VERSION 5.8 ;
BUSBITCHARS "[]" ;
DIVIDERCHAR "/" ;
UNITS
    DATABASE MICRONS 1000 ;
END UNITS

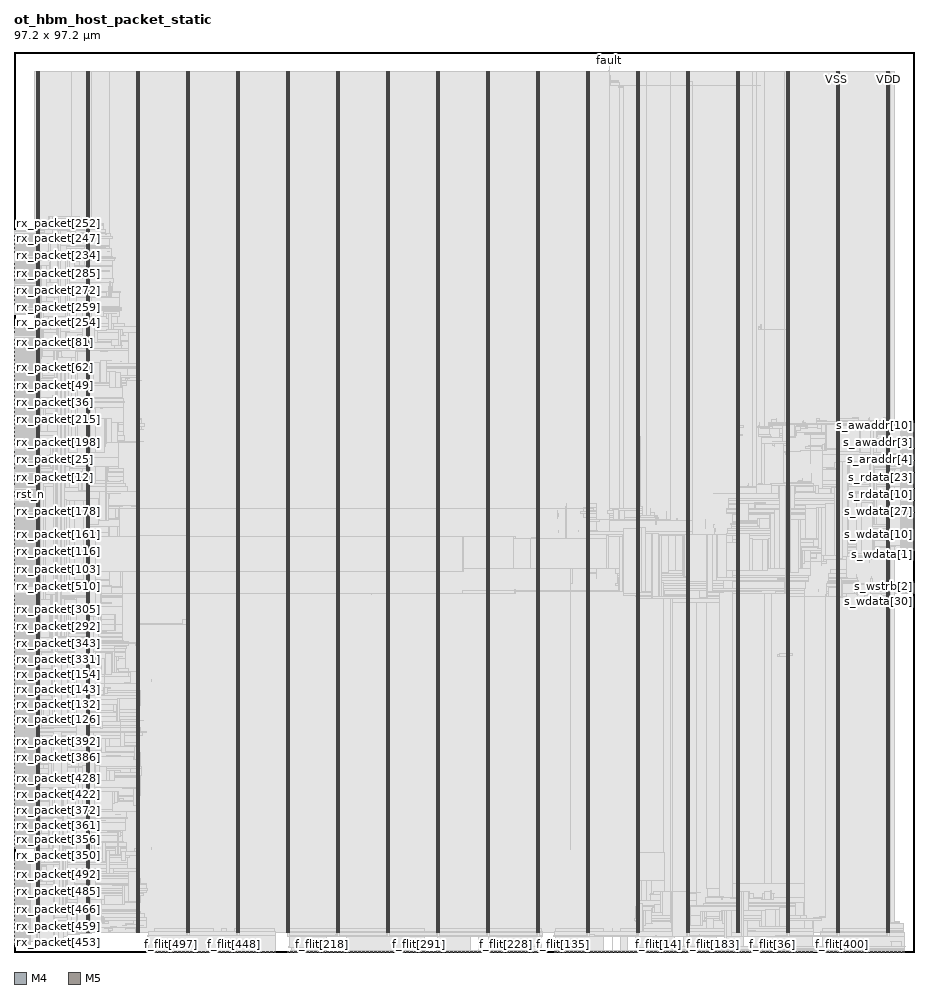
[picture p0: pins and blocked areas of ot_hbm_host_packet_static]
MACRO ot_hbm_host_packet_static
  FOREIGN ot_hbm_host_packet_static 0 0 ;
  CLASS BLOCK ;
  SIZE 97.2 BY 97.2 ;
  PIN clk
    DIRECTION INPUT ;
    USE SIGNAL ;
    PORT
      LAYER M4 ;
        RECT  0 49.248 0.084 49.272 ;
    END
  END clk
  PIN f_flit[0]
    DIRECTION OUTPUT ;
    USE SIGNAL ;
    PORT
      LAYER M5 ;
        RECT  67.536 0 67.56 0.084 ;
    END
  END f_flit[0]
  PIN f_flit[100]
    DIRECTION OUTPUT ;
    USE SIGNAL ;
    PORT
      LAYER M5 ;
        RECT  77.328 0 77.352 0.084 ;
    END
  END f_flit[100]
  PIN f_flit[101]
    DIRECTION OUTPUT ;
    USE SIGNAL ;
    PORT
      LAYER M5 ;
        RECT  77.472 0 77.496 0.084 ;
    END
  END f_flit[101]
  PIN f_flit[102]
    DIRECTION OUTPUT ;
    USE SIGNAL ;
    PORT
      LAYER M5 ;
        RECT  77.616 0 77.64 0.084 ;
    END
  END f_flit[102]
  PIN f_flit[103]
    DIRECTION OUTPUT ;
    USE SIGNAL ;
    PORT
      LAYER M5 ;
        RECT  77.76 0 77.784 0.084 ;
    END
  END f_flit[103]
  PIN f_flit[104]
    DIRECTION OUTPUT ;
    USE SIGNAL ;
    PORT
      LAYER M5 ;
        RECT  77.904 0 77.928 0.084 ;
    END
  END f_flit[104]
  PIN f_flit[105]
    DIRECTION OUTPUT ;
    USE SIGNAL ;
    PORT
      LAYER M5 ;
        RECT  78.048 0 78.072 0.084 ;
    END
  END f_flit[105]
  PIN f_flit[106]
    DIRECTION OUTPUT ;
    USE SIGNAL ;
    PORT
      LAYER M5 ;
        RECT  78.192 0 78.216 0.084 ;
    END
  END f_flit[106]
  PIN f_flit[107]
    DIRECTION OUTPUT ;
    USE SIGNAL ;
    PORT
      LAYER M5 ;
        RECT  78.336 0 78.36 0.084 ;
    END
  END f_flit[107]
  PIN f_flit[108]
    DIRECTION OUTPUT ;
    USE SIGNAL ;
    PORT
      LAYER M5 ;
        RECT  78.48 0 78.504 0.084 ;
    END
  END f_flit[108]
  PIN f_flit[109]
    DIRECTION OUTPUT ;
    USE SIGNAL ;
    PORT
      LAYER M5 ;
        RECT  78.624 0 78.648 0.084 ;
    END
  END f_flit[109]
  PIN f_flit[10]
    DIRECTION OUTPUT ;
    USE SIGNAL ;
    PORT
      LAYER M5 ;
        RECT  68.976 0 69 0.084 ;
    END
  END f_flit[10]
  PIN f_flit[110]
    DIRECTION OUTPUT ;
    USE SIGNAL ;
    PORT
      LAYER M5 ;
        RECT  78.768 0 78.792 0.084 ;
    END
  END f_flit[110]
  PIN f_flit[111]
    DIRECTION OUTPUT ;
    USE SIGNAL ;
    PORT
      LAYER M5 ;
        RECT  78.912 0 78.936 0.084 ;
    END
  END f_flit[111]
  PIN f_flit[112]
    DIRECTION OUTPUT ;
    USE SIGNAL ;
    PORT
      LAYER M5 ;
        RECT  79.056 0 79.08 0.084 ;
    END
  END f_flit[112]
  PIN f_flit[113]
    DIRECTION OUTPUT ;
    USE SIGNAL ;
    PORT
      LAYER M5 ;
        RECT  79.2 0 79.224 0.084 ;
    END
  END f_flit[113]
  PIN f_flit[114]
    DIRECTION OUTPUT ;
    USE SIGNAL ;
    PORT
      LAYER M5 ;
        RECT  79.344 0 79.368 0.084 ;
    END
  END f_flit[114]
  PIN f_flit[115]
    DIRECTION OUTPUT ;
    USE SIGNAL ;
    PORT
      LAYER M5 ;
        RECT  79.488 0 79.512 0.084 ;
    END
  END f_flit[115]
  PIN f_flit[116]
    DIRECTION OUTPUT ;
    USE SIGNAL ;
    PORT
      LAYER M5 ;
        RECT  79.632 0 79.656 0.084 ;
    END
  END f_flit[116]
  PIN f_flit[117]
    DIRECTION OUTPUT ;
    USE SIGNAL ;
    PORT
      LAYER M5 ;
        RECT  79.776 0 79.8 0.084 ;
    END
  END f_flit[117]
  PIN f_flit[118]
    DIRECTION OUTPUT ;
    USE SIGNAL ;
    PORT
      LAYER M5 ;
        RECT  79.92 0 79.944 0.084 ;
    END
  END f_flit[118]
  PIN f_flit[119]
    DIRECTION OUTPUT ;
    USE SIGNAL ;
    PORT
      LAYER M5 ;
        RECT  80.064 0 80.088 0.084 ;
    END
  END f_flit[119]
  PIN f_flit[11]
    DIRECTION OUTPUT ;
    USE SIGNAL ;
    PORT
      LAYER M5 ;
        RECT  69.12 0 69.144 0.084 ;
    END
  END f_flit[11]
  PIN f_flit[120]
    DIRECTION OUTPUT ;
    USE SIGNAL ;
    PORT
      LAYER M5 ;
        RECT  80.208 0 80.232 0.084 ;
    END
  END f_flit[120]
  PIN f_flit[121]
    DIRECTION OUTPUT ;
    USE SIGNAL ;
    PORT
      LAYER M5 ;
        RECT  80.352 0 80.376 0.084 ;
    END
  END f_flit[121]
  PIN f_flit[122]
    DIRECTION OUTPUT ;
    USE SIGNAL ;
    PORT
      LAYER M5 ;
        RECT  80.496 0 80.52 0.084 ;
    END
  END f_flit[122]
  PIN f_flit[123]
    DIRECTION OUTPUT ;
    USE SIGNAL ;
    PORT
      LAYER M5 ;
        RECT  80.64 0 80.664 0.084 ;
    END
  END f_flit[123]
  PIN f_flit[124]
    DIRECTION OUTPUT ;
    USE SIGNAL ;
    PORT
      LAYER M5 ;
        RECT  80.784 0 80.808 0.084 ;
    END
  END f_flit[124]
  PIN f_flit[125]
    DIRECTION OUTPUT ;
    USE SIGNAL ;
    PORT
      LAYER M5 ;
        RECT  80.928 0 80.952 0.084 ;
    END
  END f_flit[125]
  PIN f_flit[126]
    DIRECTION OUTPUT ;
    USE SIGNAL ;
    PORT
      LAYER M5 ;
        RECT  81.072 0 81.096 0.084 ;
    END
  END f_flit[126]
  PIN f_flit[127]
    DIRECTION OUTPUT ;
    USE SIGNAL ;
    PORT
      LAYER M5 ;
        RECT  81.216 0 81.24 0.084 ;
    END
  END f_flit[127]
  PIN f_flit[128]
    DIRECTION OUTPUT ;
    USE SIGNAL ;
    PORT
      LAYER M5 ;
        RECT  58.32 0 58.344 0.084 ;
    END
  END f_flit[128]
  PIN f_flit[129]
    DIRECTION OUTPUT ;
    USE SIGNAL ;
    PORT
      LAYER M5 ;
        RECT  58.464 0 58.488 0.084 ;
    END
  END f_flit[129]
  PIN f_flit[12]
    DIRECTION OUTPUT ;
    USE SIGNAL ;
    PORT
      LAYER M5 ;
        RECT  69.264 0 69.288 0.084 ;
    END
  END f_flit[12]
  PIN f_flit[130]
    DIRECTION OUTPUT ;
    USE SIGNAL ;
    PORT
      LAYER M5 ;
        RECT  58.608 0 58.632 0.084 ;
    END
  END f_flit[130]
  PIN f_flit[131]
    DIRECTION OUTPUT ;
    USE SIGNAL ;
    PORT
      LAYER M5 ;
        RECT  58.752 0 58.776 0.084 ;
    END
  END f_flit[131]
  PIN f_flit[132]
    DIRECTION OUTPUT ;
    USE SIGNAL ;
    PORT
      LAYER M5 ;
        RECT  58.896 0 58.92 0.084 ;
    END
  END f_flit[132]
  PIN f_flit[133]
    DIRECTION OUTPUT ;
    USE SIGNAL ;
    PORT
      LAYER M5 ;
        RECT  59.04 0 59.064 0.084 ;
    END
  END f_flit[133]
  PIN f_flit[134]
    DIRECTION OUTPUT ;
    USE SIGNAL ;
    PORT
      LAYER M5 ;
        RECT  59.184 0 59.208 0.084 ;
    END
  END f_flit[134]
  PIN f_flit[135]
    DIRECTION OUTPUT ;
    USE SIGNAL ;
    PORT
      LAYER M5 ;
        RECT  59.328 0 59.352 0.084 ;
    END
  END f_flit[135]
  PIN f_flit[136]
    DIRECTION OUTPUT ;
    USE SIGNAL ;
    PORT
      LAYER M5 ;
        RECT  59.472 0 59.496 0.084 ;
    END
  END f_flit[136]
  PIN f_flit[137]
    DIRECTION OUTPUT ;
    USE SIGNAL ;
    PORT
      LAYER M5 ;
        RECT  59.616 0 59.64 0.084 ;
    END
  END f_flit[137]
  PIN f_flit[138]
    DIRECTION OUTPUT ;
    USE SIGNAL ;
    PORT
      LAYER M5 ;
        RECT  59.76 0 59.784 0.084 ;
    END
  END f_flit[138]
  PIN f_flit[139]
    DIRECTION OUTPUT ;
    USE SIGNAL ;
    PORT
      LAYER M5 ;
        RECT  59.904 0 59.928 0.084 ;
    END
  END f_flit[139]
  PIN f_flit[13]
    DIRECTION OUTPUT ;
    USE SIGNAL ;
    PORT
      LAYER M5 ;
        RECT  69.408 0 69.432 0.084 ;
    END
  END f_flit[13]
  PIN f_flit[140]
    DIRECTION OUTPUT ;
    USE SIGNAL ;
    PORT
      LAYER M5 ;
        RECT  60.048 0 60.072 0.084 ;
    END
  END f_flit[140]
  PIN f_flit[141]
    DIRECTION OUTPUT ;
    USE SIGNAL ;
    PORT
      LAYER M5 ;
        RECT  60.192 0 60.216 0.084 ;
    END
  END f_flit[141]
  PIN f_flit[142]
    DIRECTION OUTPUT ;
    USE SIGNAL ;
    PORT
      LAYER M5 ;
        RECT  60.336 0 60.36 0.084 ;
    END
  END f_flit[142]
  PIN f_flit[143]
    DIRECTION OUTPUT ;
    USE SIGNAL ;
    PORT
      LAYER M5 ;
        RECT  60.48 0 60.504 0.084 ;
    END
  END f_flit[143]
  PIN f_flit[144]
    DIRECTION OUTPUT ;
    USE SIGNAL ;
    PORT
      LAYER M5 ;
        RECT  60.624 0 60.648 0.084 ;
    END
  END f_flit[144]
  PIN f_flit[145]
    DIRECTION OUTPUT ;
    USE SIGNAL ;
    PORT
      LAYER M5 ;
        RECT  60.768 0 60.792 0.084 ;
    END
  END f_flit[145]
  PIN f_flit[146]
    DIRECTION OUTPUT ;
    USE SIGNAL ;
    PORT
      LAYER M5 ;
        RECT  60.912 0 60.936 0.084 ;
    END
  END f_flit[146]
  PIN f_flit[147]
    DIRECTION OUTPUT ;
    USE SIGNAL ;
    PORT
      LAYER M5 ;
        RECT  61.056 0 61.08 0.084 ;
    END
  END f_flit[147]
  PIN f_flit[148]
    DIRECTION OUTPUT ;
    USE SIGNAL ;
    PORT
      LAYER M5 ;
        RECT  61.2 0 61.224 0.084 ;
    END
  END f_flit[148]
  PIN f_flit[149]
    DIRECTION OUTPUT ;
    USE SIGNAL ;
    PORT
      LAYER M5 ;
        RECT  61.344 0 61.368 0.084 ;
    END
  END f_flit[149]
  PIN f_flit[14]
    DIRECTION OUTPUT ;
    USE SIGNAL ;
    PORT
      LAYER M5 ;
        RECT  69.552 0 69.576 0.084 ;
    END
  END f_flit[14]
  PIN f_flit[150]
    DIRECTION OUTPUT ;
    USE SIGNAL ;
    PORT
      LAYER M5 ;
        RECT  61.488 0 61.512 0.084 ;
    END
  END f_flit[150]
  PIN f_flit[151]
    DIRECTION OUTPUT ;
    USE SIGNAL ;
    PORT
      LAYER M5 ;
        RECT  61.632 0 61.656 0.084 ;
    END
  END f_flit[151]
  PIN f_flit[152]
    DIRECTION OUTPUT ;
    USE SIGNAL ;
    PORT
      LAYER M5 ;
        RECT  61.776 0 61.8 0.084 ;
    END
  END f_flit[152]
  PIN f_flit[153]
    DIRECTION OUTPUT ;
    USE SIGNAL ;
    PORT
      LAYER M5 ;
        RECT  61.92 0 61.944 0.084 ;
    END
  END f_flit[153]
  PIN f_flit[154]
    DIRECTION OUTPUT ;
    USE SIGNAL ;
    PORT
      LAYER M5 ;
        RECT  62.064 0 62.088 0.084 ;
    END
  END f_flit[154]
  PIN f_flit[155]
    DIRECTION OUTPUT ;
    USE SIGNAL ;
    PORT
      LAYER M5 ;
        RECT  62.208 0 62.232 0.084 ;
    END
  END f_flit[155]
  PIN f_flit[156]
    DIRECTION OUTPUT ;
    USE SIGNAL ;
    PORT
      LAYER M5 ;
        RECT  62.352 0 62.376 0.084 ;
    END
  END f_flit[156]
  PIN f_flit[157]
    DIRECTION OUTPUT ;
    USE SIGNAL ;
    PORT
      LAYER M5 ;
        RECT  62.496 0 62.52 0.084 ;
    END
  END f_flit[157]
  PIN f_flit[158]
    DIRECTION OUTPUT ;
    USE SIGNAL ;
    PORT
      LAYER M5 ;
        RECT  62.64 0 62.664 0.084 ;
    END
  END f_flit[158]
  PIN f_flit[159]
    DIRECTION OUTPUT ;
    USE SIGNAL ;
    PORT
      LAYER M5 ;
        RECT  62.784 0 62.808 0.084 ;
    END
  END f_flit[159]
  PIN f_flit[15]
    DIRECTION OUTPUT ;
    USE SIGNAL ;
    PORT
      LAYER M5 ;
        RECT  69.696 0 69.72 0.084 ;
    END
  END f_flit[15]
  PIN f_flit[160]
    DIRECTION OUTPUT ;
    USE SIGNAL ;
    PORT
      LAYER M5 ;
        RECT  72.144 0 72.168 0.084 ;
    END
  END f_flit[160]
  PIN f_flit[161]
    DIRECTION OUTPUT ;
    USE SIGNAL ;
    PORT
      LAYER M5 ;
        RECT  72.288 0 72.312 0.084 ;
    END
  END f_flit[161]
  PIN f_flit[162]
    DIRECTION OUTPUT ;
    USE SIGNAL ;
    PORT
      LAYER M5 ;
        RECT  72.432 0 72.456 0.084 ;
    END
  END f_flit[162]
  PIN f_flit[163]
    DIRECTION OUTPUT ;
    USE SIGNAL ;
    PORT
      LAYER M5 ;
        RECT  72.576 0 72.6 0.084 ;
    END
  END f_flit[163]
  PIN f_flit[164]
    DIRECTION OUTPUT ;
    USE SIGNAL ;
    PORT
      LAYER M5 ;
        RECT  72.72 0 72.744 0.084 ;
    END
  END f_flit[164]
  PIN f_flit[165]
    DIRECTION OUTPUT ;
    USE SIGNAL ;
    PORT
      LAYER M5 ;
        RECT  72.864 0 72.888 0.084 ;
    END
  END f_flit[165]
  PIN f_flit[166]
    DIRECTION OUTPUT ;
    USE SIGNAL ;
    PORT
      LAYER M5 ;
        RECT  73.008 0 73.032 0.084 ;
    END
  END f_flit[166]
  PIN f_flit[167]
    DIRECTION OUTPUT ;
    USE SIGNAL ;
    PORT
      LAYER M5 ;
        RECT  73.152 0 73.176 0.084 ;
    END
  END f_flit[167]
  PIN f_flit[168]
    DIRECTION OUTPUT ;
    USE SIGNAL ;
    PORT
      LAYER M5 ;
        RECT  73.296 0 73.32 0.084 ;
    END
  END f_flit[168]
  PIN f_flit[169]
    DIRECTION OUTPUT ;
    USE SIGNAL ;
    PORT
      LAYER M5 ;
        RECT  73.44 0 73.464 0.084 ;
    END
  END f_flit[169]
  PIN f_flit[16]
    DIRECTION OUTPUT ;
    USE SIGNAL ;
    PORT
      LAYER M5 ;
        RECT  69.84 0 69.864 0.084 ;
    END
  END f_flit[16]
  PIN f_flit[170]
    DIRECTION OUTPUT ;
    USE SIGNAL ;
    PORT
      LAYER M5 ;
        RECT  73.584 0 73.608 0.084 ;
    END
  END f_flit[170]
  PIN f_flit[171]
    DIRECTION OUTPUT ;
    USE SIGNAL ;
    PORT
      LAYER M5 ;
        RECT  73.728 0 73.752 0.084 ;
    END
  END f_flit[171]
  PIN f_flit[172]
    DIRECTION OUTPUT ;
    USE SIGNAL ;
    PORT
      LAYER M5 ;
        RECT  73.872 0 73.896 0.084 ;
    END
  END f_flit[172]
  PIN f_flit[173]
    DIRECTION OUTPUT ;
    USE SIGNAL ;
    PORT
      LAYER M5 ;
        RECT  74.016 0 74.04 0.084 ;
    END
  END f_flit[173]
  PIN f_flit[174]
    DIRECTION OUTPUT ;
    USE SIGNAL ;
    PORT
      LAYER M5 ;
        RECT  74.16 0 74.184 0.084 ;
    END
  END f_flit[174]
  PIN f_flit[175]
    DIRECTION OUTPUT ;
    USE SIGNAL ;
    PORT
      LAYER M5 ;
        RECT  74.304 0 74.328 0.084 ;
    END
  END f_flit[175]
  PIN f_flit[176]
    DIRECTION OUTPUT ;
    USE SIGNAL ;
    PORT
      LAYER M5 ;
        RECT  74.448 0 74.472 0.084 ;
    END
  END f_flit[176]
  PIN f_flit[177]
    DIRECTION OUTPUT ;
    USE SIGNAL ;
    PORT
      LAYER M5 ;
        RECT  74.592 0 74.616 0.084 ;
    END
  END f_flit[177]
  PIN f_flit[178]
    DIRECTION OUTPUT ;
    USE SIGNAL ;
    PORT
      LAYER M5 ;
        RECT  74.736 0 74.76 0.084 ;
    END
  END f_flit[178]
  PIN f_flit[179]
    DIRECTION OUTPUT ;
    USE SIGNAL ;
    PORT
      LAYER M5 ;
        RECT  74.88 0 74.904 0.084 ;
    END
  END f_flit[179]
  PIN f_flit[17]
    DIRECTION OUTPUT ;
    USE SIGNAL ;
    PORT
      LAYER M5 ;
        RECT  69.984 0 70.008 0.084 ;
    END
  END f_flit[17]
  PIN f_flit[180]
    DIRECTION OUTPUT ;
    USE SIGNAL ;
    PORT
      LAYER M5 ;
        RECT  75.024 0 75.048 0.084 ;
    END
  END f_flit[180]
  PIN f_flit[181]
    DIRECTION OUTPUT ;
    USE SIGNAL ;
    PORT
      LAYER M5 ;
        RECT  75.168 0 75.192 0.084 ;
    END
  END f_flit[181]
  PIN f_flit[182]
    DIRECTION OUTPUT ;
    USE SIGNAL ;
    PORT
      LAYER M5 ;
        RECT  75.312 0 75.336 0.084 ;
    END
  END f_flit[182]
  PIN f_flit[183]
    DIRECTION OUTPUT ;
    USE SIGNAL ;
    PORT
      LAYER M5 ;
        RECT  75.456 0 75.48 0.084 ;
    END
  END f_flit[183]
  PIN f_flit[184]
    DIRECTION OUTPUT ;
    USE SIGNAL ;
    PORT
      LAYER M5 ;
        RECT  75.6 0 75.624 0.084 ;
    END
  END f_flit[184]
  PIN f_flit[185]
    DIRECTION OUTPUT ;
    USE SIGNAL ;
    PORT
      LAYER M5 ;
        RECT  75.744 0 75.768 0.084 ;
    END
  END f_flit[185]
  PIN f_flit[186]
    DIRECTION OUTPUT ;
    USE SIGNAL ;
    PORT
      LAYER M5 ;
        RECT  75.888 0 75.912 0.084 ;
    END
  END f_flit[186]
  PIN f_flit[187]
    DIRECTION OUTPUT ;
    USE SIGNAL ;
    PORT
      LAYER M5 ;
        RECT  76.032 0 76.056 0.084 ;
    END
  END f_flit[187]
  PIN f_flit[188]
    DIRECTION OUTPUT ;
    USE SIGNAL ;
    PORT
      LAYER M5 ;
        RECT  76.176 0 76.2 0.084 ;
    END
  END f_flit[188]
  PIN f_flit[189]
    DIRECTION OUTPUT ;
    USE SIGNAL ;
    PORT
      LAYER M5 ;
        RECT  76.32 0 76.344 0.084 ;
    END
  END f_flit[189]
  PIN f_flit[18]
    DIRECTION OUTPUT ;
    USE SIGNAL ;
    PORT
      LAYER M5 ;
        RECT  70.128 0 70.152 0.084 ;
    END
  END f_flit[18]
  PIN f_flit[190]
    DIRECTION OUTPUT ;
    USE SIGNAL ;
    PORT
      LAYER M5 ;
        RECT  76.464 0 76.488 0.084 ;
    END
  END f_flit[190]
  PIN f_flit[191]
    DIRECTION OUTPUT ;
    USE SIGNAL ;
    PORT
      LAYER M5 ;
        RECT  76.608 0 76.632 0.084 ;
    END
  END f_flit[191]
  PIN f_flit[192]
    DIRECTION OUTPUT ;
    USE SIGNAL ;
    PORT
      LAYER M5 ;
        RECT  29.52 0 29.544 0.084 ;
    END
  END f_flit[192]
  PIN f_flit[193]
    DIRECTION OUTPUT ;
    USE SIGNAL ;
    PORT
      LAYER M5 ;
        RECT  29.664 0 29.688 0.084 ;
    END
  END f_flit[193]
  PIN f_flit[194]
    DIRECTION OUTPUT ;
    USE SIGNAL ;
    PORT
      LAYER M5 ;
        RECT  29.808 0 29.832 0.084 ;
    END
  END f_flit[194]
  PIN f_flit[195]
    DIRECTION OUTPUT ;
    USE SIGNAL ;
    PORT
      LAYER M5 ;
        RECT  29.952 0 29.976 0.084 ;
    END
  END f_flit[195]
  PIN f_flit[196]
    DIRECTION OUTPUT ;
    USE SIGNAL ;
    PORT
      LAYER M5 ;
        RECT  30.096 0 30.12 0.084 ;
    END
  END f_flit[196]
  PIN f_flit[197]
    DIRECTION OUTPUT ;
    USE SIGNAL ;
    PORT
      LAYER M5 ;
        RECT  30.24 0 30.264 0.084 ;
    END
  END f_flit[197]
  PIN f_flit[198]
    DIRECTION OUTPUT ;
    USE SIGNAL ;
    PORT
      LAYER M5 ;
        RECT  30.384 0 30.408 0.084 ;
    END
  END f_flit[198]
  PIN f_flit[199]
    DIRECTION OUTPUT ;
    USE SIGNAL ;
    PORT
      LAYER M5 ;
        RECT  30.528 0 30.552 0.084 ;
    END
  END f_flit[199]
  PIN f_flit[19]
    DIRECTION OUTPUT ;
    USE SIGNAL ;
    PORT
      LAYER M5 ;
        RECT  70.272 0 70.296 0.084 ;
    END
  END f_flit[19]
  PIN f_flit[1]
    DIRECTION OUTPUT ;
    USE SIGNAL ;
    PORT
      LAYER M5 ;
        RECT  67.68 0 67.704 0.084 ;
    END
  END f_flit[1]
  PIN f_flit[200]
    DIRECTION OUTPUT ;
    USE SIGNAL ;
    PORT
      LAYER M5 ;
        RECT  30.672 0 30.696 0.084 ;
    END
  END f_flit[200]
  PIN f_flit[201]
    DIRECTION OUTPUT ;
    USE SIGNAL ;
    PORT
      LAYER M5 ;
        RECT  30.816 0 30.84 0.084 ;
    END
  END f_flit[201]
  PIN f_flit[202]
    DIRECTION OUTPUT ;
    USE SIGNAL ;
    PORT
      LAYER M5 ;
        RECT  30.96 0 30.984 0.084 ;
    END
  END f_flit[202]
  PIN f_flit[203]
    DIRECTION OUTPUT ;
    USE SIGNAL ;
    PORT
      LAYER M5 ;
        RECT  31.104 0 31.128 0.084 ;
    END
  END f_flit[203]
  PIN f_flit[204]
    DIRECTION OUTPUT ;
    USE SIGNAL ;
    PORT
      LAYER M5 ;
        RECT  31.248 0 31.272 0.084 ;
    END
  END f_flit[204]
  PIN f_flit[205]
    DIRECTION OUTPUT ;
    USE SIGNAL ;
    PORT
      LAYER M5 ;
        RECT  31.392 0 31.416 0.084 ;
    END
  END f_flit[205]
  PIN f_flit[206]
    DIRECTION OUTPUT ;
    USE SIGNAL ;
    PORT
      LAYER M5 ;
        RECT  31.536 0 31.56 0.084 ;
    END
  END f_flit[206]
  PIN f_flit[207]
    DIRECTION OUTPUT ;
    USE SIGNAL ;
    PORT
      LAYER M5 ;
        RECT  31.68 0 31.704 0.084 ;
    END
  END f_flit[207]
  PIN f_flit[208]
    DIRECTION OUTPUT ;
    USE SIGNAL ;
    PORT
      LAYER M5 ;
        RECT  31.824 0 31.848 0.084 ;
    END
  END f_flit[208]
  PIN f_flit[209]
    DIRECTION OUTPUT ;
    USE SIGNAL ;
    PORT
      LAYER M5 ;
        RECT  31.968 0 31.992 0.084 ;
    END
  END f_flit[209]
  PIN f_flit[20]
    DIRECTION OUTPUT ;
    USE SIGNAL ;
    PORT
      LAYER M5 ;
        RECT  70.416 0 70.44 0.084 ;
    END
  END f_flit[20]
  PIN f_flit[210]
    DIRECTION OUTPUT ;
    USE SIGNAL ;
    PORT
      LAYER M5 ;
        RECT  32.112 0 32.136 0.084 ;
    END
  END f_flit[210]
  PIN f_flit[211]
    DIRECTION OUTPUT ;
    USE SIGNAL ;
    PORT
      LAYER M5 ;
        RECT  32.256 0 32.28 0.084 ;
    END
  END f_flit[211]
  PIN f_flit[212]
    DIRECTION OUTPUT ;
    USE SIGNAL ;
    PORT
      LAYER M5 ;
        RECT  32.4 0 32.424 0.084 ;
    END
  END f_flit[212]
  PIN f_flit[213]
    DIRECTION OUTPUT ;
    USE SIGNAL ;
    PORT
      LAYER M5 ;
        RECT  32.544 0 32.568 0.084 ;
    END
  END f_flit[213]
  PIN f_flit[214]
    DIRECTION OUTPUT ;
    USE SIGNAL ;
    PORT
      LAYER M5 ;
        RECT  32.688 0 32.712 0.084 ;
    END
  END f_flit[214]
  PIN f_flit[215]
    DIRECTION OUTPUT ;
    USE SIGNAL ;
    PORT
      LAYER M5 ;
        RECT  32.832 0 32.856 0.084 ;
    END
  END f_flit[215]
  PIN f_flit[216]
    DIRECTION OUTPUT ;
    USE SIGNAL ;
    PORT
      LAYER M5 ;
        RECT  32.976 0 33 0.084 ;
    END
  END f_flit[216]
  PIN f_flit[217]
    DIRECTION OUTPUT ;
    USE SIGNAL ;
    PORT
      LAYER M5 ;
        RECT  33.12 0 33.144 0.084 ;
    END
  END f_flit[217]
  PIN f_flit[218]
    DIRECTION OUTPUT ;
    USE SIGNAL ;
    PORT
      LAYER M5 ;
        RECT  33.264 0 33.288 0.084 ;
    END
  END f_flit[218]
  PIN f_flit[219]
    DIRECTION OUTPUT ;
    USE SIGNAL ;
    PORT
      LAYER M5 ;
        RECT  33.408 0 33.432 0.084 ;
    END
  END f_flit[219]
  PIN f_flit[21]
    DIRECTION OUTPUT ;
    USE SIGNAL ;
    PORT
      LAYER M5 ;
        RECT  70.56 0 70.584 0.084 ;
    END
  END f_flit[21]
  PIN f_flit[220]
    DIRECTION OUTPUT ;
    USE SIGNAL ;
    PORT
      LAYER M5 ;
        RECT  33.552 0 33.576 0.084 ;
    END
  END f_flit[220]
  PIN f_flit[221]
    DIRECTION OUTPUT ;
    USE SIGNAL ;
    PORT
      LAYER M5 ;
        RECT  33.696 0 33.72 0.084 ;
    END
  END f_flit[221]
  PIN f_flit[222]
    DIRECTION OUTPUT ;
    USE SIGNAL ;
    PORT
      LAYER M5 ;
        RECT  33.84 0 33.864 0.084 ;
    END
  END f_flit[222]
  PIN f_flit[223]
    DIRECTION OUTPUT ;
    USE SIGNAL ;
    PORT
      LAYER M5 ;
        RECT  33.984 0 34.008 0.084 ;
    END
  END f_flit[223]
  PIN f_flit[224]
    DIRECTION OUTPUT ;
    USE SIGNAL ;
    PORT
      LAYER M5 ;
        RECT  52.56 0 52.584 0.084 ;
    END
  END f_flit[224]
  PIN f_flit[225]
    DIRECTION OUTPUT ;
    USE SIGNAL ;
    PORT
      LAYER M5 ;
        RECT  52.704 0 52.728 0.084 ;
    END
  END f_flit[225]
  PIN f_flit[226]
    DIRECTION OUTPUT ;
    USE SIGNAL ;
    PORT
      LAYER M5 ;
        RECT  52.848 0 52.872 0.084 ;
    END
  END f_flit[226]
  PIN f_flit[227]
    DIRECTION OUTPUT ;
    USE SIGNAL ;
    PORT
      LAYER M5 ;
        RECT  52.992 0 53.016 0.084 ;
    END
  END f_flit[227]
  PIN f_flit[228]
    DIRECTION OUTPUT ;
    USE SIGNAL ;
    PORT
      LAYER M5 ;
        RECT  53.136 0 53.16 0.084 ;
    END
  END f_flit[228]
  PIN f_flit[229]
    DIRECTION OUTPUT ;
    USE SIGNAL ;
    PORT
      LAYER M5 ;
        RECT  53.28 0 53.304 0.084 ;
    END
  END f_flit[229]
  PIN f_flit[22]
    DIRECTION OUTPUT ;
    USE SIGNAL ;
    PORT
      LAYER M5 ;
        RECT  70.704 0 70.728 0.084 ;
    END
  END f_flit[22]
  PIN f_flit[230]
    DIRECTION OUTPUT ;
    USE SIGNAL ;
    PORT
      LAYER M5 ;
        RECT  53.424 0 53.448 0.084 ;
    END
  END f_flit[230]
  PIN f_flit[231]
    DIRECTION OUTPUT ;
    USE SIGNAL ;
    PORT
      LAYER M5 ;
        RECT  53.568 0 53.592 0.084 ;
    END
  END f_flit[231]
  PIN f_flit[232]
    DIRECTION OUTPUT ;
    USE SIGNAL ;
    PORT
      LAYER M5 ;
        RECT  53.712 0 53.736 0.084 ;
    END
  END f_flit[232]
  PIN f_flit[233]
    DIRECTION OUTPUT ;
    USE SIGNAL ;
    PORT
      LAYER M5 ;
        RECT  53.856 0 53.88 0.084 ;
    END
  END f_flit[233]
  PIN f_flit[234]
    DIRECTION OUTPUT ;
    USE SIGNAL ;
    PORT
      LAYER M5 ;
        RECT  54 0 54.024 0.084 ;
    END
  END f_flit[234]
  PIN f_flit[235]
    DIRECTION OUTPUT ;
    USE SIGNAL ;
    PORT
      LAYER M5 ;
        RECT  54.144 0 54.168 0.084 ;
    END
  END f_flit[235]
  PIN f_flit[236]
    DIRECTION OUTPUT ;
    USE SIGNAL ;
    PORT
      LAYER M5 ;
        RECT  54.288 0 54.312 0.084 ;
    END
  END f_flit[236]
  PIN f_flit[237]
    DIRECTION OUTPUT ;
    USE SIGNAL ;
    PORT
      LAYER M5 ;
        RECT  54.432 0 54.456 0.084 ;
    END
  END f_flit[237]
  PIN f_flit[238]
    DIRECTION OUTPUT ;
    USE SIGNAL ;
    PORT
      LAYER M5 ;
        RECT  54.576 0 54.6 0.084 ;
    END
  END f_flit[238]
  PIN f_flit[239]
    DIRECTION OUTPUT ;
    USE SIGNAL ;
    PORT
      LAYER M5 ;
        RECT  54.72 0 54.744 0.084 ;
    END
  END f_flit[239]
  PIN f_flit[23]
    DIRECTION OUTPUT ;
    USE SIGNAL ;
    PORT
      LAYER M5 ;
        RECT  70.848 0 70.872 0.084 ;
    END
  END f_flit[23]
  PIN f_flit[240]
    DIRECTION OUTPUT ;
    USE SIGNAL ;
    PORT
      LAYER M5 ;
        RECT  54.864 0 54.888 0.084 ;
    END
  END f_flit[240]
  PIN f_flit[241]
    DIRECTION OUTPUT ;
    USE SIGNAL ;
    PORT
      LAYER M5 ;
        RECT  55.008 0 55.032 0.084 ;
    END
  END f_flit[241]
  PIN f_flit[242]
    DIRECTION OUTPUT ;
    USE SIGNAL ;
    PORT
      LAYER M5 ;
        RECT  55.152 0 55.176 0.084 ;
    END
  END f_flit[242]
  PIN f_flit[243]
    DIRECTION OUTPUT ;
    USE SIGNAL ;
    PORT
      LAYER M5 ;
        RECT  55.296 0 55.32 0.084 ;
    END
  END f_flit[243]
  PIN f_flit[244]
    DIRECTION OUTPUT ;
    USE SIGNAL ;
    PORT
      LAYER M5 ;
        RECT  55.44 0 55.464 0.084 ;
    END
  END f_flit[244]
  PIN f_flit[245]
    DIRECTION OUTPUT ;
    USE SIGNAL ;
    PORT
      LAYER M5 ;
        RECT  55.584 0 55.608 0.084 ;
    END
  END f_flit[245]
  PIN f_flit[246]
    DIRECTION OUTPUT ;
    USE SIGNAL ;
    PORT
      LAYER M5 ;
        RECT  55.728 0 55.752 0.084 ;
    END
  END f_flit[246]
  PIN f_flit[247]
    DIRECTION OUTPUT ;
    USE SIGNAL ;
    PORT
      LAYER M5 ;
        RECT  55.872 0 55.896 0.084 ;
    END
  END f_flit[247]
  PIN f_flit[248]
    DIRECTION OUTPUT ;
    USE SIGNAL ;
    PORT
      LAYER M5 ;
        RECT  56.016 0 56.04 0.084 ;
    END
  END f_flit[248]
  PIN f_flit[249]
    DIRECTION OUTPUT ;
    USE SIGNAL ;
    PORT
      LAYER M5 ;
        RECT  56.16 0 56.184 0.084 ;
    END
  END f_flit[249]
  PIN f_flit[24]
    DIRECTION OUTPUT ;
    USE SIGNAL ;
    PORT
      LAYER M5 ;
        RECT  70.992 0 71.016 0.084 ;
    END
  END f_flit[24]
  PIN f_flit[250]
    DIRECTION OUTPUT ;
    USE SIGNAL ;
    PORT
      LAYER M5 ;
        RECT  56.304 0 56.328 0.084 ;
    END
  END f_flit[250]
  PIN f_flit[251]
    DIRECTION OUTPUT ;
    USE SIGNAL ;
    PORT
      LAYER M5 ;
        RECT  56.448 0 56.472 0.084 ;
    END
  END f_flit[251]
  PIN f_flit[252]
    DIRECTION OUTPUT ;
    USE SIGNAL ;
    PORT
      LAYER M5 ;
        RECT  56.592 0 56.616 0.084 ;
    END
  END f_flit[252]
  PIN f_flit[253]
    DIRECTION OUTPUT ;
    USE SIGNAL ;
    PORT
      LAYER M5 ;
        RECT  56.736 0 56.76 0.084 ;
    END
  END f_flit[253]
  PIN f_flit[254]
    DIRECTION OUTPUT ;
    USE SIGNAL ;
    PORT
      LAYER M5 ;
        RECT  56.88 0 56.904 0.084 ;
    END
  END f_flit[254]
  PIN f_flit[255]
    DIRECTION OUTPUT ;
    USE SIGNAL ;
    PORT
      LAYER M5 ;
        RECT  57.024 0 57.048 0.084 ;
    END
  END f_flit[255]
  PIN f_flit[256]
    DIRECTION OUTPUT ;
    USE SIGNAL ;
    PORT
      LAYER M5 ;
        RECT  47.952 0 47.976 0.084 ;
    END
  END f_flit[256]
  PIN f_flit[257]
    DIRECTION OUTPUT ;
    USE SIGNAL ;
    PORT
      LAYER M5 ;
        RECT  48.096 0 48.12 0.084 ;
    END
  END f_flit[257]
  PIN f_flit[258]
    DIRECTION OUTPUT ;
    USE SIGNAL ;
    PORT
      LAYER M5 ;
        RECT  48.24 0 48.264 0.084 ;
    END
  END f_flit[258]
  PIN f_flit[259]
    DIRECTION OUTPUT ;
    USE SIGNAL ;
    PORT
      LAYER M5 ;
        RECT  48.384 0 48.408 0.084 ;
    END
  END f_flit[259]
  PIN f_flit[25]
    DIRECTION OUTPUT ;
    USE SIGNAL ;
    PORT
      LAYER M5 ;
        RECT  71.136 0 71.16 0.084 ;
    END
  END f_flit[25]
  PIN f_flit[260]
    DIRECTION OUTPUT ;
    USE SIGNAL ;
    PORT
      LAYER M5 ;
        RECT  48.528 0 48.552 0.084 ;
    END
  END f_flit[260]
  PIN f_flit[261]
    DIRECTION OUTPUT ;
    USE SIGNAL ;
    PORT
      LAYER M5 ;
        RECT  48.672 0 48.696 0.084 ;
    END
  END f_flit[261]
  PIN f_flit[262]
    DIRECTION OUTPUT ;
    USE SIGNAL ;
    PORT
      LAYER M5 ;
        RECT  48.816 0 48.84 0.084 ;
    END
  END f_flit[262]
  PIN f_flit[263]
    DIRECTION OUTPUT ;
    USE SIGNAL ;
    PORT
      LAYER M5 ;
        RECT  48.96 0 48.984 0.084 ;
    END
  END f_flit[263]
  PIN f_flit[264]
    DIRECTION OUTPUT ;
    USE SIGNAL ;
    PORT
      LAYER M5 ;
        RECT  49.104 0 49.128 0.084 ;
    END
  END f_flit[264]
  PIN f_flit[265]
    DIRECTION OUTPUT ;
    USE SIGNAL ;
    PORT
      LAYER M5 ;
        RECT  49.248 0 49.272 0.084 ;
    END
  END f_flit[265]
  PIN f_flit[266]
    DIRECTION OUTPUT ;
    USE SIGNAL ;
    PORT
      LAYER M5 ;
        RECT  49.392 0 49.416 0.084 ;
    END
  END f_flit[266]
  PIN f_flit[267]
    DIRECTION OUTPUT ;
    USE SIGNAL ;
    PORT
      LAYER M5 ;
        RECT  49.536 0 49.56 0.084 ;
    END
  END f_flit[267]
  PIN f_flit[268]
    DIRECTION OUTPUT ;
    USE SIGNAL ;
    PORT
      LAYER M5 ;
        RECT  49.68 0 49.704 0.084 ;
    END
  END f_flit[268]
  PIN f_flit[269]
    DIRECTION OUTPUT ;
    USE SIGNAL ;
    PORT
      LAYER M5 ;
        RECT  49.824 0 49.848 0.084 ;
    END
  END f_flit[269]
  PIN f_flit[26]
    DIRECTION OUTPUT ;
    USE SIGNAL ;
    PORT
      LAYER M5 ;
        RECT  71.28 0 71.304 0.084 ;
    END
  END f_flit[26]
  PIN f_flit[270]
    DIRECTION OUTPUT ;
    USE SIGNAL ;
    PORT
      LAYER M5 ;
        RECT  49.968 0 49.992 0.084 ;
    END
  END f_flit[270]
  PIN f_flit[271]
    DIRECTION OUTPUT ;
    USE SIGNAL ;
    PORT
      LAYER M5 ;
        RECT  50.112 0 50.136 0.084 ;
    END
  END f_flit[271]
  PIN f_flit[272]
    DIRECTION OUTPUT ;
    USE SIGNAL ;
    PORT
      LAYER M5 ;
        RECT  50.256 0 50.28 0.084 ;
    END
  END f_flit[272]
  PIN f_flit[273]
    DIRECTION OUTPUT ;
    USE SIGNAL ;
    PORT
      LAYER M5 ;
        RECT  50.4 0 50.424 0.084 ;
    END
  END f_flit[273]
  PIN f_flit[274]
    DIRECTION OUTPUT ;
    USE SIGNAL ;
    PORT
      LAYER M5 ;
        RECT  50.544 0 50.568 0.084 ;
    END
  END f_flit[274]
  PIN f_flit[275]
    DIRECTION OUTPUT ;
    USE SIGNAL ;
    PORT
      LAYER M5 ;
        RECT  50.688 0 50.712 0.084 ;
    END
  END f_flit[275]
  PIN f_flit[276]
    DIRECTION OUTPUT ;
    USE SIGNAL ;
    PORT
      LAYER M5 ;
        RECT  50.832 0 50.856 0.084 ;
    END
  END f_flit[276]
  PIN f_flit[277]
    DIRECTION OUTPUT ;
    USE SIGNAL ;
    PORT
      LAYER M5 ;
        RECT  50.976 0 51 0.084 ;
    END
  END f_flit[277]
  PIN f_flit[278]
    DIRECTION OUTPUT ;
    USE SIGNAL ;
    PORT
      LAYER M5 ;
        RECT  51.12 0 51.144 0.084 ;
    END
  END f_flit[278]
  PIN f_flit[279]
    DIRECTION OUTPUT ;
    USE SIGNAL ;
    PORT
      LAYER M5 ;
        RECT  51.264 0 51.288 0.084 ;
    END
  END f_flit[279]
  PIN f_flit[27]
    DIRECTION OUTPUT ;
    USE SIGNAL ;
    PORT
      LAYER M5 ;
        RECT  71.424 0 71.448 0.084 ;
    END
  END f_flit[27]
  PIN f_flit[280]
    DIRECTION OUTPUT ;
    USE SIGNAL ;
    PORT
      LAYER M5 ;
        RECT  51.408 0 51.432 0.084 ;
    END
  END f_flit[280]
  PIN f_flit[281]
    DIRECTION OUTPUT ;
    USE SIGNAL ;
    PORT
      LAYER M5 ;
        RECT  51.552 0 51.576 0.084 ;
    END
  END f_flit[281]
  PIN f_flit[282]
    DIRECTION OUTPUT ;
    USE SIGNAL ;
    PORT
      LAYER M5 ;
        RECT  51.696 0 51.72 0.084 ;
    END
  END f_flit[282]
  PIN f_flit[283]
    DIRECTION OUTPUT ;
    USE SIGNAL ;
    PORT
      LAYER M5 ;
        RECT  51.84 0 51.864 0.084 ;
    END
  END f_flit[283]
  PIN f_flit[284]
    DIRECTION OUTPUT ;
    USE SIGNAL ;
    PORT
      LAYER M5 ;
        RECT  51.984 0 52.008 0.084 ;
    END
  END f_flit[284]
  PIN f_flit[285]
    DIRECTION OUTPUT ;
    USE SIGNAL ;
    PORT
      LAYER M5 ;
        RECT  52.128 0 52.152 0.084 ;
    END
  END f_flit[285]
  PIN f_flit[286]
    DIRECTION OUTPUT ;
    USE SIGNAL ;
    PORT
      LAYER M5 ;
        RECT  52.272 0 52.296 0.084 ;
    END
  END f_flit[286]
  PIN f_flit[287]
    DIRECTION OUTPUT ;
    USE SIGNAL ;
    PORT
      LAYER M5 ;
        RECT  52.416 0 52.44 0.084 ;
    END
  END f_flit[287]
  PIN f_flit[288]
    DIRECTION OUTPUT ;
    USE SIGNAL ;
    PORT
      LAYER M5 ;
        RECT  43.344 0 43.368 0.084 ;
    END
  END f_flit[288]
  PIN f_flit[289]
    DIRECTION OUTPUT ;
    USE SIGNAL ;
    PORT
      LAYER M5 ;
        RECT  43.488 0 43.512 0.084 ;
    END
  END f_flit[289]
  PIN f_flit[28]
    DIRECTION OUTPUT ;
    USE SIGNAL ;
    PORT
      LAYER M5 ;
        RECT  71.568 0 71.592 0.084 ;
    END
  END f_flit[28]
  PIN f_flit[290]
    DIRECTION OUTPUT ;
    USE SIGNAL ;
    PORT
      LAYER M5 ;
        RECT  43.632 0 43.656 0.084 ;
    END
  END f_flit[290]
  PIN f_flit[291]
    DIRECTION OUTPUT ;
    USE SIGNAL ;
    PORT
      LAYER M5 ;
        RECT  43.776 0 43.8 0.084 ;
    END
  END f_flit[291]
  PIN f_flit[292]
    DIRECTION OUTPUT ;
    USE SIGNAL ;
    PORT
      LAYER M5 ;
        RECT  43.92 0 43.944 0.084 ;
    END
  END f_flit[292]
  PIN f_flit[293]
    DIRECTION OUTPUT ;
    USE SIGNAL ;
    PORT
      LAYER M5 ;
        RECT  44.064 0 44.088 0.084 ;
    END
  END f_flit[293]
  PIN f_flit[294]
    DIRECTION OUTPUT ;
    USE SIGNAL ;
    PORT
      LAYER M5 ;
        RECT  44.208 0 44.232 0.084 ;
    END
  END f_flit[294]
  PIN f_flit[295]
    DIRECTION OUTPUT ;
    USE SIGNAL ;
    PORT
      LAYER M5 ;
        RECT  44.352 0 44.376 0.084 ;
    END
  END f_flit[295]
  PIN f_flit[296]
    DIRECTION OUTPUT ;
    USE SIGNAL ;
    PORT
      LAYER M5 ;
        RECT  44.496 0 44.52 0.084 ;
    END
  END f_flit[296]
  PIN f_flit[297]
    DIRECTION OUTPUT ;
    USE SIGNAL ;
    PORT
      LAYER M5 ;
        RECT  44.64 0 44.664 0.084 ;
    END
  END f_flit[297]
  PIN f_flit[298]
    DIRECTION OUTPUT ;
    USE SIGNAL ;
    PORT
      LAYER M5 ;
        RECT  44.784 0 44.808 0.084 ;
    END
  END f_flit[298]
  PIN f_flit[299]
    DIRECTION OUTPUT ;
    USE SIGNAL ;
    PORT
      LAYER M5 ;
        RECT  44.928 0 44.952 0.084 ;
    END
  END f_flit[299]
  PIN f_flit[29]
    DIRECTION OUTPUT ;
    USE SIGNAL ;
    PORT
      LAYER M5 ;
        RECT  71.712 0 71.736 0.084 ;
    END
  END f_flit[29]
  PIN f_flit[2]
    DIRECTION OUTPUT ;
    USE SIGNAL ;
    PORT
      LAYER M5 ;
        RECT  67.824 0 67.848 0.084 ;
    END
  END f_flit[2]
  PIN f_flit[300]
    DIRECTION OUTPUT ;
    USE SIGNAL ;
    PORT
      LAYER M5 ;
        RECT  45.072 0 45.096 0.084 ;
    END
  END f_flit[300]
  PIN f_flit[301]
    DIRECTION OUTPUT ;
    USE SIGNAL ;
    PORT
      LAYER M5 ;
        RECT  45.216 0 45.24 0.084 ;
    END
  END f_flit[301]
  PIN f_flit[302]
    DIRECTION OUTPUT ;
    USE SIGNAL ;
    PORT
      LAYER M5 ;
        RECT  45.36 0 45.384 0.084 ;
    END
  END f_flit[302]
  PIN f_flit[303]
    DIRECTION OUTPUT ;
    USE SIGNAL ;
    PORT
      LAYER M5 ;
        RECT  45.504 0 45.528 0.084 ;
    END
  END f_flit[303]
  PIN f_flit[304]
    DIRECTION OUTPUT ;
    USE SIGNAL ;
    PORT
      LAYER M5 ;
        RECT  45.648 0 45.672 0.084 ;
    END
  END f_flit[304]
  PIN f_flit[305]
    DIRECTION OUTPUT ;
    USE SIGNAL ;
    PORT
      LAYER M5 ;
        RECT  45.792 0 45.816 0.084 ;
    END
  END f_flit[305]
  PIN f_flit[306]
    DIRECTION OUTPUT ;
    USE SIGNAL ;
    PORT
      LAYER M5 ;
        RECT  45.936 0 45.96 0.084 ;
    END
  END f_flit[306]
  PIN f_flit[307]
    DIRECTION OUTPUT ;
    USE SIGNAL ;
    PORT
      LAYER M5 ;
        RECT  46.08 0 46.104 0.084 ;
    END
  END f_flit[307]
  PIN f_flit[308]
    DIRECTION OUTPUT ;
    USE SIGNAL ;
    PORT
      LAYER M5 ;
        RECT  46.224 0 46.248 0.084 ;
    END
  END f_flit[308]
  PIN f_flit[309]
    DIRECTION OUTPUT ;
    USE SIGNAL ;
    PORT
      LAYER M5 ;
        RECT  46.368 0 46.392 0.084 ;
    END
  END f_flit[309]
  PIN f_flit[30]
    DIRECTION OUTPUT ;
    USE SIGNAL ;
    PORT
      LAYER M5 ;
        RECT  71.856 0 71.88 0.084 ;
    END
  END f_flit[30]
  PIN f_flit[310]
    DIRECTION OUTPUT ;
    USE SIGNAL ;
    PORT
      LAYER M5 ;
        RECT  46.512 0 46.536 0.084 ;
    END
  END f_flit[310]
  PIN f_flit[311]
    DIRECTION OUTPUT ;
    USE SIGNAL ;
    PORT
      LAYER M5 ;
        RECT  46.656 0 46.68 0.084 ;
    END
  END f_flit[311]
  PIN f_flit[312]
    DIRECTION OUTPUT ;
    USE SIGNAL ;
    PORT
      LAYER M5 ;
        RECT  46.8 0 46.824 0.084 ;
    END
  END f_flit[312]
  PIN f_flit[313]
    DIRECTION OUTPUT ;
    USE SIGNAL ;
    PORT
      LAYER M5 ;
        RECT  46.944 0 46.968 0.084 ;
    END
  END f_flit[313]
  PIN f_flit[314]
    DIRECTION OUTPUT ;
    USE SIGNAL ;
    PORT
      LAYER M5 ;
        RECT  47.088 0 47.112 0.084 ;
    END
  END f_flit[314]
  PIN f_flit[315]
    DIRECTION OUTPUT ;
    USE SIGNAL ;
    PORT
      LAYER M5 ;
        RECT  47.232 0 47.256 0.084 ;
    END
  END f_flit[315]
  PIN f_flit[316]
    DIRECTION OUTPUT ;
    USE SIGNAL ;
    PORT
      LAYER M5 ;
        RECT  47.376 0 47.4 0.084 ;
    END
  END f_flit[316]
  PIN f_flit[317]
    DIRECTION OUTPUT ;
    USE SIGNAL ;
    PORT
      LAYER M5 ;
        RECT  47.52 0 47.544 0.084 ;
    END
  END f_flit[317]
  PIN f_flit[318]
    DIRECTION OUTPUT ;
    USE SIGNAL ;
    PORT
      LAYER M5 ;
        RECT  47.664 0 47.688 0.084 ;
    END
  END f_flit[318]
  PIN f_flit[319]
    DIRECTION OUTPUT ;
    USE SIGNAL ;
    PORT
      LAYER M5 ;
        RECT  47.808 0 47.832 0.084 ;
    END
  END f_flit[319]
  PIN f_flit[31]
    DIRECTION OUTPUT ;
    USE SIGNAL ;
    PORT
      LAYER M5 ;
        RECT  72 0 72.024 0.084 ;
    END
  END f_flit[31]
  PIN f_flit[320]
    DIRECTION OUTPUT ;
    USE SIGNAL ;
    PORT
      LAYER M5 ;
        RECT  38.736 0 38.76 0.084 ;
    END
  END f_flit[320]
  PIN f_flit[321]
    DIRECTION OUTPUT ;
    USE SIGNAL ;
    PORT
      LAYER M5 ;
        RECT  38.88 0 38.904 0.084 ;
    END
  END f_flit[321]
  PIN f_flit[322]
    DIRECTION OUTPUT ;
    USE SIGNAL ;
    PORT
      LAYER M5 ;
        RECT  39.024 0 39.048 0.084 ;
    END
  END f_flit[322]
  PIN f_flit[323]
    DIRECTION OUTPUT ;
    USE SIGNAL ;
    PORT
      LAYER M5 ;
        RECT  39.168 0 39.192 0.084 ;
    END
  END f_flit[323]
  PIN f_flit[324]
    DIRECTION OUTPUT ;
    USE SIGNAL ;
    PORT
      LAYER M5 ;
        RECT  39.312 0 39.336 0.084 ;
    END
  END f_flit[324]
  PIN f_flit[325]
    DIRECTION OUTPUT ;
    USE SIGNAL ;
    PORT
      LAYER M5 ;
        RECT  39.456 0 39.48 0.084 ;
    END
  END f_flit[325]
  PIN f_flit[326]
    DIRECTION OUTPUT ;
    USE SIGNAL ;
    PORT
      LAYER M5 ;
        RECT  39.6 0 39.624 0.084 ;
    END
  END f_flit[326]
  PIN f_flit[327]
    DIRECTION OUTPUT ;
    USE SIGNAL ;
    PORT
      LAYER M5 ;
        RECT  39.744 0 39.768 0.084 ;
    END
  END f_flit[327]
  PIN f_flit[328]
    DIRECTION OUTPUT ;
    USE SIGNAL ;
    PORT
      LAYER M5 ;
        RECT  39.888 0 39.912 0.084 ;
    END
  END f_flit[328]
  PIN f_flit[329]
    DIRECTION OUTPUT ;
    USE SIGNAL ;
    PORT
      LAYER M5 ;
        RECT  40.032 0 40.056 0.084 ;
    END
  END f_flit[329]
  PIN f_flit[32]
    DIRECTION OUTPUT ;
    USE SIGNAL ;
    PORT
      LAYER M5 ;
        RECT  81.36 0 81.384 0.084 ;
    END
  END f_flit[32]
  PIN f_flit[330]
    DIRECTION OUTPUT ;
    USE SIGNAL ;
    PORT
      LAYER M5 ;
        RECT  40.176 0 40.2 0.084 ;
    END
  END f_flit[330]
  PIN f_flit[331]
    DIRECTION OUTPUT ;
    USE SIGNAL ;
    PORT
      LAYER M5 ;
        RECT  40.32 0 40.344 0.084 ;
    END
  END f_flit[331]
  PIN f_flit[332]
    DIRECTION OUTPUT ;
    USE SIGNAL ;
    PORT
      LAYER M5 ;
        RECT  40.464 0 40.488 0.084 ;
    END
  END f_flit[332]
  PIN f_flit[333]
    DIRECTION OUTPUT ;
    USE SIGNAL ;
    PORT
      LAYER M5 ;
        RECT  40.608 0 40.632 0.084 ;
    END
  END f_flit[333]
  PIN f_flit[334]
    DIRECTION OUTPUT ;
    USE SIGNAL ;
    PORT
      LAYER M5 ;
        RECT  40.752 0 40.776 0.084 ;
    END
  END f_flit[334]
  PIN f_flit[335]
    DIRECTION OUTPUT ;
    USE SIGNAL ;
    PORT
      LAYER M5 ;
        RECT  40.896 0 40.92 0.084 ;
    END
  END f_flit[335]
  PIN f_flit[336]
    DIRECTION OUTPUT ;
    USE SIGNAL ;
    PORT
      LAYER M5 ;
        RECT  41.04 0 41.064 0.084 ;
    END
  END f_flit[336]
  PIN f_flit[337]
    DIRECTION OUTPUT ;
    USE SIGNAL ;
    PORT
      LAYER M5 ;
        RECT  41.184 0 41.208 0.084 ;
    END
  END f_flit[337]
  PIN f_flit[338]
    DIRECTION OUTPUT ;
    USE SIGNAL ;
    PORT
      LAYER M5 ;
        RECT  41.328 0 41.352 0.084 ;
    END
  END f_flit[338]
  PIN f_flit[339]
    DIRECTION OUTPUT ;
    USE SIGNAL ;
    PORT
      LAYER M5 ;
        RECT  41.472 0 41.496 0.084 ;
    END
  END f_flit[339]
  PIN f_flit[33]
    DIRECTION OUTPUT ;
    USE SIGNAL ;
    PORT
      LAYER M5 ;
        RECT  81.504 0 81.528 0.084 ;
    END
  END f_flit[33]
  PIN f_flit[340]
    DIRECTION OUTPUT ;
    USE SIGNAL ;
    PORT
      LAYER M5 ;
        RECT  41.616 0 41.64 0.084 ;
    END
  END f_flit[340]
  PIN f_flit[341]
    DIRECTION OUTPUT ;
    USE SIGNAL ;
    PORT
      LAYER M5 ;
        RECT  41.76 0 41.784 0.084 ;
    END
  END f_flit[341]
  PIN f_flit[342]
    DIRECTION OUTPUT ;
    USE SIGNAL ;
    PORT
      LAYER M5 ;
        RECT  41.904 0 41.928 0.084 ;
    END
  END f_flit[342]
  PIN f_flit[343]
    DIRECTION OUTPUT ;
    USE SIGNAL ;
    PORT
      LAYER M5 ;
        RECT  42.048 0 42.072 0.084 ;
    END
  END f_flit[343]
  PIN f_flit[344]
    DIRECTION OUTPUT ;
    USE SIGNAL ;
    PORT
      LAYER M5 ;
        RECT  42.192 0 42.216 0.084 ;
    END
  END f_flit[344]
  PIN f_flit[345]
    DIRECTION OUTPUT ;
    USE SIGNAL ;
    PORT
      LAYER M5 ;
        RECT  42.336 0 42.36 0.084 ;
    END
  END f_flit[345]
  PIN f_flit[346]
    DIRECTION OUTPUT ;
    USE SIGNAL ;
    PORT
      LAYER M5 ;
        RECT  42.48 0 42.504 0.084 ;
    END
  END f_flit[346]
  PIN f_flit[347]
    DIRECTION OUTPUT ;
    USE SIGNAL ;
    PORT
      LAYER M5 ;
        RECT  42.624 0 42.648 0.084 ;
    END
  END f_flit[347]
  PIN f_flit[348]
    DIRECTION OUTPUT ;
    USE SIGNAL ;
    PORT
      LAYER M5 ;
        RECT  42.768 0 42.792 0.084 ;
    END
  END f_flit[348]
  PIN f_flit[349]
    DIRECTION OUTPUT ;
    USE SIGNAL ;
    PORT
      LAYER M5 ;
        RECT  42.912 0 42.936 0.084 ;
    END
  END f_flit[349]
  PIN f_flit[34]
    DIRECTION OUTPUT ;
    USE SIGNAL ;
    PORT
      LAYER M5 ;
        RECT  81.648 0 81.672 0.084 ;
    END
  END f_flit[34]
  PIN f_flit[350]
    DIRECTION OUTPUT ;
    USE SIGNAL ;
    PORT
      LAYER M5 ;
        RECT  43.056 0 43.08 0.084 ;
    END
  END f_flit[350]
  PIN f_flit[351]
    DIRECTION OUTPUT ;
    USE SIGNAL ;
    PORT
      LAYER M5 ;
        RECT  43.2 0 43.224 0.084 ;
    END
  END f_flit[351]
  PIN f_flit[352]
    DIRECTION OUTPUT ;
    USE SIGNAL ;
    PORT
      LAYER M5 ;
        RECT  34.128 0 34.152 0.084 ;
    END
  END f_flit[352]
  PIN f_flit[353]
    DIRECTION OUTPUT ;
    USE SIGNAL ;
    PORT
      LAYER M5 ;
        RECT  34.272 0 34.296 0.084 ;
    END
  END f_flit[353]
  PIN f_flit[354]
    DIRECTION OUTPUT ;
    USE SIGNAL ;
    PORT
      LAYER M5 ;
        RECT  34.416 0 34.44 0.084 ;
    END
  END f_flit[354]
  PIN f_flit[355]
    DIRECTION OUTPUT ;
    USE SIGNAL ;
    PORT
      LAYER M5 ;
        RECT  34.56 0 34.584 0.084 ;
    END
  END f_flit[355]
  PIN f_flit[356]
    DIRECTION OUTPUT ;
    USE SIGNAL ;
    PORT
      LAYER M5 ;
        RECT  34.704 0 34.728 0.084 ;
    END
  END f_flit[356]
  PIN f_flit[357]
    DIRECTION OUTPUT ;
    USE SIGNAL ;
    PORT
      LAYER M5 ;
        RECT  34.848 0 34.872 0.084 ;
    END
  END f_flit[357]
  PIN f_flit[358]
    DIRECTION OUTPUT ;
    USE SIGNAL ;
    PORT
      LAYER M5 ;
        RECT  34.992 0 35.016 0.084 ;
    END
  END f_flit[358]
  PIN f_flit[359]
    DIRECTION OUTPUT ;
    USE SIGNAL ;
    PORT
      LAYER M5 ;
        RECT  35.136 0 35.16 0.084 ;
    END
  END f_flit[359]
  PIN f_flit[35]
    DIRECTION OUTPUT ;
    USE SIGNAL ;
    PORT
      LAYER M5 ;
        RECT  81.792 0 81.816 0.084 ;
    END
  END f_flit[35]
  PIN f_flit[360]
    DIRECTION OUTPUT ;
    USE SIGNAL ;
    PORT
      LAYER M5 ;
        RECT  35.28 0 35.304 0.084 ;
    END
  END f_flit[360]
  PIN f_flit[361]
    DIRECTION OUTPUT ;
    USE SIGNAL ;
    PORT
      LAYER M5 ;
        RECT  35.424 0 35.448 0.084 ;
    END
  END f_flit[361]
  PIN f_flit[362]
    DIRECTION OUTPUT ;
    USE SIGNAL ;
    PORT
      LAYER M5 ;
        RECT  35.568 0 35.592 0.084 ;
    END
  END f_flit[362]
  PIN f_flit[363]
    DIRECTION OUTPUT ;
    USE SIGNAL ;
    PORT
      LAYER M5 ;
        RECT  35.712 0 35.736 0.084 ;
    END
  END f_flit[363]
  PIN f_flit[364]
    DIRECTION OUTPUT ;
    USE SIGNAL ;
    PORT
      LAYER M5 ;
        RECT  35.856 0 35.88 0.084 ;
    END
  END f_flit[364]
  PIN f_flit[365]
    DIRECTION OUTPUT ;
    USE SIGNAL ;
    PORT
      LAYER M5 ;
        RECT  36 0 36.024 0.084 ;
    END
  END f_flit[365]
  PIN f_flit[366]
    DIRECTION OUTPUT ;
    USE SIGNAL ;
    PORT
      LAYER M5 ;
        RECT  36.144 0 36.168 0.084 ;
    END
  END f_flit[366]
  PIN f_flit[367]
    DIRECTION OUTPUT ;
    USE SIGNAL ;
    PORT
      LAYER M5 ;
        RECT  36.288 0 36.312 0.084 ;
    END
  END f_flit[367]
  PIN f_flit[368]
    DIRECTION OUTPUT ;
    USE SIGNAL ;
    PORT
      LAYER M5 ;
        RECT  36.432 0 36.456 0.084 ;
    END
  END f_flit[368]
  PIN f_flit[369]
    DIRECTION OUTPUT ;
    USE SIGNAL ;
    PORT
      LAYER M5 ;
        RECT  36.576 0 36.6 0.084 ;
    END
  END f_flit[369]
  PIN f_flit[36]
    DIRECTION OUTPUT ;
    USE SIGNAL ;
    PORT
      LAYER M5 ;
        RECT  81.936 0 81.96 0.084 ;
    END
  END f_flit[36]
  PIN f_flit[370]
    DIRECTION OUTPUT ;
    USE SIGNAL ;
    PORT
      LAYER M5 ;
        RECT  36.72 0 36.744 0.084 ;
    END
  END f_flit[370]
  PIN f_flit[371]
    DIRECTION OUTPUT ;
    USE SIGNAL ;
    PORT
      LAYER M5 ;
        RECT  36.864 0 36.888 0.084 ;
    END
  END f_flit[371]
  PIN f_flit[372]
    DIRECTION OUTPUT ;
    USE SIGNAL ;
    PORT
      LAYER M5 ;
        RECT  37.008 0 37.032 0.084 ;
    END
  END f_flit[372]
  PIN f_flit[373]
    DIRECTION OUTPUT ;
    USE SIGNAL ;
    PORT
      LAYER M5 ;
        RECT  37.152 0 37.176 0.084 ;
    END
  END f_flit[373]
  PIN f_flit[374]
    DIRECTION OUTPUT ;
    USE SIGNAL ;
    PORT
      LAYER M5 ;
        RECT  37.296 0 37.32 0.084 ;
    END
  END f_flit[374]
  PIN f_flit[375]
    DIRECTION OUTPUT ;
    USE SIGNAL ;
    PORT
      LAYER M5 ;
        RECT  37.44 0 37.464 0.084 ;
    END
  END f_flit[375]
  PIN f_flit[376]
    DIRECTION OUTPUT ;
    USE SIGNAL ;
    PORT
      LAYER M5 ;
        RECT  37.584 0 37.608 0.084 ;
    END
  END f_flit[376]
  PIN f_flit[377]
    DIRECTION OUTPUT ;
    USE SIGNAL ;
    PORT
      LAYER M5 ;
        RECT  37.728 0 37.752 0.084 ;
    END
  END f_flit[377]
  PIN f_flit[378]
    DIRECTION OUTPUT ;
    USE SIGNAL ;
    PORT
      LAYER M5 ;
        RECT  37.872 0 37.896 0.084 ;
    END
  END f_flit[378]
  PIN f_flit[379]
    DIRECTION OUTPUT ;
    USE SIGNAL ;
    PORT
      LAYER M5 ;
        RECT  38.016 0 38.04 0.084 ;
    END
  END f_flit[379]
  PIN f_flit[37]
    DIRECTION OUTPUT ;
    USE SIGNAL ;
    PORT
      LAYER M5 ;
        RECT  82.08 0 82.104 0.084 ;
    END
  END f_flit[37]
  PIN f_flit[380]
    DIRECTION OUTPUT ;
    USE SIGNAL ;
    PORT
      LAYER M5 ;
        RECT  38.16 0 38.184 0.084 ;
    END
  END f_flit[380]
  PIN f_flit[381]
    DIRECTION OUTPUT ;
    USE SIGNAL ;
    PORT
      LAYER M5 ;
        RECT  38.304 0 38.328 0.084 ;
    END
  END f_flit[381]
  PIN f_flit[382]
    DIRECTION OUTPUT ;
    USE SIGNAL ;
    PORT
      LAYER M5 ;
        RECT  38.448 0 38.472 0.084 ;
    END
  END f_flit[382]
  PIN f_flit[383]
    DIRECTION OUTPUT ;
    USE SIGNAL ;
    PORT
      LAYER M5 ;
        RECT  38.592 0 38.616 0.084 ;
    END
  END f_flit[383]
  PIN f_flit[384]
    DIRECTION OUTPUT ;
    USE SIGNAL ;
    PORT
      LAYER M5 ;
        RECT  87.12 0 87.144 0.084 ;
    END
  END f_flit[384]
  PIN f_flit[385]
    DIRECTION OUTPUT ;
    USE SIGNAL ;
    PORT
      LAYER M5 ;
        RECT  87.264 0 87.288 0.084 ;
    END
  END f_flit[385]
  PIN f_flit[386]
    DIRECTION OUTPUT ;
    USE SIGNAL ;
    PORT
      LAYER M5 ;
        RECT  87.408 0 87.432 0.084 ;
    END
  END f_flit[386]
  PIN f_flit[387]
    DIRECTION OUTPUT ;
    USE SIGNAL ;
    PORT
      LAYER M5 ;
        RECT  87.552 0 87.576 0.084 ;
    END
  END f_flit[387]
  PIN f_flit[388]
    DIRECTION OUTPUT ;
    USE SIGNAL ;
    PORT
      LAYER M5 ;
        RECT  87.696 0 87.72 0.084 ;
    END
  END f_flit[388]
  PIN f_flit[389]
    DIRECTION OUTPUT ;
    USE SIGNAL ;
    PORT
      LAYER M5 ;
        RECT  87.84 0 87.864 0.084 ;
    END
  END f_flit[389]
  PIN f_flit[38]
    DIRECTION OUTPUT ;
    USE SIGNAL ;
    PORT
      LAYER M5 ;
        RECT  82.224 0 82.248 0.084 ;
    END
  END f_flit[38]
  PIN f_flit[390]
    DIRECTION OUTPUT ;
    USE SIGNAL ;
    PORT
      LAYER M5 ;
        RECT  87.984 0 88.008 0.084 ;
    END
  END f_flit[390]
  PIN f_flit[391]
    DIRECTION OUTPUT ;
    USE SIGNAL ;
    PORT
      LAYER M5 ;
        RECT  88.128 0 88.152 0.084 ;
    END
  END f_flit[391]
  PIN f_flit[392]
    DIRECTION OUTPUT ;
    USE SIGNAL ;
    PORT
      LAYER M5 ;
        RECT  88.272 0 88.296 0.084 ;
    END
  END f_flit[392]
  PIN f_flit[393]
    DIRECTION OUTPUT ;
    USE SIGNAL ;
    PORT
      LAYER M5 ;
        RECT  88.416 0 88.44 0.084 ;
    END
  END f_flit[393]
  PIN f_flit[394]
    DIRECTION OUTPUT ;
    USE SIGNAL ;
    PORT
      LAYER M5 ;
        RECT  88.56 0 88.584 0.084 ;
    END
  END f_flit[394]
  PIN f_flit[395]
    DIRECTION OUTPUT ;
    USE SIGNAL ;
    PORT
      LAYER M5 ;
        RECT  88.704 0 88.728 0.084 ;
    END
  END f_flit[395]
  PIN f_flit[396]
    DIRECTION OUTPUT ;
    USE SIGNAL ;
    PORT
      LAYER M5 ;
        RECT  88.848 0 88.872 0.084 ;
    END
  END f_flit[396]
  PIN f_flit[397]
    DIRECTION OUTPUT ;
    USE SIGNAL ;
    PORT
      LAYER M5 ;
        RECT  88.992 0 89.016 0.084 ;
    END
  END f_flit[397]
  PIN f_flit[398]
    DIRECTION OUTPUT ;
    USE SIGNAL ;
    PORT
      LAYER M5 ;
        RECT  89.136 0 89.16 0.084 ;
    END
  END f_flit[398]
  PIN f_flit[399]
    DIRECTION OUTPUT ;
    USE SIGNAL ;
    PORT
      LAYER M5 ;
        RECT  89.28 0 89.304 0.084 ;
    END
  END f_flit[399]
  PIN f_flit[39]
    DIRECTION OUTPUT ;
    USE SIGNAL ;
    PORT
      LAYER M5 ;
        RECT  82.368 0 82.392 0.084 ;
    END
  END f_flit[39]
  PIN f_flit[3]
    DIRECTION OUTPUT ;
    USE SIGNAL ;
    PORT
      LAYER M5 ;
        RECT  67.968 0 67.992 0.084 ;
    END
  END f_flit[3]
  PIN f_flit[400]
    DIRECTION OUTPUT ;
    USE SIGNAL ;
    PORT
      LAYER M5 ;
        RECT  89.424 0 89.448 0.084 ;
    END
  END f_flit[400]
  PIN f_flit[401]
    DIRECTION OUTPUT ;
    USE SIGNAL ;
    PORT
      LAYER M5 ;
        RECT  89.568 0 89.592 0.084 ;
    END
  END f_flit[401]
  PIN f_flit[402]
    DIRECTION OUTPUT ;
    USE SIGNAL ;
    PORT
      LAYER M5 ;
        RECT  89.712 0 89.736 0.084 ;
    END
  END f_flit[402]
  PIN f_flit[403]
    DIRECTION OUTPUT ;
    USE SIGNAL ;
    PORT
      LAYER M5 ;
        RECT  89.856 0 89.88 0.084 ;
    END
  END f_flit[403]
  PIN f_flit[404]
    DIRECTION OUTPUT ;
    USE SIGNAL ;
    PORT
      LAYER M5 ;
        RECT  90 0 90.024 0.084 ;
    END
  END f_flit[404]
  PIN f_flit[405]
    DIRECTION OUTPUT ;
    USE SIGNAL ;
    PORT
      LAYER M5 ;
        RECT  90.144 0 90.168 0.084 ;
    END
  END f_flit[405]
  PIN f_flit[406]
    DIRECTION OUTPUT ;
    USE SIGNAL ;
    PORT
      LAYER M5 ;
        RECT  90.288 0 90.312 0.084 ;
    END
  END f_flit[406]
  PIN f_flit[407]
    DIRECTION OUTPUT ;
    USE SIGNAL ;
    PORT
      LAYER M5 ;
        RECT  90.432 0 90.456 0.084 ;
    END
  END f_flit[407]
  PIN f_flit[408]
    DIRECTION OUTPUT ;
    USE SIGNAL ;
    PORT
      LAYER M5 ;
        RECT  90.576 0 90.6 0.084 ;
    END
  END f_flit[408]
  PIN f_flit[409]
    DIRECTION OUTPUT ;
    USE SIGNAL ;
    PORT
      LAYER M5 ;
        RECT  90.72 0 90.744 0.084 ;
    END
  END f_flit[409]
  PIN f_flit[40]
    DIRECTION OUTPUT ;
    USE SIGNAL ;
    PORT
      LAYER M5 ;
        RECT  82.512 0 82.536 0.084 ;
    END
  END f_flit[40]
  PIN f_flit[410]
    DIRECTION OUTPUT ;
    USE SIGNAL ;
    PORT
      LAYER M5 ;
        RECT  90.864 0 90.888 0.084 ;
    END
  END f_flit[410]
  PIN f_flit[411]
    DIRECTION OUTPUT ;
    USE SIGNAL ;
    PORT
      LAYER M5 ;
        RECT  91.008 0 91.032 0.084 ;
    END
  END f_flit[411]
  PIN f_flit[412]
    DIRECTION OUTPUT ;
    USE SIGNAL ;
    PORT
      LAYER M5 ;
        RECT  91.152 0 91.176 0.084 ;
    END
  END f_flit[412]
  PIN f_flit[413]
    DIRECTION OUTPUT ;
    USE SIGNAL ;
    PORT
      LAYER M5 ;
        RECT  91.296 0 91.32 0.084 ;
    END
  END f_flit[413]
  PIN f_flit[414]
    DIRECTION OUTPUT ;
    USE SIGNAL ;
    PORT
      LAYER M5 ;
        RECT  91.44 0 91.464 0.084 ;
    END
  END f_flit[414]
  PIN f_flit[415]
    DIRECTION OUTPUT ;
    USE SIGNAL ;
    PORT
      LAYER M5 ;
        RECT  91.584 0 91.608 0.084 ;
    END
  END f_flit[415]
  PIN f_flit[416]
    DIRECTION OUTPUT ;
    USE SIGNAL ;
    PORT
      LAYER M5 ;
        RECT  91.728 0 91.752 0.084 ;
    END
  END f_flit[416]
  PIN f_flit[417]
    DIRECTION OUTPUT ;
    USE SIGNAL ;
    PORT
      LAYER M5 ;
        RECT  91.872 0 91.896 0.084 ;
    END
  END f_flit[417]
  PIN f_flit[418]
    DIRECTION OUTPUT ;
    USE SIGNAL ;
    PORT
      LAYER M5 ;
        RECT  92.016 0 92.04 0.084 ;
    END
  END f_flit[418]
  PIN f_flit[419]
    DIRECTION OUTPUT ;
    USE SIGNAL ;
    PORT
      LAYER M5 ;
        RECT  92.16 0 92.184 0.084 ;
    END
  END f_flit[419]
  PIN f_flit[41]
    DIRECTION OUTPUT ;
    USE SIGNAL ;
    PORT
      LAYER M5 ;
        RECT  82.656 0 82.68 0.084 ;
    END
  END f_flit[41]
  PIN f_flit[420]
    DIRECTION OUTPUT ;
    USE SIGNAL ;
    PORT
      LAYER M5 ;
        RECT  92.304 0 92.328 0.084 ;
    END
  END f_flit[420]
  PIN f_flit[421]
    DIRECTION OUTPUT ;
    USE SIGNAL ;
    PORT
      LAYER M5 ;
        RECT  92.448 0 92.472 0.084 ;
    END
  END f_flit[421]
  PIN f_flit[422]
    DIRECTION OUTPUT ;
    USE SIGNAL ;
    PORT
      LAYER M5 ;
        RECT  92.592 0 92.616 0.084 ;
    END
  END f_flit[422]
  PIN f_flit[423]
    DIRECTION OUTPUT ;
    USE SIGNAL ;
    PORT
      LAYER M5 ;
        RECT  92.736 0 92.76 0.084 ;
    END
  END f_flit[423]
  PIN f_flit[424]
    DIRECTION OUTPUT ;
    USE SIGNAL ;
    PORT
      LAYER M5 ;
        RECT  92.88 0 92.904 0.084 ;
    END
  END f_flit[424]
  PIN f_flit[425]
    DIRECTION OUTPUT ;
    USE SIGNAL ;
    PORT
      LAYER M5 ;
        RECT  93.024 0 93.048 0.084 ;
    END
  END f_flit[425]
  PIN f_flit[426]
    DIRECTION OUTPUT ;
    USE SIGNAL ;
    PORT
      LAYER M5 ;
        RECT  93.168 0 93.192 0.084 ;
    END
  END f_flit[426]
  PIN f_flit[427]
    DIRECTION OUTPUT ;
    USE SIGNAL ;
    PORT
      LAYER M5 ;
        RECT  93.312 0 93.336 0.084 ;
    END
  END f_flit[427]
  PIN f_flit[428]
    DIRECTION OUTPUT ;
    USE SIGNAL ;
    PORT
      LAYER M5 ;
        RECT  93.456 0 93.48 0.084 ;
    END
  END f_flit[428]
  PIN f_flit[429]
    DIRECTION OUTPUT ;
    USE SIGNAL ;
    PORT
      LAYER M5 ;
        RECT  93.6 0 93.624 0.084 ;
    END
  END f_flit[429]
  PIN f_flit[42]
    DIRECTION OUTPUT ;
    USE SIGNAL ;
    PORT
      LAYER M5 ;
        RECT  82.8 0 82.824 0.084 ;
    END
  END f_flit[42]
  PIN f_flit[430]
    DIRECTION OUTPUT ;
    USE SIGNAL ;
    PORT
      LAYER M5 ;
        RECT  93.744 0 93.768 0.084 ;
    END
  END f_flit[430]
  PIN f_flit[431]
    DIRECTION OUTPUT ;
    USE SIGNAL ;
    PORT
      LAYER M5 ;
        RECT  93.888 0 93.912 0.084 ;
    END
  END f_flit[431]
  PIN f_flit[432]
    DIRECTION OUTPUT ;
    USE SIGNAL ;
    PORT
      LAYER M5 ;
        RECT  94.032 0 94.056 0.084 ;
    END
  END f_flit[432]
  PIN f_flit[433]
    DIRECTION OUTPUT ;
    USE SIGNAL ;
    PORT
      LAYER M5 ;
        RECT  94.176 0 94.2 0.084 ;
    END
  END f_flit[433]
  PIN f_flit[434]
    DIRECTION OUTPUT ;
    USE SIGNAL ;
    PORT
      LAYER M5 ;
        RECT  94.32 0 94.344 0.084 ;
    END
  END f_flit[434]
  PIN f_flit[435]
    DIRECTION OUTPUT ;
    USE SIGNAL ;
    PORT
      LAYER M5 ;
        RECT  94.464 0 94.488 0.084 ;
    END
  END f_flit[435]
  PIN f_flit[436]
    DIRECTION OUTPUT ;
    USE SIGNAL ;
    PORT
      LAYER M5 ;
        RECT  94.608 0 94.632 0.084 ;
    END
  END f_flit[436]
  PIN f_flit[437]
    DIRECTION OUTPUT ;
    USE SIGNAL ;
    PORT
      LAYER M5 ;
        RECT  94.752 0 94.776 0.084 ;
    END
  END f_flit[437]
  PIN f_flit[438]
    DIRECTION OUTPUT ;
    USE SIGNAL ;
    PORT
      LAYER M5 ;
        RECT  94.896 0 94.92 0.084 ;
    END
  END f_flit[438]
  PIN f_flit[439]
    DIRECTION OUTPUT ;
    USE SIGNAL ;
    PORT
      LAYER M5 ;
        RECT  95.04 0 95.064 0.084 ;
    END
  END f_flit[439]
  PIN f_flit[43]
    DIRECTION OUTPUT ;
    USE SIGNAL ;
    PORT
      LAYER M5 ;
        RECT  82.944 0 82.968 0.084 ;
    END
  END f_flit[43]
  PIN f_flit[440]
    DIRECTION OUTPUT ;
    USE SIGNAL ;
    PORT
      LAYER M5 ;
        RECT  95.184 0 95.208 0.084 ;
    END
  END f_flit[440]
  PIN f_flit[441]
    DIRECTION OUTPUT ;
    USE SIGNAL ;
    PORT
      LAYER M5 ;
        RECT  95.328 0 95.352 0.084 ;
    END
  END f_flit[441]
  PIN f_flit[442]
    DIRECTION OUTPUT ;
    USE SIGNAL ;
    PORT
      LAYER M5 ;
        RECT  95.472 0 95.496 0.084 ;
    END
  END f_flit[442]
  PIN f_flit[443]
    DIRECTION OUTPUT ;
    USE SIGNAL ;
    PORT
      LAYER M5 ;
        RECT  95.616 0 95.64 0.084 ;
    END
  END f_flit[443]
  PIN f_flit[444]
    DIRECTION OUTPUT ;
    USE SIGNAL ;
    PORT
      LAYER M5 ;
        RECT  95.76 0 95.784 0.084 ;
    END
  END f_flit[444]
  PIN f_flit[445]
    DIRECTION OUTPUT ;
    USE SIGNAL ;
    PORT
      LAYER M5 ;
        RECT  95.904 0 95.928 0.084 ;
    END
  END f_flit[445]
  PIN f_flit[446]
    DIRECTION OUTPUT ;
    USE SIGNAL ;
    PORT
      LAYER M5 ;
        RECT  96.048 0 96.072 0.084 ;
    END
  END f_flit[446]
  PIN f_flit[447]
    DIRECTION OUTPUT ;
    USE SIGNAL ;
    PORT
      LAYER M5 ;
        RECT  96.192 0 96.216 0.084 ;
    END
  END f_flit[447]
  PIN f_flit[448]
    DIRECTION OUTPUT ;
    USE SIGNAL ;
    PORT
      LAYER M5 ;
        RECT  23.76 0 23.784 0.084 ;
    END
  END f_flit[448]
  PIN f_flit[449]
    DIRECTION OUTPUT ;
    USE SIGNAL ;
    PORT
      LAYER M5 ;
        RECT  23.904 0 23.928 0.084 ;
    END
  END f_flit[449]
  PIN f_flit[44]
    DIRECTION OUTPUT ;
    USE SIGNAL ;
    PORT
      LAYER M5 ;
        RECT  83.088 0 83.112 0.084 ;
    END
  END f_flit[44]
  PIN f_flit[450]
    DIRECTION OUTPUT ;
    USE SIGNAL ;
    PORT
      LAYER M5 ;
        RECT  24.048 0 24.072 0.084 ;
    END
  END f_flit[450]
  PIN f_flit[451]
    DIRECTION OUTPUT ;
    USE SIGNAL ;
    PORT
      LAYER M5 ;
        RECT  24.192 0 24.216 0.084 ;
    END
  END f_flit[451]
  PIN f_flit[452]
    DIRECTION OUTPUT ;
    USE SIGNAL ;
    PORT
      LAYER M5 ;
        RECT  24.336 0 24.36 0.084 ;
    END
  END f_flit[452]
  PIN f_flit[453]
    DIRECTION OUTPUT ;
    USE SIGNAL ;
    PORT
      LAYER M5 ;
        RECT  24.48 0 24.504 0.084 ;
    END
  END f_flit[453]
  PIN f_flit[454]
    DIRECTION OUTPUT ;
    USE SIGNAL ;
    PORT
      LAYER M5 ;
        RECT  24.624 0 24.648 0.084 ;
    END
  END f_flit[454]
  PIN f_flit[455]
    DIRECTION OUTPUT ;
    USE SIGNAL ;
    PORT
      LAYER M5 ;
        RECT  24.768 0 24.792 0.084 ;
    END
  END f_flit[455]
  PIN f_flit[456]
    DIRECTION OUTPUT ;
    USE SIGNAL ;
    PORT
      LAYER M5 ;
        RECT  24.912 0 24.936 0.084 ;
    END
  END f_flit[456]
  PIN f_flit[457]
    DIRECTION OUTPUT ;
    USE SIGNAL ;
    PORT
      LAYER M5 ;
        RECT  25.056 0 25.08 0.084 ;
    END
  END f_flit[457]
  PIN f_flit[458]
    DIRECTION OUTPUT ;
    USE SIGNAL ;
    PORT
      LAYER M5 ;
        RECT  25.2 0 25.224 0.084 ;
    END
  END f_flit[458]
  PIN f_flit[459]
    DIRECTION OUTPUT ;
    USE SIGNAL ;
    PORT
      LAYER M5 ;
        RECT  25.344 0 25.368 0.084 ;
    END
  END f_flit[459]
  PIN f_flit[45]
    DIRECTION OUTPUT ;
    USE SIGNAL ;
    PORT
      LAYER M5 ;
        RECT  83.232 0 83.256 0.084 ;
    END
  END f_flit[45]
  PIN f_flit[460]
    DIRECTION OUTPUT ;
    USE SIGNAL ;
    PORT
      LAYER M5 ;
        RECT  25.488 0 25.512 0.084 ;
    END
  END f_flit[460]
  PIN f_flit[461]
    DIRECTION OUTPUT ;
    USE SIGNAL ;
    PORT
      LAYER M5 ;
        RECT  25.632 0 25.656 0.084 ;
    END
  END f_flit[461]
  PIN f_flit[462]
    DIRECTION OUTPUT ;
    USE SIGNAL ;
    PORT
      LAYER M5 ;
        RECT  25.776 0 25.8 0.084 ;
    END
  END f_flit[462]
  PIN f_flit[463]
    DIRECTION OUTPUT ;
    USE SIGNAL ;
    PORT
      LAYER M5 ;
        RECT  25.92 0 25.944 0.084 ;
    END
  END f_flit[463]
  PIN f_flit[464]
    DIRECTION OUTPUT ;
    USE SIGNAL ;
    PORT
      LAYER M5 ;
        RECT  26.064 0 26.088 0.084 ;
    END
  END f_flit[464]
  PIN f_flit[465]
    DIRECTION OUTPUT ;
    USE SIGNAL ;
    PORT
      LAYER M5 ;
        RECT  26.208 0 26.232 0.084 ;
    END
  END f_flit[465]
  PIN f_flit[466]
    DIRECTION OUTPUT ;
    USE SIGNAL ;
    PORT
      LAYER M5 ;
        RECT  26.352 0 26.376 0.084 ;
    END
  END f_flit[466]
  PIN f_flit[467]
    DIRECTION OUTPUT ;
    USE SIGNAL ;
    PORT
      LAYER M5 ;
        RECT  26.496 0 26.52 0.084 ;
    END
  END f_flit[467]
  PIN f_flit[468]
    DIRECTION OUTPUT ;
    USE SIGNAL ;
    PORT
      LAYER M5 ;
        RECT  26.64 0 26.664 0.084 ;
    END
  END f_flit[468]
  PIN f_flit[469]
    DIRECTION OUTPUT ;
    USE SIGNAL ;
    PORT
      LAYER M5 ;
        RECT  26.784 0 26.808 0.084 ;
    END
  END f_flit[469]
  PIN f_flit[46]
    DIRECTION OUTPUT ;
    USE SIGNAL ;
    PORT
      LAYER M5 ;
        RECT  83.376 0 83.4 0.084 ;
    END
  END f_flit[46]
  PIN f_flit[470]
    DIRECTION OUTPUT ;
    USE SIGNAL ;
    PORT
      LAYER M5 ;
        RECT  26.928 0 26.952 0.084 ;
    END
  END f_flit[470]
  PIN f_flit[471]
    DIRECTION OUTPUT ;
    USE SIGNAL ;
    PORT
      LAYER M5 ;
        RECT  27.072 0 27.096 0.084 ;
    END
  END f_flit[471]
  PIN f_flit[472]
    DIRECTION OUTPUT ;
    USE SIGNAL ;
    PORT
      LAYER M5 ;
        RECT  27.216 0 27.24 0.084 ;
    END
  END f_flit[472]
  PIN f_flit[473]
    DIRECTION OUTPUT ;
    USE SIGNAL ;
    PORT
      LAYER M5 ;
        RECT  27.36 0 27.384 0.084 ;
    END
  END f_flit[473]
  PIN f_flit[474]
    DIRECTION OUTPUT ;
    USE SIGNAL ;
    PORT
      LAYER M5 ;
        RECT  27.504 0 27.528 0.084 ;
    END
  END f_flit[474]
  PIN f_flit[475]
    DIRECTION OUTPUT ;
    USE SIGNAL ;
    PORT
      LAYER M5 ;
        RECT  27.648 0 27.672 0.084 ;
    END
  END f_flit[475]
  PIN f_flit[476]
    DIRECTION OUTPUT ;
    USE SIGNAL ;
    PORT
      LAYER M5 ;
        RECT  27.792 0 27.816 0.084 ;
    END
  END f_flit[476]
  PIN f_flit[477]
    DIRECTION OUTPUT ;
    USE SIGNAL ;
    PORT
      LAYER M5 ;
        RECT  27.936 0 27.96 0.084 ;
    END
  END f_flit[477]
  PIN f_flit[478]
    DIRECTION OUTPUT ;
    USE SIGNAL ;
    PORT
      LAYER M5 ;
        RECT  28.08 0 28.104 0.084 ;
    END
  END f_flit[478]
  PIN f_flit[479]
    DIRECTION OUTPUT ;
    USE SIGNAL ;
    PORT
      LAYER M5 ;
        RECT  28.224 0 28.248 0.084 ;
    END
  END f_flit[479]
  PIN f_flit[47]
    DIRECTION OUTPUT ;
    USE SIGNAL ;
    PORT
      LAYER M5 ;
        RECT  83.52 0 83.544 0.084 ;
    END
  END f_flit[47]
  PIN f_flit[480]
    DIRECTION OUTPUT ;
    USE SIGNAL ;
    PORT
      LAYER M5 ;
        RECT  14.544 0 14.568 0.084 ;
    END
  END f_flit[480]
  PIN f_flit[481]
    DIRECTION OUTPUT ;
    USE SIGNAL ;
    PORT
      LAYER M5 ;
        RECT  14.688 0 14.712 0.084 ;
    END
  END f_flit[481]
  PIN f_flit[482]
    DIRECTION OUTPUT ;
    USE SIGNAL ;
    PORT
      LAYER M5 ;
        RECT  14.832 0 14.856 0.084 ;
    END
  END f_flit[482]
  PIN f_flit[483]
    DIRECTION OUTPUT ;
    USE SIGNAL ;
    PORT
      LAYER M5 ;
        RECT  14.976 0 15 0.084 ;
    END
  END f_flit[483]
  PIN f_flit[484]
    DIRECTION OUTPUT ;
    USE SIGNAL ;
    PORT
      LAYER M5 ;
        RECT  15.12 0 15.144 0.084 ;
    END
  END f_flit[484]
  PIN f_flit[485]
    DIRECTION OUTPUT ;
    USE SIGNAL ;
    PORT
      LAYER M5 ;
        RECT  15.264 0 15.288 0.084 ;
    END
  END f_flit[485]
  PIN f_flit[486]
    DIRECTION OUTPUT ;
    USE SIGNAL ;
    PORT
      LAYER M5 ;
        RECT  15.408 0 15.432 0.084 ;
    END
  END f_flit[486]
  PIN f_flit[487]
    DIRECTION OUTPUT ;
    USE SIGNAL ;
    PORT
      LAYER M5 ;
        RECT  15.552 0 15.576 0.084 ;
    END
  END f_flit[487]
  PIN f_flit[488]
    DIRECTION OUTPUT ;
    USE SIGNAL ;
    PORT
      LAYER M5 ;
        RECT  15.696 0 15.72 0.084 ;
    END
  END f_flit[488]
  PIN f_flit[489]
    DIRECTION OUTPUT ;
    USE SIGNAL ;
    PORT
      LAYER M5 ;
        RECT  15.84 0 15.864 0.084 ;
    END
  END f_flit[489]
  PIN f_flit[48]
    DIRECTION OUTPUT ;
    USE SIGNAL ;
    PORT
      LAYER M5 ;
        RECT  83.664 0 83.688 0.084 ;
    END
  END f_flit[48]
  PIN f_flit[490]
    DIRECTION OUTPUT ;
    USE SIGNAL ;
    PORT
      LAYER M5 ;
        RECT  15.984 0 16.008 0.084 ;
    END
  END f_flit[490]
  PIN f_flit[491]
    DIRECTION OUTPUT ;
    USE SIGNAL ;
    PORT
      LAYER M5 ;
        RECT  16.128 0 16.152 0.084 ;
    END
  END f_flit[491]
  PIN f_flit[492]
    DIRECTION OUTPUT ;
    USE SIGNAL ;
    PORT
      LAYER M5 ;
        RECT  16.272 0 16.296 0.084 ;
    END
  END f_flit[492]
  PIN f_flit[493]
    DIRECTION OUTPUT ;
    USE SIGNAL ;
    PORT
      LAYER M5 ;
        RECT  16.416 0 16.44 0.084 ;
    END
  END f_flit[493]
  PIN f_flit[494]
    DIRECTION OUTPUT ;
    USE SIGNAL ;
    PORT
      LAYER M5 ;
        RECT  16.56 0 16.584 0.084 ;
    END
  END f_flit[494]
  PIN f_flit[495]
    DIRECTION OUTPUT ;
    USE SIGNAL ;
    PORT
      LAYER M5 ;
        RECT  16.704 0 16.728 0.084 ;
    END
  END f_flit[495]
  PIN f_flit[496]
    DIRECTION OUTPUT ;
    USE SIGNAL ;
    PORT
      LAYER M5 ;
        RECT  16.848 0 16.872 0.084 ;
    END
  END f_flit[496]
  PIN f_flit[497]
    DIRECTION OUTPUT ;
    USE SIGNAL ;
    PORT
      LAYER M5 ;
        RECT  16.992 0 17.016 0.084 ;
    END
  END f_flit[497]
  PIN f_flit[498]
    DIRECTION OUTPUT ;
    USE SIGNAL ;
    PORT
      LAYER M5 ;
        RECT  17.136 0 17.16 0.084 ;
    END
  END f_flit[498]
  PIN f_flit[499]
    DIRECTION OUTPUT ;
    USE SIGNAL ;
    PORT
      LAYER M5 ;
        RECT  17.28 0 17.304 0.084 ;
    END
  END f_flit[499]
  PIN f_flit[49]
    DIRECTION OUTPUT ;
    USE SIGNAL ;
    PORT
      LAYER M5 ;
        RECT  83.808 0 83.832 0.084 ;
    END
  END f_flit[49]
  PIN f_flit[4]
    DIRECTION OUTPUT ;
    USE SIGNAL ;
    PORT
      LAYER M5 ;
        RECT  68.112 0 68.136 0.084 ;
    END
  END f_flit[4]
  PIN f_flit[500]
    DIRECTION OUTPUT ;
    USE SIGNAL ;
    PORT
      LAYER M5 ;
        RECT  17.424 0 17.448 0.084 ;
    END
  END f_flit[500]
  PIN f_flit[501]
    DIRECTION OUTPUT ;
    USE SIGNAL ;
    PORT
      LAYER M5 ;
        RECT  17.568 0 17.592 0.084 ;
    END
  END f_flit[501]
  PIN f_flit[502]
    DIRECTION OUTPUT ;
    USE SIGNAL ;
    PORT
      LAYER M5 ;
        RECT  17.712 0 17.736 0.084 ;
    END
  END f_flit[502]
  PIN f_flit[503]
    DIRECTION OUTPUT ;
    USE SIGNAL ;
    PORT
      LAYER M5 ;
        RECT  17.856 0 17.88 0.084 ;
    END
  END f_flit[503]
  PIN f_flit[504]
    DIRECTION OUTPUT ;
    USE SIGNAL ;
    PORT
      LAYER M5 ;
        RECT  18 0 18.024 0.084 ;
    END
  END f_flit[504]
  PIN f_flit[505]
    DIRECTION OUTPUT ;
    USE SIGNAL ;
    PORT
      LAYER M5 ;
        RECT  18.144 0 18.168 0.084 ;
    END
  END f_flit[505]
  PIN f_flit[506]
    DIRECTION OUTPUT ;
    USE SIGNAL ;
    PORT
      LAYER M5 ;
        RECT  18.288 0 18.312 0.084 ;
    END
  END f_flit[506]
  PIN f_flit[507]
    DIRECTION OUTPUT ;
    USE SIGNAL ;
    PORT
      LAYER M5 ;
        RECT  18.432 0 18.456 0.084 ;
    END
  END f_flit[507]
  PIN f_flit[508]
    DIRECTION OUTPUT ;
    USE SIGNAL ;
    PORT
      LAYER M5 ;
        RECT  18.576 0 18.6 0.084 ;
    END
  END f_flit[508]
  PIN f_flit[509]
    DIRECTION OUTPUT ;
    USE SIGNAL ;
    PORT
      LAYER M5 ;
        RECT  18.72 0 18.744 0.084 ;
    END
  END f_flit[509]
  PIN f_flit[50]
    DIRECTION OUTPUT ;
    USE SIGNAL ;
    PORT
      LAYER M5 ;
        RECT  83.952 0 83.976 0.084 ;
    END
  END f_flit[50]
  PIN f_flit[510]
    DIRECTION OUTPUT ;
    USE SIGNAL ;
    PORT
      LAYER M5 ;
        RECT  18.864 0 18.888 0.084 ;
    END
  END f_flit[510]
  PIN f_flit[511]
    DIRECTION OUTPUT ;
    USE SIGNAL ;
    PORT
      LAYER M5 ;
        RECT  19.008 0 19.032 0.084 ;
    END
  END f_flit[511]
  PIN f_flit[512]
    DIRECTION OUTPUT ;
    USE SIGNAL ;
    PORT
      LAYER M5 ;
        RECT  19.152 0 19.176 0.084 ;
    END
  END f_flit[512]
  PIN f_flit[513]
    DIRECTION OUTPUT ;
    USE SIGNAL ;
    PORT
      LAYER M5 ;
        RECT  19.296 0 19.32 0.084 ;
    END
  END f_flit[513]
  PIN f_flit[514]
    DIRECTION OUTPUT ;
    USE SIGNAL ;
    PORT
      LAYER M5 ;
        RECT  19.44 0 19.464 0.084 ;
    END
  END f_flit[514]
  PIN f_flit[515]
    DIRECTION OUTPUT ;
    USE SIGNAL ;
    PORT
      LAYER M5 ;
        RECT  19.584 0 19.608 0.084 ;
    END
  END f_flit[515]
  PIN f_flit[516]
    DIRECTION OUTPUT ;
    USE SIGNAL ;
    PORT
      LAYER M5 ;
        RECT  19.728 0 19.752 0.084 ;
    END
  END f_flit[516]
  PIN f_flit[517]
    DIRECTION OUTPUT ;
    USE SIGNAL ;
    PORT
      LAYER M5 ;
        RECT  19.872 0 19.896 0.084 ;
    END
  END f_flit[517]
  PIN f_flit[518]
    DIRECTION OUTPUT ;
    USE SIGNAL ;
    PORT
      LAYER M5 ;
        RECT  20.016 0 20.04 0.084 ;
    END
  END f_flit[518]
  PIN f_flit[519]
    DIRECTION OUTPUT ;
    USE SIGNAL ;
    PORT
      LAYER M5 ;
        RECT  20.16 0 20.184 0.084 ;
    END
  END f_flit[519]
  PIN f_flit[51]
    DIRECTION OUTPUT ;
    USE SIGNAL ;
    PORT
      LAYER M5 ;
        RECT  84.096 0 84.12 0.084 ;
    END
  END f_flit[51]
  PIN f_flit[520]
    DIRECTION OUTPUT ;
    USE SIGNAL ;
    PORT
      LAYER M5 ;
        RECT  20.304 0 20.328 0.084 ;
    END
  END f_flit[520]
  PIN f_flit[521]
    DIRECTION OUTPUT ;
    USE SIGNAL ;
    PORT
      LAYER M5 ;
        RECT  20.448 0 20.472 0.084 ;
    END
  END f_flit[521]
  PIN f_flit[522]
    DIRECTION OUTPUT ;
    USE SIGNAL ;
    PORT
      LAYER M5 ;
        RECT  20.592 0 20.616 0.084 ;
    END
  END f_flit[522]
  PIN f_flit[523]
    DIRECTION OUTPUT ;
    USE SIGNAL ;
    PORT
      LAYER M5 ;
        RECT  20.736 0 20.76 0.084 ;
    END
  END f_flit[523]
  PIN f_flit[524]
    DIRECTION OUTPUT ;
    USE SIGNAL ;
    PORT
      LAYER M5 ;
        RECT  20.88 0 20.904 0.084 ;
    END
  END f_flit[524]
  PIN f_flit[525]
    DIRECTION OUTPUT ;
    USE SIGNAL ;
    PORT
      LAYER M5 ;
        RECT  21.024 0 21.048 0.084 ;
    END
  END f_flit[525]
  PIN f_flit[526]
    DIRECTION OUTPUT ;
    USE SIGNAL ;
    PORT
      LAYER M5 ;
        RECT  21.168 0 21.192 0.084 ;
    END
  END f_flit[526]
  PIN f_flit[527]
    DIRECTION OUTPUT ;
    USE SIGNAL ;
    PORT
      LAYER M5 ;
        RECT  21.312 0 21.336 0.084 ;
    END
  END f_flit[527]
  PIN f_flit[528]
    DIRECTION OUTPUT ;
    USE SIGNAL ;
    PORT
      LAYER M5 ;
        RECT  21.456 0 21.48 0.084 ;
    END
  END f_flit[528]
  PIN f_flit[529]
    DIRECTION OUTPUT ;
    USE SIGNAL ;
    PORT
      LAYER M5 ;
        RECT  21.6 0 21.624 0.084 ;
    END
  END f_flit[529]
  PIN f_flit[52]
    DIRECTION OUTPUT ;
    USE SIGNAL ;
    PORT
      LAYER M5 ;
        RECT  84.24 0 84.264 0.084 ;
    END
  END f_flit[52]
  PIN f_flit[530]
    DIRECTION OUTPUT ;
    USE SIGNAL ;
    PORT
      LAYER M5 ;
        RECT  21.744 0 21.768 0.084 ;
    END
  END f_flit[530]
  PIN f_flit[531]
    DIRECTION OUTPUT ;
    USE SIGNAL ;
    PORT
      LAYER M5 ;
        RECT  21.888 0 21.912 0.084 ;
    END
  END f_flit[531]
  PIN f_flit[532]
    DIRECTION OUTPUT ;
    USE SIGNAL ;
    PORT
      LAYER M5 ;
        RECT  22.032 0 22.056 0.084 ;
    END
  END f_flit[532]
  PIN f_flit[533]
    DIRECTION OUTPUT ;
    USE SIGNAL ;
    PORT
      LAYER M5 ;
        RECT  22.176 0 22.2 0.084 ;
    END
  END f_flit[533]
  PIN f_flit[534]
    DIRECTION OUTPUT ;
    USE SIGNAL ;
    PORT
      LAYER M5 ;
        RECT  22.32 0 22.344 0.084 ;
    END
  END f_flit[534]
  PIN f_flit[535]
    DIRECTION OUTPUT ;
    USE SIGNAL ;
    PORT
      LAYER M5 ;
        RECT  22.464 0 22.488 0.084 ;
    END
  END f_flit[535]
  PIN f_flit[536]
    DIRECTION OUTPUT ;
    USE SIGNAL ;
    PORT
      LAYER M5 ;
        RECT  22.608 0 22.632 0.084 ;
    END
  END f_flit[536]
  PIN f_flit[537]
    DIRECTION OUTPUT ;
    USE SIGNAL ;
    PORT
      LAYER M5 ;
        RECT  22.752 0 22.776 0.084 ;
    END
  END f_flit[537]
  PIN f_flit[538]
    DIRECTION OUTPUT ;
    USE SIGNAL ;
    PORT
      LAYER M5 ;
        RECT  22.896 0 22.92 0.084 ;
    END
  END f_flit[538]
  PIN f_flit[539]
    DIRECTION OUTPUT ;
    USE SIGNAL ;
    PORT
      LAYER M5 ;
        RECT  23.04 0 23.064 0.084 ;
    END
  END f_flit[539]
  PIN f_flit[53]
    DIRECTION OUTPUT ;
    USE SIGNAL ;
    PORT
      LAYER M5 ;
        RECT  84.384 0 84.408 0.084 ;
    END
  END f_flit[53]
  PIN f_flit[540]
    DIRECTION OUTPUT ;
    USE SIGNAL ;
    PORT
      LAYER M5 ;
        RECT  23.184 0 23.208 0.084 ;
    END
  END f_flit[540]
  PIN f_flit[541]
    DIRECTION OUTPUT ;
    USE SIGNAL ;
    PORT
      LAYER M5 ;
        RECT  23.328 0 23.352 0.084 ;
    END
  END f_flit[541]
  PIN f_flit[542]
    DIRECTION OUTPUT ;
    USE SIGNAL ;
    PORT
      LAYER M5 ;
        RECT  23.472 0 23.496 0.084 ;
    END
  END f_flit[542]
  PIN f_flit[543]
    DIRECTION OUTPUT ;
    USE SIGNAL ;
    PORT
      LAYER M5 ;
        RECT  23.616 0 23.64 0.084 ;
    END
  END f_flit[543]
  PIN f_flit[544]
    DIRECTION OUTPUT ;
    USE SIGNAL ;
    PORT
      LAYER M5 ;
        RECT  85.968 0 85.992 0.084 ;
    END
  END f_flit[544]
  PIN f_flit[54]
    DIRECTION OUTPUT ;
    USE SIGNAL ;
    PORT
      LAYER M5 ;
        RECT  84.528 0 84.552 0.084 ;
    END
  END f_flit[54]
  PIN f_flit[55]
    DIRECTION OUTPUT ;
    USE SIGNAL ;
    PORT
      LAYER M5 ;
        RECT  84.672 0 84.696 0.084 ;
    END
  END f_flit[55]
  PIN f_flit[56]
    DIRECTION OUTPUT ;
    USE SIGNAL ;
    PORT
      LAYER M5 ;
        RECT  84.816 0 84.84 0.084 ;
    END
  END f_flit[56]
  PIN f_flit[57]
    DIRECTION OUTPUT ;
    USE SIGNAL ;
    PORT
      LAYER M5 ;
        RECT  84.96 0 84.984 0.084 ;
    END
  END f_flit[57]
  PIN f_flit[58]
    DIRECTION OUTPUT ;
    USE SIGNAL ;
    PORT
      LAYER M5 ;
        RECT  85.104 0 85.128 0.084 ;
    END
  END f_flit[58]
  PIN f_flit[59]
    DIRECTION OUTPUT ;
    USE SIGNAL ;
    PORT
      LAYER M5 ;
        RECT  85.248 0 85.272 0.084 ;
    END
  END f_flit[59]
  PIN f_flit[5]
    DIRECTION OUTPUT ;
    USE SIGNAL ;
    PORT
      LAYER M5 ;
        RECT  68.256 0 68.28 0.084 ;
    END
  END f_flit[5]
  PIN f_flit[60]
    DIRECTION OUTPUT ;
    USE SIGNAL ;
    PORT
      LAYER M5 ;
        RECT  85.392 0 85.416 0.084 ;
    END
  END f_flit[60]
  PIN f_flit[61]
    DIRECTION OUTPUT ;
    USE SIGNAL ;
    PORT
      LAYER M5 ;
        RECT  85.536 0 85.56 0.084 ;
    END
  END f_flit[61]
  PIN f_flit[62]
    DIRECTION OUTPUT ;
    USE SIGNAL ;
    PORT
      LAYER M5 ;
        RECT  85.68 0 85.704 0.084 ;
    END
  END f_flit[62]
  PIN f_flit[63]
    DIRECTION OUTPUT ;
    USE SIGNAL ;
    PORT
      LAYER M5 ;
        RECT  85.824 0 85.848 0.084 ;
    END
  END f_flit[63]
  PIN f_flit[64]
    DIRECTION OUTPUT ;
    USE SIGNAL ;
    PORT
      LAYER M5 ;
        RECT  62.928 0 62.952 0.084 ;
    END
  END f_flit[64]
  PIN f_flit[65]
    DIRECTION OUTPUT ;
    USE SIGNAL ;
    PORT
      LAYER M5 ;
        RECT  63.072 0 63.096 0.084 ;
    END
  END f_flit[65]
  PIN f_flit[66]
    DIRECTION OUTPUT ;
    USE SIGNAL ;
    PORT
      LAYER M5 ;
        RECT  63.216 0 63.24 0.084 ;
    END
  END f_flit[66]
  PIN f_flit[67]
    DIRECTION OUTPUT ;
    USE SIGNAL ;
    PORT
      LAYER M5 ;
        RECT  63.36 0 63.384 0.084 ;
    END
  END f_flit[67]
  PIN f_flit[68]
    DIRECTION OUTPUT ;
    USE SIGNAL ;
    PORT
      LAYER M5 ;
        RECT  63.504 0 63.528 0.084 ;
    END
  END f_flit[68]
  PIN f_flit[69]
    DIRECTION OUTPUT ;
    USE SIGNAL ;
    PORT
      LAYER M5 ;
        RECT  63.648 0 63.672 0.084 ;
    END
  END f_flit[69]
  PIN f_flit[6]
    DIRECTION OUTPUT ;
    USE SIGNAL ;
    PORT
      LAYER M5 ;
        RECT  68.4 0 68.424 0.084 ;
    END
  END f_flit[6]
  PIN f_flit[70]
    DIRECTION OUTPUT ;
    USE SIGNAL ;
    PORT
      LAYER M5 ;
        RECT  63.792 0 63.816 0.084 ;
    END
  END f_flit[70]
  PIN f_flit[71]
    DIRECTION OUTPUT ;
    USE SIGNAL ;
    PORT
      LAYER M5 ;
        RECT  63.936 0 63.96 0.084 ;
    END
  END f_flit[71]
  PIN f_flit[72]
    DIRECTION OUTPUT ;
    USE SIGNAL ;
    PORT
      LAYER M5 ;
        RECT  64.08 0 64.104 0.084 ;
    END
  END f_flit[72]
  PIN f_flit[73]
    DIRECTION OUTPUT ;
    USE SIGNAL ;
    PORT
      LAYER M5 ;
        RECT  64.224 0 64.248 0.084 ;
    END
  END f_flit[73]
  PIN f_flit[74]
    DIRECTION OUTPUT ;
    USE SIGNAL ;
    PORT
      LAYER M5 ;
        RECT  64.368 0 64.392 0.084 ;
    END
  END f_flit[74]
  PIN f_flit[75]
    DIRECTION OUTPUT ;
    USE SIGNAL ;
    PORT
      LAYER M5 ;
        RECT  64.512 0 64.536 0.084 ;
    END
  END f_flit[75]
  PIN f_flit[76]
    DIRECTION OUTPUT ;
    USE SIGNAL ;
    PORT
      LAYER M5 ;
        RECT  64.656 0 64.68 0.084 ;
    END
  END f_flit[76]
  PIN f_flit[77]
    DIRECTION OUTPUT ;
    USE SIGNAL ;
    PORT
      LAYER M5 ;
        RECT  64.8 0 64.824 0.084 ;
    END
  END f_flit[77]
  PIN f_flit[78]
    DIRECTION OUTPUT ;
    USE SIGNAL ;
    PORT
      LAYER M5 ;
        RECT  64.944 0 64.968 0.084 ;
    END
  END f_flit[78]
  PIN f_flit[79]
    DIRECTION OUTPUT ;
    USE SIGNAL ;
    PORT
      LAYER M5 ;
        RECT  65.088 0 65.112 0.084 ;
    END
  END f_flit[79]
  PIN f_flit[7]
    DIRECTION OUTPUT ;
    USE SIGNAL ;
    PORT
      LAYER M5 ;
        RECT  68.544 0 68.568 0.084 ;
    END
  END f_flit[7]
  PIN f_flit[80]
    DIRECTION OUTPUT ;
    USE SIGNAL ;
    PORT
      LAYER M5 ;
        RECT  65.232 0 65.256 0.084 ;
    END
  END f_flit[80]
  PIN f_flit[81]
    DIRECTION OUTPUT ;
    USE SIGNAL ;
    PORT
      LAYER M5 ;
        RECT  65.376 0 65.4 0.084 ;
    END
  END f_flit[81]
  PIN f_flit[82]
    DIRECTION OUTPUT ;
    USE SIGNAL ;
    PORT
      LAYER M5 ;
        RECT  65.52 0 65.544 0.084 ;
    END
  END f_flit[82]
  PIN f_flit[83]
    DIRECTION OUTPUT ;
    USE SIGNAL ;
    PORT
      LAYER M5 ;
        RECT  65.664 0 65.688 0.084 ;
    END
  END f_flit[83]
  PIN f_flit[84]
    DIRECTION OUTPUT ;
    USE SIGNAL ;
    PORT
      LAYER M5 ;
        RECT  65.808 0 65.832 0.084 ;
    END
  END f_flit[84]
  PIN f_flit[85]
    DIRECTION OUTPUT ;
    USE SIGNAL ;
    PORT
      LAYER M5 ;
        RECT  65.952 0 65.976 0.084 ;
    END
  END f_flit[85]
  PIN f_flit[86]
    DIRECTION OUTPUT ;
    USE SIGNAL ;
    PORT
      LAYER M5 ;
        RECT  66.096 0 66.12 0.084 ;
    END
  END f_flit[86]
  PIN f_flit[87]
    DIRECTION OUTPUT ;
    USE SIGNAL ;
    PORT
      LAYER M5 ;
        RECT  66.24 0 66.264 0.084 ;
    END
  END f_flit[87]
  PIN f_flit[88]
    DIRECTION OUTPUT ;
    USE SIGNAL ;
    PORT
      LAYER M5 ;
        RECT  66.384 0 66.408 0.084 ;
    END
  END f_flit[88]
  PIN f_flit[89]
    DIRECTION OUTPUT ;
    USE SIGNAL ;
    PORT
      LAYER M5 ;
        RECT  66.528 0 66.552 0.084 ;
    END
  END f_flit[89]
  PIN f_flit[8]
    DIRECTION OUTPUT ;
    USE SIGNAL ;
    PORT
      LAYER M5 ;
        RECT  68.688 0 68.712 0.084 ;
    END
  END f_flit[8]
  PIN f_flit[90]
    DIRECTION OUTPUT ;
    USE SIGNAL ;
    PORT
      LAYER M5 ;
        RECT  66.672 0 66.696 0.084 ;
    END
  END f_flit[90]
  PIN f_flit[91]
    DIRECTION OUTPUT ;
    USE SIGNAL ;
    PORT
      LAYER M5 ;
        RECT  66.816 0 66.84 0.084 ;
    END
  END f_flit[91]
  PIN f_flit[92]
    DIRECTION OUTPUT ;
    USE SIGNAL ;
    PORT
      LAYER M5 ;
        RECT  66.96 0 66.984 0.084 ;
    END
  END f_flit[92]
  PIN f_flit[93]
    DIRECTION OUTPUT ;
    USE SIGNAL ;
    PORT
      LAYER M5 ;
        RECT  67.104 0 67.128 0.084 ;
    END
  END f_flit[93]
  PIN f_flit[94]
    DIRECTION OUTPUT ;
    USE SIGNAL ;
    PORT
      LAYER M5 ;
        RECT  67.248 0 67.272 0.084 ;
    END
  END f_flit[94]
  PIN f_flit[95]
    DIRECTION OUTPUT ;
    USE SIGNAL ;
    PORT
      LAYER M5 ;
        RECT  67.392 0 67.416 0.084 ;
    END
  END f_flit[95]
  PIN f_flit[96]
    DIRECTION OUTPUT ;
    USE SIGNAL ;
    PORT
      LAYER M5 ;
        RECT  76.752 0 76.776 0.084 ;
    END
  END f_flit[96]
  PIN f_flit[97]
    DIRECTION OUTPUT ;
    USE SIGNAL ;
    PORT
      LAYER M5 ;
        RECT  76.896 0 76.92 0.084 ;
    END
  END f_flit[97]
  PIN f_flit[98]
    DIRECTION OUTPUT ;
    USE SIGNAL ;
    PORT
      LAYER M5 ;
        RECT  77.04 0 77.064 0.084 ;
    END
  END f_flit[98]
  PIN f_flit[99]
    DIRECTION OUTPUT ;
    USE SIGNAL ;
    PORT
      LAYER M5 ;
        RECT  77.184 0 77.208 0.084 ;
    END
  END f_flit[99]
  PIN f_flit[9]
    DIRECTION OUTPUT ;
    USE SIGNAL ;
    PORT
      LAYER M5 ;
        RECT  68.832 0 68.856 0.084 ;
    END
  END f_flit[9]
  PIN f_send
    DIRECTION OUTPUT ;
    USE SIGNAL ;
    PORT
      LAYER M5 ;
        RECT  86.112 0 86.136 0.084 ;
    END
  END f_send
  PIN fault
    DIRECTION INPUT ;
    USE SIGNAL ;
    PORT
      LAYER M5 ;
        RECT  64.224 97.116 64.248 97.2 ;
    END
  END fault
  PIN irq
    DIRECTION INPUT ;
    USE SIGNAL ;
    PORT
      LAYER M5 ;
        RECT  64.368 97.116 64.392 97.2 ;
    END
  END irq
  PIN protocol_fault
    DIRECTION OUTPUT ;
    USE SIGNAL ;
    PORT
      LAYER M5 ;
        RECT  64.512 97.116 64.536 97.2 ;
    END
  END protocol_fault
  PIN rst_n
    DIRECTION INPUT ;
    USE SIGNAL ;
    PORT
      LAYER M4 ;
        RECT  0 49.392 0.084 49.416 ;
    END
  END rst_n
  PIN rx_packet[0]
    DIRECTION INPUT ;
    USE SIGNAL ;
    PORT
      LAYER M4 ;
        RECT  0 49.536 0.084 49.56 ;
    END
  END rx_packet[0]
  PIN rx_packet[100]
    DIRECTION INPUT ;
    USE SIGNAL ;
    PORT
      LAYER M4 ;
        RECT  0 40.896 0.084 40.92 ;
    END
  END rx_packet[100]
  PIN rx_packet[101]
    DIRECTION INPUT ;
    USE SIGNAL ;
    PORT
      LAYER M4 ;
        RECT  0 41.04 0.084 41.064 ;
    END
  END rx_packet[101]
  PIN rx_packet[102]
    DIRECTION INPUT ;
    USE SIGNAL ;
    PORT
      LAYER M4 ;
        RECT  0 41.184 0.084 41.208 ;
    END
  END rx_packet[102]
  PIN rx_packet[103]
    DIRECTION INPUT ;
    USE SIGNAL ;
    PORT
      LAYER M4 ;
        RECT  0 41.328 0.084 41.352 ;
    END
  END rx_packet[103]
  PIN rx_packet[104]
    DIRECTION INPUT ;
    USE SIGNAL ;
    PORT
      LAYER M4 ;
        RECT  0 41.472 0.084 41.496 ;
    END
  END rx_packet[104]
  PIN rx_packet[105]
    DIRECTION INPUT ;
    USE SIGNAL ;
    PORT
      LAYER M4 ;
        RECT  0 41.616 0.084 41.64 ;
    END
  END rx_packet[105]
  PIN rx_packet[106]
    DIRECTION INPUT ;
    USE SIGNAL ;
    PORT
      LAYER M4 ;
        RECT  0 41.76 0.084 41.784 ;
    END
  END rx_packet[106]
  PIN rx_packet[107]
    DIRECTION INPUT ;
    USE SIGNAL ;
    PORT
      LAYER M4 ;
        RECT  0 41.904 0.084 41.928 ;
    END
  END rx_packet[107]
  PIN rx_packet[108]
    DIRECTION INPUT ;
    USE SIGNAL ;
    PORT
      LAYER M4 ;
        RECT  0 42.048 0.084 42.072 ;
    END
  END rx_packet[108]
  PIN rx_packet[109]
    DIRECTION INPUT ;
    USE SIGNAL ;
    PORT
      LAYER M4 ;
        RECT  0 42.192 0.084 42.216 ;
    END
  END rx_packet[109]
  PIN rx_packet[10]
    DIRECTION INPUT ;
    USE SIGNAL ;
    PORT
      LAYER M4 ;
        RECT  0 50.976 0.084 51 ;
    END
  END rx_packet[10]
  PIN rx_packet[110]
    DIRECTION INPUT ;
    USE SIGNAL ;
    PORT
      LAYER M4 ;
        RECT  0 42.336 0.084 42.36 ;
    END
  END rx_packet[110]
  PIN rx_packet[111]
    DIRECTION INPUT ;
    USE SIGNAL ;
    PORT
      LAYER M4 ;
        RECT  0 42.48 0.084 42.504 ;
    END
  END rx_packet[111]
  PIN rx_packet[112]
    DIRECTION INPUT ;
    USE SIGNAL ;
    PORT
      LAYER M4 ;
        RECT  0 42.624 0.084 42.648 ;
    END
  END rx_packet[112]
  PIN rx_packet[113]
    DIRECTION INPUT ;
    USE SIGNAL ;
    PORT
      LAYER M4 ;
        RECT  0 42.768 0.084 42.792 ;
    END
  END rx_packet[113]
  PIN rx_packet[114]
    DIRECTION INPUT ;
    USE SIGNAL ;
    PORT
      LAYER M4 ;
        RECT  0 42.912 0.084 42.936 ;
    END
  END rx_packet[114]
  PIN rx_packet[115]
    DIRECTION INPUT ;
    USE SIGNAL ;
    PORT
      LAYER M4 ;
        RECT  0 43.056 0.084 43.08 ;
    END
  END rx_packet[115]
  PIN rx_packet[116]
    DIRECTION INPUT ;
    USE SIGNAL ;
    PORT
      LAYER M4 ;
        RECT  0 43.2 0.084 43.224 ;
    END
  END rx_packet[116]
  PIN rx_packet[117]
    DIRECTION INPUT ;
    USE SIGNAL ;
    PORT
      LAYER M4 ;
        RECT  0 43.344 0.084 43.368 ;
    END
  END rx_packet[117]
  PIN rx_packet[118]
    DIRECTION INPUT ;
    USE SIGNAL ;
    PORT
      LAYER M4 ;
        RECT  0 43.488 0.084 43.512 ;
    END
  END rx_packet[118]
  PIN rx_packet[119]
    DIRECTION INPUT ;
    USE SIGNAL ;
    PORT
      LAYER M4 ;
        RECT  0 43.632 0.084 43.656 ;
    END
  END rx_packet[119]
  PIN rx_packet[11]
    DIRECTION INPUT ;
    USE SIGNAL ;
    PORT
      LAYER M4 ;
        RECT  0 51.12 0.084 51.144 ;
    END
  END rx_packet[11]
  PIN rx_packet[120]
    DIRECTION INPUT ;
    USE SIGNAL ;
    PORT
      LAYER M4 ;
        RECT  0 43.776 0.084 43.8 ;
    END
  END rx_packet[120]
  PIN rx_packet[121]
    DIRECTION INPUT ;
    USE SIGNAL ;
    PORT
      LAYER M4 ;
        RECT  0 43.92 0.084 43.944 ;
    END
  END rx_packet[121]
  PIN rx_packet[122]
    DIRECTION INPUT ;
    USE SIGNAL ;
    PORT
      LAYER M4 ;
        RECT  0 44.064 0.084 44.088 ;
    END
  END rx_packet[122]
  PIN rx_packet[123]
    DIRECTION INPUT ;
    USE SIGNAL ;
    PORT
      LAYER M4 ;
        RECT  0 44.208 0.084 44.232 ;
    END
  END rx_packet[123]
  PIN rx_packet[124]
    DIRECTION INPUT ;
    USE SIGNAL ;
    PORT
      LAYER M4 ;
        RECT  0 44.352 0.084 44.376 ;
    END
  END rx_packet[124]
  PIN rx_packet[125]
    DIRECTION INPUT ;
    USE SIGNAL ;
    PORT
      LAYER M4 ;
        RECT  0 44.496 0.084 44.52 ;
    END
  END rx_packet[125]
  PIN rx_packet[126]
    DIRECTION INPUT ;
    USE SIGNAL ;
    PORT
      LAYER M4 ;
        RECT  0 25.056 0.084 25.08 ;
    END
  END rx_packet[126]
  PIN rx_packet[127]
    DIRECTION INPUT ;
    USE SIGNAL ;
    PORT
      LAYER M4 ;
        RECT  0 25.2 0.084 25.224 ;
    END
  END rx_packet[127]
  PIN rx_packet[128]
    DIRECTION INPUT ;
    USE SIGNAL ;
    PORT
      LAYER M4 ;
        RECT  0 25.344 0.084 25.368 ;
    END
  END rx_packet[128]
  PIN rx_packet[129]
    DIRECTION INPUT ;
    USE SIGNAL ;
    PORT
      LAYER M4 ;
        RECT  0 25.488 0.084 25.512 ;
    END
  END rx_packet[129]
  PIN rx_packet[12]
    DIRECTION INPUT ;
    USE SIGNAL ;
    PORT
      LAYER M4 ;
        RECT  0 51.264 0.084 51.288 ;
    END
  END rx_packet[12]
  PIN rx_packet[130]
    DIRECTION INPUT ;
    USE SIGNAL ;
    PORT
      LAYER M4 ;
        RECT  0 25.632 0.084 25.656 ;
    END
  END rx_packet[130]
  PIN rx_packet[131]
    DIRECTION INPUT ;
    USE SIGNAL ;
    PORT
      LAYER M4 ;
        RECT  0 25.776 0.084 25.8 ;
    END
  END rx_packet[131]
  PIN rx_packet[132]
    DIRECTION INPUT ;
    USE SIGNAL ;
    PORT
      LAYER M4 ;
        RECT  0 25.92 0.084 25.944 ;
    END
  END rx_packet[132]
  PIN rx_packet[133]
    DIRECTION INPUT ;
    USE SIGNAL ;
    PORT
      LAYER M4 ;
        RECT  0 26.064 0.084 26.088 ;
    END
  END rx_packet[133]
  PIN rx_packet[134]
    DIRECTION INPUT ;
    USE SIGNAL ;
    PORT
      LAYER M4 ;
        RECT  0 26.208 0.084 26.232 ;
    END
  END rx_packet[134]
  PIN rx_packet[135]
    DIRECTION INPUT ;
    USE SIGNAL ;
    PORT
      LAYER M4 ;
        RECT  0 26.352 0.084 26.376 ;
    END
  END rx_packet[135]
  PIN rx_packet[136]
    DIRECTION INPUT ;
    USE SIGNAL ;
    PORT
      LAYER M4 ;
        RECT  0 26.496 0.084 26.52 ;
    END
  END rx_packet[136]
  PIN rx_packet[137]
    DIRECTION INPUT ;
    USE SIGNAL ;
    PORT
      LAYER M4 ;
        RECT  0 26.64 0.084 26.664 ;
    END
  END rx_packet[137]
  PIN rx_packet[138]
    DIRECTION INPUT ;
    USE SIGNAL ;
    PORT
      LAYER M4 ;
        RECT  0 26.784 0.084 26.808 ;
    END
  END rx_packet[138]
  PIN rx_packet[139]
    DIRECTION INPUT ;
    USE SIGNAL ;
    PORT
      LAYER M4 ;
        RECT  0 26.928 0.084 26.952 ;
    END
  END rx_packet[139]
  PIN rx_packet[13]
    DIRECTION INPUT ;
    USE SIGNAL ;
    PORT
      LAYER M4 ;
        RECT  0 51.408 0.084 51.432 ;
    END
  END rx_packet[13]
  PIN rx_packet[140]
    DIRECTION INPUT ;
    USE SIGNAL ;
    PORT
      LAYER M4 ;
        RECT  0 27.072 0.084 27.096 ;
    END
  END rx_packet[140]
  PIN rx_packet[141]
    DIRECTION INPUT ;
    USE SIGNAL ;
    PORT
      LAYER M4 ;
        RECT  0 27.216 0.084 27.24 ;
    END
  END rx_packet[141]
  PIN rx_packet[142]
    DIRECTION INPUT ;
    USE SIGNAL ;
    PORT
      LAYER M4 ;
        RECT  0 27.36 0.084 27.384 ;
    END
  END rx_packet[142]
  PIN rx_packet[143]
    DIRECTION INPUT ;
    USE SIGNAL ;
    PORT
      LAYER M4 ;
        RECT  0 27.504 0.084 27.528 ;
    END
  END rx_packet[143]
  PIN rx_packet[144]
    DIRECTION INPUT ;
    USE SIGNAL ;
    PORT
      LAYER M4 ;
        RECT  0 27.648 0.084 27.672 ;
    END
  END rx_packet[144]
  PIN rx_packet[145]
    DIRECTION INPUT ;
    USE SIGNAL ;
    PORT
      LAYER M4 ;
        RECT  0 27.792 0.084 27.816 ;
    END
  END rx_packet[145]
  PIN rx_packet[146]
    DIRECTION INPUT ;
    USE SIGNAL ;
    PORT
      LAYER M4 ;
        RECT  0 27.936 0.084 27.96 ;
    END
  END rx_packet[146]
  PIN rx_packet[147]
    DIRECTION INPUT ;
    USE SIGNAL ;
    PORT
      LAYER M4 ;
        RECT  0 28.08 0.084 28.104 ;
    END
  END rx_packet[147]
  PIN rx_packet[148]
    DIRECTION INPUT ;
    USE SIGNAL ;
    PORT
      LAYER M4 ;
        RECT  0 28.224 0.084 28.248 ;
    END
  END rx_packet[148]
  PIN rx_packet[149]
    DIRECTION INPUT ;
    USE SIGNAL ;
    PORT
      LAYER M4 ;
        RECT  0 28.368 0.084 28.392 ;
    END
  END rx_packet[149]
  PIN rx_packet[14]
    DIRECTION INPUT ;
    USE SIGNAL ;
    PORT
      LAYER M4 ;
        RECT  0 51.552 0.084 51.576 ;
    END
  END rx_packet[14]
  PIN rx_packet[150]
    DIRECTION INPUT ;
    USE SIGNAL ;
    PORT
      LAYER M4 ;
        RECT  0 28.512 0.084 28.536 ;
    END
  END rx_packet[150]
  PIN rx_packet[151]
    DIRECTION INPUT ;
    USE SIGNAL ;
    PORT
      LAYER M4 ;
        RECT  0 28.656 0.084 28.68 ;
    END
  END rx_packet[151]
  PIN rx_packet[152]
    DIRECTION INPUT ;
    USE SIGNAL ;
    PORT
      LAYER M4 ;
        RECT  0 28.8 0.084 28.824 ;
    END
  END rx_packet[152]
  PIN rx_packet[153]
    DIRECTION INPUT ;
    USE SIGNAL ;
    PORT
      LAYER M4 ;
        RECT  0 28.944 0.084 28.968 ;
    END
  END rx_packet[153]
  PIN rx_packet[154]
    DIRECTION INPUT ;
    USE SIGNAL ;
    PORT
      LAYER M4 ;
        RECT  0 29.088 0.084 29.112 ;
    END
  END rx_packet[154]
  PIN rx_packet[155]
    DIRECTION INPUT ;
    USE SIGNAL ;
    PORT
      LAYER M4 ;
        RECT  0 29.232 0.084 29.256 ;
    END
  END rx_packet[155]
  PIN rx_packet[156]
    DIRECTION INPUT ;
    USE SIGNAL ;
    PORT
      LAYER M4 ;
        RECT  0 29.376 0.084 29.4 ;
    END
  END rx_packet[156]
  PIN rx_packet[157]
    DIRECTION INPUT ;
    USE SIGNAL ;
    PORT
      LAYER M4 ;
        RECT  0 29.52 0.084 29.544 ;
    END
  END rx_packet[157]
  PIN rx_packet[158]
    DIRECTION INPUT ;
    USE SIGNAL ;
    PORT
      LAYER M4 ;
        RECT  0 44.64 0.084 44.664 ;
    END
  END rx_packet[158]
  PIN rx_packet[159]
    DIRECTION INPUT ;
    USE SIGNAL ;
    PORT
      LAYER M4 ;
        RECT  0 44.784 0.084 44.808 ;
    END
  END rx_packet[159]
  PIN rx_packet[15]
    DIRECTION INPUT ;
    USE SIGNAL ;
    PORT
      LAYER M4 ;
        RECT  0 51.696 0.084 51.72 ;
    END
  END rx_packet[15]
  PIN rx_packet[160]
    DIRECTION INPUT ;
    USE SIGNAL ;
    PORT
      LAYER M4 ;
        RECT  0 44.928 0.084 44.952 ;
    END
  END rx_packet[160]
  PIN rx_packet[161]
    DIRECTION INPUT ;
    USE SIGNAL ;
    PORT
      LAYER M4 ;
        RECT  0 45.072 0.084 45.096 ;
    END
  END rx_packet[161]
  PIN rx_packet[162]
    DIRECTION INPUT ;
    USE SIGNAL ;
    PORT
      LAYER M4 ;
        RECT  0 45.216 0.084 45.24 ;
    END
  END rx_packet[162]
  PIN rx_packet[163]
    DIRECTION INPUT ;
    USE SIGNAL ;
    PORT
      LAYER M4 ;
        RECT  0 45.36 0.084 45.384 ;
    END
  END rx_packet[163]
  PIN rx_packet[164]
    DIRECTION INPUT ;
    USE SIGNAL ;
    PORT
      LAYER M4 ;
        RECT  0 45.504 0.084 45.528 ;
    END
  END rx_packet[164]
  PIN rx_packet[165]
    DIRECTION INPUT ;
    USE SIGNAL ;
    PORT
      LAYER M4 ;
        RECT  0 45.648 0.084 45.672 ;
    END
  END rx_packet[165]
  PIN rx_packet[166]
    DIRECTION INPUT ;
    USE SIGNAL ;
    PORT
      LAYER M4 ;
        RECT  0 45.792 0.084 45.816 ;
    END
  END rx_packet[166]
  PIN rx_packet[167]
    DIRECTION INPUT ;
    USE SIGNAL ;
    PORT
      LAYER M4 ;
        RECT  0 45.936 0.084 45.96 ;
    END
  END rx_packet[167]
  PIN rx_packet[168]
    DIRECTION INPUT ;
    USE SIGNAL ;
    PORT
      LAYER M4 ;
        RECT  0 46.08 0.084 46.104 ;
    END
  END rx_packet[168]
  PIN rx_packet[169]
    DIRECTION INPUT ;
    USE SIGNAL ;
    PORT
      LAYER M4 ;
        RECT  0 46.224 0.084 46.248 ;
    END
  END rx_packet[169]
  PIN rx_packet[16]
    DIRECTION INPUT ;
    USE SIGNAL ;
    PORT
      LAYER M4 ;
        RECT  0 51.84 0.084 51.864 ;
    END
  END rx_packet[16]
  PIN rx_packet[170]
    DIRECTION INPUT ;
    USE SIGNAL ;
    PORT
      LAYER M4 ;
        RECT  0 46.368 0.084 46.392 ;
    END
  END rx_packet[170]
  PIN rx_packet[171]
    DIRECTION INPUT ;
    USE SIGNAL ;
    PORT
      LAYER M4 ;
        RECT  0 46.512 0.084 46.536 ;
    END
  END rx_packet[171]
  PIN rx_packet[172]
    DIRECTION INPUT ;
    USE SIGNAL ;
    PORT
      LAYER M4 ;
        RECT  0 46.656 0.084 46.68 ;
    END
  END rx_packet[172]
  PIN rx_packet[173]
    DIRECTION INPUT ;
    USE SIGNAL ;
    PORT
      LAYER M4 ;
        RECT  0 46.8 0.084 46.824 ;
    END
  END rx_packet[173]
  PIN rx_packet[174]
    DIRECTION INPUT ;
    USE SIGNAL ;
    PORT
      LAYER M4 ;
        RECT  0 46.944 0.084 46.968 ;
    END
  END rx_packet[174]
  PIN rx_packet[175]
    DIRECTION INPUT ;
    USE SIGNAL ;
    PORT
      LAYER M4 ;
        RECT  0 47.088 0.084 47.112 ;
    END
  END rx_packet[175]
  PIN rx_packet[176]
    DIRECTION INPUT ;
    USE SIGNAL ;
    PORT
      LAYER M4 ;
        RECT  0 47.232 0.084 47.256 ;
    END
  END rx_packet[176]
  PIN rx_packet[177]
    DIRECTION INPUT ;
    USE SIGNAL ;
    PORT
      LAYER M4 ;
        RECT  0 47.376 0.084 47.4 ;
    END
  END rx_packet[177]
  PIN rx_packet[178]
    DIRECTION INPUT ;
    USE SIGNAL ;
    PORT
      LAYER M4 ;
        RECT  0 47.52 0.084 47.544 ;
    END
  END rx_packet[178]
  PIN rx_packet[179]
    DIRECTION INPUT ;
    USE SIGNAL ;
    PORT
      LAYER M4 ;
        RECT  0 47.664 0.084 47.688 ;
    END
  END rx_packet[179]
  PIN rx_packet[17]
    DIRECTION INPUT ;
    USE SIGNAL ;
    PORT
      LAYER M4 ;
        RECT  0 51.984 0.084 52.008 ;
    END
  END rx_packet[17]
  PIN rx_packet[180]
    DIRECTION INPUT ;
    USE SIGNAL ;
    PORT
      LAYER M4 ;
        RECT  0 47.808 0.084 47.832 ;
    END
  END rx_packet[180]
  PIN rx_packet[181]
    DIRECTION INPUT ;
    USE SIGNAL ;
    PORT
      LAYER M4 ;
        RECT  0 47.952 0.084 47.976 ;
    END
  END rx_packet[181]
  PIN rx_packet[182]
    DIRECTION INPUT ;
    USE SIGNAL ;
    PORT
      LAYER M4 ;
        RECT  0 48.096 0.084 48.12 ;
    END
  END rx_packet[182]
  PIN rx_packet[183]
    DIRECTION INPUT ;
    USE SIGNAL ;
    PORT
      LAYER M4 ;
        RECT  0 48.24 0.084 48.264 ;
    END
  END rx_packet[183]
  PIN rx_packet[184]
    DIRECTION INPUT ;
    USE SIGNAL ;
    PORT
      LAYER M4 ;
        RECT  0 48.384 0.084 48.408 ;
    END
  END rx_packet[184]
  PIN rx_packet[185]
    DIRECTION INPUT ;
    USE SIGNAL ;
    PORT
      LAYER M4 ;
        RECT  0 48.528 0.084 48.552 ;
    END
  END rx_packet[185]
  PIN rx_packet[186]
    DIRECTION INPUT ;
    USE SIGNAL ;
    PORT
      LAYER M4 ;
        RECT  0 48.672 0.084 48.696 ;
    END
  END rx_packet[186]
  PIN rx_packet[187]
    DIRECTION INPUT ;
    USE SIGNAL ;
    PORT
      LAYER M4 ;
        RECT  0 48.816 0.084 48.84 ;
    END
  END rx_packet[187]
  PIN rx_packet[188]
    DIRECTION INPUT ;
    USE SIGNAL ;
    PORT
      LAYER M4 ;
        RECT  0 48.96 0.084 48.984 ;
    END
  END rx_packet[188]
  PIN rx_packet[189]
    DIRECTION INPUT ;
    USE SIGNAL ;
    PORT
      LAYER M4 ;
        RECT  0 49.104 0.084 49.128 ;
    END
  END rx_packet[189]
  PIN rx_packet[18]
    DIRECTION INPUT ;
    USE SIGNAL ;
    PORT
      LAYER M4 ;
        RECT  0 52.128 0.084 52.152 ;
    END
  END rx_packet[18]
  PIN rx_packet[190]
    DIRECTION INPUT ;
    USE SIGNAL ;
    PORT
      LAYER M4 ;
        RECT  0 53.856 0.084 53.88 ;
    END
  END rx_packet[190]
  PIN rx_packet[191]
    DIRECTION INPUT ;
    USE SIGNAL ;
    PORT
      LAYER M4 ;
        RECT  0 54 0.084 54.024 ;
    END
  END rx_packet[191]
  PIN rx_packet[192]
    DIRECTION INPUT ;
    USE SIGNAL ;
    PORT
      LAYER M4 ;
        RECT  0 54.144 0.084 54.168 ;
    END
  END rx_packet[192]
  PIN rx_packet[193]
    DIRECTION INPUT ;
    USE SIGNAL ;
    PORT
      LAYER M4 ;
        RECT  0 54.288 0.084 54.312 ;
    END
  END rx_packet[193]
  PIN rx_packet[194]
    DIRECTION INPUT ;
    USE SIGNAL ;
    PORT
      LAYER M4 ;
        RECT  0 54.432 0.084 54.456 ;
    END
  END rx_packet[194]
  PIN rx_packet[195]
    DIRECTION INPUT ;
    USE SIGNAL ;
    PORT
      LAYER M4 ;
        RECT  0 54.576 0.084 54.6 ;
    END
  END rx_packet[195]
  PIN rx_packet[196]
    DIRECTION INPUT ;
    USE SIGNAL ;
    PORT
      LAYER M4 ;
        RECT  0 54.72 0.084 54.744 ;
    END
  END rx_packet[196]
  PIN rx_packet[197]
    DIRECTION INPUT ;
    USE SIGNAL ;
    PORT
      LAYER M4 ;
        RECT  0 54.864 0.084 54.888 ;
    END
  END rx_packet[197]
  PIN rx_packet[198]
    DIRECTION INPUT ;
    USE SIGNAL ;
    PORT
      LAYER M4 ;
        RECT  0 55.008 0.084 55.032 ;
    END
  END rx_packet[198]
  PIN rx_packet[199]
    DIRECTION INPUT ;
    USE SIGNAL ;
    PORT
      LAYER M4 ;
        RECT  0 55.152 0.084 55.176 ;
    END
  END rx_packet[199]
  PIN rx_packet[19]
    DIRECTION INPUT ;
    USE SIGNAL ;
    PORT
      LAYER M4 ;
        RECT  0 52.272 0.084 52.296 ;
    END
  END rx_packet[19]
  PIN rx_packet[1]
    DIRECTION INPUT ;
    USE SIGNAL ;
    PORT
      LAYER M4 ;
        RECT  0 49.68 0.084 49.704 ;
    END
  END rx_packet[1]
  PIN rx_packet[200]
    DIRECTION INPUT ;
    USE SIGNAL ;
    PORT
      LAYER M4 ;
        RECT  0 55.296 0.084 55.32 ;
    END
  END rx_packet[200]
  PIN rx_packet[201]
    DIRECTION INPUT ;
    USE SIGNAL ;
    PORT
      LAYER M4 ;
        RECT  0 55.44 0.084 55.464 ;
    END
  END rx_packet[201]
  PIN rx_packet[202]
    DIRECTION INPUT ;
    USE SIGNAL ;
    PORT
      LAYER M4 ;
        RECT  0 55.584 0.084 55.608 ;
    END
  END rx_packet[202]
  PIN rx_packet[203]
    DIRECTION INPUT ;
    USE SIGNAL ;
    PORT
      LAYER M4 ;
        RECT  0 55.728 0.084 55.752 ;
    END
  END rx_packet[203]
  PIN rx_packet[204]
    DIRECTION INPUT ;
    USE SIGNAL ;
    PORT
      LAYER M4 ;
        RECT  0 55.872 0.084 55.896 ;
    END
  END rx_packet[204]
  PIN rx_packet[205]
    DIRECTION INPUT ;
    USE SIGNAL ;
    PORT
      LAYER M4 ;
        RECT  0 56.016 0.084 56.04 ;
    END
  END rx_packet[205]
  PIN rx_packet[206]
    DIRECTION INPUT ;
    USE SIGNAL ;
    PORT
      LAYER M4 ;
        RECT  0 56.16 0.084 56.184 ;
    END
  END rx_packet[206]
  PIN rx_packet[207]
    DIRECTION INPUT ;
    USE SIGNAL ;
    PORT
      LAYER M4 ;
        RECT  0 56.304 0.084 56.328 ;
    END
  END rx_packet[207]
  PIN rx_packet[208]
    DIRECTION INPUT ;
    USE SIGNAL ;
    PORT
      LAYER M4 ;
        RECT  0 56.448 0.084 56.472 ;
    END
  END rx_packet[208]
  PIN rx_packet[209]
    DIRECTION INPUT ;
    USE SIGNAL ;
    PORT
      LAYER M4 ;
        RECT  0 56.592 0.084 56.616 ;
    END
  END rx_packet[209]
  PIN rx_packet[20]
    DIRECTION INPUT ;
    USE SIGNAL ;
    PORT
      LAYER M4 ;
        RECT  0 52.416 0.084 52.44 ;
    END
  END rx_packet[20]
  PIN rx_packet[210]
    DIRECTION INPUT ;
    USE SIGNAL ;
    PORT
      LAYER M4 ;
        RECT  0 56.736 0.084 56.76 ;
    END
  END rx_packet[210]
  PIN rx_packet[211]
    DIRECTION INPUT ;
    USE SIGNAL ;
    PORT
      LAYER M4 ;
        RECT  0 56.88 0.084 56.904 ;
    END
  END rx_packet[211]
  PIN rx_packet[212]
    DIRECTION INPUT ;
    USE SIGNAL ;
    PORT
      LAYER M4 ;
        RECT  0 57.024 0.084 57.048 ;
    END
  END rx_packet[212]
  PIN rx_packet[213]
    DIRECTION INPUT ;
    USE SIGNAL ;
    PORT
      LAYER M4 ;
        RECT  0 57.168 0.084 57.192 ;
    END
  END rx_packet[213]
  PIN rx_packet[214]
    DIRECTION INPUT ;
    USE SIGNAL ;
    PORT
      LAYER M4 ;
        RECT  0 57.312 0.084 57.336 ;
    END
  END rx_packet[214]
  PIN rx_packet[215]
    DIRECTION INPUT ;
    USE SIGNAL ;
    PORT
      LAYER M4 ;
        RECT  0 57.456 0.084 57.48 ;
    END
  END rx_packet[215]
  PIN rx_packet[216]
    DIRECTION INPUT ;
    USE SIGNAL ;
    PORT
      LAYER M4 ;
        RECT  0 57.6 0.084 57.624 ;
    END
  END rx_packet[216]
  PIN rx_packet[217]
    DIRECTION INPUT ;
    USE SIGNAL ;
    PORT
      LAYER M4 ;
        RECT  0 57.744 0.084 57.768 ;
    END
  END rx_packet[217]
  PIN rx_packet[218]
    DIRECTION INPUT ;
    USE SIGNAL ;
    PORT
      LAYER M4 ;
        RECT  0 57.888 0.084 57.912 ;
    END
  END rx_packet[218]
  PIN rx_packet[219]
    DIRECTION INPUT ;
    USE SIGNAL ;
    PORT
      LAYER M4 ;
        RECT  0 58.032 0.084 58.056 ;
    END
  END rx_packet[219]
  PIN rx_packet[21]
    DIRECTION INPUT ;
    USE SIGNAL ;
    PORT
      LAYER M4 ;
        RECT  0 52.56 0.084 52.584 ;
    END
  END rx_packet[21]
  PIN rx_packet[220]
    DIRECTION INPUT ;
    USE SIGNAL ;
    PORT
      LAYER M4 ;
        RECT  0 58.176 0.084 58.2 ;
    END
  END rx_packet[220]
  PIN rx_packet[221]
    DIRECTION INPUT ;
    USE SIGNAL ;
    PORT
      LAYER M4 ;
        RECT  0 58.32 0.084 58.344 ;
    END
  END rx_packet[221]
  PIN rx_packet[222]
    DIRECTION INPUT ;
    USE SIGNAL ;
    PORT
      LAYER M4 ;
        RECT  0 73.44 0.084 73.464 ;
    END
  END rx_packet[222]
  PIN rx_packet[223]
    DIRECTION INPUT ;
    USE SIGNAL ;
    PORT
      LAYER M4 ;
        RECT  0 73.584 0.084 73.608 ;
    END
  END rx_packet[223]
  PIN rx_packet[224]
    DIRECTION INPUT ;
    USE SIGNAL ;
    PORT
      LAYER M4 ;
        RECT  0 73.728 0.084 73.752 ;
    END
  END rx_packet[224]
  PIN rx_packet[225]
    DIRECTION INPUT ;
    USE SIGNAL ;
    PORT
      LAYER M4 ;
        RECT  0 73.872 0.084 73.896 ;
    END
  END rx_packet[225]
  PIN rx_packet[226]
    DIRECTION INPUT ;
    USE SIGNAL ;
    PORT
      LAYER M4 ;
        RECT  0 74.016 0.084 74.04 ;
    END
  END rx_packet[226]
  PIN rx_packet[227]
    DIRECTION INPUT ;
    USE SIGNAL ;
    PORT
      LAYER M4 ;
        RECT  0 74.16 0.084 74.184 ;
    END
  END rx_packet[227]
  PIN rx_packet[228]
    DIRECTION INPUT ;
    USE SIGNAL ;
    PORT
      LAYER M4 ;
        RECT  0 74.304 0.084 74.328 ;
    END
  END rx_packet[228]
  PIN rx_packet[229]
    DIRECTION INPUT ;
    USE SIGNAL ;
    PORT
      LAYER M4 ;
        RECT  0 74.448 0.084 74.472 ;
    END
  END rx_packet[229]
  PIN rx_packet[22]
    DIRECTION INPUT ;
    USE SIGNAL ;
    PORT
      LAYER M4 ;
        RECT  0 52.704 0.084 52.728 ;
    END
  END rx_packet[22]
  PIN rx_packet[230]
    DIRECTION INPUT ;
    USE SIGNAL ;
    PORT
      LAYER M4 ;
        RECT  0 74.592 0.084 74.616 ;
    END
  END rx_packet[230]
  PIN rx_packet[231]
    DIRECTION INPUT ;
    USE SIGNAL ;
    PORT
      LAYER M4 ;
        RECT  0 74.736 0.084 74.76 ;
    END
  END rx_packet[231]
  PIN rx_packet[232]
    DIRECTION INPUT ;
    USE SIGNAL ;
    PORT
      LAYER M4 ;
        RECT  0 74.88 0.084 74.904 ;
    END
  END rx_packet[232]
  PIN rx_packet[233]
    DIRECTION INPUT ;
    USE SIGNAL ;
    PORT
      LAYER M4 ;
        RECT  0 75.024 0.084 75.048 ;
    END
  END rx_packet[233]
  PIN rx_packet[234]
    DIRECTION INPUT ;
    USE SIGNAL ;
    PORT
      LAYER M4 ;
        RECT  0 75.168 0.084 75.192 ;
    END
  END rx_packet[234]
  PIN rx_packet[235]
    DIRECTION INPUT ;
    USE SIGNAL ;
    PORT
      LAYER M4 ;
        RECT  0 75.312 0.084 75.336 ;
    END
  END rx_packet[235]
  PIN rx_packet[236]
    DIRECTION INPUT ;
    USE SIGNAL ;
    PORT
      LAYER M4 ;
        RECT  0 75.456 0.084 75.48 ;
    END
  END rx_packet[236]
  PIN rx_packet[237]
    DIRECTION INPUT ;
    USE SIGNAL ;
    PORT
      LAYER M4 ;
        RECT  0 75.6 0.084 75.624 ;
    END
  END rx_packet[237]
  PIN rx_packet[238]
    DIRECTION INPUT ;
    USE SIGNAL ;
    PORT
      LAYER M4 ;
        RECT  0 75.744 0.084 75.768 ;
    END
  END rx_packet[238]
  PIN rx_packet[239]
    DIRECTION INPUT ;
    USE SIGNAL ;
    PORT
      LAYER M4 ;
        RECT  0 75.888 0.084 75.912 ;
    END
  END rx_packet[239]
  PIN rx_packet[23]
    DIRECTION INPUT ;
    USE SIGNAL ;
    PORT
      LAYER M4 ;
        RECT  0 52.848 0.084 52.872 ;
    END
  END rx_packet[23]
  PIN rx_packet[240]
    DIRECTION INPUT ;
    USE SIGNAL ;
    PORT
      LAYER M4 ;
        RECT  0 76.032 0.084 76.056 ;
    END
  END rx_packet[240]
  PIN rx_packet[241]
    DIRECTION INPUT ;
    USE SIGNAL ;
    PORT
      LAYER M4 ;
        RECT  0 76.176 0.084 76.2 ;
    END
  END rx_packet[241]
  PIN rx_packet[242]
    DIRECTION INPUT ;
    USE SIGNAL ;
    PORT
      LAYER M4 ;
        RECT  0 76.32 0.084 76.344 ;
    END
  END rx_packet[242]
  PIN rx_packet[243]
    DIRECTION INPUT ;
    USE SIGNAL ;
    PORT
      LAYER M4 ;
        RECT  0 76.464 0.084 76.488 ;
    END
  END rx_packet[243]
  PIN rx_packet[244]
    DIRECTION INPUT ;
    USE SIGNAL ;
    PORT
      LAYER M4 ;
        RECT  0 76.608 0.084 76.632 ;
    END
  END rx_packet[244]
  PIN rx_packet[245]
    DIRECTION INPUT ;
    USE SIGNAL ;
    PORT
      LAYER M4 ;
        RECT  0 76.752 0.084 76.776 ;
    END
  END rx_packet[245]
  PIN rx_packet[246]
    DIRECTION INPUT ;
    USE SIGNAL ;
    PORT
      LAYER M4 ;
        RECT  0 76.896 0.084 76.92 ;
    END
  END rx_packet[246]
  PIN rx_packet[247]
    DIRECTION INPUT ;
    USE SIGNAL ;
    PORT
      LAYER M4 ;
        RECT  0 77.04 0.084 77.064 ;
    END
  END rx_packet[247]
  PIN rx_packet[248]
    DIRECTION INPUT ;
    USE SIGNAL ;
    PORT
      LAYER M4 ;
        RECT  0 77.184 0.084 77.208 ;
    END
  END rx_packet[248]
  PIN rx_packet[249]
    DIRECTION INPUT ;
    USE SIGNAL ;
    PORT
      LAYER M4 ;
        RECT  0 77.328 0.084 77.352 ;
    END
  END rx_packet[249]
  PIN rx_packet[24]
    DIRECTION INPUT ;
    USE SIGNAL ;
    PORT
      LAYER M4 ;
        RECT  0 52.992 0.084 53.016 ;
    END
  END rx_packet[24]
  PIN rx_packet[250]
    DIRECTION INPUT ;
    USE SIGNAL ;
    PORT
      LAYER M4 ;
        RECT  0 77.472 0.084 77.496 ;
    END
  END rx_packet[250]
  PIN rx_packet[251]
    DIRECTION INPUT ;
    USE SIGNAL ;
    PORT
      LAYER M4 ;
        RECT  0 77.616 0.084 77.64 ;
    END
  END rx_packet[251]
  PIN rx_packet[252]
    DIRECTION INPUT ;
    USE SIGNAL ;
    PORT
      LAYER M4 ;
        RECT  0 77.76 0.084 77.784 ;
    END
  END rx_packet[252]
  PIN rx_packet[253]
    DIRECTION INPUT ;
    USE SIGNAL ;
    PORT
      LAYER M4 ;
        RECT  0 77.904 0.084 77.928 ;
    END
  END rx_packet[253]
  PIN rx_packet[254]
    DIRECTION INPUT ;
    USE SIGNAL ;
    PORT
      LAYER M4 ;
        RECT  0 68.832 0.084 68.856 ;
    END
  END rx_packet[254]
  PIN rx_packet[255]
    DIRECTION INPUT ;
    USE SIGNAL ;
    PORT
      LAYER M4 ;
        RECT  0 68.976 0.084 69 ;
    END
  END rx_packet[255]
  PIN rx_packet[256]
    DIRECTION INPUT ;
    USE SIGNAL ;
    PORT
      LAYER M4 ;
        RECT  0 69.12 0.084 69.144 ;
    END
  END rx_packet[256]
  PIN rx_packet[257]
    DIRECTION INPUT ;
    USE SIGNAL ;
    PORT
      LAYER M4 ;
        RECT  0 69.264 0.084 69.288 ;
    END
  END rx_packet[257]
  PIN rx_packet[258]
    DIRECTION INPUT ;
    USE SIGNAL ;
    PORT
      LAYER M4 ;
        RECT  0 69.408 0.084 69.432 ;
    END
  END rx_packet[258]
  PIN rx_packet[259]
    DIRECTION INPUT ;
    USE SIGNAL ;
    PORT
      LAYER M4 ;
        RECT  0 69.552 0.084 69.576 ;
    END
  END rx_packet[259]
  PIN rx_packet[25]
    DIRECTION INPUT ;
    USE SIGNAL ;
    PORT
      LAYER M4 ;
        RECT  0 53.136 0.084 53.16 ;
    END
  END rx_packet[25]
  PIN rx_packet[260]
    DIRECTION INPUT ;
    USE SIGNAL ;
    PORT
      LAYER M4 ;
        RECT  0 69.696 0.084 69.72 ;
    END
  END rx_packet[260]
  PIN rx_packet[261]
    DIRECTION INPUT ;
    USE SIGNAL ;
    PORT
      LAYER M4 ;
        RECT  0 69.84 0.084 69.864 ;
    END
  END rx_packet[261]
  PIN rx_packet[262]
    DIRECTION INPUT ;
    USE SIGNAL ;
    PORT
      LAYER M4 ;
        RECT  0 69.984 0.084 70.008 ;
    END
  END rx_packet[262]
  PIN rx_packet[263]
    DIRECTION INPUT ;
    USE SIGNAL ;
    PORT
      LAYER M4 ;
        RECT  0 70.128 0.084 70.152 ;
    END
  END rx_packet[263]
  PIN rx_packet[264]
    DIRECTION INPUT ;
    USE SIGNAL ;
    PORT
      LAYER M4 ;
        RECT  0 70.272 0.084 70.296 ;
    END
  END rx_packet[264]
  PIN rx_packet[265]
    DIRECTION INPUT ;
    USE SIGNAL ;
    PORT
      LAYER M4 ;
        RECT  0 70.416 0.084 70.44 ;
    END
  END rx_packet[265]
  PIN rx_packet[266]
    DIRECTION INPUT ;
    USE SIGNAL ;
    PORT
      LAYER M4 ;
        RECT  0 70.56 0.084 70.584 ;
    END
  END rx_packet[266]
  PIN rx_packet[267]
    DIRECTION INPUT ;
    USE SIGNAL ;
    PORT
      LAYER M4 ;
        RECT  0 70.704 0.084 70.728 ;
    END
  END rx_packet[267]
  PIN rx_packet[268]
    DIRECTION INPUT ;
    USE SIGNAL ;
    PORT
      LAYER M4 ;
        RECT  0 70.848 0.084 70.872 ;
    END
  END rx_packet[268]
  PIN rx_packet[269]
    DIRECTION INPUT ;
    USE SIGNAL ;
    PORT
      LAYER M4 ;
        RECT  0 70.992 0.084 71.016 ;
    END
  END rx_packet[269]
  PIN rx_packet[26]
    DIRECTION INPUT ;
    USE SIGNAL ;
    PORT
      LAYER M4 ;
        RECT  0 53.28 0.084 53.304 ;
    END
  END rx_packet[26]
  PIN rx_packet[270]
    DIRECTION INPUT ;
    USE SIGNAL ;
    PORT
      LAYER M4 ;
        RECT  0 71.136 0.084 71.16 ;
    END
  END rx_packet[270]
  PIN rx_packet[271]
    DIRECTION INPUT ;
    USE SIGNAL ;
    PORT
      LAYER M4 ;
        RECT  0 71.28 0.084 71.304 ;
    END
  END rx_packet[271]
  PIN rx_packet[272]
    DIRECTION INPUT ;
    USE SIGNAL ;
    PORT
      LAYER M4 ;
        RECT  0 71.424 0.084 71.448 ;
    END
  END rx_packet[272]
  PIN rx_packet[273]
    DIRECTION INPUT ;
    USE SIGNAL ;
    PORT
      LAYER M4 ;
        RECT  0 71.568 0.084 71.592 ;
    END
  END rx_packet[273]
  PIN rx_packet[274]
    DIRECTION INPUT ;
    USE SIGNAL ;
    PORT
      LAYER M4 ;
        RECT  0 71.712 0.084 71.736 ;
    END
  END rx_packet[274]
  PIN rx_packet[275]
    DIRECTION INPUT ;
    USE SIGNAL ;
    PORT
      LAYER M4 ;
        RECT  0 71.856 0.084 71.88 ;
    END
  END rx_packet[275]
  PIN rx_packet[276]
    DIRECTION INPUT ;
    USE SIGNAL ;
    PORT
      LAYER M4 ;
        RECT  0 72 0.084 72.024 ;
    END
  END rx_packet[276]
  PIN rx_packet[277]
    DIRECTION INPUT ;
    USE SIGNAL ;
    PORT
      LAYER M4 ;
        RECT  0 72.144 0.084 72.168 ;
    END
  END rx_packet[277]
  PIN rx_packet[278]
    DIRECTION INPUT ;
    USE SIGNAL ;
    PORT
      LAYER M4 ;
        RECT  0 72.288 0.084 72.312 ;
    END
  END rx_packet[278]
  PIN rx_packet[279]
    DIRECTION INPUT ;
    USE SIGNAL ;
    PORT
      LAYER M4 ;
        RECT  0 72.432 0.084 72.456 ;
    END
  END rx_packet[279]
  PIN rx_packet[27]
    DIRECTION INPUT ;
    USE SIGNAL ;
    PORT
      LAYER M4 ;
        RECT  0 53.424 0.084 53.448 ;
    END
  END rx_packet[27]
  PIN rx_packet[280]
    DIRECTION INPUT ;
    USE SIGNAL ;
    PORT
      LAYER M4 ;
        RECT  0 72.576 0.084 72.6 ;
    END
  END rx_packet[280]
  PIN rx_packet[281]
    DIRECTION INPUT ;
    USE SIGNAL ;
    PORT
      LAYER M4 ;
        RECT  0 72.72 0.084 72.744 ;
    END
  END rx_packet[281]
  PIN rx_packet[282]
    DIRECTION INPUT ;
    USE SIGNAL ;
    PORT
      LAYER M4 ;
        RECT  0 72.864 0.084 72.888 ;
    END
  END rx_packet[282]
  PIN rx_packet[283]
    DIRECTION INPUT ;
    USE SIGNAL ;
    PORT
      LAYER M4 ;
        RECT  0 73.008 0.084 73.032 ;
    END
  END rx_packet[283]
  PIN rx_packet[284]
    DIRECTION INPUT ;
    USE SIGNAL ;
    PORT
      LAYER M4 ;
        RECT  0 73.152 0.084 73.176 ;
    END
  END rx_packet[284]
  PIN rx_packet[285]
    DIRECTION INPUT ;
    USE SIGNAL ;
    PORT
      LAYER M4 ;
        RECT  0 73.296 0.084 73.32 ;
    END
  END rx_packet[285]
  PIN rx_packet[286]
    DIRECTION INPUT ;
    USE SIGNAL ;
    PORT
      LAYER M4 ;
        RECT  0 34.272 0.084 34.296 ;
    END
  END rx_packet[286]
  PIN rx_packet[287]
    DIRECTION INPUT ;
    USE SIGNAL ;
    PORT
      LAYER M4 ;
        RECT  0 34.416 0.084 34.44 ;
    END
  END rx_packet[287]
  PIN rx_packet[288]
    DIRECTION INPUT ;
    USE SIGNAL ;
    PORT
      LAYER M4 ;
        RECT  0 34.56 0.084 34.584 ;
    END
  END rx_packet[288]
  PIN rx_packet[289]
    DIRECTION INPUT ;
    USE SIGNAL ;
    PORT
      LAYER M4 ;
        RECT  0 34.704 0.084 34.728 ;
    END
  END rx_packet[289]
  PIN rx_packet[28]
    DIRECTION INPUT ;
    USE SIGNAL ;
    PORT
      LAYER M4 ;
        RECT  0 53.568 0.084 53.592 ;
    END
  END rx_packet[28]
  PIN rx_packet[290]
    DIRECTION INPUT ;
    USE SIGNAL ;
    PORT
      LAYER M4 ;
        RECT  0 34.848 0.084 34.872 ;
    END
  END rx_packet[290]
  PIN rx_packet[291]
    DIRECTION INPUT ;
    USE SIGNAL ;
    PORT
      LAYER M4 ;
        RECT  0 34.992 0.084 35.016 ;
    END
  END rx_packet[291]
  PIN rx_packet[292]
    DIRECTION INPUT ;
    USE SIGNAL ;
    PORT
      LAYER M4 ;
        RECT  0 35.136 0.084 35.16 ;
    END
  END rx_packet[292]
  PIN rx_packet[293]
    DIRECTION INPUT ;
    USE SIGNAL ;
    PORT
      LAYER M4 ;
        RECT  0 35.28 0.084 35.304 ;
    END
  END rx_packet[293]
  PIN rx_packet[294]
    DIRECTION INPUT ;
    USE SIGNAL ;
    PORT
      LAYER M4 ;
        RECT  0 35.424 0.084 35.448 ;
    END
  END rx_packet[294]
  PIN rx_packet[295]
    DIRECTION INPUT ;
    USE SIGNAL ;
    PORT
      LAYER M4 ;
        RECT  0 35.568 0.084 35.592 ;
    END
  END rx_packet[295]
  PIN rx_packet[296]
    DIRECTION INPUT ;
    USE SIGNAL ;
    PORT
      LAYER M4 ;
        RECT  0 35.712 0.084 35.736 ;
    END
  END rx_packet[296]
  PIN rx_packet[297]
    DIRECTION INPUT ;
    USE SIGNAL ;
    PORT
      LAYER M4 ;
        RECT  0 35.856 0.084 35.88 ;
    END
  END rx_packet[297]
  PIN rx_packet[298]
    DIRECTION INPUT ;
    USE SIGNAL ;
    PORT
      LAYER M4 ;
        RECT  0 36 0.084 36.024 ;
    END
  END rx_packet[298]
  PIN rx_packet[299]
    DIRECTION INPUT ;
    USE SIGNAL ;
    PORT
      LAYER M4 ;
        RECT  0 36.144 0.084 36.168 ;
    END
  END rx_packet[299]
  PIN rx_packet[29]
    DIRECTION INPUT ;
    USE SIGNAL ;
    PORT
      LAYER M4 ;
        RECT  0 53.712 0.084 53.736 ;
    END
  END rx_packet[29]
  PIN rx_packet[2]
    DIRECTION INPUT ;
    USE SIGNAL ;
    PORT
      LAYER M4 ;
        RECT  0 49.824 0.084 49.848 ;
    END
  END rx_packet[2]
  PIN rx_packet[300]
    DIRECTION INPUT ;
    USE SIGNAL ;
    PORT
      LAYER M4 ;
        RECT  0 36.288 0.084 36.312 ;
    END
  END rx_packet[300]
  PIN rx_packet[301]
    DIRECTION INPUT ;
    USE SIGNAL ;
    PORT
      LAYER M4 ;
        RECT  0 36.432 0.084 36.456 ;
    END
  END rx_packet[301]
  PIN rx_packet[302]
    DIRECTION INPUT ;
    USE SIGNAL ;
    PORT
      LAYER M4 ;
        RECT  0 36.576 0.084 36.6 ;
    END
  END rx_packet[302]
  PIN rx_packet[303]
    DIRECTION INPUT ;
    USE SIGNAL ;
    PORT
      LAYER M4 ;
        RECT  0 36.72 0.084 36.744 ;
    END
  END rx_packet[303]
  PIN rx_packet[304]
    DIRECTION INPUT ;
    USE SIGNAL ;
    PORT
      LAYER M4 ;
        RECT  0 36.864 0.084 36.888 ;
    END
  END rx_packet[304]
  PIN rx_packet[305]
    DIRECTION INPUT ;
    USE SIGNAL ;
    PORT
      LAYER M4 ;
        RECT  0 37.008 0.084 37.032 ;
    END
  END rx_packet[305]
  PIN rx_packet[306]
    DIRECTION INPUT ;
    USE SIGNAL ;
    PORT
      LAYER M4 ;
        RECT  0 37.152 0.084 37.176 ;
    END
  END rx_packet[306]
  PIN rx_packet[307]
    DIRECTION INPUT ;
    USE SIGNAL ;
    PORT
      LAYER M4 ;
        RECT  0 37.296 0.084 37.32 ;
    END
  END rx_packet[307]
  PIN rx_packet[308]
    DIRECTION INPUT ;
    USE SIGNAL ;
    PORT
      LAYER M4 ;
        RECT  0 37.44 0.084 37.464 ;
    END
  END rx_packet[308]
  PIN rx_packet[309]
    DIRECTION INPUT ;
    USE SIGNAL ;
    PORT
      LAYER M4 ;
        RECT  0 37.584 0.084 37.608 ;
    END
  END rx_packet[309]
  PIN rx_packet[30]
    DIRECTION INPUT ;
    USE SIGNAL ;
    PORT
      LAYER M4 ;
        RECT  0 58.464 0.084 58.488 ;
    END
  END rx_packet[30]
  PIN rx_packet[310]
    DIRECTION INPUT ;
    USE SIGNAL ;
    PORT
      LAYER M4 ;
        RECT  0 37.728 0.084 37.752 ;
    END
  END rx_packet[310]
  PIN rx_packet[311]
    DIRECTION INPUT ;
    USE SIGNAL ;
    PORT
      LAYER M4 ;
        RECT  0 37.872 0.084 37.896 ;
    END
  END rx_packet[311]
  PIN rx_packet[312]
    DIRECTION INPUT ;
    USE SIGNAL ;
    PORT
      LAYER M4 ;
        RECT  0 38.016 0.084 38.04 ;
    END
  END rx_packet[312]
  PIN rx_packet[313]
    DIRECTION INPUT ;
    USE SIGNAL ;
    PORT
      LAYER M4 ;
        RECT  0 38.16 0.084 38.184 ;
    END
  END rx_packet[313]
  PIN rx_packet[314]
    DIRECTION INPUT ;
    USE SIGNAL ;
    PORT
      LAYER M4 ;
        RECT  0 38.304 0.084 38.328 ;
    END
  END rx_packet[314]
  PIN rx_packet[315]
    DIRECTION INPUT ;
    USE SIGNAL ;
    PORT
      LAYER M4 ;
        RECT  0 38.448 0.084 38.472 ;
    END
  END rx_packet[315]
  PIN rx_packet[316]
    DIRECTION INPUT ;
    USE SIGNAL ;
    PORT
      LAYER M4 ;
        RECT  0 38.592 0.084 38.616 ;
    END
  END rx_packet[316]
  PIN rx_packet[317]
    DIRECTION INPUT ;
    USE SIGNAL ;
    PORT
      LAYER M4 ;
        RECT  0 38.736 0.084 38.76 ;
    END
  END rx_packet[317]
  PIN rx_packet[318]
    DIRECTION INPUT ;
    USE SIGNAL ;
    PORT
      LAYER M4 ;
        RECT  0 29.664 0.084 29.688 ;
    END
  END rx_packet[318]
  PIN rx_packet[319]
    DIRECTION INPUT ;
    USE SIGNAL ;
    PORT
      LAYER M4 ;
        RECT  0 29.808 0.084 29.832 ;
    END
  END rx_packet[319]
  PIN rx_packet[31]
    DIRECTION INPUT ;
    USE SIGNAL ;
    PORT
      LAYER M4 ;
        RECT  0 58.608 0.084 58.632 ;
    END
  END rx_packet[31]
  PIN rx_packet[320]
    DIRECTION INPUT ;
    USE SIGNAL ;
    PORT
      LAYER M4 ;
        RECT  0 29.952 0.084 29.976 ;
    END
  END rx_packet[320]
  PIN rx_packet[321]
    DIRECTION INPUT ;
    USE SIGNAL ;
    PORT
      LAYER M4 ;
        RECT  0 30.096 0.084 30.12 ;
    END
  END rx_packet[321]
  PIN rx_packet[322]
    DIRECTION INPUT ;
    USE SIGNAL ;
    PORT
      LAYER M4 ;
        RECT  0 30.24 0.084 30.264 ;
    END
  END rx_packet[322]
  PIN rx_packet[323]
    DIRECTION INPUT ;
    USE SIGNAL ;
    PORT
      LAYER M4 ;
        RECT  0 30.384 0.084 30.408 ;
    END
  END rx_packet[323]
  PIN rx_packet[324]
    DIRECTION INPUT ;
    USE SIGNAL ;
    PORT
      LAYER M4 ;
        RECT  0 30.528 0.084 30.552 ;
    END
  END rx_packet[324]
  PIN rx_packet[325]
    DIRECTION INPUT ;
    USE SIGNAL ;
    PORT
      LAYER M4 ;
        RECT  0 30.672 0.084 30.696 ;
    END
  END rx_packet[325]
  PIN rx_packet[326]
    DIRECTION INPUT ;
    USE SIGNAL ;
    PORT
      LAYER M4 ;
        RECT  0 30.816 0.084 30.84 ;
    END
  END rx_packet[326]
  PIN rx_packet[327]
    DIRECTION INPUT ;
    USE SIGNAL ;
    PORT
      LAYER M4 ;
        RECT  0 30.96 0.084 30.984 ;
    END
  END rx_packet[327]
  PIN rx_packet[328]
    DIRECTION INPUT ;
    USE SIGNAL ;
    PORT
      LAYER M4 ;
        RECT  0 31.104 0.084 31.128 ;
    END
  END rx_packet[328]
  PIN rx_packet[329]
    DIRECTION INPUT ;
    USE SIGNAL ;
    PORT
      LAYER M4 ;
        RECT  0 31.248 0.084 31.272 ;
    END
  END rx_packet[329]
  PIN rx_packet[32]
    DIRECTION INPUT ;
    USE SIGNAL ;
    PORT
      LAYER M4 ;
        RECT  0 58.752 0.084 58.776 ;
    END
  END rx_packet[32]
  PIN rx_packet[330]
    DIRECTION INPUT ;
    USE SIGNAL ;
    PORT
      LAYER M4 ;
        RECT  0 31.392 0.084 31.416 ;
    END
  END rx_packet[330]
  PIN rx_packet[331]
    DIRECTION INPUT ;
    USE SIGNAL ;
    PORT
      LAYER M4 ;
        RECT  0 31.536 0.084 31.56 ;
    END
  END rx_packet[331]
  PIN rx_packet[332]
    DIRECTION INPUT ;
    USE SIGNAL ;
    PORT
      LAYER M4 ;
        RECT  0 31.68 0.084 31.704 ;
    END
  END rx_packet[332]
  PIN rx_packet[333]
    DIRECTION INPUT ;
    USE SIGNAL ;
    PORT
      LAYER M4 ;
        RECT  0 31.824 0.084 31.848 ;
    END
  END rx_packet[333]
  PIN rx_packet[334]
    DIRECTION INPUT ;
    USE SIGNAL ;
    PORT
      LAYER M4 ;
        RECT  0 31.968 0.084 31.992 ;
    END
  END rx_packet[334]
  PIN rx_packet[335]
    DIRECTION INPUT ;
    USE SIGNAL ;
    PORT
      LAYER M4 ;
        RECT  0 32.112 0.084 32.136 ;
    END
  END rx_packet[335]
  PIN rx_packet[336]
    DIRECTION INPUT ;
    USE SIGNAL ;
    PORT
      LAYER M4 ;
        RECT  0 32.256 0.084 32.28 ;
    END
  END rx_packet[336]
  PIN rx_packet[337]
    DIRECTION INPUT ;
    USE SIGNAL ;
    PORT
      LAYER M4 ;
        RECT  0 32.4 0.084 32.424 ;
    END
  END rx_packet[337]
  PIN rx_packet[338]
    DIRECTION INPUT ;
    USE SIGNAL ;
    PORT
      LAYER M4 ;
        RECT  0 32.544 0.084 32.568 ;
    END
  END rx_packet[338]
  PIN rx_packet[339]
    DIRECTION INPUT ;
    USE SIGNAL ;
    PORT
      LAYER M4 ;
        RECT  0 32.688 0.084 32.712 ;
    END
  END rx_packet[339]
  PIN rx_packet[33]
    DIRECTION INPUT ;
    USE SIGNAL ;
    PORT
      LAYER M4 ;
        RECT  0 58.896 0.084 58.92 ;
    END
  END rx_packet[33]
  PIN rx_packet[340]
    DIRECTION INPUT ;
    USE SIGNAL ;
    PORT
      LAYER M4 ;
        RECT  0 32.832 0.084 32.856 ;
    END
  END rx_packet[340]
  PIN rx_packet[341]
    DIRECTION INPUT ;
    USE SIGNAL ;
    PORT
      LAYER M4 ;
        RECT  0 32.976 0.084 33 ;
    END
  END rx_packet[341]
  PIN rx_packet[342]
    DIRECTION INPUT ;
    USE SIGNAL ;
    PORT
      LAYER M4 ;
        RECT  0 33.12 0.084 33.144 ;
    END
  END rx_packet[342]
  PIN rx_packet[343]
    DIRECTION INPUT ;
    USE SIGNAL ;
    PORT
      LAYER M4 ;
        RECT  0 33.264 0.084 33.288 ;
    END
  END rx_packet[343]
  PIN rx_packet[344]
    DIRECTION INPUT ;
    USE SIGNAL ;
    PORT
      LAYER M4 ;
        RECT  0 33.408 0.084 33.432 ;
    END
  END rx_packet[344]
  PIN rx_packet[345]
    DIRECTION INPUT ;
    USE SIGNAL ;
    PORT
      LAYER M4 ;
        RECT  0 33.552 0.084 33.576 ;
    END
  END rx_packet[345]
  PIN rx_packet[346]
    DIRECTION INPUT ;
    USE SIGNAL ;
    PORT
      LAYER M4 ;
        RECT  0 33.696 0.084 33.72 ;
    END
  END rx_packet[346]
  PIN rx_packet[347]
    DIRECTION INPUT ;
    USE SIGNAL ;
    PORT
      LAYER M4 ;
        RECT  0 33.84 0.084 33.864 ;
    END
  END rx_packet[347]
  PIN rx_packet[348]
    DIRECTION INPUT ;
    USE SIGNAL ;
    PORT
      LAYER M4 ;
        RECT  0 33.984 0.084 34.008 ;
    END
  END rx_packet[348]
  PIN rx_packet[349]
    DIRECTION INPUT ;
    USE SIGNAL ;
    PORT
      LAYER M4 ;
        RECT  0 34.128 0.084 34.152 ;
    END
  END rx_packet[349]
  PIN rx_packet[34]
    DIRECTION INPUT ;
    USE SIGNAL ;
    PORT
      LAYER M4 ;
        RECT  0 59.04 0.084 59.064 ;
    END
  END rx_packet[34]
  PIN rx_packet[350]
    DIRECTION INPUT ;
    USE SIGNAL ;
    PORT
      LAYER M4 ;
        RECT  0 11.232 0.084 11.256 ;
    END
  END rx_packet[350]
  PIN rx_packet[351]
    DIRECTION INPUT ;
    USE SIGNAL ;
    PORT
      LAYER M4 ;
        RECT  0 11.376 0.084 11.4 ;
    END
  END rx_packet[351]
  PIN rx_packet[352]
    DIRECTION INPUT ;
    USE SIGNAL ;
    PORT
      LAYER M4 ;
        RECT  0 11.52 0.084 11.544 ;
    END
  END rx_packet[352]
  PIN rx_packet[353]
    DIRECTION INPUT ;
    USE SIGNAL ;
    PORT
      LAYER M4 ;
        RECT  0 11.664 0.084 11.688 ;
    END
  END rx_packet[353]
  PIN rx_packet[354]
    DIRECTION INPUT ;
    USE SIGNAL ;
    PORT
      LAYER M4 ;
        RECT  0 11.808 0.084 11.832 ;
    END
  END rx_packet[354]
  PIN rx_packet[355]
    DIRECTION INPUT ;
    USE SIGNAL ;
    PORT
      LAYER M4 ;
        RECT  0 11.952 0.084 11.976 ;
    END
  END rx_packet[355]
  PIN rx_packet[356]
    DIRECTION INPUT ;
    USE SIGNAL ;
    PORT
      LAYER M4 ;
        RECT  0 12.096 0.084 12.12 ;
    END
  END rx_packet[356]
  PIN rx_packet[357]
    DIRECTION INPUT ;
    USE SIGNAL ;
    PORT
      LAYER M4 ;
        RECT  0 12.24 0.084 12.264 ;
    END
  END rx_packet[357]
  PIN rx_packet[358]
    DIRECTION INPUT ;
    USE SIGNAL ;
    PORT
      LAYER M4 ;
        RECT  0 12.384 0.084 12.408 ;
    END
  END rx_packet[358]
  PIN rx_packet[359]
    DIRECTION INPUT ;
    USE SIGNAL ;
    PORT
      LAYER M4 ;
        RECT  0 12.528 0.084 12.552 ;
    END
  END rx_packet[359]
  PIN rx_packet[35]
    DIRECTION INPUT ;
    USE SIGNAL ;
    PORT
      LAYER M4 ;
        RECT  0 59.184 0.084 59.208 ;
    END
  END rx_packet[35]
  PIN rx_packet[360]
    DIRECTION INPUT ;
    USE SIGNAL ;
    PORT
      LAYER M4 ;
        RECT  0 12.672 0.084 12.696 ;
    END
  END rx_packet[360]
  PIN rx_packet[361]
    DIRECTION INPUT ;
    USE SIGNAL ;
    PORT
      LAYER M4 ;
        RECT  0 12.816 0.084 12.84 ;
    END
  END rx_packet[361]
  PIN rx_packet[362]
    DIRECTION INPUT ;
    USE SIGNAL ;
    PORT
      LAYER M4 ;
        RECT  0 12.96 0.084 12.984 ;
    END
  END rx_packet[362]
  PIN rx_packet[363]
    DIRECTION INPUT ;
    USE SIGNAL ;
    PORT
      LAYER M4 ;
        RECT  0 13.104 0.084 13.128 ;
    END
  END rx_packet[363]
  PIN rx_packet[364]
    DIRECTION INPUT ;
    USE SIGNAL ;
    PORT
      LAYER M4 ;
        RECT  0 13.248 0.084 13.272 ;
    END
  END rx_packet[364]
  PIN rx_packet[365]
    DIRECTION INPUT ;
    USE SIGNAL ;
    PORT
      LAYER M4 ;
        RECT  0 13.392 0.084 13.416 ;
    END
  END rx_packet[365]
  PIN rx_packet[366]
    DIRECTION INPUT ;
    USE SIGNAL ;
    PORT
      LAYER M4 ;
        RECT  0 13.536 0.084 13.56 ;
    END
  END rx_packet[366]
  PIN rx_packet[367]
    DIRECTION INPUT ;
    USE SIGNAL ;
    PORT
      LAYER M4 ;
        RECT  0 13.68 0.084 13.704 ;
    END
  END rx_packet[367]
  PIN rx_packet[368]
    DIRECTION INPUT ;
    USE SIGNAL ;
    PORT
      LAYER M4 ;
        RECT  0 13.824 0.084 13.848 ;
    END
  END rx_packet[368]
  PIN rx_packet[369]
    DIRECTION INPUT ;
    USE SIGNAL ;
    PORT
      LAYER M4 ;
        RECT  0 13.968 0.084 13.992 ;
    END
  END rx_packet[369]
  PIN rx_packet[36]
    DIRECTION INPUT ;
    USE SIGNAL ;
    PORT
      LAYER M4 ;
        RECT  0 59.328 0.084 59.352 ;
    END
  END rx_packet[36]
  PIN rx_packet[370]
    DIRECTION INPUT ;
    USE SIGNAL ;
    PORT
      LAYER M4 ;
        RECT  0 14.112 0.084 14.136 ;
    END
  END rx_packet[370]
  PIN rx_packet[371]
    DIRECTION INPUT ;
    USE SIGNAL ;
    PORT
      LAYER M4 ;
        RECT  0 14.256 0.084 14.28 ;
    END
  END rx_packet[371]
  PIN rx_packet[372]
    DIRECTION INPUT ;
    USE SIGNAL ;
    PORT
      LAYER M4 ;
        RECT  0 14.4 0.084 14.424 ;
    END
  END rx_packet[372]
  PIN rx_packet[373]
    DIRECTION INPUT ;
    USE SIGNAL ;
    PORT
      LAYER M4 ;
        RECT  0 14.544 0.084 14.568 ;
    END
  END rx_packet[373]
  PIN rx_packet[374]
    DIRECTION INPUT ;
    USE SIGNAL ;
    PORT
      LAYER M4 ;
        RECT  0 14.688 0.084 14.712 ;
    END
  END rx_packet[374]
  PIN rx_packet[375]
    DIRECTION INPUT ;
    USE SIGNAL ;
    PORT
      LAYER M4 ;
        RECT  0 14.832 0.084 14.856 ;
    END
  END rx_packet[375]
  PIN rx_packet[376]
    DIRECTION INPUT ;
    USE SIGNAL ;
    PORT
      LAYER M4 ;
        RECT  0 14.976 0.084 15 ;
    END
  END rx_packet[376]
  PIN rx_packet[377]
    DIRECTION INPUT ;
    USE SIGNAL ;
    PORT
      LAYER M4 ;
        RECT  0 15.12 0.084 15.144 ;
    END
  END rx_packet[377]
  PIN rx_packet[378]
    DIRECTION INPUT ;
    USE SIGNAL ;
    PORT
      LAYER M4 ;
        RECT  0 15.264 0.084 15.288 ;
    END
  END rx_packet[378]
  PIN rx_packet[379]
    DIRECTION INPUT ;
    USE SIGNAL ;
    PORT
      LAYER M4 ;
        RECT  0 15.408 0.084 15.432 ;
    END
  END rx_packet[379]
  PIN rx_packet[37]
    DIRECTION INPUT ;
    USE SIGNAL ;
    PORT
      LAYER M4 ;
        RECT  0 59.472 0.084 59.496 ;
    END
  END rx_packet[37]
  PIN rx_packet[380]
    DIRECTION INPUT ;
    USE SIGNAL ;
    PORT
      LAYER M4 ;
        RECT  0 15.552 0.084 15.576 ;
    END
  END rx_packet[380]
  PIN rx_packet[381]
    DIRECTION INPUT ;
    USE SIGNAL ;
    PORT
      LAYER M4 ;
        RECT  0 15.696 0.084 15.72 ;
    END
  END rx_packet[381]
  PIN rx_packet[382]
    DIRECTION INPUT ;
    USE SIGNAL ;
    PORT
      LAYER M4 ;
        RECT  0 20.448 0.084 20.472 ;
    END
  END rx_packet[382]
  PIN rx_packet[383]
    DIRECTION INPUT ;
    USE SIGNAL ;
    PORT
      LAYER M4 ;
        RECT  0 20.592 0.084 20.616 ;
    END
  END rx_packet[383]
  PIN rx_packet[384]
    DIRECTION INPUT ;
    USE SIGNAL ;
    PORT
      LAYER M4 ;
        RECT  0 20.736 0.084 20.76 ;
    END
  END rx_packet[384]
  PIN rx_packet[385]
    DIRECTION INPUT ;
    USE SIGNAL ;
    PORT
      LAYER M4 ;
        RECT  0 20.88 0.084 20.904 ;
    END
  END rx_packet[385]
  PIN rx_packet[386]
    DIRECTION INPUT ;
    USE SIGNAL ;
    PORT
      LAYER M4 ;
        RECT  0 21.024 0.084 21.048 ;
    END
  END rx_packet[386]
  PIN rx_packet[387]
    DIRECTION INPUT ;
    USE SIGNAL ;
    PORT
      LAYER M4 ;
        RECT  0 21.168 0.084 21.192 ;
    END
  END rx_packet[387]
  PIN rx_packet[388]
    DIRECTION INPUT ;
    USE SIGNAL ;
    PORT
      LAYER M4 ;
        RECT  0 21.312 0.084 21.336 ;
    END
  END rx_packet[388]
  PIN rx_packet[389]
    DIRECTION INPUT ;
    USE SIGNAL ;
    PORT
      LAYER M4 ;
        RECT  0 21.456 0.084 21.48 ;
    END
  END rx_packet[389]
  PIN rx_packet[38]
    DIRECTION INPUT ;
    USE SIGNAL ;
    PORT
      LAYER M4 ;
        RECT  0 59.616 0.084 59.64 ;
    END
  END rx_packet[38]
  PIN rx_packet[390]
    DIRECTION INPUT ;
    USE SIGNAL ;
    PORT
      LAYER M4 ;
        RECT  0 21.6 0.084 21.624 ;
    END
  END rx_packet[390]
  PIN rx_packet[391]
    DIRECTION INPUT ;
    USE SIGNAL ;
    PORT
      LAYER M4 ;
        RECT  0 21.744 0.084 21.768 ;
    END
  END rx_packet[391]
  PIN rx_packet[392]
    DIRECTION INPUT ;
    USE SIGNAL ;
    PORT
      LAYER M4 ;
        RECT  0 21.888 0.084 21.912 ;
    END
  END rx_packet[392]
  PIN rx_packet[393]
    DIRECTION INPUT ;
    USE SIGNAL ;
    PORT
      LAYER M4 ;
        RECT  0 22.032 0.084 22.056 ;
    END
  END rx_packet[393]
  PIN rx_packet[394]
    DIRECTION INPUT ;
    USE SIGNAL ;
    PORT
      LAYER M4 ;
        RECT  0 22.176 0.084 22.2 ;
    END
  END rx_packet[394]
  PIN rx_packet[395]
    DIRECTION INPUT ;
    USE SIGNAL ;
    PORT
      LAYER M4 ;
        RECT  0 22.32 0.084 22.344 ;
    END
  END rx_packet[395]
  PIN rx_packet[396]
    DIRECTION INPUT ;
    USE SIGNAL ;
    PORT
      LAYER M4 ;
        RECT  0 22.464 0.084 22.488 ;
    END
  END rx_packet[396]
  PIN rx_packet[397]
    DIRECTION INPUT ;
    USE SIGNAL ;
    PORT
      LAYER M4 ;
        RECT  0 22.608 0.084 22.632 ;
    END
  END rx_packet[397]
  PIN rx_packet[398]
    DIRECTION INPUT ;
    USE SIGNAL ;
    PORT
      LAYER M4 ;
        RECT  0 22.752 0.084 22.776 ;
    END
  END rx_packet[398]
  PIN rx_packet[399]
    DIRECTION INPUT ;
    USE SIGNAL ;
    PORT
      LAYER M4 ;
        RECT  0 22.896 0.084 22.92 ;
    END
  END rx_packet[399]
  PIN rx_packet[39]
    DIRECTION INPUT ;
    USE SIGNAL ;
    PORT
      LAYER M4 ;
        RECT  0 59.76 0.084 59.784 ;
    END
  END rx_packet[39]
  PIN rx_packet[3]
    DIRECTION INPUT ;
    USE SIGNAL ;
    PORT
      LAYER M4 ;
        RECT  0 49.968 0.084 49.992 ;
    END
  END rx_packet[3]
  PIN rx_packet[400]
    DIRECTION INPUT ;
    USE SIGNAL ;
    PORT
      LAYER M4 ;
        RECT  0 23.04 0.084 23.064 ;
    END
  END rx_packet[400]
  PIN rx_packet[401]
    DIRECTION INPUT ;
    USE SIGNAL ;
    PORT
      LAYER M4 ;
        RECT  0 23.184 0.084 23.208 ;
    END
  END rx_packet[401]
  PIN rx_packet[402]
    DIRECTION INPUT ;
    USE SIGNAL ;
    PORT
      LAYER M4 ;
        RECT  0 23.328 0.084 23.352 ;
    END
  END rx_packet[402]
  PIN rx_packet[403]
    DIRECTION INPUT ;
    USE SIGNAL ;
    PORT
      LAYER M4 ;
        RECT  0 23.472 0.084 23.496 ;
    END
  END rx_packet[403]
  PIN rx_packet[404]
    DIRECTION INPUT ;
    USE SIGNAL ;
    PORT
      LAYER M4 ;
        RECT  0 23.616 0.084 23.64 ;
    END
  END rx_packet[404]
  PIN rx_packet[405]
    DIRECTION INPUT ;
    USE SIGNAL ;
    PORT
      LAYER M4 ;
        RECT  0 23.76 0.084 23.784 ;
    END
  END rx_packet[405]
  PIN rx_packet[406]
    DIRECTION INPUT ;
    USE SIGNAL ;
    PORT
      LAYER M4 ;
        RECT  0 23.904 0.084 23.928 ;
    END
  END rx_packet[406]
  PIN rx_packet[407]
    DIRECTION INPUT ;
    USE SIGNAL ;
    PORT
      LAYER M4 ;
        RECT  0 24.048 0.084 24.072 ;
    END
  END rx_packet[407]
  PIN rx_packet[408]
    DIRECTION INPUT ;
    USE SIGNAL ;
    PORT
      LAYER M4 ;
        RECT  0 24.192 0.084 24.216 ;
    END
  END rx_packet[408]
  PIN rx_packet[409]
    DIRECTION INPUT ;
    USE SIGNAL ;
    PORT
      LAYER M4 ;
        RECT  0 24.336 0.084 24.36 ;
    END
  END rx_packet[409]
  PIN rx_packet[40]
    DIRECTION INPUT ;
    USE SIGNAL ;
    PORT
      LAYER M4 ;
        RECT  0 59.904 0.084 59.928 ;
    END
  END rx_packet[40]
  PIN rx_packet[410]
    DIRECTION INPUT ;
    USE SIGNAL ;
    PORT
      LAYER M4 ;
        RECT  0 24.48 0.084 24.504 ;
    END
  END rx_packet[410]
  PIN rx_packet[411]
    DIRECTION INPUT ;
    USE SIGNAL ;
    PORT
      LAYER M4 ;
        RECT  0 24.624 0.084 24.648 ;
    END
  END rx_packet[411]
  PIN rx_packet[412]
    DIRECTION INPUT ;
    USE SIGNAL ;
    PORT
      LAYER M4 ;
        RECT  0 24.768 0.084 24.792 ;
    END
  END rx_packet[412]
  PIN rx_packet[413]
    DIRECTION INPUT ;
    USE SIGNAL ;
    PORT
      LAYER M4 ;
        RECT  0 24.912 0.084 24.936 ;
    END
  END rx_packet[413]
  PIN rx_packet[414]
    DIRECTION INPUT ;
    USE SIGNAL ;
    PORT
      LAYER M4 ;
        RECT  0 15.84 0.084 15.864 ;
    END
  END rx_packet[414]
  PIN rx_packet[415]
    DIRECTION INPUT ;
    USE SIGNAL ;
    PORT
      LAYER M4 ;
        RECT  0 15.984 0.084 16.008 ;
    END
  END rx_packet[415]
  PIN rx_packet[416]
    DIRECTION INPUT ;
    USE SIGNAL ;
    PORT
      LAYER M4 ;
        RECT  0 16.128 0.084 16.152 ;
    END
  END rx_packet[416]
  PIN rx_packet[417]
    DIRECTION INPUT ;
    USE SIGNAL ;
    PORT
      LAYER M4 ;
        RECT  0 16.272 0.084 16.296 ;
    END
  END rx_packet[417]
  PIN rx_packet[418]
    DIRECTION INPUT ;
    USE SIGNAL ;
    PORT
      LAYER M4 ;
        RECT  0 16.416 0.084 16.44 ;
    END
  END rx_packet[418]
  PIN rx_packet[419]
    DIRECTION INPUT ;
    USE SIGNAL ;
    PORT
      LAYER M4 ;
        RECT  0 16.56 0.084 16.584 ;
    END
  END rx_packet[419]
  PIN rx_packet[41]
    DIRECTION INPUT ;
    USE SIGNAL ;
    PORT
      LAYER M4 ;
        RECT  0 60.048 0.084 60.072 ;
    END
  END rx_packet[41]
  PIN rx_packet[420]
    DIRECTION INPUT ;
    USE SIGNAL ;
    PORT
      LAYER M4 ;
        RECT  0 16.704 0.084 16.728 ;
    END
  END rx_packet[420]
  PIN rx_packet[421]
    DIRECTION INPUT ;
    USE SIGNAL ;
    PORT
      LAYER M4 ;
        RECT  0 16.848 0.084 16.872 ;
    END
  END rx_packet[421]
  PIN rx_packet[422]
    DIRECTION INPUT ;
    USE SIGNAL ;
    PORT
      LAYER M4 ;
        RECT  0 16.992 0.084 17.016 ;
    END
  END rx_packet[422]
  PIN rx_packet[423]
    DIRECTION INPUT ;
    USE SIGNAL ;
    PORT
      LAYER M4 ;
        RECT  0 17.136 0.084 17.16 ;
    END
  END rx_packet[423]
  PIN rx_packet[424]
    DIRECTION INPUT ;
    USE SIGNAL ;
    PORT
      LAYER M4 ;
        RECT  0 17.28 0.084 17.304 ;
    END
  END rx_packet[424]
  PIN rx_packet[425]
    DIRECTION INPUT ;
    USE SIGNAL ;
    PORT
      LAYER M4 ;
        RECT  0 17.424 0.084 17.448 ;
    END
  END rx_packet[425]
  PIN rx_packet[426]
    DIRECTION INPUT ;
    USE SIGNAL ;
    PORT
      LAYER M4 ;
        RECT  0 17.568 0.084 17.592 ;
    END
  END rx_packet[426]
  PIN rx_packet[427]
    DIRECTION INPUT ;
    USE SIGNAL ;
    PORT
      LAYER M4 ;
        RECT  0 17.712 0.084 17.736 ;
    END
  END rx_packet[427]
  PIN rx_packet[428]
    DIRECTION INPUT ;
    USE SIGNAL ;
    PORT
      LAYER M4 ;
        RECT  0 17.856 0.084 17.88 ;
    END
  END rx_packet[428]
  PIN rx_packet[429]
    DIRECTION INPUT ;
    USE SIGNAL ;
    PORT
      LAYER M4 ;
        RECT  0 18 0.084 18.024 ;
    END
  END rx_packet[429]
  PIN rx_packet[42]
    DIRECTION INPUT ;
    USE SIGNAL ;
    PORT
      LAYER M4 ;
        RECT  0 60.192 0.084 60.216 ;
    END
  END rx_packet[42]
  PIN rx_packet[430]
    DIRECTION INPUT ;
    USE SIGNAL ;
    PORT
      LAYER M4 ;
        RECT  0 18.144 0.084 18.168 ;
    END
  END rx_packet[430]
  PIN rx_packet[431]
    DIRECTION INPUT ;
    USE SIGNAL ;
    PORT
      LAYER M4 ;
        RECT  0 18.288 0.084 18.312 ;
    END
  END rx_packet[431]
  PIN rx_packet[432]
    DIRECTION INPUT ;
    USE SIGNAL ;
    PORT
      LAYER M4 ;
        RECT  0 18.432 0.084 18.456 ;
    END
  END rx_packet[432]
  PIN rx_packet[433]
    DIRECTION INPUT ;
    USE SIGNAL ;
    PORT
      LAYER M4 ;
        RECT  0 18.576 0.084 18.6 ;
    END
  END rx_packet[433]
  PIN rx_packet[434]
    DIRECTION INPUT ;
    USE SIGNAL ;
    PORT
      LAYER M4 ;
        RECT  0 18.72 0.084 18.744 ;
    END
  END rx_packet[434]
  PIN rx_packet[435]
    DIRECTION INPUT ;
    USE SIGNAL ;
    PORT
      LAYER M4 ;
        RECT  0 18.864 0.084 18.888 ;
    END
  END rx_packet[435]
  PIN rx_packet[436]
    DIRECTION INPUT ;
    USE SIGNAL ;
    PORT
      LAYER M4 ;
        RECT  0 19.008 0.084 19.032 ;
    END
  END rx_packet[436]
  PIN rx_packet[437]
    DIRECTION INPUT ;
    USE SIGNAL ;
    PORT
      LAYER M4 ;
        RECT  0 19.152 0.084 19.176 ;
    END
  END rx_packet[437]
  PIN rx_packet[438]
    DIRECTION INPUT ;
    USE SIGNAL ;
    PORT
      LAYER M4 ;
        RECT  0 19.296 0.084 19.32 ;
    END
  END rx_packet[438]
  PIN rx_packet[439]
    DIRECTION INPUT ;
    USE SIGNAL ;
    PORT
      LAYER M4 ;
        RECT  0 19.44 0.084 19.464 ;
    END
  END rx_packet[439]
  PIN rx_packet[43]
    DIRECTION INPUT ;
    USE SIGNAL ;
    PORT
      LAYER M4 ;
        RECT  0 60.336 0.084 60.36 ;
    END
  END rx_packet[43]
  PIN rx_packet[440]
    DIRECTION INPUT ;
    USE SIGNAL ;
    PORT
      LAYER M4 ;
        RECT  0 19.584 0.084 19.608 ;
    END
  END rx_packet[440]
  PIN rx_packet[441]
    DIRECTION INPUT ;
    USE SIGNAL ;
    PORT
      LAYER M4 ;
        RECT  0 19.728 0.084 19.752 ;
    END
  END rx_packet[441]
  PIN rx_packet[442]
    DIRECTION INPUT ;
    USE SIGNAL ;
    PORT
      LAYER M4 ;
        RECT  0 19.872 0.084 19.896 ;
    END
  END rx_packet[442]
  PIN rx_packet[443]
    DIRECTION INPUT ;
    USE SIGNAL ;
    PORT
      LAYER M4 ;
        RECT  0 20.016 0.084 20.04 ;
    END
  END rx_packet[443]
  PIN rx_packet[444]
    DIRECTION INPUT ;
    USE SIGNAL ;
    PORT
      LAYER M4 ;
        RECT  0 20.16 0.084 20.184 ;
    END
  END rx_packet[444]
  PIN rx_packet[445]
    DIRECTION INPUT ;
    USE SIGNAL ;
    PORT
      LAYER M4 ;
        RECT  0 20.304 0.084 20.328 ;
    END
  END rx_packet[445]
  PIN rx_packet[446]
    DIRECTION INPUT ;
    USE SIGNAL ;
    PORT
      LAYER M4 ;
        RECT  0 0.864 0.084 0.888 ;
    END
  END rx_packet[446]
  PIN rx_packet[447]
    DIRECTION INPUT ;
    USE SIGNAL ;
    PORT
      LAYER M4 ;
        RECT  0 1.008 0.084 1.032 ;
    END
  END rx_packet[447]
  PIN rx_packet[448]
    DIRECTION INPUT ;
    USE SIGNAL ;
    PORT
      LAYER M4 ;
        RECT  0 1.152 0.084 1.176 ;
    END
  END rx_packet[448]
  PIN rx_packet[449]
    DIRECTION INPUT ;
    USE SIGNAL ;
    PORT
      LAYER M4 ;
        RECT  0 1.296 0.084 1.32 ;
    END
  END rx_packet[449]
  PIN rx_packet[44]
    DIRECTION INPUT ;
    USE SIGNAL ;
    PORT
      LAYER M4 ;
        RECT  0 60.48 0.084 60.504 ;
    END
  END rx_packet[44]
  PIN rx_packet[450]
    DIRECTION INPUT ;
    USE SIGNAL ;
    PORT
      LAYER M4 ;
        RECT  0 1.44 0.084 1.464 ;
    END
  END rx_packet[450]
  PIN rx_packet[451]
    DIRECTION INPUT ;
    USE SIGNAL ;
    PORT
      LAYER M4 ;
        RECT  0 1.584 0.084 1.608 ;
    END
  END rx_packet[451]
  PIN rx_packet[452]
    DIRECTION INPUT ;
    USE SIGNAL ;
    PORT
      LAYER M4 ;
        RECT  0 1.728 0.084 1.752 ;
    END
  END rx_packet[452]
  PIN rx_packet[453]
    DIRECTION INPUT ;
    USE SIGNAL ;
    PORT
      LAYER M4 ;
        RECT  0 1.872 0.084 1.896 ;
    END
  END rx_packet[453]
  PIN rx_packet[454]
    DIRECTION INPUT ;
    USE SIGNAL ;
    PORT
      LAYER M4 ;
        RECT  0 2.016 0.084 2.04 ;
    END
  END rx_packet[454]
  PIN rx_packet[455]
    DIRECTION INPUT ;
    USE SIGNAL ;
    PORT
      LAYER M4 ;
        RECT  0 2.16 0.084 2.184 ;
    END
  END rx_packet[455]
  PIN rx_packet[456]
    DIRECTION INPUT ;
    USE SIGNAL ;
    PORT
      LAYER M4 ;
        RECT  0 2.304 0.084 2.328 ;
    END
  END rx_packet[456]
  PIN rx_packet[457]
    DIRECTION INPUT ;
    USE SIGNAL ;
    PORT
      LAYER M4 ;
        RECT  0 2.448 0.084 2.472 ;
    END
  END rx_packet[457]
  PIN rx_packet[458]
    DIRECTION INPUT ;
    USE SIGNAL ;
    PORT
      LAYER M4 ;
        RECT  0 2.592 0.084 2.616 ;
    END
  END rx_packet[458]
  PIN rx_packet[459]
    DIRECTION INPUT ;
    USE SIGNAL ;
    PORT
      LAYER M4 ;
        RECT  0 2.736 0.084 2.76 ;
    END
  END rx_packet[459]
  PIN rx_packet[45]
    DIRECTION INPUT ;
    USE SIGNAL ;
    PORT
      LAYER M4 ;
        RECT  0 60.624 0.084 60.648 ;
    END
  END rx_packet[45]
  PIN rx_packet[460]
    DIRECTION INPUT ;
    USE SIGNAL ;
    PORT
      LAYER M4 ;
        RECT  0 2.88 0.084 2.904 ;
    END
  END rx_packet[460]
  PIN rx_packet[461]
    DIRECTION INPUT ;
    USE SIGNAL ;
    PORT
      LAYER M4 ;
        RECT  0 3.024 0.084 3.048 ;
    END
  END rx_packet[461]
  PIN rx_packet[462]
    DIRECTION INPUT ;
    USE SIGNAL ;
    PORT
      LAYER M4 ;
        RECT  0 3.168 0.084 3.192 ;
    END
  END rx_packet[462]
  PIN rx_packet[463]
    DIRECTION INPUT ;
    USE SIGNAL ;
    PORT
      LAYER M4 ;
        RECT  0 3.312 0.084 3.336 ;
    END
  END rx_packet[463]
  PIN rx_packet[464]
    DIRECTION INPUT ;
    USE SIGNAL ;
    PORT
      LAYER M4 ;
        RECT  0 3.456 0.084 3.48 ;
    END
  END rx_packet[464]
  PIN rx_packet[465]
    DIRECTION INPUT ;
    USE SIGNAL ;
    PORT
      LAYER M4 ;
        RECT  0 3.6 0.084 3.624 ;
    END
  END rx_packet[465]
  PIN rx_packet[466]
    DIRECTION INPUT ;
    USE SIGNAL ;
    PORT
      LAYER M4 ;
        RECT  0 3.744 0.084 3.768 ;
    END
  END rx_packet[466]
  PIN rx_packet[467]
    DIRECTION INPUT ;
    USE SIGNAL ;
    PORT
      LAYER M4 ;
        RECT  0 3.888 0.084 3.912 ;
    END
  END rx_packet[467]
  PIN rx_packet[468]
    DIRECTION INPUT ;
    USE SIGNAL ;
    PORT
      LAYER M4 ;
        RECT  0 4.032 0.084 4.056 ;
    END
  END rx_packet[468]
  PIN rx_packet[469]
    DIRECTION INPUT ;
    USE SIGNAL ;
    PORT
      LAYER M4 ;
        RECT  0 4.176 0.084 4.2 ;
    END
  END rx_packet[469]
  PIN rx_packet[46]
    DIRECTION INPUT ;
    USE SIGNAL ;
    PORT
      LAYER M4 ;
        RECT  0 60.768 0.084 60.792 ;
    END
  END rx_packet[46]
  PIN rx_packet[470]
    DIRECTION INPUT ;
    USE SIGNAL ;
    PORT
      LAYER M4 ;
        RECT  0 4.32 0.084 4.344 ;
    END
  END rx_packet[470]
  PIN rx_packet[471]
    DIRECTION INPUT ;
    USE SIGNAL ;
    PORT
      LAYER M4 ;
        RECT  0 4.464 0.084 4.488 ;
    END
  END rx_packet[471]
  PIN rx_packet[472]
    DIRECTION INPUT ;
    USE SIGNAL ;
    PORT
      LAYER M4 ;
        RECT  0 4.608 0.084 4.632 ;
    END
  END rx_packet[472]
  PIN rx_packet[473]
    DIRECTION INPUT ;
    USE SIGNAL ;
    PORT
      LAYER M4 ;
        RECT  0 4.752 0.084 4.776 ;
    END
  END rx_packet[473]
  PIN rx_packet[474]
    DIRECTION INPUT ;
    USE SIGNAL ;
    PORT
      LAYER M4 ;
        RECT  0 4.896 0.084 4.92 ;
    END
  END rx_packet[474]
  PIN rx_packet[475]
    DIRECTION INPUT ;
    USE SIGNAL ;
    PORT
      LAYER M4 ;
        RECT  0 5.04 0.084 5.064 ;
    END
  END rx_packet[475]
  PIN rx_packet[476]
    DIRECTION INPUT ;
    USE SIGNAL ;
    PORT
      LAYER M4 ;
        RECT  0 5.184 0.084 5.208 ;
    END
  END rx_packet[476]
  PIN rx_packet[477]
    DIRECTION INPUT ;
    USE SIGNAL ;
    PORT
      LAYER M4 ;
        RECT  0 5.328 0.084 5.352 ;
    END
  END rx_packet[477]
  PIN rx_packet[478]
    DIRECTION INPUT ;
    USE SIGNAL ;
    PORT
      LAYER M4 ;
        RECT  0 5.472 0.084 5.496 ;
    END
  END rx_packet[478]
  PIN rx_packet[479]
    DIRECTION INPUT ;
    USE SIGNAL ;
    PORT
      LAYER M4 ;
        RECT  0 5.616 0.084 5.64 ;
    END
  END rx_packet[479]
  PIN rx_packet[47]
    DIRECTION INPUT ;
    USE SIGNAL ;
    PORT
      LAYER M4 ;
        RECT  0 60.912 0.084 60.936 ;
    END
  END rx_packet[47]
  PIN rx_packet[480]
    DIRECTION INPUT ;
    USE SIGNAL ;
    PORT
      LAYER M4 ;
        RECT  0 5.76 0.084 5.784 ;
    END
  END rx_packet[480]
  PIN rx_packet[481]
    DIRECTION INPUT ;
    USE SIGNAL ;
    PORT
      LAYER M4 ;
        RECT  0 5.904 0.084 5.928 ;
    END
  END rx_packet[481]
  PIN rx_packet[482]
    DIRECTION INPUT ;
    USE SIGNAL ;
    PORT
      LAYER M4 ;
        RECT  0 6.048 0.084 6.072 ;
    END
  END rx_packet[482]
  PIN rx_packet[483]
    DIRECTION INPUT ;
    USE SIGNAL ;
    PORT
      LAYER M4 ;
        RECT  0 6.192 0.084 6.216 ;
    END
  END rx_packet[483]
  PIN rx_packet[484]
    DIRECTION INPUT ;
    USE SIGNAL ;
    PORT
      LAYER M4 ;
        RECT  0 6.336 0.084 6.36 ;
    END
  END rx_packet[484]
  PIN rx_packet[485]
    DIRECTION INPUT ;
    USE SIGNAL ;
    PORT
      LAYER M4 ;
        RECT  0 6.48 0.084 6.504 ;
    END
  END rx_packet[485]
  PIN rx_packet[486]
    DIRECTION INPUT ;
    USE SIGNAL ;
    PORT
      LAYER M4 ;
        RECT  0 6.624 0.084 6.648 ;
    END
  END rx_packet[486]
  PIN rx_packet[487]
    DIRECTION INPUT ;
    USE SIGNAL ;
    PORT
      LAYER M4 ;
        RECT  0 6.768 0.084 6.792 ;
    END
  END rx_packet[487]
  PIN rx_packet[488]
    DIRECTION INPUT ;
    USE SIGNAL ;
    PORT
      LAYER M4 ;
        RECT  0 6.912 0.084 6.936 ;
    END
  END rx_packet[488]
  PIN rx_packet[489]
    DIRECTION INPUT ;
    USE SIGNAL ;
    PORT
      LAYER M4 ;
        RECT  0 7.056 0.084 7.08 ;
    END
  END rx_packet[489]
  PIN rx_packet[48]
    DIRECTION INPUT ;
    USE SIGNAL ;
    PORT
      LAYER M4 ;
        RECT  0 61.056 0.084 61.08 ;
    END
  END rx_packet[48]
  PIN rx_packet[490]
    DIRECTION INPUT ;
    USE SIGNAL ;
    PORT
      LAYER M4 ;
        RECT  0 7.2 0.084 7.224 ;
    END
  END rx_packet[490]
  PIN rx_packet[491]
    DIRECTION INPUT ;
    USE SIGNAL ;
    PORT
      LAYER M4 ;
        RECT  0 7.344 0.084 7.368 ;
    END
  END rx_packet[491]
  PIN rx_packet[492]
    DIRECTION INPUT ;
    USE SIGNAL ;
    PORT
      LAYER M4 ;
        RECT  0 7.488 0.084 7.512 ;
    END
  END rx_packet[492]
  PIN rx_packet[493]
    DIRECTION INPUT ;
    USE SIGNAL ;
    PORT
      LAYER M4 ;
        RECT  0 7.632 0.084 7.656 ;
    END
  END rx_packet[493]
  PIN rx_packet[494]
    DIRECTION INPUT ;
    USE SIGNAL ;
    PORT
      LAYER M4 ;
        RECT  0 7.776 0.084 7.8 ;
    END
  END rx_packet[494]
  PIN rx_packet[495]
    DIRECTION INPUT ;
    USE SIGNAL ;
    PORT
      LAYER M4 ;
        RECT  0 7.92 0.084 7.944 ;
    END
  END rx_packet[495]
  PIN rx_packet[496]
    DIRECTION INPUT ;
    USE SIGNAL ;
    PORT
      LAYER M4 ;
        RECT  0 8.064 0.084 8.088 ;
    END
  END rx_packet[496]
  PIN rx_packet[497]
    DIRECTION INPUT ;
    USE SIGNAL ;
    PORT
      LAYER M4 ;
        RECT  0 8.208 0.084 8.232 ;
    END
  END rx_packet[497]
  PIN rx_packet[498]
    DIRECTION INPUT ;
    USE SIGNAL ;
    PORT
      LAYER M4 ;
        RECT  0 8.352 0.084 8.376 ;
    END
  END rx_packet[498]
  PIN rx_packet[499]
    DIRECTION INPUT ;
    USE SIGNAL ;
    PORT
      LAYER M4 ;
        RECT  0 8.496 0.084 8.52 ;
    END
  END rx_packet[499]
  PIN rx_packet[49]
    DIRECTION INPUT ;
    USE SIGNAL ;
    PORT
      LAYER M4 ;
        RECT  0 61.2 0.084 61.224 ;
    END
  END rx_packet[49]
  PIN rx_packet[4]
    DIRECTION INPUT ;
    USE SIGNAL ;
    PORT
      LAYER M4 ;
        RECT  0 50.112 0.084 50.136 ;
    END
  END rx_packet[4]
  PIN rx_packet[500]
    DIRECTION INPUT ;
    USE SIGNAL ;
    PORT
      LAYER M4 ;
        RECT  0 8.64 0.084 8.664 ;
    END
  END rx_packet[500]
  PIN rx_packet[501]
    DIRECTION INPUT ;
    USE SIGNAL ;
    PORT
      LAYER M4 ;
        RECT  0 8.784 0.084 8.808 ;
    END
  END rx_packet[501]
  PIN rx_packet[502]
    DIRECTION INPUT ;
    USE SIGNAL ;
    PORT
      LAYER M4 ;
        RECT  0 8.928 0.084 8.952 ;
    END
  END rx_packet[502]
  PIN rx_packet[503]
    DIRECTION INPUT ;
    USE SIGNAL ;
    PORT
      LAYER M4 ;
        RECT  0 9.072 0.084 9.096 ;
    END
  END rx_packet[503]
  PIN rx_packet[504]
    DIRECTION INPUT ;
    USE SIGNAL ;
    PORT
      LAYER M4 ;
        RECT  0 9.216 0.084 9.24 ;
    END
  END rx_packet[504]
  PIN rx_packet[505]
    DIRECTION INPUT ;
    USE SIGNAL ;
    PORT
      LAYER M4 ;
        RECT  0 9.36 0.084 9.384 ;
    END
  END rx_packet[505]
  PIN rx_packet[506]
    DIRECTION INPUT ;
    USE SIGNAL ;
    PORT
      LAYER M4 ;
        RECT  0 9.504 0.084 9.528 ;
    END
  END rx_packet[506]
  PIN rx_packet[507]
    DIRECTION INPUT ;
    USE SIGNAL ;
    PORT
      LAYER M4 ;
        RECT  0 9.648 0.084 9.672 ;
    END
  END rx_packet[507]
  PIN rx_packet[508]
    DIRECTION INPUT ;
    USE SIGNAL ;
    PORT
      LAYER M4 ;
        RECT  0 9.792 0.084 9.816 ;
    END
  END rx_packet[508]
  PIN rx_packet[509]
    DIRECTION INPUT ;
    USE SIGNAL ;
    PORT
      LAYER M4 ;
        RECT  0 9.936 0.084 9.96 ;
    END
  END rx_packet[509]
  PIN rx_packet[50]
    DIRECTION INPUT ;
    USE SIGNAL ;
    PORT
      LAYER M4 ;
        RECT  0 61.344 0.084 61.368 ;
    END
  END rx_packet[50]
  PIN rx_packet[510]
    DIRECTION INPUT ;
    USE SIGNAL ;
    PORT
      LAYER M4 ;
        RECT  0 39.456 0.084 39.48 ;
    END
  END rx_packet[510]
  PIN rx_packet[511]
    DIRECTION INPUT ;
    USE SIGNAL ;
    PORT
      LAYER M4 ;
        RECT  0 39.6 0.084 39.624 ;
    END
  END rx_packet[511]
  PIN rx_packet[51]
    DIRECTION INPUT ;
    USE SIGNAL ;
    PORT
      LAYER M4 ;
        RECT  0 61.488 0.084 61.512 ;
    END
  END rx_packet[51]
  PIN rx_packet[52]
    DIRECTION INPUT ;
    USE SIGNAL ;
    PORT
      LAYER M4 ;
        RECT  0 61.632 0.084 61.656 ;
    END
  END rx_packet[52]
  PIN rx_packet[53]
    DIRECTION INPUT ;
    USE SIGNAL ;
    PORT
      LAYER M4 ;
        RECT  0 61.776 0.084 61.8 ;
    END
  END rx_packet[53]
  PIN rx_packet[54]
    DIRECTION INPUT ;
    USE SIGNAL ;
    PORT
      LAYER M4 ;
        RECT  0 61.92 0.084 61.944 ;
    END
  END rx_packet[54]
  PIN rx_packet[55]
    DIRECTION INPUT ;
    USE SIGNAL ;
    PORT
      LAYER M4 ;
        RECT  0 62.064 0.084 62.088 ;
    END
  END rx_packet[55]
  PIN rx_packet[56]
    DIRECTION INPUT ;
    USE SIGNAL ;
    PORT
      LAYER M4 ;
        RECT  0 62.208 0.084 62.232 ;
    END
  END rx_packet[56]
  PIN rx_packet[57]
    DIRECTION INPUT ;
    USE SIGNAL ;
    PORT
      LAYER M4 ;
        RECT  0 62.352 0.084 62.376 ;
    END
  END rx_packet[57]
  PIN rx_packet[58]
    DIRECTION INPUT ;
    USE SIGNAL ;
    PORT
      LAYER M4 ;
        RECT  0 62.496 0.084 62.52 ;
    END
  END rx_packet[58]
  PIN rx_packet[59]
    DIRECTION INPUT ;
    USE SIGNAL ;
    PORT
      LAYER M4 ;
        RECT  0 62.64 0.084 62.664 ;
    END
  END rx_packet[59]
  PIN rx_packet[5]
    DIRECTION INPUT ;
    USE SIGNAL ;
    PORT
      LAYER M4 ;
        RECT  0 50.256 0.084 50.28 ;
    END
  END rx_packet[5]
  PIN rx_packet[60]
    DIRECTION INPUT ;
    USE SIGNAL ;
    PORT
      LAYER M4 ;
        RECT  0 62.784 0.084 62.808 ;
    END
  END rx_packet[60]
  PIN rx_packet[61]
    DIRECTION INPUT ;
    USE SIGNAL ;
    PORT
      LAYER M4 ;
        RECT  0 62.928 0.084 62.952 ;
    END
  END rx_packet[61]
  PIN rx_packet[62]
    DIRECTION INPUT ;
    USE SIGNAL ;
    PORT
      LAYER M4 ;
        RECT  0 63.072 0.084 63.096 ;
    END
  END rx_packet[62]
  PIN rx_packet[63]
    DIRECTION INPUT ;
    USE SIGNAL ;
    PORT
      LAYER M4 ;
        RECT  0 63.216 0.084 63.24 ;
    END
  END rx_packet[63]
  PIN rx_packet[64]
    DIRECTION INPUT ;
    USE SIGNAL ;
    PORT
      LAYER M4 ;
        RECT  0 63.36 0.084 63.384 ;
    END
  END rx_packet[64]
  PIN rx_packet[65]
    DIRECTION INPUT ;
    USE SIGNAL ;
    PORT
      LAYER M4 ;
        RECT  0 63.504 0.084 63.528 ;
    END
  END rx_packet[65]
  PIN rx_packet[66]
    DIRECTION INPUT ;
    USE SIGNAL ;
    PORT
      LAYER M4 ;
        RECT  0 63.648 0.084 63.672 ;
    END
  END rx_packet[66]
  PIN rx_packet[67]
    DIRECTION INPUT ;
    USE SIGNAL ;
    PORT
      LAYER M4 ;
        RECT  0 63.792 0.084 63.816 ;
    END
  END rx_packet[67]
  PIN rx_packet[68]
    DIRECTION INPUT ;
    USE SIGNAL ;
    PORT
      LAYER M4 ;
        RECT  0 63.936 0.084 63.96 ;
    END
  END rx_packet[68]
  PIN rx_packet[69]
    DIRECTION INPUT ;
    USE SIGNAL ;
    PORT
      LAYER M4 ;
        RECT  0 64.08 0.084 64.104 ;
    END
  END rx_packet[69]
  PIN rx_packet[6]
    DIRECTION INPUT ;
    USE SIGNAL ;
    PORT
      LAYER M4 ;
        RECT  0 50.4 0.084 50.424 ;
    END
  END rx_packet[6]
  PIN rx_packet[70]
    DIRECTION INPUT ;
    USE SIGNAL ;
    PORT
      LAYER M4 ;
        RECT  0 64.224 0.084 64.248 ;
    END
  END rx_packet[70]
  PIN rx_packet[71]
    DIRECTION INPUT ;
    USE SIGNAL ;
    PORT
      LAYER M4 ;
        RECT  0 64.368 0.084 64.392 ;
    END
  END rx_packet[71]
  PIN rx_packet[72]
    DIRECTION INPUT ;
    USE SIGNAL ;
    PORT
      LAYER M4 ;
        RECT  0 64.512 0.084 64.536 ;
    END
  END rx_packet[72]
  PIN rx_packet[73]
    DIRECTION INPUT ;
    USE SIGNAL ;
    PORT
      LAYER M4 ;
        RECT  0 64.656 0.084 64.68 ;
    END
  END rx_packet[73]
  PIN rx_packet[74]
    DIRECTION INPUT ;
    USE SIGNAL ;
    PORT
      LAYER M4 ;
        RECT  0 64.8 0.084 64.824 ;
    END
  END rx_packet[74]
  PIN rx_packet[75]
    DIRECTION INPUT ;
    USE SIGNAL ;
    PORT
      LAYER M4 ;
        RECT  0 64.944 0.084 64.968 ;
    END
  END rx_packet[75]
  PIN rx_packet[76]
    DIRECTION INPUT ;
    USE SIGNAL ;
    PORT
      LAYER M4 ;
        RECT  0 65.088 0.084 65.112 ;
    END
  END rx_packet[76]
  PIN rx_packet[77]
    DIRECTION INPUT ;
    USE SIGNAL ;
    PORT
      LAYER M4 ;
        RECT  0 65.232 0.084 65.256 ;
    END
  END rx_packet[77]
  PIN rx_packet[78]
    DIRECTION INPUT ;
    USE SIGNAL ;
    PORT
      LAYER M4 ;
        RECT  0 65.376 0.084 65.4 ;
    END
  END rx_packet[78]
  PIN rx_packet[79]
    DIRECTION INPUT ;
    USE SIGNAL ;
    PORT
      LAYER M4 ;
        RECT  0 65.52 0.084 65.544 ;
    END
  END rx_packet[79]
  PIN rx_packet[7]
    DIRECTION INPUT ;
    USE SIGNAL ;
    PORT
      LAYER M4 ;
        RECT  0 50.544 0.084 50.568 ;
    END
  END rx_packet[7]
  PIN rx_packet[80]
    DIRECTION INPUT ;
    USE SIGNAL ;
    PORT
      LAYER M4 ;
        RECT  0 65.664 0.084 65.688 ;
    END
  END rx_packet[80]
  PIN rx_packet[81]
    DIRECTION INPUT ;
    USE SIGNAL ;
    PORT
      LAYER M4 ;
        RECT  0 65.808 0.084 65.832 ;
    END
  END rx_packet[81]
  PIN rx_packet[82]
    DIRECTION INPUT ;
    USE SIGNAL ;
    PORT
      LAYER M4 ;
        RECT  0 65.952 0.084 65.976 ;
    END
  END rx_packet[82]
  PIN rx_packet[83]
    DIRECTION INPUT ;
    USE SIGNAL ;
    PORT
      LAYER M4 ;
        RECT  0 66.096 0.084 66.12 ;
    END
  END rx_packet[83]
  PIN rx_packet[84]
    DIRECTION INPUT ;
    USE SIGNAL ;
    PORT
      LAYER M4 ;
        RECT  0 66.24 0.084 66.264 ;
    END
  END rx_packet[84]
  PIN rx_packet[85]
    DIRECTION INPUT ;
    USE SIGNAL ;
    PORT
      LAYER M4 ;
        RECT  0 66.384 0.084 66.408 ;
    END
  END rx_packet[85]
  PIN rx_packet[86]
    DIRECTION INPUT ;
    USE SIGNAL ;
    PORT
      LAYER M4 ;
        RECT  0 66.528 0.084 66.552 ;
    END
  END rx_packet[86]
  PIN rx_packet[87]
    DIRECTION INPUT ;
    USE SIGNAL ;
    PORT
      LAYER M4 ;
        RECT  0 66.672 0.084 66.696 ;
    END
  END rx_packet[87]
  PIN rx_packet[88]
    DIRECTION INPUT ;
    USE SIGNAL ;
    PORT
      LAYER M4 ;
        RECT  0 66.816 0.084 66.84 ;
    END
  END rx_packet[88]
  PIN rx_packet[89]
    DIRECTION INPUT ;
    USE SIGNAL ;
    PORT
      LAYER M4 ;
        RECT  0 66.96 0.084 66.984 ;
    END
  END rx_packet[89]
  PIN rx_packet[8]
    DIRECTION INPUT ;
    USE SIGNAL ;
    PORT
      LAYER M4 ;
        RECT  0 50.688 0.084 50.712 ;
    END
  END rx_packet[8]
  PIN rx_packet[90]
    DIRECTION INPUT ;
    USE SIGNAL ;
    PORT
      LAYER M4 ;
        RECT  0 67.104 0.084 67.128 ;
    END
  END rx_packet[90]
  PIN rx_packet[91]
    DIRECTION INPUT ;
    USE SIGNAL ;
    PORT
      LAYER M4 ;
        RECT  0 67.248 0.084 67.272 ;
    END
  END rx_packet[91]
  PIN rx_packet[92]
    DIRECTION INPUT ;
    USE SIGNAL ;
    PORT
      LAYER M4 ;
        RECT  0 67.392 0.084 67.416 ;
    END
  END rx_packet[92]
  PIN rx_packet[93]
    DIRECTION INPUT ;
    USE SIGNAL ;
    PORT
      LAYER M4 ;
        RECT  0 67.536 0.084 67.56 ;
    END
  END rx_packet[93]
  PIN rx_packet[94]
    DIRECTION INPUT ;
    USE SIGNAL ;
    PORT
      LAYER M4 ;
        RECT  0 40.032 0.084 40.056 ;
    END
  END rx_packet[94]
  PIN rx_packet[95]
    DIRECTION INPUT ;
    USE SIGNAL ;
    PORT
      LAYER M4 ;
        RECT  0 40.176 0.084 40.2 ;
    END
  END rx_packet[95]
  PIN rx_packet[96]
    DIRECTION INPUT ;
    USE SIGNAL ;
    PORT
      LAYER M4 ;
        RECT  0 40.32 0.084 40.344 ;
    END
  END rx_packet[96]
  PIN rx_packet[97]
    DIRECTION INPUT ;
    USE SIGNAL ;
    PORT
      LAYER M4 ;
        RECT  0 40.464 0.084 40.488 ;
    END
  END rx_packet[97]
  PIN rx_packet[98]
    DIRECTION INPUT ;
    USE SIGNAL ;
    PORT
      LAYER M4 ;
        RECT  0 40.608 0.084 40.632 ;
    END
  END rx_packet[98]
  PIN rx_packet[99]
    DIRECTION INPUT ;
    USE SIGNAL ;
    PORT
      LAYER M4 ;
        RECT  0 40.752 0.084 40.776 ;
    END
  END rx_packet[99]
  PIN rx_packet[9]
    DIRECTION INPUT ;
    USE SIGNAL ;
    PORT
      LAYER M4 ;
        RECT  0 50.832 0.084 50.856 ;
    END
  END rx_packet[9]
  PIN rx_ready
    DIRECTION OUTPUT ;
    USE SIGNAL ;
    PORT
      LAYER M4 ;
        RECT  0 39.744 0.084 39.768 ;
    END
  END rx_ready
  PIN rx_valid
    DIRECTION INPUT ;
    USE SIGNAL ;
    PORT
      LAYER M4 ;
        RECT  0 39.888 0.084 39.912 ;
    END
  END rx_valid
  PIN s_araddr[0]
    DIRECTION OUTPUT ;
    USE SIGNAL ;
    PORT
      LAYER M4 ;
        RECT  97.116 52.56 97.2 52.584 ;
    END
  END s_araddr[0]
  PIN s_araddr[10]
    DIRECTION OUTPUT ;
    USE SIGNAL ;
    PORT
      LAYER M4 ;
        RECT  97.116 54 97.2 54.024 ;
    END
  END s_araddr[10]
  PIN s_araddr[11]
    DIRECTION OUTPUT ;
    USE SIGNAL ;
    PORT
      LAYER M4 ;
        RECT  97.116 54.144 97.2 54.168 ;
    END
  END s_araddr[11]
  PIN s_araddr[1]
    DIRECTION OUTPUT ;
    USE SIGNAL ;
    PORT
      LAYER M4 ;
        RECT  97.116 52.704 97.2 52.728 ;
    END
  END s_araddr[1]
  PIN s_araddr[2]
    DIRECTION OUTPUT ;
    USE SIGNAL ;
    PORT
      LAYER M4 ;
        RECT  97.116 52.848 97.2 52.872 ;
    END
  END s_araddr[2]
  PIN s_araddr[3]
    DIRECTION OUTPUT ;
    USE SIGNAL ;
    PORT
      LAYER M4 ;
        RECT  97.116 52.992 97.2 53.016 ;
    END
  END s_araddr[3]
  PIN s_araddr[4]
    DIRECTION OUTPUT ;
    USE SIGNAL ;
    PORT
      LAYER M4 ;
        RECT  97.116 53.136 97.2 53.16 ;
    END
  END s_araddr[4]
  PIN s_araddr[5]
    DIRECTION OUTPUT ;
    USE SIGNAL ;
    PORT
      LAYER M4 ;
        RECT  97.116 53.28 97.2 53.304 ;
    END
  END s_araddr[5]
  PIN s_araddr[6]
    DIRECTION OUTPUT ;
    USE SIGNAL ;
    PORT
      LAYER M4 ;
        RECT  97.116 53.424 97.2 53.448 ;
    END
  END s_araddr[6]
  PIN s_araddr[7]
    DIRECTION OUTPUT ;
    USE SIGNAL ;
    PORT
      LAYER M4 ;
        RECT  97.116 53.568 97.2 53.592 ;
    END
  END s_araddr[7]
  PIN s_araddr[8]
    DIRECTION OUTPUT ;
    USE SIGNAL ;
    PORT
      LAYER M4 ;
        RECT  97.116 53.712 97.2 53.736 ;
    END
  END s_araddr[8]
  PIN s_araddr[9]
    DIRECTION OUTPUT ;
    USE SIGNAL ;
    PORT
      LAYER M4 ;
        RECT  97.116 53.856 97.2 53.88 ;
    END
  END s_araddr[9]
  PIN s_arready
    DIRECTION INPUT ;
    USE SIGNAL ;
    PORT
      LAYER M4 ;
        RECT  97.116 54.288 97.2 54.312 ;
    END
  END s_arready
  PIN s_arvalid
    DIRECTION OUTPUT ;
    USE SIGNAL ;
    PORT
      LAYER M4 ;
        RECT  97.116 54.432 97.2 54.456 ;
    END
  END s_arvalid
  PIN s_awaddr[0]
    DIRECTION OUTPUT ;
    USE SIGNAL ;
    PORT
      LAYER M4 ;
        RECT  97.116 54.576 97.2 54.6 ;
    END
  END s_awaddr[0]
  PIN s_awaddr[10]
    DIRECTION OUTPUT ;
    USE SIGNAL ;
    PORT
      LAYER M4 ;
        RECT  97.116 56.016 97.2 56.04 ;
    END
  END s_awaddr[10]
  PIN s_awaddr[11]
    DIRECTION OUTPUT ;
    USE SIGNAL ;
    PORT
      LAYER M4 ;
        RECT  97.116 56.16 97.2 56.184 ;
    END
  END s_awaddr[11]
  PIN s_awaddr[1]
    DIRECTION OUTPUT ;
    USE SIGNAL ;
    PORT
      LAYER M4 ;
        RECT  97.116 54.72 97.2 54.744 ;
    END
  END s_awaddr[1]
  PIN s_awaddr[2]
    DIRECTION OUTPUT ;
    USE SIGNAL ;
    PORT
      LAYER M4 ;
        RECT  97.116 54.864 97.2 54.888 ;
    END
  END s_awaddr[2]
  PIN s_awaddr[3]
    DIRECTION OUTPUT ;
    USE SIGNAL ;
    PORT
      LAYER M4 ;
        RECT  97.116 55.008 97.2 55.032 ;
    END
  END s_awaddr[3]
  PIN s_awaddr[4]
    DIRECTION OUTPUT ;
    USE SIGNAL ;
    PORT
      LAYER M4 ;
        RECT  97.116 55.152 97.2 55.176 ;
    END
  END s_awaddr[4]
  PIN s_awaddr[5]
    DIRECTION OUTPUT ;
    USE SIGNAL ;
    PORT
      LAYER M4 ;
        RECT  97.116 55.296 97.2 55.32 ;
    END
  END s_awaddr[5]
  PIN s_awaddr[6]
    DIRECTION OUTPUT ;
    USE SIGNAL ;
    PORT
      LAYER M4 ;
        RECT  97.116 55.44 97.2 55.464 ;
    END
  END s_awaddr[6]
  PIN s_awaddr[7]
    DIRECTION OUTPUT ;
    USE SIGNAL ;
    PORT
      LAYER M4 ;
        RECT  97.116 55.584 97.2 55.608 ;
    END
  END s_awaddr[7]
  PIN s_awaddr[8]
    DIRECTION OUTPUT ;
    USE SIGNAL ;
    PORT
      LAYER M4 ;
        RECT  97.116 55.728 97.2 55.752 ;
    END
  END s_awaddr[8]
  PIN s_awaddr[9]
    DIRECTION OUTPUT ;
    USE SIGNAL ;
    PORT
      LAYER M4 ;
        RECT  97.116 55.872 97.2 55.896 ;
    END
  END s_awaddr[9]
  PIN s_awready
    DIRECTION INPUT ;
    USE SIGNAL ;
    PORT
      LAYER M4 ;
        RECT  97.116 56.304 97.2 56.328 ;
    END
  END s_awready
  PIN s_awvalid
    DIRECTION OUTPUT ;
    USE SIGNAL ;
    PORT
      LAYER M4 ;
        RECT  97.116 56.448 97.2 56.472 ;
    END
  END s_awvalid
  PIN s_bready
    DIRECTION OUTPUT ;
    USE SIGNAL ;
    PORT
      LAYER M4 ;
        RECT  97.116 56.592 97.2 56.616 ;
    END
  END s_bready
  PIN s_bresp[0]
    DIRECTION INPUT ;
    USE SIGNAL ;
    PORT
      LAYER M4 ;
        RECT  97.116 56.736 97.2 56.76 ;
    END
  END s_bresp[0]
  PIN s_bresp[1]
    DIRECTION INPUT ;
    USE SIGNAL ;
    PORT
      LAYER M4 ;
        RECT  97.116 56.88 97.2 56.904 ;
    END
  END s_bresp[1]
  PIN s_bvalid
    DIRECTION INPUT ;
    USE SIGNAL ;
    PORT
      LAYER M4 ;
        RECT  97.116 57.024 97.2 57.048 ;
    END
  END s_bvalid
  PIN s_rdata[0]
    DIRECTION INPUT ;
    USE SIGNAL ;
    PORT
      LAYER M4 ;
        RECT  97.116 47.952 97.2 47.976 ;
    END
  END s_rdata[0]
  PIN s_rdata[10]
    DIRECTION INPUT ;
    USE SIGNAL ;
    PORT
      LAYER M4 ;
        RECT  97.116 49.392 97.2 49.416 ;
    END
  END s_rdata[10]
  PIN s_rdata[11]
    DIRECTION INPUT ;
    USE SIGNAL ;
    PORT
      LAYER M4 ;
        RECT  97.116 49.536 97.2 49.56 ;
    END
  END s_rdata[11]
  PIN s_rdata[12]
    DIRECTION INPUT ;
    USE SIGNAL ;
    PORT
      LAYER M4 ;
        RECT  97.116 49.68 97.2 49.704 ;
    END
  END s_rdata[12]
  PIN s_rdata[13]
    DIRECTION INPUT ;
    USE SIGNAL ;
    PORT
      LAYER M4 ;
        RECT  97.116 49.824 97.2 49.848 ;
    END
  END s_rdata[13]
  PIN s_rdata[14]
    DIRECTION INPUT ;
    USE SIGNAL ;
    PORT
      LAYER M4 ;
        RECT  97.116 49.968 97.2 49.992 ;
    END
  END s_rdata[14]
  PIN s_rdata[15]
    DIRECTION INPUT ;
    USE SIGNAL ;
    PORT
      LAYER M4 ;
        RECT  97.116 50.112 97.2 50.136 ;
    END
  END s_rdata[15]
  PIN s_rdata[16]
    DIRECTION INPUT ;
    USE SIGNAL ;
    PORT
      LAYER M4 ;
        RECT  97.116 50.256 97.2 50.28 ;
    END
  END s_rdata[16]
  PIN s_rdata[17]
    DIRECTION INPUT ;
    USE SIGNAL ;
    PORT
      LAYER M4 ;
        RECT  97.116 50.4 97.2 50.424 ;
    END
  END s_rdata[17]
  PIN s_rdata[18]
    DIRECTION INPUT ;
    USE SIGNAL ;
    PORT
      LAYER M4 ;
        RECT  97.116 50.544 97.2 50.568 ;
    END
  END s_rdata[18]
  PIN s_rdata[19]
    DIRECTION INPUT ;
    USE SIGNAL ;
    PORT
      LAYER M4 ;
        RECT  97.116 50.688 97.2 50.712 ;
    END
  END s_rdata[19]
  PIN s_rdata[1]
    DIRECTION INPUT ;
    USE SIGNAL ;
    PORT
      LAYER M4 ;
        RECT  97.116 48.096 97.2 48.12 ;
    END
  END s_rdata[1]
  PIN s_rdata[20]
    DIRECTION INPUT ;
    USE SIGNAL ;
    PORT
      LAYER M4 ;
        RECT  97.116 50.832 97.2 50.856 ;
    END
  END s_rdata[20]
  PIN s_rdata[21]
    DIRECTION INPUT ;
    USE SIGNAL ;
    PORT
      LAYER M4 ;
        RECT  97.116 50.976 97.2 51 ;
    END
  END s_rdata[21]
  PIN s_rdata[22]
    DIRECTION INPUT ;
    USE SIGNAL ;
    PORT
      LAYER M4 ;
        RECT  97.116 51.12 97.2 51.144 ;
    END
  END s_rdata[22]
  PIN s_rdata[23]
    DIRECTION INPUT ;
    USE SIGNAL ;
    PORT
      LAYER M4 ;
        RECT  97.116 51.264 97.2 51.288 ;
    END
  END s_rdata[23]
  PIN s_rdata[24]
    DIRECTION INPUT ;
    USE SIGNAL ;
    PORT
      LAYER M4 ;
        RECT  97.116 51.408 97.2 51.432 ;
    END
  END s_rdata[24]
  PIN s_rdata[25]
    DIRECTION INPUT ;
    USE SIGNAL ;
    PORT
      LAYER M4 ;
        RECT  97.116 51.552 97.2 51.576 ;
    END
  END s_rdata[25]
  PIN s_rdata[26]
    DIRECTION INPUT ;
    USE SIGNAL ;
    PORT
      LAYER M4 ;
        RECT  97.116 51.696 97.2 51.72 ;
    END
  END s_rdata[26]
  PIN s_rdata[27]
    DIRECTION INPUT ;
    USE SIGNAL ;
    PORT
      LAYER M4 ;
        RECT  97.116 51.84 97.2 51.864 ;
    END
  END s_rdata[27]
  PIN s_rdata[28]
    DIRECTION INPUT ;
    USE SIGNAL ;
    PORT
      LAYER M4 ;
        RECT  97.116 51.984 97.2 52.008 ;
    END
  END s_rdata[28]
  PIN s_rdata[29]
    DIRECTION INPUT ;
    USE SIGNAL ;
    PORT
      LAYER M4 ;
        RECT  97.116 52.128 97.2 52.152 ;
    END
  END s_rdata[29]
  PIN s_rdata[2]
    DIRECTION INPUT ;
    USE SIGNAL ;
    PORT
      LAYER M4 ;
        RECT  97.116 48.24 97.2 48.264 ;
    END
  END s_rdata[2]
  PIN s_rdata[30]
    DIRECTION INPUT ;
    USE SIGNAL ;
    PORT
      LAYER M4 ;
        RECT  97.116 52.272 97.2 52.296 ;
    END
  END s_rdata[30]
  PIN s_rdata[31]
    DIRECTION INPUT ;
    USE SIGNAL ;
    PORT
      LAYER M4 ;
        RECT  97.116 52.416 97.2 52.44 ;
    END
  END s_rdata[31]
  PIN s_rdata[3]
    DIRECTION INPUT ;
    USE SIGNAL ;
    PORT
      LAYER M4 ;
        RECT  97.116 48.384 97.2 48.408 ;
    END
  END s_rdata[3]
  PIN s_rdata[4]
    DIRECTION INPUT ;
    USE SIGNAL ;
    PORT
      LAYER M4 ;
        RECT  97.116 48.528 97.2 48.552 ;
    END
  END s_rdata[4]
  PIN s_rdata[5]
    DIRECTION INPUT ;
    USE SIGNAL ;
    PORT
      LAYER M4 ;
        RECT  97.116 48.672 97.2 48.696 ;
    END
  END s_rdata[5]
  PIN s_rdata[6]
    DIRECTION INPUT ;
    USE SIGNAL ;
    PORT
      LAYER M4 ;
        RECT  97.116 48.816 97.2 48.84 ;
    END
  END s_rdata[6]
  PIN s_rdata[7]
    DIRECTION INPUT ;
    USE SIGNAL ;
    PORT
      LAYER M4 ;
        RECT  97.116 48.96 97.2 48.984 ;
    END
  END s_rdata[7]
  PIN s_rdata[8]
    DIRECTION INPUT ;
    USE SIGNAL ;
    PORT
      LAYER M4 ;
        RECT  97.116 49.104 97.2 49.128 ;
    END
  END s_rdata[8]
  PIN s_rdata[9]
    DIRECTION INPUT ;
    USE SIGNAL ;
    PORT
      LAYER M4 ;
        RECT  97.116 49.248 97.2 49.272 ;
    END
  END s_rdata[9]
  PIN s_rready
    DIRECTION OUTPUT ;
    USE SIGNAL ;
    PORT
      LAYER M4 ;
        RECT  97.116 43.344 97.2 43.368 ;
    END
  END s_rready
  PIN s_rvalid
    DIRECTION INPUT ;
    USE SIGNAL ;
    PORT
      LAYER M4 ;
        RECT  97.116 43.488 97.2 43.512 ;
    END
  END s_rvalid
  PIN s_wdata[0]
    DIRECTION OUTPUT ;
    USE SIGNAL ;
    PORT
      LAYER M4 ;
        RECT  97.116 43.632 97.2 43.656 ;
    END
  END s_wdata[0]
  PIN s_wdata[10]
    DIRECTION OUTPUT ;
    USE SIGNAL ;
    PORT
      LAYER M4 ;
        RECT  97.116 45.072 97.2 45.096 ;
    END
  END s_wdata[10]
  PIN s_wdata[11]
    DIRECTION OUTPUT ;
    USE SIGNAL ;
    PORT
      LAYER M4 ;
        RECT  97.116 45.216 97.2 45.24 ;
    END
  END s_wdata[11]
  PIN s_wdata[12]
    DIRECTION OUTPUT ;
    USE SIGNAL ;
    PORT
      LAYER M4 ;
        RECT  97.116 45.36 97.2 45.384 ;
    END
  END s_wdata[12]
  PIN s_wdata[13]
    DIRECTION OUTPUT ;
    USE SIGNAL ;
    PORT
      LAYER M4 ;
        RECT  97.116 45.504 97.2 45.528 ;
    END
  END s_wdata[13]
  PIN s_wdata[14]
    DIRECTION OUTPUT ;
    USE SIGNAL ;
    PORT
      LAYER M4 ;
        RECT  97.116 45.648 97.2 45.672 ;
    END
  END s_wdata[14]
  PIN s_wdata[15]
    DIRECTION OUTPUT ;
    USE SIGNAL ;
    PORT
      LAYER M4 ;
        RECT  97.116 45.792 97.2 45.816 ;
    END
  END s_wdata[15]
  PIN s_wdata[16]
    DIRECTION OUTPUT ;
    USE SIGNAL ;
    PORT
      LAYER M4 ;
        RECT  97.116 45.936 97.2 45.96 ;
    END
  END s_wdata[16]
  PIN s_wdata[17]
    DIRECTION OUTPUT ;
    USE SIGNAL ;
    PORT
      LAYER M4 ;
        RECT  97.116 46.08 97.2 46.104 ;
    END
  END s_wdata[17]
  PIN s_wdata[18]
    DIRECTION OUTPUT ;
    USE SIGNAL ;
    PORT
      LAYER M4 ;
        RECT  97.116 46.224 97.2 46.248 ;
    END
  END s_wdata[18]
  PIN s_wdata[19]
    DIRECTION OUTPUT ;
    USE SIGNAL ;
    PORT
      LAYER M4 ;
        RECT  97.116 46.368 97.2 46.392 ;
    END
  END s_wdata[19]
  PIN s_wdata[1]
    DIRECTION OUTPUT ;
    USE SIGNAL ;
    PORT
      LAYER M4 ;
        RECT  97.116 43.776 97.2 43.8 ;
    END
  END s_wdata[1]
  PIN s_wdata[20]
    DIRECTION OUTPUT ;
    USE SIGNAL ;
    PORT
      LAYER M4 ;
        RECT  97.116 46.512 97.2 46.536 ;
    END
  END s_wdata[20]
  PIN s_wdata[21]
    DIRECTION OUTPUT ;
    USE SIGNAL ;
    PORT
      LAYER M4 ;
        RECT  97.116 46.656 97.2 46.68 ;
    END
  END s_wdata[21]
  PIN s_wdata[22]
    DIRECTION OUTPUT ;
    USE SIGNAL ;
    PORT
      LAYER M4 ;
        RECT  97.116 46.8 97.2 46.824 ;
    END
  END s_wdata[22]
  PIN s_wdata[23]
    DIRECTION OUTPUT ;
    USE SIGNAL ;
    PORT
      LAYER M4 ;
        RECT  97.116 46.944 97.2 46.968 ;
    END
  END s_wdata[23]
  PIN s_wdata[24]
    DIRECTION OUTPUT ;
    USE SIGNAL ;
    PORT
      LAYER M4 ;
        RECT  97.116 47.088 97.2 47.112 ;
    END
  END s_wdata[24]
  PIN s_wdata[25]
    DIRECTION OUTPUT ;
    USE SIGNAL ;
    PORT
      LAYER M4 ;
        RECT  97.116 47.232 97.2 47.256 ;
    END
  END s_wdata[25]
  PIN s_wdata[26]
    DIRECTION OUTPUT ;
    USE SIGNAL ;
    PORT
      LAYER M4 ;
        RECT  97.116 47.376 97.2 47.4 ;
    END
  END s_wdata[26]
  PIN s_wdata[27]
    DIRECTION OUTPUT ;
    USE SIGNAL ;
    PORT
      LAYER M4 ;
        RECT  97.116 47.52 97.2 47.544 ;
    END
  END s_wdata[27]
  PIN s_wdata[28]
    DIRECTION OUTPUT ;
    USE SIGNAL ;
    PORT
      LAYER M4 ;
        RECT  97.116 47.664 97.2 47.688 ;
    END
  END s_wdata[28]
  PIN s_wdata[29]
    DIRECTION OUTPUT ;
    USE SIGNAL ;
    PORT
      LAYER M4 ;
        RECT  97.116 47.808 97.2 47.832 ;
    END
  END s_wdata[29]
  PIN s_wdata[2]
    DIRECTION OUTPUT ;
    USE SIGNAL ;
    PORT
      LAYER M4 ;
        RECT  97.116 43.92 97.2 43.944 ;
    END
  END s_wdata[2]
  PIN s_wdata[30]
    DIRECTION OUTPUT ;
    USE SIGNAL ;
    PORT
      LAYER M4 ;
        RECT  97.116 38.736 97.2 38.76 ;
    END
  END s_wdata[30]
  PIN s_wdata[31]
    DIRECTION OUTPUT ;
    USE SIGNAL ;
    PORT
      LAYER M4 ;
        RECT  97.116 38.88 97.2 38.904 ;
    END
  END s_wdata[31]
  PIN s_wdata[3]
    DIRECTION OUTPUT ;
    USE SIGNAL ;
    PORT
      LAYER M4 ;
        RECT  97.116 44.064 97.2 44.088 ;
    END
  END s_wdata[3]
  PIN s_wdata[4]
    DIRECTION OUTPUT ;
    USE SIGNAL ;
    PORT
      LAYER M4 ;
        RECT  97.116 44.208 97.2 44.232 ;
    END
  END s_wdata[4]
  PIN s_wdata[5]
    DIRECTION OUTPUT ;
    USE SIGNAL ;
    PORT
      LAYER M4 ;
        RECT  97.116 44.352 97.2 44.376 ;
    END
  END s_wdata[5]
  PIN s_wdata[6]
    DIRECTION OUTPUT ;
    USE SIGNAL ;
    PORT
      LAYER M4 ;
        RECT  97.116 44.496 97.2 44.52 ;
    END
  END s_wdata[6]
  PIN s_wdata[7]
    DIRECTION OUTPUT ;
    USE SIGNAL ;
    PORT
      LAYER M4 ;
        RECT  97.116 44.64 97.2 44.664 ;
    END
  END s_wdata[7]
  PIN s_wdata[8]
    DIRECTION OUTPUT ;
    USE SIGNAL ;
    PORT
      LAYER M4 ;
        RECT  97.116 44.784 97.2 44.808 ;
    END
  END s_wdata[8]
  PIN s_wdata[9]
    DIRECTION OUTPUT ;
    USE SIGNAL ;
    PORT
      LAYER M4 ;
        RECT  97.116 44.928 97.2 44.952 ;
    END
  END s_wdata[9]
  PIN s_wready
    DIRECTION INPUT ;
    USE SIGNAL ;
    PORT
      LAYER M4 ;
        RECT  97.116 39.024 97.2 39.048 ;
    END
  END s_wready
  PIN s_wstrb[0]
    DIRECTION OUTPUT ;
    USE SIGNAL ;
    PORT
      LAYER M4 ;
        RECT  97.116 39.168 97.2 39.192 ;
    END
  END s_wstrb[0]
  PIN s_wstrb[1]
    DIRECTION OUTPUT ;
    USE SIGNAL ;
    PORT
      LAYER M4 ;
        RECT  97.116 39.312 97.2 39.336 ;
    END
  END s_wstrb[1]
  PIN s_wstrb[2]
    DIRECTION OUTPUT ;
    USE SIGNAL ;
    PORT
      LAYER M4 ;
        RECT  97.116 39.456 97.2 39.48 ;
    END
  END s_wstrb[2]
  PIN s_wstrb[3]
    DIRECTION OUTPUT ;
    USE SIGNAL ;
    PORT
      LAYER M4 ;
        RECT  97.116 39.6 97.2 39.624 ;
    END
  END s_wstrb[3]
  PIN s_wvalid
    DIRECTION OUTPUT ;
    USE SIGNAL ;
    PORT
      LAYER M4 ;
        RECT  97.116 39.744 97.2 39.768 ;
    END
  END s_wvalid
  PIN t_cr
    DIRECTION INPUT ;
    USE SIGNAL ;
    PORT
      LAYER M5 ;
        RECT  86.256 0 86.28 0.084 ;
    END
  END t_cr
  PIN VDD
    DIRECTION INOUT ;
    USE POWER ;
    PORT
      LAYER M5 ;
        RECT  94.392 2.151 94.512 95.049 ;
        RECT  88.992 2.151 89.112 95.049 ;
        RECT  83.592 2.151 83.712 95.049 ;
        RECT  78.192 2.151 78.312 95.049 ;
        RECT  72.792 2.151 72.912 95.049 ;
        RECT  67.392 2.151 67.512 95.049 ;
        RECT  61.992 2.151 62.112 95.049 ;
        RECT  56.592 2.151 56.712 95.049 ;
        RECT  51.192 2.151 51.312 95.049 ;
        RECT  45.792 2.151 45.912 95.049 ;
        RECT  40.392 2.151 40.512 95.049 ;
        RECT  34.992 2.151 35.112 95.049 ;
        RECT  29.592 2.151 29.712 95.049 ;
        RECT  24.192 2.151 24.312 95.049 ;
        RECT  18.792 2.151 18.912 95.049 ;
        RECT  13.392 2.151 13.512 95.049 ;
        RECT  7.992 2.151 8.112 95.049 ;
        RECT  2.592 2.151 2.712 95.049 ;
    END
  END VDD
  PIN VSS
    DIRECTION INOUT ;
    USE GROUND ;
    PORT
      LAYER M5 ;
        RECT  94.2 2.137 94.32 95.063 ;
        RECT  88.8 2.137 88.92 95.063 ;
        RECT  83.4 2.137 83.52 95.063 ;
        RECT  78 2.137 78.12 95.063 ;
        RECT  72.6 2.137 72.72 95.063 ;
        RECT  67.2 2.137 67.32 95.063 ;
        RECT  61.8 2.137 61.92 95.063 ;
        RECT  56.4 2.137 56.52 95.063 ;
        RECT  51 2.137 51.12 95.063 ;
        RECT  45.6 2.137 45.72 95.063 ;
        RECT  40.2 2.137 40.32 95.063 ;
        RECT  34.8 2.137 34.92 95.063 ;
        RECT  29.4 2.137 29.52 95.063 ;
        RECT  24 2.137 24.12 95.063 ;
        RECT  18.6 2.137 18.72 95.063 ;
        RECT  13.2 2.137 13.32 95.063 ;
        RECT  7.8 2.137 7.92 95.063 ;
        RECT  2.4 2.137 2.52 95.063 ;
    END
  END VSS
  # OT_OBS_CLOSED layer=M5 d_um=1.536 added=100
  OBS
    LAYER RVTN ;
     RECT  2.16 2.16 95.04 2.295 ;
     RECT  2.16 2.565 95.04 2.835 ;
     RECT  2.16 3.105 95.04 3.375 ;
     RECT  2.16 3.645 95.04 3.915 ;
     RECT  2.16 4.185 95.04 4.455 ;
     RECT  2.16 4.725 95.04 4.995 ;
     RECT  2.16 5.265 95.04 5.535 ;
     RECT  2.16 5.805 95.04 6.075 ;
     RECT  2.16 6.345 95.04 6.615 ;
     RECT  2.16 6.885 95.04 7.155 ;
     RECT  2.16 7.425 95.04 7.695 ;
     RECT  2.16 7.965 95.04 8.235 ;
     RECT  2.16 8.505 95.04 8.775 ;
     RECT  2.16 9.045 95.04 9.315 ;
     RECT  2.16 9.585 95.04 9.855 ;
     RECT  2.16 10.125 95.04 10.395 ;
     RECT  2.16 10.665 95.04 10.935 ;
     RECT  2.16 11.205 95.04 11.475 ;
     RECT  2.16 11.745 95.04 12.015 ;
     RECT  2.16 12.285 95.04 12.555 ;
     RECT  2.16 12.825 95.04 13.095 ;
     RECT  2.16 13.365 95.04 13.635 ;
     RECT  2.16 13.905 95.04 14.175 ;
     RECT  2.16 14.445 95.04 14.715 ;
     RECT  2.16 14.985 95.04 15.255 ;
     RECT  2.16 15.525 95.04 15.795 ;
     RECT  2.16 16.065 95.04 16.335 ;
     RECT  2.16 16.605 95.04 16.875 ;
     RECT  2.16 17.145 95.04 17.415 ;
     RECT  2.16 17.685 95.04 17.955 ;
     RECT  2.16 18.225 95.04 18.495 ;
     RECT  2.16 18.765 95.04 19.035 ;
     RECT  2.16 19.305 95.04 19.575 ;
     RECT  2.16 19.845 95.04 20.115 ;
     RECT  2.16 20.385 95.04 20.655 ;
     RECT  2.16 20.925 95.04 21.195 ;
     RECT  2.16 21.465 95.04 21.735 ;
     RECT  2.16 22.005 95.04 22.275 ;
     RECT  2.16 22.545 95.04 22.815 ;
     RECT  2.16 23.085 95.04 23.355 ;
     RECT  2.16 23.625 95.04 23.895 ;
     RECT  2.16 24.165 95.04 24.435 ;
     RECT  2.16 24.705 95.04 24.975 ;
     RECT  2.16 25.245 95.04 25.515 ;
     RECT  2.16 25.785 95.04 26.055 ;
     RECT  2.16 26.325 95.04 26.595 ;
     RECT  2.16 26.865 95.04 27.135 ;
     RECT  2.16 27.405 95.04 27.675 ;
     RECT  2.16 27.945 95.04 28.215 ;
     RECT  2.16 28.485 95.04 28.755 ;
     RECT  2.16 29.025 95.04 29.295 ;
     RECT  2.16 29.565 95.04 29.835 ;
     RECT  2.16 30.105 95.04 30.375 ;
     RECT  2.16 30.645 95.04 30.915 ;
     RECT  2.16 31.185 95.04 31.455 ;
     RECT  2.16 31.725 95.04 31.995 ;
     RECT  2.16 32.265 95.04 32.535 ;
     RECT  2.16 32.805 95.04 33.075 ;
     RECT  2.16 33.345 95.04 33.615 ;
     RECT  2.16 33.885 95.04 34.155 ;
     RECT  2.16 34.425 95.04 34.695 ;
     RECT  2.16 34.965 95.04 35.235 ;
     RECT  2.16 35.505 95.04 35.775 ;
     RECT  2.16 36.045 95.04 36.315 ;
     RECT  2.16 36.585 95.04 36.855 ;
     RECT  2.16 37.125 95.04 37.395 ;
     RECT  2.16 37.665 95.04 37.935 ;
     RECT  2.16 38.205 95.04 38.475 ;
     RECT  2.16 38.745 95.04 39.015 ;
     RECT  2.16 39.285 95.04 39.555 ;
     RECT  2.16 39.825 95.04 40.095 ;
     RECT  2.16 40.365 95.04 40.635 ;
     RECT  2.16 40.905 95.04 41.175 ;
     RECT  2.16 41.445 95.04 41.715 ;
     RECT  2.16 41.985 95.04 42.255 ;
     RECT  2.16 42.525 95.04 42.795 ;
     RECT  2.16 43.065 95.04 43.335 ;
     RECT  2.16 43.605 95.04 43.875 ;
     RECT  2.16 44.145 95.04 44.415 ;
     RECT  2.16 44.685 95.04 44.955 ;
     RECT  2.16 45.225 95.04 45.495 ;
     RECT  2.16 45.765 95.04 46.035 ;
     RECT  2.16 46.305 95.04 46.575 ;
     RECT  2.16 46.845 95.04 47.115 ;
     RECT  2.16 47.385 95.04 47.655 ;
     RECT  2.16 47.925 95.04 48.195 ;
     RECT  2.16 48.465 95.04 48.735 ;
     RECT  2.16 49.005 95.04 49.275 ;
     RECT  2.16 49.545 95.04 49.815 ;
     RECT  2.16 50.085 95.04 50.355 ;
     RECT  2.16 50.625 95.04 50.895 ;
     RECT  2.16 51.165 95.04 51.435 ;
     RECT  2.16 51.705 95.04 51.975 ;
     RECT  2.16 52.245 95.04 52.515 ;
     RECT  2.16 52.785 95.04 53.055 ;
     RECT  2.16 53.325 95.04 53.595 ;
     RECT  2.16 53.865 95.04 54.135 ;
     RECT  2.16 54.405 95.04 54.675 ;
     RECT  2.16 54.945 95.04 55.215 ;
     RECT  2.16 55.485 95.04 55.755 ;
     RECT  2.16 56.025 95.04 56.295 ;
     RECT  2.16 56.565 95.04 56.835 ;
     RECT  2.16 57.105 95.04 57.375 ;
     RECT  2.16 57.645 95.04 57.915 ;
     RECT  2.16 58.185 95.04 58.455 ;
     RECT  2.16 58.725 95.04 58.995 ;
     RECT  2.16 59.265 95.04 59.535 ;
     RECT  2.16 59.805 95.04 60.075 ;
     RECT  2.16 60.345 95.04 60.615 ;
     RECT  2.16 60.885 95.04 61.155 ;
     RECT  2.16 61.425 95.04 61.695 ;
     RECT  2.16 61.965 95.04 62.235 ;
     RECT  2.16 62.505 95.04 62.775 ;
     RECT  2.16 63.045 95.04 63.315 ;
     RECT  2.16 63.585 95.04 63.855 ;
     RECT  2.16 64.125 95.04 64.395 ;
     RECT  2.16 64.665 95.04 64.935 ;
     RECT  2.16 65.205 95.04 65.475 ;
     RECT  2.16 65.745 95.04 66.015 ;
     RECT  2.16 66.285 95.04 66.555 ;
     RECT  2.16 66.825 95.04 67.095 ;
     RECT  2.16 67.365 95.04 67.635 ;
     RECT  2.16 67.905 95.04 68.175 ;
     RECT  2.16 68.445 95.04 68.715 ;
     RECT  2.16 68.985 95.04 69.255 ;
     RECT  2.16 69.525 95.04 69.795 ;
     RECT  2.16 70.065 95.04 70.335 ;
     RECT  2.16 70.605 95.04 70.875 ;
     RECT  2.16 71.145 95.04 71.415 ;
     RECT  2.16 71.685 95.04 71.955 ;
     RECT  2.16 72.225 95.04 72.495 ;
     RECT  2.16 72.765 95.04 73.035 ;
     RECT  2.16 73.305 95.04 73.575 ;
     RECT  2.16 73.845 95.04 74.115 ;
     RECT  2.16 74.385 95.04 74.655 ;
     RECT  2.16 74.925 95.04 75.195 ;
     RECT  2.16 75.465 95.04 75.735 ;
     RECT  2.16 76.005 95.04 76.275 ;
     RECT  2.16 76.545 95.04 76.815 ;
     RECT  2.16 77.085 95.04 77.355 ;
     RECT  2.16 77.625 95.04 77.895 ;
     RECT  2.16 78.165 95.04 78.435 ;
     RECT  2.16 78.705 95.04 78.975 ;
     RECT  2.16 79.245 95.04 79.515 ;
     RECT  2.16 79.785 95.04 80.055 ;
     RECT  2.16 80.325 95.04 80.595 ;
     RECT  2.16 80.865 95.04 81.135 ;
     RECT  2.16 81.405 95.04 81.675 ;
     RECT  2.16 81.945 95.04 82.215 ;
     RECT  2.16 82.485 95.04 82.755 ;
     RECT  2.16 83.025 95.04 83.295 ;
     RECT  2.16 83.565 95.04 83.835 ;
     RECT  2.16 84.105 95.04 84.375 ;
     RECT  2.16 84.645 95.04 84.915 ;
     RECT  2.16 85.185 95.04 85.455 ;
     RECT  2.16 85.725 95.04 85.995 ;
     RECT  2.16 86.265 95.04 86.535 ;
     RECT  2.16 86.805 95.04 87.075 ;
     RECT  2.16 87.345 95.04 87.615 ;
     RECT  2.16 87.885 95.04 88.155 ;
     RECT  2.16 88.425 95.04 88.695 ;
     RECT  2.16 88.965 95.04 89.235 ;
     RECT  2.16 89.505 95.04 89.775 ;
     RECT  2.16 90.045 95.04 90.315 ;
     RECT  2.16 90.585 95.04 90.855 ;
     RECT  2.16 91.125 95.04 91.395 ;
     RECT  2.16 91.665 95.04 91.935 ;
     RECT  2.16 92.205 95.04 92.475 ;
     RECT  2.16 92.745 95.04 93.015 ;
     RECT  2.16 93.285 95.04 93.555 ;
     RECT  2.16 93.825 95.04 94.095 ;
     RECT  2.16 94.365 95.04 94.635 ;
     RECT  2.16 94.905 95.04 95.04 ;
    LAYER RVTP ;
     RECT  2.16 2.295 95.04 2.565 ;
     RECT  2.16 2.835 95.04 3.105 ;
     RECT  2.16 3.375 95.04 3.645 ;
     RECT  2.16 3.915 95.04 4.185 ;
     RECT  2.16 4.455 95.04 4.725 ;
     RECT  2.16 4.995 95.04 5.265 ;
     RECT  2.16 5.535 95.04 5.805 ;
     RECT  2.16 6.075 95.04 6.345 ;
     RECT  2.16 6.615 95.04 6.885 ;
     RECT  2.16 7.155 95.04 7.425 ;
     RECT  2.16 7.695 95.04 7.965 ;
     RECT  2.16 8.235 95.04 8.505 ;
     RECT  2.16 8.775 95.04 9.045 ;
     RECT  2.16 9.315 95.04 9.585 ;
     RECT  2.16 9.855 95.04 10.125 ;
     RECT  2.16 10.395 95.04 10.665 ;
     RECT  2.16 10.935 95.04 11.205 ;
     RECT  2.16 11.475 95.04 11.745 ;
     RECT  2.16 12.015 95.04 12.285 ;
     RECT  2.16 12.555 95.04 12.825 ;
     RECT  2.16 13.095 95.04 13.365 ;
     RECT  2.16 13.635 95.04 13.905 ;
     RECT  2.16 14.175 95.04 14.445 ;
     RECT  2.16 14.715 95.04 14.985 ;
     RECT  2.16 15.255 95.04 15.525 ;
     RECT  2.16 15.795 95.04 16.065 ;
     RECT  2.16 16.335 95.04 16.605 ;
     RECT  2.16 16.875 95.04 17.145 ;
     RECT  2.16 17.415 95.04 17.685 ;
     RECT  2.16 17.955 95.04 18.225 ;
     RECT  2.16 18.495 95.04 18.765 ;
     RECT  2.16 19.035 95.04 19.305 ;
     RECT  2.16 19.575 95.04 19.845 ;
     RECT  2.16 20.115 95.04 20.385 ;
     RECT  2.16 20.655 95.04 20.925 ;
     RECT  2.16 21.195 95.04 21.465 ;
     RECT  2.16 21.735 95.04 22.005 ;
     RECT  2.16 22.275 95.04 22.545 ;
     RECT  2.16 22.815 95.04 23.085 ;
     RECT  2.16 23.355 95.04 23.625 ;
     RECT  2.16 23.895 95.04 24.165 ;
     RECT  2.16 24.435 95.04 24.705 ;
     RECT  2.16 24.975 95.04 25.245 ;
     RECT  2.16 25.515 95.04 25.785 ;
     RECT  2.16 26.055 95.04 26.325 ;
     RECT  2.16 26.595 95.04 26.865 ;
     RECT  2.16 27.135 95.04 27.405 ;
     RECT  2.16 27.675 95.04 27.945 ;
     RECT  2.16 28.215 95.04 28.485 ;
     RECT  2.16 28.755 95.04 29.025 ;
     RECT  2.16 29.295 95.04 29.565 ;
     RECT  2.16 29.835 95.04 30.105 ;
     RECT  2.16 30.375 95.04 30.645 ;
     RECT  2.16 30.915 95.04 31.185 ;
     RECT  2.16 31.455 95.04 31.725 ;
     RECT  2.16 31.995 95.04 32.265 ;
     RECT  2.16 32.535 95.04 32.805 ;
     RECT  2.16 33.075 95.04 33.345 ;
     RECT  2.16 33.615 95.04 33.885 ;
     RECT  2.16 34.155 95.04 34.425 ;
     RECT  2.16 34.695 95.04 34.965 ;
     RECT  2.16 35.235 95.04 35.505 ;
     RECT  2.16 35.775 95.04 36.045 ;
     RECT  2.16 36.315 95.04 36.585 ;
     RECT  2.16 36.855 95.04 37.125 ;
     RECT  2.16 37.395 95.04 37.665 ;
     RECT  2.16 37.935 95.04 38.205 ;
     RECT  2.16 38.475 95.04 38.745 ;
     RECT  2.16 39.015 95.04 39.285 ;
     RECT  2.16 39.555 95.04 39.825 ;
     RECT  2.16 40.095 95.04 40.365 ;
     RECT  2.16 40.635 95.04 40.905 ;
     RECT  2.16 41.175 95.04 41.445 ;
     RECT  2.16 41.715 95.04 41.985 ;
     RECT  2.16 42.255 95.04 42.525 ;
     RECT  2.16 42.795 95.04 43.065 ;
     RECT  2.16 43.335 95.04 43.605 ;
     RECT  2.16 43.875 95.04 44.145 ;
     RECT  2.16 44.415 95.04 44.685 ;
     RECT  2.16 44.955 95.04 45.225 ;
     RECT  2.16 45.495 95.04 45.765 ;
     RECT  2.16 46.035 95.04 46.305 ;
     RECT  2.16 46.575 95.04 46.845 ;
     RECT  2.16 47.115 95.04 47.385 ;
     RECT  2.16 47.655 95.04 47.925 ;
     RECT  2.16 48.195 95.04 48.465 ;
     RECT  2.16 48.735 95.04 49.005 ;
     RECT  2.16 49.275 95.04 49.545 ;
     RECT  2.16 49.815 95.04 50.085 ;
     RECT  2.16 50.355 95.04 50.625 ;
     RECT  2.16 50.895 95.04 51.165 ;
     RECT  2.16 51.435 95.04 51.705 ;
     RECT  2.16 51.975 95.04 52.245 ;
     RECT  2.16 52.515 95.04 52.785 ;
     RECT  2.16 53.055 95.04 53.325 ;
     RECT  2.16 53.595 95.04 53.865 ;
     RECT  2.16 54.135 95.04 54.405 ;
     RECT  2.16 54.675 95.04 54.945 ;
     RECT  2.16 55.215 95.04 55.485 ;
     RECT  2.16 55.755 95.04 56.025 ;
     RECT  2.16 56.295 95.04 56.565 ;
     RECT  2.16 56.835 95.04 57.105 ;
     RECT  2.16 57.375 95.04 57.645 ;
     RECT  2.16 57.915 95.04 58.185 ;
     RECT  2.16 58.455 95.04 58.725 ;
     RECT  2.16 58.995 95.04 59.265 ;
     RECT  2.16 59.535 95.04 59.805 ;
     RECT  2.16 60.075 95.04 60.345 ;
     RECT  2.16 60.615 95.04 60.885 ;
     RECT  2.16 61.155 95.04 61.425 ;
     RECT  2.16 61.695 95.04 61.965 ;
     RECT  2.16 62.235 95.04 62.505 ;
     RECT  2.16 62.775 95.04 63.045 ;
     RECT  2.16 63.315 95.04 63.585 ;
     RECT  2.16 63.855 95.04 64.125 ;
     RECT  2.16 64.395 95.04 64.665 ;
     RECT  2.16 64.935 95.04 65.205 ;
     RECT  2.16 65.475 95.04 65.745 ;
     RECT  2.16 66.015 95.04 66.285 ;
     RECT  2.16 66.555 95.04 66.825 ;
     RECT  2.16 67.095 95.04 67.365 ;
     RECT  2.16 67.635 95.04 67.905 ;
     RECT  2.16 68.175 95.04 68.445 ;
     RECT  2.16 68.715 95.04 68.985 ;
     RECT  2.16 69.255 95.04 69.525 ;
     RECT  2.16 69.795 95.04 70.065 ;
     RECT  2.16 70.335 95.04 70.605 ;
     RECT  2.16 70.875 95.04 71.145 ;
     RECT  2.16 71.415 95.04 71.685 ;
     RECT  2.16 71.955 95.04 72.225 ;
     RECT  2.16 72.495 95.04 72.765 ;
     RECT  2.16 73.035 95.04 73.305 ;
     RECT  2.16 73.575 95.04 73.845 ;
     RECT  2.16 74.115 95.04 74.385 ;
     RECT  2.16 74.655 95.04 74.925 ;
     RECT  2.16 75.195 95.04 75.465 ;
     RECT  2.16 75.735 95.04 76.005 ;
     RECT  2.16 76.275 95.04 76.545 ;
     RECT  2.16 76.815 95.04 77.085 ;
     RECT  2.16 77.355 95.04 77.625 ;
     RECT  2.16 77.895 95.04 78.165 ;
     RECT  2.16 78.435 95.04 78.705 ;
     RECT  2.16 78.975 95.04 79.245 ;
     RECT  2.16 79.515 95.04 79.785 ;
     RECT  2.16 80.055 95.04 80.325 ;
     RECT  2.16 80.595 95.04 80.865 ;
     RECT  2.16 81.135 95.04 81.405 ;
     RECT  2.16 81.675 95.04 81.945 ;
     RECT  2.16 82.215 95.04 82.485 ;
     RECT  2.16 82.755 95.04 83.025 ;
     RECT  2.16 83.295 95.04 83.565 ;
     RECT  2.16 83.835 95.04 84.105 ;
     RECT  2.16 84.375 95.04 84.645 ;
     RECT  2.16 84.915 95.04 85.185 ;
     RECT  2.16 85.455 95.04 85.725 ;
     RECT  2.16 85.995 95.04 86.265 ;
     RECT  2.16 86.535 95.04 86.805 ;
     RECT  2.16 87.075 95.04 87.345 ;
     RECT  2.16 87.615 95.04 87.885 ;
     RECT  2.16 88.155 95.04 88.425 ;
     RECT  2.16 88.695 95.04 88.965 ;
     RECT  2.16 89.235 95.04 89.505 ;
     RECT  2.16 89.775 95.04 90.045 ;
     RECT  2.16 90.315 95.04 90.585 ;
     RECT  2.16 90.855 95.04 91.125 ;
     RECT  2.16 91.395 95.04 91.665 ;
     RECT  2.16 91.935 95.04 92.205 ;
     RECT  2.16 92.475 95.04 92.745 ;
     RECT  2.16 93.015 95.04 93.285 ;
     RECT  2.16 93.555 95.04 93.825 ;
     RECT  2.16 94.095 95.04 94.365 ;
     RECT  2.16 94.635 95.04 94.905 ;
    LAYER M1 ;
     RECT  2.16 2.151 95.04 95.049 ;
    LAYER M2 ;
     RECT  0.103 13.536 0.139 14.238 ;
     RECT  0.103 60.39 0.139 60.408 ;
     RECT  0.103 1.926 0.535 1.944 ;
     RECT  0.139 13.032 0.535 14.238 ;
     RECT  0.103 16.38 0.535 16.398 ;
     RECT  0.499 49.554 0.535 49.572 ;
     RECT  0.103 64.332 0.535 64.35 ;
     RECT  0.103 68.922 0.535 69.318 ;
     RECT  0.103 70.074 0.535 71.208 ;
     RECT  0.103 42.606 0.563 42.624 ;
     RECT  0.535 1.926 2.16 2.628 ;
     RECT  0.535 5.544 2.16 5.562 ;
     RECT  0.103 7.74 2.16 7.758 ;
     RECT  0.535 12.528 2.16 14.238 ;
     RECT  0.535 16.38 2.16 17.478 ;
     RECT  0.535 20.43 2.16 20.448 ;
     RECT  0.535 21.474 2.16 21.492 ;
     RECT  0.535 22.752 2.16 22.77 ;
     RECT  0.103 27.342 2.16 27.36 ;
     RECT  0.535 28.458 2.16 28.476 ;
     RECT  0.103 31.23 2.16 31.248 ;
     RECT  0.103 33.012 2.16 33.03 ;
     RECT  0.103 34.74 2.16 34.758 ;
     RECT  0.103 37.602 2.16 37.62 ;
     RECT  0.103 39.294 2.16 39.312 ;
     RECT  2.155 42.336 2.16 42.354 ;
     RECT  0.535 45.396 2.16 45.414 ;
     RECT  0.535 46.62 2.16 46.638 ;
     RECT  0.535 48.78 2.16 49.572 ;
     RECT  0.103 50.328 2.16 50.346 ;
     RECT  0.535 52.992 2.16 54.054 ;
     RECT  0.103 58.122 2.16 58.716 ;
     RECT  0.139 60.39 2.16 60.948 ;
     RECT  0.535 63.828 2.16 64.962 ;
     RECT  0.535 68.922 2.16 72.18 ;
     RECT  0.535 74.088 2.16 74.106 ;
     RECT  0.103 76.86 2.16 76.878 ;
     RECT  2.16 1.926 6.215 95.049 ;
     RECT  6.215 2.034 8.375 95.049 ;
     RECT  8.375 2.106 10.355 95.049 ;
     RECT  10.355 2.151 68.323 95.049 ;
     RECT  68.323 2.106 70.871 95.049 ;
     RECT  70.871 2.151 79.735 95.049 ;
     RECT  79.519 0.531 79.807 0.549 ;
     RECT  79.807 0.531 79.907 1.17 ;
     RECT  79.735 2.106 80.231 95.049 ;
     RECT  80.231 2.151 81.067 95.049 ;
     RECT  79.907 0.531 81.599 0.549 ;
     RECT  82.471 0.378 82.571 0.396 ;
     RECT  81.067 2.106 83.183 95.049 ;
     RECT  83.183 2.151 94.711 95.049 ;
     RECT  94.711 2.106 95.04 95.049 ;
     RECT  95.04 2.106 95.639 3.294 ;
     RECT  95.04 42.966 95.747 57.132 ;
     RECT  95.639 2.106 95.783 3.06 ;
     RECT  95.747 42.966 95.783 55.404 ;
     RECT  95.783 2.106 95.927 2.214 ;
     RECT  95.783 3.042 96.071 3.06 ;
     RECT  95.927 2.106 96.215 2.124 ;
     RECT  95.04 38.718 96.323 39.654 ;
     RECT  95.783 42.966 96.323 45.954 ;
     RECT  95.783 47.088 96.323 55.404 ;
     RECT  95.747 56.304 96.323 57.024 ;
     RECT  96.323 42.966 96.359 45.018 ;
     RECT  96.323 47.466 96.359 47.718 ;
     RECT  96.323 48.816 96.359 54.126 ;
     RECT  96.359 43.308 96.395 43.326 ;
     RECT  96.359 47.466 96.395 47.484 ;
     RECT  96.359 49.086 96.395 49.806 ;
     RECT  96.395 49.788 97.043 49.806 ;
     RECT  96.359 52.794 97.079 54.126 ;
     RECT  96.323 39.06 97.115 39.654 ;
     RECT  96.359 44.424 97.115 45.018 ;
     RECT  96.359 50.634 97.115 51.696 ;
     RECT  97.079 52.992 97.115 54.126 ;
     RECT  96.323 56.304 97.115 56.664 ;
    LAYER M3 ;
     RECT  80.244 0.043 80.262 0.091 ;
     RECT  84.024 0.043 84.042 0.091 ;
     RECT  82.152 0.091 83.034 0.139 ;
     RECT  81.54 0.139 83.034 0.187 ;
     RECT  83.772 0.091 86.202 0.187 ;
     RECT  79.884 0.091 80.442 0.235 ;
     RECT  81.54 0.187 86.202 0.235 ;
     RECT  76.716 0.091 78.822 0.52 ;
     RECT  79.884 0.235 86.202 0.52 ;
     RECT  29.916 0.091 33.75 0.523 ;
     RECT  51.264 0.091 56.034 0.523 ;
     RECT  56.952 0.091 56.97 0.523 ;
     RECT  67.068 0.091 71.118 0.523 ;
     RECT  76.716 0.52 86.202 0.557 ;
     RECT  15.156 0.091 21.546 0.571 ;
     RECT  87.264 0.091 94.374 0.571 ;
     RECT  1.728 0.859 1.746 1.003 ;
     RECT  2.844 1.435 2.862 1.579 ;
     RECT  5.328 1.147 5.346 1.723 ;
     RECT  14.832 0.571 21.546 1.723 ;
     RECT  22.428 0.091 22.914 1.723 ;
     RECT  23.76 0.091 28.098 1.723 ;
     RECT  29.736 0.523 33.75 1.723 ;
     RECT  35.856 0.091 44.37 1.723 ;
     RECT  45.756 0.091 49.302 1.723 ;
     RECT  50.148 0.091 50.526 1.723 ;
     RECT  51.264 0.523 56.97 1.723 ;
     RECT  58.428 0.091 63.666 1.723 ;
     RECT  64.584 0.091 64.602 1.723 ;
     RECT  65.52 0.091 66.222 1.723 ;
     RECT  67.068 0.523 71.298 1.723 ;
     RECT  72.288 0.091 75.906 1.723 ;
     RECT  76.716 0.557 78.822 1.723 ;
     RECT  79.812 0.557 86.202 1.723 ;
     RECT  87.264 0.571 96.21 1.723 ;
     RECT  5.328 1.723 5.814 1.921 ;
     RECT  0.108 1.291 0.126 1.949 ;
     RECT  2.772 1.579 2.862 1.993 ;
     RECT  1.728 1.003 1.782 2.011 ;
     RECT  2.772 1.993 3.114 2.011 ;
     RECT  1.728 2.011 3.114 2.021 ;
     RECT  5.328 1.921 6.21 2.029 ;
     RECT  7.056 1.867 7.074 2.029 ;
     RECT  1.764 2.021 3.114 2.065 ;
     RECT  5.328 2.029 7.074 2.101 ;
     RECT  87.12 1.723 96.21 2.129 ;
     RECT  4.68 2.101 7.578 2.143 ;
     RECT  8.352 2.029 8.37 2.143 ;
     RECT  29.556 1.723 57.042 2.143 ;
     RECT  4.68 2.143 8.37 2.191 ;
     RECT  13.215 2.143 13.305 2.191 ;
     RECT  14.472 1.723 28.206 2.219 ;
     RECT  29.415 2.143 57.042 2.219 ;
     RECT  58.32 1.723 86.346 2.219 ;
     RECT  87.12 2.129 96.066 2.219 ;
     RECT  13.176 2.191 13.305 2.227 ;
     RECT  1.764 2.065 3.438 2.255 ;
     RECT  10.332 2.101 10.35 2.263 ;
     RECT  10.224 2.263 10.386 2.335 ;
     RECT  10.224 2.335 10.458 2.371 ;
     RECT  13.14 2.227 13.305 2.413 ;
     RECT  4.356 2.191 8.37 2.461 ;
     RECT  15.156 2.219 21.546 2.525 ;
     RECT  22.428 2.219 22.914 2.525 ;
     RECT  23.76 2.219 28.098 2.525 ;
     RECT  29.415 2.219 44.37 2.525 ;
     RECT  45.615 2.219 56.97 2.525 ;
     RECT  58.428 2.219 63.666 2.525 ;
     RECT  64.584 2.219 64.602 2.525 ;
     RECT  65.52 2.219 86.346 2.525 ;
     RECT  87.264 2.219 96.066 2.525 ;
     RECT  10.224 2.371 10.602 2.533 ;
     RECT  13.14 2.413 13.497 2.533 ;
     RECT  2.304 2.255 3.438 2.569 ;
     RECT  4.356 2.461 8.91 2.569 ;
     RECT  11.988 2.461 12.006 2.569 ;
     RECT  12.816 2.533 13.497 2.569 ;
     RECT  0.144 2.155 0.162 2.605 ;
     RECT  11.988 2.569 13.497 2.605 ;
     RECT  2.304 2.569 8.91 2.641 ;
     RECT  9.72 2.533 10.602 2.641 ;
     RECT  11.988 2.605 14.274 2.641 ;
     RECT  0.144 2.605 0.558 2.861 ;
     RECT  0.54 2.861 0.558 3.053 ;
     RECT  94.215 2.525 96.066 3.065 ;
     RECT  94.215 3.065 95.634 3.209 ;
     RECT  67.215 2.525 74.826 3.271 ;
     RECT  95.616 3.209 95.634 3.299 ;
     RECT  75.564 2.525 85.41 3.379 ;
     RECT  86.184 2.525 86.346 3.379 ;
     RECT  67.104 3.271 74.826 3.415 ;
     RECT  2.304 2.641 14.274 3.451 ;
     RECT  75.564 3.379 86.346 3.451 ;
     RECT  67.032 3.415 74.826 3.569 ;
     RECT  75.564 3.451 87.174 3.605 ;
     RECT  67.104 3.569 74.826 3.613 ;
     RECT  75.564 3.605 85.554 3.613 ;
     RECT  2.196 3.451 14.274 3.677 ;
     RECT  86.364 3.605 87.174 3.683 ;
     RECT  2.304 3.677 14.094 3.713 ;
     RECT  86.94 3.683 87.174 3.721 ;
     RECT  86.94 3.721 87.678 3.839 ;
     RECT  67.104 3.613 85.554 3.947 ;
     RECT  67.104 3.947 85.41 3.965 ;
     RECT  3.564 3.713 14.094 4.109 ;
     RECT  3.564 4.109 13.662 4.379 ;
     RECT  3.564 4.379 13.554 4.495 ;
     RECT  2.304 3.713 2.697 4.621 ;
     RECT  3.492 4.495 13.554 4.621 ;
     RECT  67.104 3.965 84.402 4.919 ;
     RECT  67.215 4.919 84.402 5.063 ;
     RECT  74.484 5.063 84.402 5.189 ;
     RECT  74.664 5.189 84.402 5.305 ;
     RECT  85.212 3.965 85.41 5.305 ;
     RECT  2.304 4.621 13.554 5.341 ;
     RECT  67.215 5.063 73.674 5.603 ;
     RECT  0.54 5.539 0.558 5.789 ;
     RECT  74.664 5.305 85.41 5.873 ;
     RECT  74.88 5.873 85.41 5.909 ;
     RECT  74.88 5.909 76.626 5.999 ;
     RECT  0.144 6.091 0.162 6.221 ;
     RECT  68.688 5.603 73.674 6.275 ;
     RECT  2.304 5.341 13.698 6.277 ;
     RECT  68.868 6.275 73.674 6.305 ;
     RECT  71.064 6.305 73.674 6.413 ;
     RECT  2.304 6.277 13.878 6.421 ;
     RECT  2.304 6.421 14.31 6.619 ;
     RECT  2.304 6.619 14.418 6.809 ;
     RECT  74.88 5.999 76.194 6.817 ;
     RECT  2.304 6.809 14.31 7.259 ;
     RECT  4.428 7.259 14.31 7.349 ;
     RECT  77.58 5.909 85.41 7.349 ;
     RECT  4.428 7.349 14.202 7.385 ;
     RECT  67.215 5.603 67.77 7.735 ;
     RECT  68.868 6.305 70.29 7.735 ;
     RECT  4.428 7.385 13.662 7.889 ;
     RECT  0.108 7.735 0.126 8.093 ;
     RECT  4.428 7.889 13.554 8.159 ;
     RECT  2.304 7.259 3.474 8.275 ;
     RECT  4.428 8.159 13.497 8.275 ;
     RECT  2.304 8.275 13.497 8.735 ;
     RECT  4.284 8.735 13.497 9.005 ;
     RECT  0.144 8.923 0.162 9.053 ;
     RECT  2.304 8.735 3.546 9.211 ;
     RECT  2.268 9.211 3.546 9.347 ;
     RECT  2.304 9.347 3.546 9.481 ;
     RECT  4.284 9.005 12.294 9.481 ;
     RECT  2.304 9.481 12.294 9.689 ;
     RECT  2.304 9.689 3.258 10.049 ;
     RECT  2.304 10.049 3.186 10.085 ;
     RECT  2.415 10.085 3.186 10.121 ;
     RECT  4.248 9.689 12.294 10.165 ;
     RECT  4.248 10.165 12.438 10.435 ;
     RECT  13.215 9.005 13.497 10.435 ;
     RECT  67.215 7.735 70.29 10.769 ;
     RECT  4.248 10.435 13.497 10.859 ;
     RECT  12.96 10.859 13.497 11.129 ;
     RECT  4.248 10.859 12.15 11.131 ;
     RECT  2.415 10.121 2.697 11.281 ;
     RECT  3.636 11.131 12.15 11.281 ;
     RECT  14.832 11.101 14.85 11.309 ;
     RECT  2.415 11.281 12.15 11.371 ;
     RECT  2.304 11.371 12.15 11.849 ;
     RECT  2.304 11.849 11.862 11.939 ;
     RECT  2.304 11.939 11.79 11.975 ;
     RECT  0.216 12.091 0.234 12.235 ;
     RECT  0.108 12.235 0.234 12.517 ;
     RECT  2.304 11.975 11.718 12.557 ;
     RECT  3.744 12.557 11.718 12.901 ;
     RECT  3.744 12.901 11.754 13.171 ;
     RECT  0.108 12.517 0.558 13.277 ;
     RECT  2.304 12.557 2.97 13.405 ;
     RECT  2.268 13.405 2.97 13.565 ;
     RECT  2.304 13.565 2.97 13.981 ;
     RECT  3.744 13.171 12.078 13.981 ;
     RECT  0.108 13.277 0.126 14.285 ;
     RECT  2.304 13.981 12.078 14.377 ;
     RECT  2.304 14.377 12.222 14.477 ;
     RECT  2.304 14.477 12.186 15.223 ;
     RECT  13.215 11.129 13.497 15.223 ;
     RECT  2.304 15.223 13.497 16.267 ;
     RECT  2.196 16.267 13.497 16.397 ;
     RECT  0.108 16.375 0.126 16.733 ;
     RECT  2.304 16.397 13.497 16.807 ;
     RECT  2.304 16.807 13.59 16.951 ;
     RECT  2.304 16.951 13.662 17.753 ;
     RECT  0.54 16.951 0.558 17.885 ;
     RECT  2.304 17.753 13.626 18.841 ;
     RECT  2.304 18.841 13.662 18.907 ;
     RECT  2.304 18.907 13.698 19.075 ;
     RECT  2.304 19.075 13.806 19.769 ;
     RECT  3.996 19.769 13.806 20.039 ;
     RECT  6.912 20.039 13.806 20.075 ;
     RECT  3.996 20.039 6.174 20.219 ;
     RECT  2.304 19.769 3.186 20.299 ;
     RECT  2.268 20.299 3.186 20.345 ;
     RECT  0.144 20.347 0.162 20.425 ;
     RECT  0.144 20.425 0.558 20.477 ;
     RECT  0.54 20.477 0.558 20.621 ;
     RECT  6.912 20.075 13.662 21.091 ;
     RECT  3.996 20.219 6.138 21.127 ;
     RECT  6.876 21.091 13.662 21.127 ;
     RECT  2.304 20.345 3.186 21.451 ;
     RECT  2.304 21.451 3.222 21.505 ;
     RECT  3.996 21.127 13.662 21.505 ;
     RECT  2.304 21.505 13.662 21.533 ;
     RECT  2.304 21.533 13.554 21.695 ;
     RECT  0.54 21.469 0.558 21.917 ;
     RECT  2.304 21.695 13.497 22.171 ;
     RECT  2.268 22.171 13.497 22.307 ;
     RECT  2.304 22.307 13.497 22.577 ;
     RECT  0.144 22.507 0.162 22.747 ;
     RECT  0.144 22.747 0.558 22.925 ;
     RECT  0.54 22.925 0.558 23.069 ;
     RECT  3.996 22.577 13.497 23.371 ;
     RECT  2.304 22.577 3.078 23.431 ;
     RECT  3.996 23.371 13.878 23.431 ;
     RECT  2.304 23.431 13.878 23.701 ;
     RECT  2.304 23.701 14.346 23.819 ;
     RECT  2.304 23.819 13.662 24.233 ;
     RECT  2.304 24.233 13.497 24.431 ;
     RECT  2.304 24.431 3.222 24.935 ;
     RECT  2.415 24.935 3.222 25.447 ;
     RECT  3.996 24.431 13.497 25.447 ;
     RECT  0.144 25.339 0.162 25.661 ;
     RECT  2.415 25.447 13.497 25.915 ;
     RECT  2.304 25.915 13.497 26.635 ;
     RECT  2.304 26.635 13.626 27.301 ;
     RECT  0.108 27.337 0.126 27.389 ;
     RECT  2.304 27.301 13.662 27.743 ;
     RECT  2.304 27.743 13.626 28.075 ;
     RECT  2.268 28.075 13.626 28.211 ;
     RECT  0.144 28.267 0.162 28.397 ;
     RECT  0.54 28.453 0.558 28.541 ;
     RECT  2.268 28.211 13.497 28.949 ;
     RECT  14.832 29.227 14.85 29.399 ;
     RECT  2.304 28.949 13.497 29.759 ;
     RECT  0.144 29.659 0.162 29.789 ;
     RECT  2.304 29.759 12.402 30.569 ;
     RECT  0.144 31.147 0.162 31.225 ;
     RECT  0.108 31.225 0.162 31.421 ;
     RECT  2.304 30.569 12.006 31.693 ;
     RECT  0.144 31.421 0.162 31.853 ;
     RECT  2.304 31.693 12.042 32.341 ;
     RECT  2.268 32.341 12.042 32.429 ;
     RECT  2.304 32.429 12.042 32.773 ;
     RECT  2.304 32.773 12.186 33.151 ;
     RECT  13.215 29.759 13.497 33.151 ;
     RECT  0.108 33.007 0.126 33.293 ;
     RECT  2.304 33.151 12.366 33.349 ;
     RECT  13.14 33.151 13.497 33.349 ;
     RECT  2.304 33.349 13.497 33.449 ;
     RECT  2.304 33.449 12.366 33.539 ;
     RECT  2.304 33.539 12.186 33.575 ;
     RECT  2.304 33.575 11.862 33.611 ;
     RECT  2.304 33.611 11.754 33.953 ;
     RECT  2.304 33.953 11.718 34.115 ;
     RECT  2.304 34.115 11.682 34.385 ;
     RECT  2.415 34.385 11.682 34.541 ;
     RECT  0.324 34.555 0.342 34.732 ;
     RECT  0.108 34.732 0.342 34.733 ;
     RECT  0.108 34.733 0.126 34.877 ;
     RECT  2.415 34.541 2.898 35.131 ;
     RECT  2.304 35.131 2.898 35.323 ;
     RECT  3.672 34.541 11.682 35.323 ;
     RECT  18.615 2.525 18.897 35.401 ;
     RECT  18.468 35.401 18.897 35.581 ;
     RECT  18.18 35.581 18.897 35.885 ;
     RECT  0.144 36.907 0.162 37.037 ;
     RECT  2.304 35.323 11.682 37.355 ;
     RECT  71.1 6.413 73.674 37.741 ;
     RECT  74.808 6.817 76.194 37.741 ;
     RECT  0.108 37.597 0.126 37.757 ;
     RECT  67.215 10.769 70.182 38.173 ;
     RECT  71.1 37.741 76.194 38.173 ;
     RECT  88.815 2.525 89.097 38.281 ;
     RECT  2.415 37.355 11.682 38.299 ;
     RECT  88.815 38.281 89.478 38.395 ;
     RECT  2.304 38.299 11.682 38.435 ;
     RECT  67.215 38.173 76.194 38.443 ;
     RECT  88.815 38.395 89.514 38.443 ;
     RECT  94.215 3.209 94.497 38.479 ;
     RECT  2.34 38.435 11.682 38.507 ;
     RECT  66.204 38.479 66.222 38.515 ;
     RECT  67.104 38.443 76.194 38.515 ;
     RECT  91.8 38.443 91.854 38.515 ;
     RECT  91.8 38.515 92.43 38.551 ;
     RECT  87.66 3.839 87.678 38.579 ;
     RECT  77.58 7.349 81.018 38.677 ;
     RECT  81.792 7.349 85.41 38.677 ;
     RECT  88.815 38.443 89.874 38.677 ;
     RECT  91.044 38.551 91.062 38.677 ;
     RECT  91.8 38.551 92.718 38.677 ;
     RECT  93.636 38.479 94.497 38.677 ;
     RECT  38.628 38.641 38.646 38.713 ;
     RECT  87.732 38.677 87.75 38.713 ;
     RECT  88.524 38.677 94.497 38.713 ;
     RECT  38.304 38.713 38.646 38.717 ;
     RECT  38.304 38.717 38.322 38.765 ;
     RECT  65.808 38.515 76.194 38.785 ;
     RECT  65.808 38.785 76.626 38.947 ;
     RECT  54.108 38.731 54.126 38.971 ;
     RECT  87.732 38.713 94.497 38.983 ;
     RECT  53.748 38.971 54.126 39.011 ;
     RECT  65.556 38.947 76.626 39.091 ;
     RECT  77.58 38.677 85.41 39.091 ;
     RECT  96.3 38.713 96.318 39.091 ;
     RECT  86.904 38.983 86.922 39.119 ;
     RECT  54.108 39.011 54.126 39.149 ;
     RECT  65.556 39.091 85.41 39.209 ;
     RECT  65.556 39.209 76.59 39.217 ;
     RECT  65.412 39.217 76.59 39.259 ;
     RECT  65.376 39.259 76.59 39.289 ;
     RECT  77.58 39.209 85.41 39.289 ;
     RECT  96.3 39.091 96.354 39.307 ;
     RECT  2.415 38.507 11.682 39.341 ;
     RECT  87.732 38.983 94.662 39.451 ;
     RECT  95.724 39.307 96.354 39.451 ;
     RECT  3.816 39.341 11.682 39.479 ;
     RECT  87.732 39.451 96.354 39.479 ;
     RECT  0.108 39.289 0.126 39.485 ;
     RECT  87.732 39.479 95.166 39.515 ;
     RECT  3.816 39.479 10.53 39.533 ;
     RECT  2.415 39.341 2.754 39.595 ;
     RECT  65.304 39.289 76.59 39.595 ;
     RECT  97.092 38.875 97.11 39.659 ;
     RECT  87.732 39.515 94.497 39.749 ;
     RECT  96.336 39.479 96.354 39.773 ;
     RECT  64.944 39.595 76.59 39.785 ;
     RECT  87.732 39.749 91.314 39.785 ;
     RECT  92.232 39.749 93.222 39.785 ;
     RECT  92.232 39.785 93.186 39.821 ;
     RECT  60.12 11.101 60.138 39.829 ;
     RECT  92.232 39.821 92.718 39.857 ;
     RECT  87.804 39.785 91.314 39.893 ;
     RECT  77.58 39.289 85.518 39.991 ;
     RECT  87.804 39.893 91.206 40.019 ;
     RECT  87.948 40.019 91.206 40.091 ;
     RECT  65.16 39.785 76.59 40.135 ;
     RECT  77.58 39.991 85.806 40.135 ;
     RECT  3.816 39.533 10.35 40.171 ;
     RECT  2.304 39.595 2.754 40.261 ;
     RECT  3.6 40.171 10.35 40.261 ;
     RECT  92.484 39.857 92.718 40.289 ;
     RECT  87.948 40.091 91.134 40.325 ;
     RECT  92.484 40.289 92.61 40.325 ;
     RECT  87.948 40.325 90.054 40.361 ;
     RECT  87.948 40.361 90.018 40.433 ;
     RECT  91.008 40.325 91.134 40.469 ;
     RECT  65.16 40.135 85.806 40.493 ;
     RECT  92.592 40.325 92.61 40.559 ;
     RECT  65.16 40.493 76.59 40.667 ;
     RECT  77.58 40.493 85.806 40.711 ;
     RECT  91.008 40.469 91.026 40.739 ;
     RECT  61.815 2.525 62.097 40.801 ;
     RECT  65.16 40.667 75.906 40.837 ;
     RECT  87.948 40.433 89.946 40.865 ;
     RECT  61.776 40.801 62.097 40.873 ;
     RECT  62.856 40.333 62.874 40.873 ;
     RECT  0.144 40.747 0.162 40.877 ;
     RECT  61.776 40.873 62.874 40.973 ;
     RECT  48.456 41.071 48.474 41.117 ;
     RECT  47.7 41.131 47.718 41.171 ;
     RECT  18.615 35.885 18.897 41.275 ;
     RECT  24.015 2.525 24.297 41.275 ;
     RECT  29.415 2.525 29.697 41.275 ;
     RECT  34.815 2.525 35.097 41.275 ;
     RECT  40.215 2.525 40.497 41.275 ;
     RECT  45.615 2.525 45.897 41.275 ;
     RECT  88.128 40.865 89.946 41.279 ;
     RECT  18.615 41.275 18.99 41.405 ;
     RECT  24.015 41.275 24.39 41.405 ;
     RECT  29.415 41.275 29.79 41.405 ;
     RECT  34.815 41.275 35.19 41.405 ;
     RECT  40.215 41.275 40.59 41.405 ;
     RECT  45.615 41.275 45.99 41.405 ;
     RECT  77.58 40.711 86.022 41.449 ;
     RECT  0.18 41.131 0.306 41.453 ;
     RECT  62.856 40.973 62.874 41.485 ;
     RECT  64.944 40.837 75.906 41.611 ;
     RECT  64.404 41.611 75.906 41.683 ;
     RECT  0.216 41.453 0.306 41.741 ;
     RECT  2.304 40.261 10.35 41.755 ;
     RECT  11.448 39.479 11.682 41.755 ;
     RECT  60.12 39.829 60.282 41.755 ;
     RECT  64.26 41.683 75.906 41.755 ;
     RECT  60.12 41.755 61.002 41.917 ;
     RECT  61.776 40.973 62.097 41.917 ;
     RECT  87.228 41.791 87.246 41.989 ;
     RECT  2.304 41.755 11.682 42.025 ;
     RECT  13.215 33.449 13.497 42.043 ;
     RECT  24.015 41.405 24.297 42.043 ;
     RECT  34.815 41.405 35.097 42.043 ;
     RECT  45.615 41.405 45.897 42.043 ;
     RECT  56.415 2.525 56.697 42.043 ;
     RECT  64.224 41.755 75.906 42.053 ;
     RECT  13.104 42.043 13.497 42.089 ;
     RECT  23.904 42.043 24.297 42.089 ;
     RECT  34.704 42.043 35.097 42.089 ;
     RECT  45.504 42.043 45.897 42.089 ;
     RECT  56.304 42.043 56.697 42.089 ;
     RECT  76.968 41.449 86.022 42.151 ;
     RECT  60.12 41.917 62.097 42.187 ;
     RECT  62.856 41.485 63.27 42.187 ;
     RECT  87.228 41.989 87.714 42.215 ;
     RECT  72.468 42.053 75.906 42.235 ;
     RECT  76.968 42.151 86.058 42.235 ;
     RECT  58.752 42.187 58.77 42.259 ;
     RECT  64.224 42.053 71.73 42.323 ;
     RECT  2.268 42.025 11.682 42.331 ;
     RECT  60.048 42.187 63.27 42.331 ;
     RECT  64.224 42.323 71.622 42.331 ;
     RECT  92.34 42.061 92.358 42.331 ;
     RECT  72.468 42.235 86.058 42.359 ;
     RECT  2.16 42.331 11.682 42.368 ;
     RECT  87.408 42.215 87.714 42.421 ;
     RECT  88.815 41.279 89.946 42.421 ;
     RECT  90.864 42.223 90.882 42.421 ;
     RECT  92.34 42.331 92.43 42.421 ;
     RECT  58.752 42.259 58.842 42.457 ;
     RECT  76.968 42.359 86.058 42.457 ;
     RECT  92.34 42.421 92.646 42.457 ;
     RECT  58.752 42.457 58.95 42.475 ;
     RECT  2.304 42.368 11.682 42.529 ;
     RECT  58.716 42.475 58.95 42.529 ;
     RECT  0.288 41.741 0.306 42.571 ;
     RECT  0.288 42.571 0.558 42.601 ;
     RECT  90.864 42.421 91.242 42.601 ;
     RECT  92.34 42.457 92.682 42.601 ;
     RECT  0.108 42.601 0.558 42.629 ;
     RECT  76.968 42.457 86.67 42.629 ;
     RECT  0.108 42.629 0.306 42.653 ;
     RECT  72.468 42.359 76.23 42.653 ;
     RECT  2.304 42.529 11.97 42.719 ;
     RECT  58.716 42.529 59.022 42.719 ;
     RECT  2.304 42.719 11.754 42.755 ;
     RECT  16.02 42.457 16.038 42.755 ;
     RECT  60.048 42.331 71.622 42.755 ;
     RECT  60.048 42.755 64.422 42.763 ;
     RECT  90.864 42.601 92.682 42.763 ;
     RECT  2.304 42.755 11.682 42.791 ;
     RECT  87.408 42.421 89.946 42.799 ;
     RECT  14.724 42.799 14.742 42.835 ;
     RECT  59.904 42.763 64.422 42.835 ;
     RECT  87.408 42.799 90.09 42.835 ;
     RECT  90.864 42.763 92.754 42.835 ;
     RECT  14.724 42.835 14.814 42.899 ;
     RECT  72.468 42.653 75.942 42.899 ;
     RECT  14.796 42.899 14.814 42.989 ;
     RECT  77.58 42.629 86.67 42.997 ;
     RECT  87.408 42.835 92.754 42.997 ;
     RECT  72.468 42.899 75.654 43.061 ;
     RECT  77.58 42.997 92.754 43.069 ;
     RECT  2.304 42.791 11.574 43.133 ;
     RECT  77.58 43.069 93.15 43.141 ;
     RECT  94.215 39.749 94.497 43.141 ;
     RECT  2.304 43.133 11.43 43.169 ;
     RECT  72.468 43.061 75.33 43.169 ;
     RECT  96.336 42.961 96.354 43.231 ;
     RECT  2.304 43.169 11.358 43.259 ;
     RECT  59.544 42.835 64.422 43.259 ;
     RECT  72.468 43.169 75.078 43.267 ;
     RECT  2.304 43.259 2.826 43.295 ;
     RECT  95.76 43.231 96.354 43.303 ;
     RECT  59.544 43.259 60.138 43.331 ;
     RECT  65.232 42.755 71.622 43.375 ;
     RECT  72.432 43.267 75.078 43.375 ;
     RECT  60.948 43.259 64.422 43.403 ;
     RECT  77.58 43.141 94.497 43.411 ;
     RECT  95.76 43.303 96.39 43.483 ;
     RECT  60.984 43.403 64.422 43.501 ;
     RECT  65.232 43.375 75.078 43.501 ;
     RECT  95.724 43.483 96.39 43.601 ;
     RECT  77.58 43.411 94.554 43.645 ;
     RECT  76.968 43.645 94.554 43.799 ;
     RECT  77.004 43.799 94.554 43.805 ;
     RECT  96.3 43.601 96.39 43.805 ;
     RECT  60.984 43.501 75.078 43.835 ;
     RECT  87.12 43.805 94.554 43.835 ;
     RECT  87.192 43.835 94.554 43.843 ;
     RECT  60.984 43.835 61.002 43.871 ;
     RECT  0.144 42.653 0.306 43.901 ;
     RECT  61.815 43.835 75.078 43.915 ;
     RECT  96.3 43.805 96.354 44.093 ;
     RECT  77.004 43.805 86.346 44.177 ;
     RECT  2.304 43.295 2.697 44.185 ;
     RECT  58.716 42.719 58.806 44.339 ;
     RECT  18.615 41.405 18.897 44.443 ;
     RECT  58.788 44.339 58.806 44.447 ;
     RECT  53.928 44.443 53.946 44.581 ;
     RECT  77.544 44.177 86.346 44.581 ;
     RECT  87.192 43.843 95.202 44.581 ;
     RECT  56.415 42.089 56.697 44.587 ;
     RECT  61.815 43.915 75.186 44.609 ;
     RECT  2.304 44.185 2.97 44.617 ;
     RECT  74.628 44.609 74.718 44.645 ;
     RECT  2.268 44.617 2.97 44.669 ;
     RECT  96.3 44.093 96.318 44.669 ;
     RECT  74.7 44.645 74.718 44.681 ;
     RECT  55.836 44.587 56.79 44.717 ;
     RECT  3.924 43.259 11.358 44.789 ;
     RECT  18 44.443 18.897 44.879 ;
     RECT  53.928 44.581 54.126 44.879 ;
     RECT  53.928 44.879 53.946 44.909 ;
     RECT  18.324 44.879 18.897 44.957 ;
     RECT  77.544 44.581 95.202 45.019 ;
     RECT  61.815 44.609 73.746 45.053 ;
     RECT  97.092 44.419 97.11 45.101 ;
     RECT  76.932 45.019 95.202 45.185 ;
     RECT  77.004 45.185 95.202 45.211 ;
     RECT  2.304 44.669 2.97 45.265 ;
     RECT  3.924 44.789 10.17 45.265 ;
     RECT  0.288 43.901 0.306 45.391 ;
     RECT  75.6 45.019 75.618 45.391 ;
     RECT  61.815 45.053 73.314 45.455 ;
     RECT  77.004 45.211 95.742 45.499 ;
     RECT  58.788 45.301 58.806 45.563 ;
     RECT  60.984 45.463 61.002 45.563 ;
     RECT  61.815 45.455 62.982 45.563 ;
     RECT  0.288 45.391 0.558 45.677 ;
     RECT  75.6 45.391 75.798 45.689 ;
     RECT  77.004 45.499 96.318 45.725 ;
     RECT  2.304 45.265 10.17 45.931 ;
     RECT  11.196 44.789 11.358 45.931 ;
     RECT  2.304 45.931 11.358 45.959 ;
     RECT  2.304 45.959 3.402 45.965 ;
     RECT  77.508 45.725 96.318 45.968 ;
     RECT  75.528 45.841 75.546 46.157 ;
     RECT  77.508 45.968 95.778 46.253 ;
     RECT  77.544 46.253 95.778 46.397 ;
     RECT  77.544 46.397 94.662 46.499 ;
     RECT  61.815 45.563 62.946 46.543 ;
     RECT  64.26 45.455 73.314 46.607 ;
     RECT  0.288 45.677 0.306 46.615 ;
     RECT  71.568 46.607 73.314 46.643 ;
     RECT  64.26 46.607 70.794 46.679 ;
     RECT  74.664 45.769 74.682 46.679 ;
     RECT  64.26 46.679 69.642 46.685 ;
     RECT  70.452 46.679 70.794 46.685 ;
     RECT  61.815 46.543 63.27 46.733 ;
     RECT  2.415 45.965 3.402 46.741 ;
     RECT  4.32 45.959 11.358 46.741 ;
     RECT  2.415 46.741 11.358 46.769 ;
     RECT  71.568 46.643 71.658 46.769 ;
     RECT  71.568 46.769 71.586 46.805 ;
     RECT  0.288 46.615 0.558 46.829 ;
     RECT  64.26 46.685 69.606 46.877 ;
     RECT  2.415 46.769 2.697 46.885 ;
     RECT  61.815 46.733 62.946 46.885 ;
     RECT  58.716 46.813 58.734 47.083 ;
     RECT  95.724 46.397 95.778 47.083 ;
     RECT  64.26 46.877 69.174 47.147 ;
     RECT  68.58 47.147 69.174 47.183 ;
     RECT  77.58 46.499 94.662 47.227 ;
     RECT  95.724 47.083 96.318 47.227 ;
     RECT  58.716 47.083 58.806 47.309 ;
     RECT  77.58 47.227 96.318 47.317 ;
     RECT  61.524 46.885 62.946 47.353 ;
     RECT  64.26 47.147 67.842 47.353 ;
     RECT  68.76 47.183 69.174 47.453 ;
     RECT  76.932 47.317 96.318 47.461 ;
     RECT  2.304 46.885 2.697 47.515 ;
     RECT  61.164 47.353 62.946 47.579 ;
     RECT  70.452 46.685 70.47 47.579 ;
     RECT  2.268 47.515 2.697 47.587 ;
     RECT  3.564 46.769 11.358 47.587 ;
     RECT  58.716 47.309 58.734 47.651 ;
     RECT  2.268 47.587 11.358 47.687 ;
     RECT  64.044 47.353 67.842 47.723 ;
     RECT  76.932 47.461 96.39 47.837 ;
     RECT  64.332 47.723 67.842 47.849 ;
     RECT  68.76 47.453 68.778 47.849 ;
     RECT  64.332 47.849 65.79 47.885 ;
     RECT  76.932 47.837 96.354 47.885 ;
     RECT  61.524 47.579 62.946 47.993 ;
     RECT  0.288 46.829 0.306 48.091 ;
     RECT  59.544 43.331 59.706 48.119 ;
     RECT  2.304 47.687 11.358 48.127 ;
     RECT  13.215 42.089 13.497 48.127 ;
     RECT  67.215 47.849 67.842 48.155 ;
     RECT  2.304 48.127 11.718 48.199 ;
     RECT  12.636 48.127 13.497 48.199 ;
     RECT  0.144 48.091 0.306 48.221 ;
     RECT  77.148 47.885 96.354 48.299 ;
     RECT  61.815 47.993 62.946 48.389 ;
     RECT  59.688 48.119 59.706 48.425 ;
     RECT  61.815 48.389 62.298 48.425 ;
     RECT  0.288 48.221 0.306 48.775 ;
     RECT  77.148 48.299 95.202 48.803 ;
     RECT  77.148 48.803 89.658 48.965 ;
     RECT  77.76 48.965 89.658 49.001 ;
     RECT  96.336 48.299 96.354 49.081 ;
     RECT  90.54 48.803 95.202 49.243 ;
     RECT  96.336 49.081 96.39 49.243 ;
     RECT  0.288 48.775 0.558 49.277 ;
     RECT  90.54 49.243 96.39 49.307 ;
     RECT  78.015 49.001 89.658 49.675 ;
     RECT  90.54 49.307 94.554 49.675 ;
     RECT  95.724 49.307 96.39 49.675 ;
     RECT  0.504 49.277 0.558 49.709 ;
     RECT  2.304 48.199 13.497 49.739 ;
     RECT  78.015 49.675 94.554 49.775 ;
     RECT  95.724 49.675 97.038 49.811 ;
     RECT  87.264 49.775 94.554 50.251 ;
     RECT  95.724 49.811 96.354 50.251 ;
     RECT  2.304 49.739 12.222 50.279 ;
     RECT  78.015 49.775 86.346 50.279 ;
     RECT  0.504 49.709 0.522 50.285 ;
     RECT  78.015 50.279 78.39 50.351 ;
     RECT  79.2 50.279 79.362 50.423 ;
     RECT  80.244 50.279 86.346 50.423 ;
     RECT  87.264 50.251 96.354 50.459 ;
     RECT  80.244 50.423 80.802 50.477 ;
     RECT  2.304 50.279 12.078 50.549 ;
     RECT  79.344 50.423 79.362 50.549 ;
     RECT  80.424 50.477 80.802 50.549 ;
     RECT  81.72 50.423 86.346 50.549 ;
     RECT  82.728 50.549 86.238 50.585 ;
     RECT  82.728 50.585 86.094 50.621 ;
     RECT  96.336 50.459 96.354 50.665 ;
     RECT  97.092 50.539 97.11 50.665 ;
     RECT  83.124 50.621 86.094 50.729 ;
     RECT  84.564 50.729 86.094 50.819 ;
     RECT  0.108 50.323 0.126 50.861 ;
     RECT  87.264 50.459 95.166 50.891 ;
     RECT  84.708 50.819 85.122 50.927 ;
     RECT  85.104 50.927 85.122 51.089 ;
     RECT  2.304 50.549 11.862 51.395 ;
     RECT  96.336 50.665 97.11 51.581 ;
     RECT  86.076 50.819 86.094 51.629 ;
     RECT  97.092 51.581 97.11 51.725 ;
     RECT  2.304 51.395 11.826 51.739 ;
     RECT  96.336 51.581 96.354 51.835 ;
     RECT  2.232 51.739 11.826 51.869 ;
     RECT  96.3 51.835 96.354 51.979 ;
     RECT  95.724 51.979 96.354 52.043 ;
     RECT  87.264 50.891 94.842 52.141 ;
     RECT  2.304 51.869 11.826 52.169 ;
     RECT  87.264 52.141 95.166 52.301 ;
     RECT  2.304 52.169 11.286 52.475 ;
     RECT  2.304 52.475 2.697 52.717 ;
     RECT  96.3 52.043 96.354 52.789 ;
     RECT  2.268 52.717 2.697 52.877 ;
     RECT  96.3 52.789 97.074 52.877 ;
     RECT  97.056 52.877 97.074 52.987 ;
     RECT  97.056 52.987 97.11 53.021 ;
     RECT  2.304 52.877 2.697 53.257 ;
     RECT  2.304 53.257 2.826 53.401 ;
     RECT  3.564 52.475 11.286 53.401 ;
     RECT  87.264 52.301 94.662 53.761 ;
     RECT  95.724 53.275 95.778 53.761 ;
     RECT  83.124 50.729 83.697 53.941 ;
     RECT  97.092 53.021 97.11 54.173 ;
     RECT  87.264 53.761 95.778 54.301 ;
     RECT  0.54 52.987 0.558 54.317 ;
     RECT  86.04 52.789 86.058 54.409 ;
     RECT  87.264 54.301 96.318 54.409 ;
     RECT  85.5 54.409 86.058 54.571 ;
     RECT  87.228 54.409 96.318 54.571 ;
     RECT  85.5 54.571 96.318 54.635 ;
     RECT  0.144 54.571 0.162 54.701 ;
     RECT  83.124 53.941 83.718 54.707 ;
     RECT  85.824 54.635 96.318 54.707 ;
     RECT  82.152 54.607 82.17 54.751 ;
     RECT  81.9 54.751 82.17 54.913 ;
     RECT  83.124 54.707 83.697 54.913 ;
     RECT  80.676 50.549 80.694 54.949 ;
     RECT  81.9 54.913 83.697 54.949 ;
     RECT  12.312 55.051 12.33 55.111 ;
     RECT  12.024 55.111 12.33 55.139 ;
     RECT  12.024 55.139 12.042 55.181 ;
     RECT  2.304 53.401 11.286 55.291 ;
     RECT  85.968 54.707 96.318 55.409 ;
     RECT  80.676 54.949 83.697 55.525 ;
     RECT  80.676 55.525 84.006 55.561 ;
     RECT  80.676 55.561 84.366 55.589 ;
     RECT  80.676 55.589 81.81 55.651 ;
     RECT  80.388 55.651 81.81 55.679 ;
     RECT  67.215 48.155 67.662 55.715 ;
     RECT  78.015 50.351 78.297 55.759 ;
     RECT  2.304 55.291 11.97 55.787 ;
     RECT  82.656 55.589 84.366 55.831 ;
     RECT  78.015 55.759 78.678 55.859 ;
     RECT  80.388 55.679 81.738 55.859 ;
     RECT  85.968 55.409 95.742 55.921 ;
     RECT  82.656 55.831 84.51 55.949 ;
     RECT  84.456 55.949 84.51 56.029 ;
     RECT  85.32 55.921 95.742 56.045 ;
     RECT  84.456 56.029 84.546 56.065 ;
     RECT  85.32 56.045 94.698 56.065 ;
     RECT  84.456 56.065 94.698 56.129 ;
     RECT  2.304 55.787 11.862 56.219 ;
     RECT  13.215 49.739 13.497 56.443 ;
     RECT  82.656 55.949 83.697 56.497 ;
     RECT  95.688 56.045 95.742 56.587 ;
     RECT  78.015 55.859 78.297 56.605 ;
     RECT  80.388 55.859 81.594 56.605 ;
     RECT  97.092 55.723 97.11 56.669 ;
     RECT  13.215 56.443 13.77 56.731 ;
     RECT  80.136 56.605 81.594 56.731 ;
     RECT  82.404 56.497 83.697 56.731 ;
     RECT  80.136 56.731 83.697 56.759 ;
     RECT  80.388 56.759 83.697 56.767 ;
     RECT  80.388 56.767 83.754 56.795 ;
     RECT  84.528 56.129 94.698 56.869 ;
     RECT  95.688 56.587 96.318 56.869 ;
     RECT  78.015 56.605 78.75 56.903 ;
     RECT  80.388 56.795 80.55 56.903 ;
     RECT  84.528 56.869 96.318 56.909 ;
     RECT  81.468 56.795 83.754 56.911 ;
     RECT  81.468 56.911 83.79 56.971 ;
     RECT  84.528 56.909 94.497 56.971 ;
     RECT  2.304 56.219 2.826 57.001 ;
     RECT  3.564 56.219 11.862 57.001 ;
     RECT  13.215 56.731 14.058 57.029 ;
     RECT  81.468 56.971 94.497 57.029 ;
     RECT  95.724 56.909 96.318 57.029 ;
     RECT  80.46 56.903 80.55 57.065 ;
     RECT  85.104 57.029 94.497 57.065 ;
     RECT  80.532 57.065 80.55 57.137 ;
     RECT  81.468 57.029 83.79 57.137 ;
     RECT  95.724 57.029 95.742 57.137 ;
     RECT  81.828 57.137 83.79 57.173 ;
     RECT  85.104 57.065 85.518 57.173 ;
     RECT  81.828 57.173 82.458 57.209 ;
     RECT  83.415 57.173 83.79 57.209 ;
     RECT  85.104 57.173 85.23 57.299 ;
     RECT  86.652 57.065 94.497 57.299 ;
     RECT  85.212 57.299 85.23 57.371 ;
     RECT  86.652 57.299 87.786 57.407 ;
     RECT  86.652 57.407 87.714 57.443 ;
     RECT  88.815 57.299 94.497 57.443 ;
     RECT  81.828 57.209 82.314 57.479 ;
     RECT  0.144 57.355 0.162 57.485 ;
     RECT  82.296 57.479 82.314 57.569 ;
     RECT  86.652 57.443 87.03 57.569 ;
     RECT  88.815 57.443 91.206 57.569 ;
     RECT  93.78 57.443 94.497 57.569 ;
     RECT  13.215 57.029 13.806 57.581 ;
     RECT  88.815 57.569 89.226 57.605 ;
     RECT  90.252 57.569 91.206 57.605 ;
     RECT  92.304 57.443 92.43 57.605 ;
     RECT  90.54 57.605 91.206 57.713 ;
     RECT  93.888 57.569 94.497 57.713 ;
     RECT  91.044 57.713 91.062 57.749 ;
     RECT  92.412 57.605 92.43 57.749 ;
     RECT  0.108 58.117 0.126 58.781 ;
     RECT  2.304 57.001 11.862 58.793 ;
     RECT  2.304 58.793 3.078 59.099 ;
     RECT  3.996 58.793 11.862 59.305 ;
     RECT  3.996 59.305 11.934 59.459 ;
     RECT  3.996 59.459 11.826 59.729 ;
     RECT  3.996 59.729 11.754 59.845 ;
     RECT  3.816 59.845 11.754 59.881 ;
     RECT  2.304 59.099 2.862 59.899 ;
     RECT  3.6 59.881 11.754 59.899 ;
     RECT  0.108 60.385 0.126 60.925 ;
     RECT  0.108 60.925 0.162 61.085 ;
     RECT  2.304 59.899 11.754 61.195 ;
     RECT  2.304 61.195 11.862 61.231 ;
     RECT  2.304 61.231 12.15 61.357 ;
     RECT  0.144 61.085 0.162 61.373 ;
     RECT  2.268 61.357 12.15 61.517 ;
     RECT  2.304 61.517 12.15 61.771 ;
     RECT  2.304 61.771 12.222 61.969 ;
     RECT  2.304 61.969 12.438 62.041 ;
     RECT  13.215 57.581 13.497 62.041 ;
     RECT  2.304 62.041 13.497 62.231 ;
     RECT  2.304 62.231 12.222 63.049 ;
     RECT  13.215 62.231 13.497 63.049 ;
     RECT  2.304 63.049 13.497 63.085 ;
     RECT  2.268 63.085 13.497 63.245 ;
     RECT  2.304 63.245 13.497 63.509 ;
     RECT  0.54 63.823 0.558 63.965 ;
     RECT  0.108 64.327 0.126 64.541 ;
     RECT  2.304 63.509 12.33 64.975 ;
     RECT  0.54 64.939 0.558 65.117 ;
     RECT  2.304 64.975 12.402 65.165 ;
     RECT  2.304 65.165 10.854 65.803 ;
     RECT  2.268 65.803 10.854 65.849 ;
     RECT  11.628 65.165 12.402 65.939 ;
     RECT  2.304 65.849 10.854 66.085 ;
     RECT  11.628 65.939 12.366 66.085 ;
     RECT  0.144 66.571 0.162 66.701 ;
     RECT  2.304 66.085 12.366 66.865 ;
     RECT  13.215 63.509 13.497 66.865 ;
     RECT  80.424 67.243 80.442 67.441 ;
     RECT  2.304 66.865 13.497 67.559 ;
     RECT  80.424 67.441 80.766 67.559 ;
     RECT  2.304 67.559 11.898 67.595 ;
     RECT  80.748 67.559 80.766 67.757 ;
     RECT  2.376 67.595 11.898 67.829 ;
     RECT  2.376 67.829 11.754 67.865 ;
     RECT  2.376 67.865 11.178 68.611 ;
     RECT  0.108 68.917 0.126 68.953 ;
     RECT  2.376 68.611 11.394 69.223 ;
     RECT  2.376 69.223 11.43 69.331 ;
     RECT  2.376 69.331 11.61 69.403 ;
     RECT  2.304 69.403 11.61 69.485 ;
     RECT  2.415 69.485 11.61 69.593 ;
     RECT  2.415 69.593 11.43 69.719 ;
     RECT  0.108 68.953 0.558 69.725 ;
     RECT  2.415 69.719 11.394 70.699 ;
     RECT  2.304 70.699 11.394 71.249 ;
     RECT  0.108 69.725 0.126 71.309 ;
     RECT  2.304 71.249 10.854 71.339 ;
     RECT  2.304 71.339 10.602 72.265 ;
     RECT  2.304 72.265 10.674 72.301 ;
     RECT  0.54 71.725 0.558 72.461 ;
     RECT  2.304 72.301 10.782 72.725 ;
     RECT  2.304 72.725 10.674 74.083 ;
     RECT  2.232 74.083 10.674 74.183 ;
     RECT  0.54 74.083 0.558 74.477 ;
     RECT  2.304 74.183 10.674 74.731 ;
     RECT  2.304 74.731 10.89 74.857 ;
     RECT  2.304 74.857 10.926 74.993 ;
     RECT  2.304 74.993 10.638 75.119 ;
     RECT  2.304 75.119 10.566 75.155 ;
     RECT  2.304 75.155 10.53 75.929 ;
     RECT  2.304 75.929 10.422 75.965 ;
     RECT  2.304 75.965 10.314 76.171 ;
     RECT  2.268 76.171 10.314 76.307 ;
     RECT  0.108 76.855 0.126 77.069 ;
     RECT  2.304 76.307 10.314 77.089 ;
     RECT  2.304 77.089 10.602 77.279 ;
     RECT  2.304 77.279 10.458 77.549 ;
     RECT  2.304 77.549 9.954 77.555 ;
     RECT  2.304 77.555 9.918 77.585 ;
     RECT  4.104 77.585 9.918 77.693 ;
     RECT  2.304 77.585 3.258 77.755 ;
     RECT  2.268 77.755 3.258 77.927 ;
     RECT  4.104 77.693 9.882 77.999 ;
     RECT  2.415 77.927 3.258 78.077 ;
     RECT  2.415 78.077 2.862 78.125 ;
     RECT  4.104 77.999 9.702 78.511 ;
     RECT  3.78 78.511 9.702 78.557 ;
     RECT  4.14 78.557 9.702 78.629 ;
     RECT  4.14 78.629 8.73 79.169 ;
     RECT  4.14 79.169 7.074 79.435 ;
     RECT  3.708 79.435 7.074 79.439 ;
     RECT  3.708 79.439 3.726 79.475 ;
     RECT  4.788 79.439 4.806 79.475 ;
     RECT  5.868 79.439 5.886 79.475 ;
     RECT  6.876 79.439 6.894 79.475 ;
     RECT  65.376 47.885 65.79 93.325 ;
     RECT  65.268 93.325 65.79 93.479 ;
     RECT  64.332 47.885 64.35 93.547 ;
     RECT  64.332 93.547 64.458 93.631 ;
     RECT  65.268 93.479 65.394 93.631 ;
     RECT  64.332 93.631 65.394 93.929 ;
     RECT  72.615 46.643 73.314 94.019 ;
     RECT  64.332 93.929 65.25 94.027 ;
     RECT  64.296 94.027 65.25 94.127 ;
     RECT  64.296 94.127 65.178 94.163 ;
     RECT  64.296 94.163 64.458 94.289 ;
     RECT  64.296 94.289 64.386 94.685 ;
     RECT  2.415 78.125 2.697 94.787 ;
     RECT  7.815 79.169 8.097 94.787 ;
     RECT  13.215 67.559 13.497 94.787 ;
     RECT  18.615 44.957 18.897 94.787 ;
     RECT  24.015 42.089 24.297 94.787 ;
     RECT  29.415 41.405 29.697 94.787 ;
     RECT  34.815 42.089 35.097 94.787 ;
     RECT  40.215 41.405 40.497 94.787 ;
     RECT  45.615 42.089 45.897 94.787 ;
     RECT  51.015 2.525 51.297 94.787 ;
     RECT  56.415 44.717 56.697 94.787 ;
     RECT  61.815 48.425 62.097 94.787 ;
     RECT  67.215 55.715 67.497 94.787 ;
     RECT  72.615 94.019 72.897 94.787 ;
     RECT  78.015 56.903 78.297 94.787 ;
     RECT  83.415 57.209 83.697 94.787 ;
     RECT  88.815 57.605 89.097 94.787 ;
     RECT  94.215 57.713 94.497 94.787 ;
     RECT  2.415 94.787 2.505 95.057 ;
     RECT  7.815 94.787 7.905 95.057 ;
     RECT  13.215 94.787 13.305 95.057 ;
     RECT  18.615 94.787 18.705 95.057 ;
     RECT  24.015 94.787 24.105 95.057 ;
     RECT  29.415 94.787 29.505 95.057 ;
     RECT  34.815 94.787 34.905 95.057 ;
     RECT  40.215 94.787 40.305 95.057 ;
     RECT  45.615 94.787 45.705 95.057 ;
     RECT  51.015 94.787 51.105 95.057 ;
     RECT  56.415 94.787 56.505 95.057 ;
     RECT  61.815 94.787 61.905 95.057 ;
     RECT  67.215 94.787 67.305 95.057 ;
     RECT  72.615 94.787 72.705 95.057 ;
     RECT  78.015 94.787 78.105 95.057 ;
     RECT  83.415 94.787 83.505 95.057 ;
     RECT  88.815 94.787 88.905 95.057 ;
     RECT  94.215 94.787 94.305 95.057 ;
     RECT  64.296 94.685 64.35 95.165 ;
     RECT  64.332 95.165 64.35 96.365 ;
    LAYER M4 ;
     RECT  0.084 0.864 1.757 0.888 ;
     RECT  0.06 0.888 1.757 1.008 ;
     RECT  0.084 1.008 1.757 1.032 ;
     RECT  0.06 1.032 1.757 1.152 ;
     RECT  0.084 1.152 1.757 1.176 ;
     RECT  0.06 1.176 1.757 1.296 ;
     RECT  0.084 1.296 1.757 1.32 ;
     RECT  0.06 1.32 1.757 1.44 ;
     RECT  0.084 1.44 1.757 1.464 ;
     RECT  0.06 1.464 1.757 1.584 ;
     RECT  0.084 1.584 1.757 1.608 ;
     RECT  0.06 1.608 1.757 1.728 ;
     RECT  0.084 1.728 1.757 1.752 ;
     RECT  0.06 1.752 1.757 1.872 ;
     RECT  0.084 1.872 1.757 1.896 ;
     RECT  0.06 1.896 1.757 2.016 ;
     RECT  0.084 2.016 1.757 2.04 ;
     RECT  0.06 2.04 1.757 2.16 ;
     RECT  0.084 2.16 1.757 2.184 ;
     RECT  0.06 2.184 1.757 2.304 ;
     RECT  0.084 2.304 1.757 2.328 ;
     RECT  0.06 2.328 1.757 2.448 ;
     RECT  0.084 2.448 1.757 2.472 ;
     RECT  0.06 2.472 1.757 2.592 ;
     RECT  0.084 2.592 1.757 2.616 ;
     RECT  0.06 2.616 1.757 2.736 ;
     RECT  0.084 2.736 1.757 2.76 ;
     RECT  0.06 2.76 1.757 2.88 ;
     RECT  0.084 2.88 1.757 2.904 ;
     RECT  0.06 2.904 1.757 3.024 ;
     RECT  0.084 3.024 1.757 3.048 ;
     RECT  0.06 3.048 1.757 3.168 ;
     RECT  0.084 3.168 1.757 3.192 ;
     RECT  0.06 3.192 1.757 3.312 ;
     RECT  0.084 3.312 1.757 3.336 ;
     RECT  0.06 3.336 1.757 3.456 ;
     RECT  0.084 3.456 1.757 3.48 ;
     RECT  0.06 3.48 1.757 3.6 ;
     RECT  0.084 3.6 1.757 3.624 ;
     RECT  0.06 3.624 1.757 3.744 ;
     RECT  0.084 3.744 1.757 3.768 ;
     RECT  0.06 3.768 1.757 3.888 ;
     RECT  0.084 3.888 1.757 3.912 ;
     RECT  0.06 3.912 1.757 4.032 ;
     RECT  0.084 4.032 1.757 4.056 ;
     RECT  0.06 4.056 1.757 4.176 ;
     RECT  0.084 4.176 1.757 4.2 ;
     RECT  0.06 4.2 1.757 4.32 ;
     RECT  0.084 4.32 1.757 4.344 ;
     RECT  0.06 4.344 1.757 4.464 ;
     RECT  0.084 4.464 1.757 4.488 ;
     RECT  0.06 4.488 1.757 4.608 ;
     RECT  0.084 4.608 1.757 4.632 ;
     RECT  0.06 4.632 1.757 4.752 ;
     RECT  0.084 4.752 1.757 4.776 ;
     RECT  0.06 4.776 1.757 4.896 ;
     RECT  0.084 4.896 1.757 4.92 ;
     RECT  0.06 4.92 1.757 5.04 ;
     RECT  0.084 5.04 1.757 5.064 ;
     RECT  0.06 5.064 1.757 5.184 ;
     RECT  0.084 5.184 1.757 5.208 ;
     RECT  0.06 5.208 1.757 5.328 ;
     RECT  0.084 5.328 1.757 5.352 ;
     RECT  0.06 5.352 1.757 5.472 ;
     RECT  0.084 5.472 1.757 5.496 ;
     RECT  0.06 5.496 1.757 5.616 ;
     RECT  0.084 5.616 1.757 5.64 ;
     RECT  0.06 5.64 1.757 5.76 ;
     RECT  0.084 5.76 1.757 5.784 ;
     RECT  0.06 5.784 1.757 5.904 ;
     RECT  0.084 5.904 1.757 5.928 ;
     RECT  0.06 5.928 1.757 6.048 ;
     RECT  0.084 6.048 1.757 6.072 ;
     RECT  0.06 6.072 1.757 6.192 ;
     RECT  0.084 6.192 1.757 6.216 ;
     RECT  0.06 6.216 1.757 6.336 ;
     RECT  0.084 6.336 1.757 6.36 ;
     RECT  0.06 6.36 1.757 6.48 ;
     RECT  0.084 6.48 1.757 6.504 ;
     RECT  0.06 6.504 1.757 6.624 ;
     RECT  0.084 6.624 1.757 6.648 ;
     RECT  0.06 6.648 1.757 6.768 ;
     RECT  0.084 6.768 1.757 6.792 ;
     RECT  0.06 6.792 1.757 6.912 ;
     RECT  0.084 6.912 1.757 6.936 ;
     RECT  0.06 6.936 1.757 7.056 ;
     RECT  0.084 7.056 1.757 7.08 ;
     RECT  0.06 7.08 1.757 7.2 ;
     RECT  0.084 7.2 1.757 7.224 ;
     RECT  0.06 7.224 1.757 7.344 ;
     RECT  0.084 7.344 1.757 7.368 ;
     RECT  0.06 7.368 1.757 7.488 ;
     RECT  0.084 7.488 1.757 7.512 ;
     RECT  0.06 7.512 1.757 7.632 ;
     RECT  0.084 7.632 1.757 7.656 ;
     RECT  0.06 7.656 1.757 7.776 ;
     RECT  0.084 7.776 1.757 7.8 ;
     RECT  0.06 7.8 1.757 7.92 ;
     RECT  0.084 7.92 1.757 7.944 ;
     RECT  0.06 7.944 1.757 8.064 ;
     RECT  0.084 8.064 1.757 8.088 ;
     RECT  0.06 8.088 1.757 8.208 ;
     RECT  0.084 8.208 1.757 8.232 ;
     RECT  0.06 8.232 1.757 8.352 ;
     RECT  0.084 8.352 1.757 8.376 ;
     RECT  0.06 8.376 1.757 8.496 ;
     RECT  0.084 8.496 1.757 8.52 ;
     RECT  0.06 8.52 1.757 8.64 ;
     RECT  0.084 8.64 1.757 8.664 ;
     RECT  0.06 8.664 1.757 8.784 ;
     RECT  0.084 8.784 1.757 8.808 ;
     RECT  0.06 8.808 1.757 8.928 ;
     RECT  0.084 8.928 1.757 8.952 ;
     RECT  0.06 8.952 1.757 9.072 ;
     RECT  0.084 9.072 1.757 9.096 ;
     RECT  0.06 9.096 1.757 9.216 ;
     RECT  0.084 9.216 1.757 9.24 ;
     RECT  0.06 9.24 1.757 9.36 ;
     RECT  0.084 9.36 1.757 9.384 ;
     RECT  0.06 9.384 1.757 9.504 ;
     RECT  0.084 9.504 1.757 9.528 ;
     RECT  0.06 9.528 1.757 9.648 ;
     RECT  0.084 9.648 1.757 9.672 ;
     RECT  0.06 9.672 1.757 9.792 ;
     RECT  0.084 9.792 1.757 9.816 ;
     RECT  0.06 9.816 1.757 9.936 ;
     RECT  0.084 9.936 1.757 9.96 ;
     RECT  1.757 1.008 1.793 9.96 ;
     RECT  1.793 1.152 2.408 9.96 ;
     RECT  0.084 11.232 2.408 11.256 ;
     RECT  0.06 11.256 2.408 11.376 ;
     RECT  0.084 11.376 2.408 11.4 ;
     RECT  0.06 11.4 2.408 11.52 ;
     RECT  0.084 11.52 2.408 11.544 ;
     RECT  0.06 11.544 2.408 11.664 ;
     RECT  0.084 11.664 2.408 11.688 ;
     RECT  0.06 11.688 2.408 11.808 ;
     RECT  0.084 11.808 2.408 11.832 ;
     RECT  0.06 11.832 2.408 11.952 ;
     RECT  0.084 11.952 2.408 11.976 ;
     RECT  0.06 11.976 2.408 12.096 ;
     RECT  0.084 12.096 2.408 12.12 ;
     RECT  0.06 12.12 2.408 12.24 ;
     RECT  0.084 12.24 2.408 12.264 ;
     RECT  0.06 12.264 2.408 12.384 ;
     RECT  0.084 12.384 2.408 12.408 ;
     RECT  0.06 12.408 2.408 12.528 ;
     RECT  0.084 12.528 2.408 12.552 ;
     RECT  0.06 12.552 2.408 12.672 ;
     RECT  0.084 12.672 2.408 12.696 ;
     RECT  0.06 12.696 2.408 12.816 ;
     RECT  0.084 12.816 2.408 12.84 ;
     RECT  0.06 12.84 2.408 12.96 ;
     RECT  0.084 12.96 2.408 12.984 ;
     RECT  0.06 12.984 2.408 13.104 ;
     RECT  0.084 13.104 2.408 13.128 ;
     RECT  0.06 13.128 2.408 13.248 ;
     RECT  0.084 13.248 2.408 13.272 ;
     RECT  0.06 13.272 2.408 13.392 ;
     RECT  0.084 13.392 2.408 13.416 ;
     RECT  0.06 13.416 2.408 13.536 ;
     RECT  0.084 13.536 2.408 13.56 ;
     RECT  0.06 13.56 2.408 13.68 ;
     RECT  0.084 13.68 2.408 13.704 ;
     RECT  0.06 13.704 2.408 13.824 ;
     RECT  0.084 13.824 2.408 13.848 ;
     RECT  0.06 13.848 2.408 13.968 ;
     RECT  0.084 13.968 2.408 13.992 ;
     RECT  0.06 13.992 2.408 14.112 ;
     RECT  0.084 14.112 2.408 14.136 ;
     RECT  0.06 14.136 2.408 14.256 ;
     RECT  0.084 14.256 2.408 14.28 ;
     RECT  0.06 14.28 2.408 14.4 ;
     RECT  0.084 14.4 2.408 14.424 ;
     RECT  0.06 14.424 2.408 14.544 ;
     RECT  0.084 14.544 2.408 14.568 ;
     RECT  0.06 14.568 2.408 14.688 ;
     RECT  0.084 14.688 2.408 14.712 ;
     RECT  0.06 14.712 2.408 14.832 ;
     RECT  0.084 14.832 2.408 14.856 ;
     RECT  0.06 14.856 2.408 14.976 ;
     RECT  0.084 14.976 2.408 15 ;
     RECT  0.06 15 2.408 15.12 ;
     RECT  0.084 15.12 2.408 15.144 ;
     RECT  0.06 15.144 2.408 15.264 ;
     RECT  0.084 15.264 2.408 15.288 ;
     RECT  0.06 15.288 2.408 15.408 ;
     RECT  0.084 15.408 2.408 15.432 ;
     RECT  0.06 15.432 2.408 15.552 ;
     RECT  0.084 15.552 2.408 15.576 ;
     RECT  0.06 15.576 2.408 15.696 ;
     RECT  0.084 15.696 2.408 15.72 ;
     RECT  0.06 15.72 2.408 15.84 ;
     RECT  0.084 15.84 2.408 15.864 ;
     RECT  0.06 15.864 2.408 15.984 ;
     RECT  0.084 15.984 2.408 16.008 ;
     RECT  0.06 16.008 2.408 16.128 ;
     RECT  0.084 16.128 2.408 16.152 ;
     RECT  0.06 16.152 2.408 16.272 ;
     RECT  0.084 16.272 2.408 16.296 ;
     RECT  0.06 16.296 2.408 16.416 ;
     RECT  0.084 16.416 2.408 16.44 ;
     RECT  0.06 16.44 2.408 16.56 ;
     RECT  0.084 16.56 2.408 16.584 ;
     RECT  0.06 16.584 2.408 16.704 ;
     RECT  0.084 16.704 2.408 16.728 ;
     RECT  0.06 16.728 2.408 16.848 ;
     RECT  0.084 16.848 2.408 16.872 ;
     RECT  0.06 16.872 2.408 16.992 ;
     RECT  0.084 16.992 2.408 17.016 ;
     RECT  0.06 17.016 2.408 17.136 ;
     RECT  0.084 17.136 2.408 17.16 ;
     RECT  0.06 17.16 2.408 17.28 ;
     RECT  0.084 17.28 2.408 17.304 ;
     RECT  0.06 17.304 2.408 17.424 ;
     RECT  0.084 17.424 2.408 17.448 ;
     RECT  0.06 17.448 2.408 17.568 ;
     RECT  0.084 17.568 2.408 17.592 ;
     RECT  0.06 17.592 2.408 17.712 ;
     RECT  0.084 17.712 2.408 17.736 ;
     RECT  0.06 17.736 2.408 17.856 ;
     RECT  0.084 17.856 2.408 17.88 ;
     RECT  0.06 17.88 2.408 18 ;
     RECT  0.084 18 2.408 18.024 ;
     RECT  0.06 18.024 2.408 18.144 ;
     RECT  0.084 18.144 2.408 18.168 ;
     RECT  0.06 18.168 2.408 18.288 ;
     RECT  0.084 18.288 2.408 18.312 ;
     RECT  0.06 18.312 2.408 18.432 ;
     RECT  0.084 18.432 2.408 18.456 ;
     RECT  0.06 18.456 2.408 18.576 ;
     RECT  0.084 18.576 2.408 18.6 ;
     RECT  0.06 18.6 2.408 18.72 ;
     RECT  0.084 18.72 2.408 18.744 ;
     RECT  0.06 18.744 2.408 18.864 ;
     RECT  0.084 18.864 2.408 18.888 ;
     RECT  0.06 18.888 2.408 19.008 ;
     RECT  0.084 19.008 2.408 19.032 ;
     RECT  0.06 19.032 2.408 19.152 ;
     RECT  0.084 19.152 2.408 19.176 ;
     RECT  0.06 19.176 2.408 19.296 ;
     RECT  0.084 19.296 2.408 19.32 ;
     RECT  0.06 19.32 2.408 19.44 ;
     RECT  0.084 19.44 2.408 19.464 ;
     RECT  0.06 19.464 2.408 19.584 ;
     RECT  0.084 19.584 2.408 19.608 ;
     RECT  0.06 19.608 2.408 19.728 ;
     RECT  0.084 19.728 2.408 19.752 ;
     RECT  0.06 19.752 2.408 19.872 ;
     RECT  0.084 19.872 2.408 19.896 ;
     RECT  0.06 19.896 2.408 20.016 ;
     RECT  0.084 20.016 2.408 20.04 ;
     RECT  0.06 20.04 2.408 20.16 ;
     RECT  0.084 20.16 2.408 20.184 ;
     RECT  0.06 20.184 2.408 20.304 ;
     RECT  0.084 20.304 2.408 20.328 ;
     RECT  0.06 20.328 2.408 20.448 ;
     RECT  0.084 20.448 2.408 20.472 ;
     RECT  0.06 20.472 2.408 20.592 ;
     RECT  0.084 20.592 2.408 20.616 ;
     RECT  0.06 20.616 2.408 20.736 ;
     RECT  0.084 20.736 2.408 20.76 ;
     RECT  0.06 20.76 2.408 20.88 ;
     RECT  0.084 20.88 2.408 20.904 ;
     RECT  0.06 20.904 2.408 21.024 ;
     RECT  0.084 21.024 2.408 21.048 ;
     RECT  0.06 21.048 2.408 21.168 ;
     RECT  0.084 21.168 2.408 21.192 ;
     RECT  0.06 21.192 2.408 21.312 ;
     RECT  0.084 21.312 2.408 21.336 ;
     RECT  0.06 21.336 2.408 21.456 ;
     RECT  0.084 21.456 2.408 21.48 ;
     RECT  0.06 21.48 2.408 21.6 ;
     RECT  0.084 21.6 2.408 21.624 ;
     RECT  0.06 21.624 2.408 21.744 ;
     RECT  0.084 21.744 2.408 21.768 ;
     RECT  0.06 21.768 2.408 21.888 ;
     RECT  0.084 21.888 2.408 21.912 ;
     RECT  0.06 21.912 2.408 22.032 ;
     RECT  0.084 22.032 2.408 22.056 ;
     RECT  0.06 22.056 2.408 22.176 ;
     RECT  0.084 22.176 2.408 22.2 ;
     RECT  0.06 22.2 2.408 22.32 ;
     RECT  0.084 22.32 2.408 22.344 ;
     RECT  0.06 22.344 2.408 22.464 ;
     RECT  0.084 22.464 2.408 22.488 ;
     RECT  0.06 22.488 2.408 22.608 ;
     RECT  0.084 22.608 2.408 22.632 ;
     RECT  0.06 22.632 2.408 22.752 ;
     RECT  0.084 22.752 2.408 22.776 ;
     RECT  0.06 22.776 2.408 22.896 ;
     RECT  0.084 22.896 2.408 22.92 ;
     RECT  0.06 22.92 2.408 23.04 ;
     RECT  0.084 23.04 2.408 23.064 ;
     RECT  0.06 23.064 2.408 23.184 ;
     RECT  0.084 23.184 2.408 23.208 ;
     RECT  0.06 23.208 2.408 23.328 ;
     RECT  0.084 23.328 2.408 23.352 ;
     RECT  0.06 23.352 2.408 23.472 ;
     RECT  0.084 23.472 2.408 23.496 ;
     RECT  0.06 23.496 2.408 23.616 ;
     RECT  0.084 23.616 2.408 23.64 ;
     RECT  0.06 23.64 2.408 23.76 ;
     RECT  0.084 23.76 2.408 23.784 ;
     RECT  0.06 23.784 2.408 23.904 ;
     RECT  0.084 23.904 2.408 23.928 ;
     RECT  0.06 23.928 2.408 24.048 ;
     RECT  0.084 24.048 2.408 24.072 ;
     RECT  0.06 24.072 2.408 24.192 ;
     RECT  0.084 24.192 2.408 24.216 ;
     RECT  0.06 24.216 2.408 24.336 ;
     RECT  0.084 24.336 2.408 24.36 ;
     RECT  0.06 24.36 2.408 24.48 ;
     RECT  0.084 24.48 2.408 24.504 ;
     RECT  0.06 24.504 2.408 24.624 ;
     RECT  0.084 24.624 2.408 24.648 ;
     RECT  0.06 24.648 2.408 24.768 ;
     RECT  0.084 24.768 2.408 24.792 ;
     RECT  0.06 24.792 2.408 24.912 ;
     RECT  0.084 24.912 2.408 24.936 ;
     RECT  0.06 24.936 2.408 25.056 ;
     RECT  0.084 25.056 2.408 25.08 ;
     RECT  0.06 25.08 2.408 25.2 ;
     RECT  0.084 25.2 2.408 25.224 ;
     RECT  0.06 25.224 2.408 25.344 ;
     RECT  0.084 25.344 2.408 25.368 ;
     RECT  0.06 25.368 2.408 25.488 ;
     RECT  0.084 25.488 2.408 25.512 ;
     RECT  0.06 25.512 2.408 25.632 ;
     RECT  0.084 25.632 2.408 25.656 ;
     RECT  0.06 25.656 2.408 25.776 ;
     RECT  0.084 25.776 2.408 25.8 ;
     RECT  0.06 25.8 2.408 25.92 ;
     RECT  0.084 25.92 2.408 25.944 ;
     RECT  0.06 25.944 2.408 26.064 ;
     RECT  0.084 26.064 2.408 26.088 ;
     RECT  0.06 26.088 2.408 26.208 ;
     RECT  0.084 26.208 2.408 26.232 ;
     RECT  0.06 26.232 2.408 26.352 ;
     RECT  0.084 26.352 2.408 26.376 ;
     RECT  0.06 26.376 2.408 26.496 ;
     RECT  0.084 26.496 2.408 26.52 ;
     RECT  0.06 26.52 2.408 26.64 ;
     RECT  0.084 26.64 2.408 26.664 ;
     RECT  0.06 26.664 2.408 26.784 ;
     RECT  0.084 26.784 2.408 26.808 ;
     RECT  0.06 26.808 2.408 26.928 ;
     RECT  0.084 26.928 2.408 26.952 ;
     RECT  0.06 26.952 2.408 27.072 ;
     RECT  0.084 27.072 2.408 27.096 ;
     RECT  0.06 27.096 2.408 27.216 ;
     RECT  0.084 27.216 2.408 27.24 ;
     RECT  0.06 27.24 2.408 27.36 ;
     RECT  0.084 27.36 2.408 27.384 ;
     RECT  0.06 27.384 2.408 27.504 ;
     RECT  0.084 27.504 2.408 27.528 ;
     RECT  0.06 27.528 2.408 27.648 ;
     RECT  0.084 27.648 2.408 27.672 ;
     RECT  0.06 27.672 2.408 27.792 ;
     RECT  0.084 27.792 2.408 27.816 ;
     RECT  0.06 27.816 2.408 27.936 ;
     RECT  0.084 27.936 2.408 27.96 ;
     RECT  0.06 27.96 2.408 28.08 ;
     RECT  0.084 28.08 2.408 28.104 ;
     RECT  0.06 28.104 2.408 28.224 ;
     RECT  0.084 28.224 2.408 28.248 ;
     RECT  0.06 28.248 2.408 28.368 ;
     RECT  0.084 28.368 2.408 28.392 ;
     RECT  0.06 28.392 2.408 28.512 ;
     RECT  0.084 28.512 2.408 28.536 ;
     RECT  0.06 28.536 2.408 28.656 ;
     RECT  0.084 28.656 2.408 28.68 ;
     RECT  0.06 28.68 2.408 28.8 ;
     RECT  0.084 28.8 2.408 28.824 ;
     RECT  0.06 28.824 2.408 28.944 ;
     RECT  0.084 28.944 2.408 28.968 ;
     RECT  0.06 28.968 2.408 29.088 ;
     RECT  0.084 29.088 2.408 29.112 ;
     RECT  0.06 29.112 2.408 29.232 ;
     RECT  0.084 29.232 2.408 29.256 ;
     RECT  0.06 29.256 2.408 29.376 ;
     RECT  0.084 29.376 2.408 29.4 ;
     RECT  0.06 29.4 2.408 29.52 ;
     RECT  0.084 29.52 2.408 29.544 ;
     RECT  0.06 29.544 2.408 29.664 ;
     RECT  0.084 29.664 2.408 29.688 ;
     RECT  0.06 29.688 2.408 29.808 ;
     RECT  0.084 29.808 2.408 29.832 ;
     RECT  0.06 29.832 2.408 29.952 ;
     RECT  0.084 29.952 2.408 29.976 ;
     RECT  0.06 29.976 2.408 30.096 ;
     RECT  0.084 30.096 2.408 30.12 ;
     RECT  0.06 30.12 2.408 30.24 ;
     RECT  0.084 30.24 2.408 30.264 ;
     RECT  0.06 30.264 2.408 30.384 ;
     RECT  0.084 30.384 2.408 30.408 ;
     RECT  0.06 30.408 2.408 30.528 ;
     RECT  0.084 30.528 2.408 30.552 ;
     RECT  0.06 30.552 2.408 30.672 ;
     RECT  0.084 30.672 2.408 30.696 ;
     RECT  0.06 30.696 2.408 30.816 ;
     RECT  0.084 30.816 2.408 30.84 ;
     RECT  0.06 30.84 2.408 30.96 ;
     RECT  0.084 30.96 2.408 30.984 ;
     RECT  0.06 30.984 2.408 31.104 ;
     RECT  0.084 31.104 2.408 31.128 ;
     RECT  0.06 31.128 2.408 31.248 ;
     RECT  0.084 31.248 2.408 31.272 ;
     RECT  0.06 31.272 2.408 31.392 ;
     RECT  0.084 31.392 2.408 31.416 ;
     RECT  0.06 31.416 2.408 31.536 ;
     RECT  0.084 31.536 2.408 31.56 ;
     RECT  0.06 31.56 2.408 31.68 ;
     RECT  0.084 31.68 2.408 31.704 ;
     RECT  0.06 31.704 2.408 31.824 ;
     RECT  0.084 31.824 2.408 31.848 ;
     RECT  0.06 31.848 2.408 31.968 ;
     RECT  0.084 31.968 2.408 31.992 ;
     RECT  0.06 31.992 2.408 32.112 ;
     RECT  0.084 32.112 2.408 32.136 ;
     RECT  0.06 32.136 2.408 32.256 ;
     RECT  0.084 32.256 2.408 32.28 ;
     RECT  0.06 32.28 2.408 32.4 ;
     RECT  0.084 32.4 2.408 32.424 ;
     RECT  0.06 32.424 2.408 32.544 ;
     RECT  0.084 32.544 2.408 32.568 ;
     RECT  0.06 32.568 2.408 32.688 ;
     RECT  0.084 32.688 2.408 32.712 ;
     RECT  0.06 32.712 2.408 32.832 ;
     RECT  0.084 32.832 2.408 32.856 ;
     RECT  0.06 32.856 2.408 32.976 ;
     RECT  0.084 32.976 2.408 33 ;
     RECT  0.06 33 2.408 33.12 ;
     RECT  0.084 33.12 2.408 33.144 ;
     RECT  0.06 33.144 2.408 33.264 ;
     RECT  0.084 33.264 2.408 33.288 ;
     RECT  0.06 33.288 2.408 33.408 ;
     RECT  0.084 33.408 2.408 33.432 ;
     RECT  0.06 33.432 2.408 33.552 ;
     RECT  0.084 33.552 2.408 33.576 ;
     RECT  0.06 33.576 2.408 33.696 ;
     RECT  0.084 33.696 2.408 33.72 ;
     RECT  0.06 33.72 2.408 33.84 ;
     RECT  0.084 33.84 2.408 33.864 ;
     RECT  0.06 33.864 2.408 33.984 ;
     RECT  0.084 33.984 2.408 34.008 ;
     RECT  0.06 34.008 2.408 34.128 ;
     RECT  0.084 34.128 2.408 34.152 ;
     RECT  0.06 34.152 2.408 34.272 ;
     RECT  0.084 34.272 2.408 34.296 ;
     RECT  0.06 34.296 2.408 34.416 ;
     RECT  0.084 34.416 2.408 34.44 ;
     RECT  0.06 34.44 2.408 34.56 ;
     RECT  0.084 34.56 2.408 34.584 ;
     RECT  0.06 34.584 2.408 34.704 ;
     RECT  0.084 34.704 2.408 34.728 ;
     RECT  0.06 34.728 2.408 34.848 ;
     RECT  0.084 34.848 2.408 34.872 ;
     RECT  0.06 34.872 2.408 34.992 ;
     RECT  0.084 34.992 2.408 35.016 ;
     RECT  0.06 35.016 2.408 35.136 ;
     RECT  0.084 35.136 2.408 35.16 ;
     RECT  0.06 35.16 2.408 35.28 ;
     RECT  0.084 35.28 2.408 35.304 ;
     RECT  0.06 35.304 2.408 35.424 ;
     RECT  0.084 35.424 2.408 35.448 ;
     RECT  0.06 35.448 2.408 35.568 ;
     RECT  0.084 35.568 2.408 35.592 ;
     RECT  0.06 35.592 2.408 35.712 ;
     RECT  0.084 35.712 2.408 35.736 ;
     RECT  0.06 35.736 2.408 35.856 ;
     RECT  0.084 35.856 2.408 35.88 ;
     RECT  0.06 35.88 2.408 36 ;
     RECT  0.084 36 2.408 36.024 ;
     RECT  0.06 36.024 2.408 36.144 ;
     RECT  0.084 36.144 2.408 36.168 ;
     RECT  0.06 36.168 2.408 36.288 ;
     RECT  0.084 36.288 2.408 36.312 ;
     RECT  0.06 36.312 2.408 36.432 ;
     RECT  0.084 36.432 2.408 36.456 ;
     RECT  0.06 36.456 2.408 36.576 ;
     RECT  0.084 36.576 2.408 36.6 ;
     RECT  0.06 36.6 2.408 36.72 ;
     RECT  0.084 36.72 2.408 36.744 ;
     RECT  0.06 36.744 2.408 36.864 ;
     RECT  0.084 36.864 2.408 36.888 ;
     RECT  0.06 36.888 2.408 37.008 ;
     RECT  0.084 37.008 2.408 37.032 ;
     RECT  0.06 37.032 2.408 37.152 ;
     RECT  0.084 37.152 2.408 37.176 ;
     RECT  0.06 37.176 2.408 37.296 ;
     RECT  0.084 37.296 2.408 37.32 ;
     RECT  0.06 37.32 2.408 37.44 ;
     RECT  0.084 37.44 2.408 37.464 ;
     RECT  0.06 37.464 2.408 37.584 ;
     RECT  0.084 37.584 2.408 37.608 ;
     RECT  0.06 37.608 2.408 37.728 ;
     RECT  0.084 37.728 2.408 37.752 ;
     RECT  0.06 37.752 2.408 37.872 ;
     RECT  0.084 37.872 2.408 37.896 ;
     RECT  0.06 37.896 2.408 38.016 ;
     RECT  0.084 38.016 2.408 38.04 ;
     RECT  0.06 38.04 2.408 38.16 ;
     RECT  0.084 38.16 2.408 38.184 ;
     RECT  0.06 38.184 2.408 38.304 ;
     RECT  0.084 38.304 2.408 38.328 ;
     RECT  0.06 38.328 2.408 38.448 ;
     RECT  0.084 38.448 2.408 38.472 ;
     RECT  0.06 38.472 2.408 38.592 ;
     RECT  0.084 38.592 2.408 38.616 ;
     RECT  0.06 38.616 2.408 38.736 ;
     RECT  0.084 38.736 2.408 38.76 ;
     RECT  0.06 38.76 2.408 39.456 ;
     RECT  0.084 39.456 2.408 39.48 ;
     RECT  0.06 39.48 2.408 39.6 ;
     RECT  0.084 39.6 2.408 39.624 ;
     RECT  0.06 39.624 2.408 39.744 ;
     RECT  0.084 39.744 2.408 39.768 ;
     RECT  0.06 39.768 2.408 39.888 ;
     RECT  0.084 39.888 2.408 39.912 ;
     RECT  0.06 39.912 2.408 40.032 ;
     RECT  0.084 40.032 2.408 40.056 ;
     RECT  0.06 40.056 2.408 40.176 ;
     RECT  0.084 40.176 2.408 40.2 ;
     RECT  0.06 40.2 2.408 40.32 ;
     RECT  0.084 40.32 2.408 40.344 ;
     RECT  0.06 40.344 2.408 40.464 ;
     RECT  0.084 40.464 2.408 40.488 ;
     RECT  0.06 40.488 2.408 40.608 ;
     RECT  0.084 40.608 2.408 40.632 ;
     RECT  0.06 40.632 2.408 40.752 ;
     RECT  0.084 40.752 2.408 40.776 ;
     RECT  0.06 40.776 2.408 40.896 ;
     RECT  0.084 40.896 2.408 40.92 ;
     RECT  0.06 40.92 2.408 41.04 ;
     RECT  0.084 41.04 2.408 41.064 ;
     RECT  0.06 41.064 2.408 41.184 ;
     RECT  0.084 41.184 2.408 41.208 ;
     RECT  0.06 41.208 2.408 41.328 ;
     RECT  0.084 41.328 2.408 41.352 ;
     RECT  0.06 41.352 2.408 41.472 ;
     RECT  0.084 41.472 2.408 41.496 ;
     RECT  0.06 41.496 2.408 41.616 ;
     RECT  0.084 41.616 2.408 41.64 ;
     RECT  0.06 41.64 2.408 41.76 ;
     RECT  0.084 41.76 2.408 41.784 ;
     RECT  0.06 41.784 2.408 41.904 ;
     RECT  0.084 41.904 2.408 41.928 ;
     RECT  0.06 41.928 2.408 42.048 ;
     RECT  0.084 42.048 2.408 42.072 ;
     RECT  0.06 42.072 2.408 42.192 ;
     RECT  0.084 42.192 2.408 42.216 ;
     RECT  0.06 42.216 2.408 42.336 ;
     RECT  0.084 42.336 2.408 42.36 ;
     RECT  0.06 42.36 2.408 42.48 ;
     RECT  0.084 42.48 2.408 42.504 ;
     RECT  0.06 42.504 2.408 42.624 ;
     RECT  0.084 42.624 2.408 42.648 ;
     RECT  0.06 42.648 2.408 42.768 ;
     RECT  0.084 42.768 2.408 42.792 ;
     RECT  0.06 42.792 2.408 42.912 ;
     RECT  0.084 42.912 2.408 42.936 ;
     RECT  0.06 42.936 2.408 43.056 ;
     RECT  0.084 43.056 2.408 43.08 ;
     RECT  0.06 43.08 2.408 43.2 ;
     RECT  0.084 43.2 2.408 43.224 ;
     RECT  0.06 43.224 2.408 43.344 ;
     RECT  0.084 43.344 2.408 43.368 ;
     RECT  0.06 43.368 2.408 43.488 ;
     RECT  0.084 43.488 2.408 43.512 ;
     RECT  0.06 43.512 2.408 43.632 ;
     RECT  0.084 43.632 2.408 43.656 ;
     RECT  0.06 43.656 2.408 43.776 ;
     RECT  0.084 43.776 2.408 43.8 ;
     RECT  0.06 43.8 2.408 43.92 ;
     RECT  0.084 43.92 2.408 43.944 ;
     RECT  0.06 43.944 2.408 44.064 ;
     RECT  0.084 44.064 2.408 44.088 ;
     RECT  0.06 44.088 2.408 44.208 ;
     RECT  0.084 44.208 2.408 44.232 ;
     RECT  0.06 44.232 2.408 44.352 ;
     RECT  0.084 44.352 2.408 44.376 ;
     RECT  0.06 44.376 2.408 44.496 ;
     RECT  0.084 44.496 2.408 44.52 ;
     RECT  0.06 44.52 2.408 44.64 ;
     RECT  0.084 44.64 2.408 44.664 ;
     RECT  0.06 44.664 2.408 44.784 ;
     RECT  0.084 44.784 2.408 44.808 ;
     RECT  0.06 44.808 2.408 44.928 ;
     RECT  0.084 44.928 2.408 44.952 ;
     RECT  0.06 44.952 2.408 45.072 ;
     RECT  0.084 45.072 2.408 45.096 ;
     RECT  0.06 45.096 2.408 45.216 ;
     RECT  0.084 45.216 2.408 45.24 ;
     RECT  0.06 45.24 2.408 45.36 ;
     RECT  0.084 45.36 2.408 45.384 ;
     RECT  0.06 45.384 2.408 45.504 ;
     RECT  0.084 45.504 2.408 45.528 ;
     RECT  0.06 45.528 2.408 45.648 ;
     RECT  0.084 45.648 2.408 45.672 ;
     RECT  0.06 45.672 2.408 45.792 ;
     RECT  0.084 45.792 2.408 45.816 ;
     RECT  0.06 45.816 2.408 45.936 ;
     RECT  0.084 45.936 2.408 45.96 ;
     RECT  0.06 45.96 2.408 46.08 ;
     RECT  0.084 46.08 2.408 46.104 ;
     RECT  0.06 46.104 2.408 46.224 ;
     RECT  0.084 46.224 2.408 46.248 ;
     RECT  0.06 46.248 2.408 46.368 ;
     RECT  0.084 46.368 2.408 46.392 ;
     RECT  0.06 46.392 2.408 46.512 ;
     RECT  0.084 46.512 2.408 46.536 ;
     RECT  0.06 46.536 2.408 46.656 ;
     RECT  0.084 46.656 2.408 46.68 ;
     RECT  0.06 46.68 2.408 46.8 ;
     RECT  0.084 46.8 2.408 46.824 ;
     RECT  0.06 46.824 2.408 46.944 ;
     RECT  0.084 46.944 2.408 46.968 ;
     RECT  0.06 46.968 2.408 47.088 ;
     RECT  0.084 47.088 2.408 47.112 ;
     RECT  0.06 47.112 2.408 47.232 ;
     RECT  0.084 47.232 2.408 47.256 ;
     RECT  0.06 47.256 2.408 47.376 ;
     RECT  0.084 47.376 2.408 47.4 ;
     RECT  0.06 47.4 2.408 47.52 ;
     RECT  0.084 47.52 2.408 47.544 ;
     RECT  0.06 47.544 2.408 47.664 ;
     RECT  0.084 47.664 2.408 47.688 ;
     RECT  0.06 47.688 2.408 47.808 ;
     RECT  0.084 47.808 2.408 47.832 ;
     RECT  0.06 47.832 2.408 47.952 ;
     RECT  0.084 47.952 2.408 47.976 ;
     RECT  0.06 47.976 2.408 48.096 ;
     RECT  0.084 48.096 2.408 48.12 ;
     RECT  0.06 48.12 2.408 48.24 ;
     RECT  0.084 48.24 2.408 48.264 ;
     RECT  0.06 48.264 2.408 48.384 ;
     RECT  0.084 48.384 2.408 48.408 ;
     RECT  0.06 48.408 2.408 48.528 ;
     RECT  0.084 48.528 2.408 48.552 ;
     RECT  0.06 48.552 2.408 48.672 ;
     RECT  0.084 48.672 2.408 48.696 ;
     RECT  0.06 48.696 2.408 48.816 ;
     RECT  0.084 48.816 2.408 48.84 ;
     RECT  0.06 48.84 2.408 48.96 ;
     RECT  0.084 48.96 2.408 48.984 ;
     RECT  0.06 48.984 2.408 49.104 ;
     RECT  0.084 49.104 2.408 49.128 ;
     RECT  0.06 49.128 2.408 49.248 ;
     RECT  0.084 49.248 2.408 49.272 ;
     RECT  0.06 49.272 2.408 49.392 ;
     RECT  0.084 49.392 2.408 49.416 ;
     RECT  0.06 49.416 2.408 49.536 ;
     RECT  0.084 49.536 2.408 49.56 ;
     RECT  0.06 49.56 2.408 49.68 ;
     RECT  0.084 49.68 2.408 49.704 ;
     RECT  0.06 49.704 2.408 49.824 ;
     RECT  0.084 49.824 2.408 49.848 ;
     RECT  0.06 49.848 2.408 49.968 ;
     RECT  0.084 49.968 2.408 49.992 ;
     RECT  0.06 49.992 2.408 50.112 ;
     RECT  0.084 50.112 2.408 50.136 ;
     RECT  0.06 50.136 2.408 50.256 ;
     RECT  0.084 50.256 2.408 50.28 ;
     RECT  0.06 50.28 2.408 50.4 ;
     RECT  0.084 50.4 2.408 50.424 ;
     RECT  0.06 50.424 2.408 50.544 ;
     RECT  0.084 50.544 2.408 50.568 ;
     RECT  0.06 50.568 2.408 50.688 ;
     RECT  0.084 50.688 2.408 50.712 ;
     RECT  0.06 50.712 2.408 50.832 ;
     RECT  0.084 50.832 2.408 50.856 ;
     RECT  0.06 50.856 2.408 50.976 ;
     RECT  0.084 50.976 2.408 51 ;
     RECT  0.06 51 2.408 51.12 ;
     RECT  0.084 51.12 2.408 51.144 ;
     RECT  0.06 51.144 2.408 51.264 ;
     RECT  0.084 51.264 2.408 51.288 ;
     RECT  0.06 51.288 2.408 51.408 ;
     RECT  0.084 51.408 2.408 51.432 ;
     RECT  0.06 51.432 2.408 51.552 ;
     RECT  0.084 51.552 2.408 51.576 ;
     RECT  0.06 51.576 2.408 51.696 ;
     RECT  0.084 51.696 2.408 51.72 ;
     RECT  0.06 51.72 2.408 51.84 ;
     RECT  0.084 51.84 2.408 51.864 ;
     RECT  0.06 51.864 2.408 51.984 ;
     RECT  0.084 51.984 2.408 52.008 ;
     RECT  0.06 52.008 2.408 52.128 ;
     RECT  0.084 52.128 2.408 52.152 ;
     RECT  0.06 52.152 2.408 52.272 ;
     RECT  0.084 52.272 2.408 52.296 ;
     RECT  0.06 52.296 2.408 52.416 ;
     RECT  0.084 52.416 2.408 52.44 ;
     RECT  0.06 52.44 2.408 52.56 ;
     RECT  0.084 52.56 2.408 52.584 ;
     RECT  0.06 52.584 2.408 52.704 ;
     RECT  0.084 52.704 2.408 52.728 ;
     RECT  0.06 52.728 2.408 52.848 ;
     RECT  0.084 52.848 2.408 52.872 ;
     RECT  0.06 52.872 2.408 52.992 ;
     RECT  0.084 52.992 2.408 53.016 ;
     RECT  0.06 53.016 2.408 53.136 ;
     RECT  0.084 53.136 2.408 53.16 ;
     RECT  0.06 53.16 2.408 53.28 ;
     RECT  0.084 53.28 2.408 53.304 ;
     RECT  0.06 53.304 2.408 53.424 ;
     RECT  0.084 53.424 2.408 53.448 ;
     RECT  0.06 53.448 2.408 53.568 ;
     RECT  0.084 53.568 2.408 53.592 ;
     RECT  0.06 53.592 2.408 53.712 ;
     RECT  0.084 53.712 2.408 53.736 ;
     RECT  0.06 53.736 2.408 53.856 ;
     RECT  0.084 53.856 2.408 53.88 ;
     RECT  0.06 53.88 2.408 54 ;
     RECT  0.084 54 2.408 54.024 ;
     RECT  0.06 54.024 2.408 54.144 ;
     RECT  0.084 54.144 2.408 54.168 ;
     RECT  0.06 54.168 2.408 54.288 ;
     RECT  0.084 54.288 2.408 54.312 ;
     RECT  0.06 54.312 2.408 54.432 ;
     RECT  0.084 54.432 2.408 54.456 ;
     RECT  0.06 54.456 2.408 54.576 ;
     RECT  0.084 54.576 2.408 54.6 ;
     RECT  0.06 54.6 2.408 54.72 ;
     RECT  0.084 54.72 2.408 54.744 ;
     RECT  0.06 54.744 2.408 54.864 ;
     RECT  0.084 54.864 2.408 54.888 ;
     RECT  0.06 54.888 2.408 55.008 ;
     RECT  0.084 55.008 2.408 55.032 ;
     RECT  0.06 55.032 2.408 55.152 ;
     RECT  0.084 55.152 2.408 55.176 ;
     RECT  0.06 55.176 2.408 55.296 ;
     RECT  0.084 55.296 2.408 55.32 ;
     RECT  0.06 55.32 2.408 55.44 ;
     RECT  0.084 55.44 2.408 55.464 ;
     RECT  0.06 55.464 2.408 55.584 ;
     RECT  0.084 55.584 2.408 55.608 ;
     RECT  0.06 55.608 2.408 55.728 ;
     RECT  0.084 55.728 2.408 55.752 ;
     RECT  0.06 55.752 2.408 55.872 ;
     RECT  0.084 55.872 2.408 55.896 ;
     RECT  0.06 55.896 2.408 56.016 ;
     RECT  0.084 56.016 2.408 56.04 ;
     RECT  0.06 56.04 2.408 56.16 ;
     RECT  0.084 56.16 2.408 56.184 ;
     RECT  0.06 56.184 2.408 56.304 ;
     RECT  0.084 56.304 2.408 56.328 ;
     RECT  0.06 56.328 2.408 56.448 ;
     RECT  0.084 56.448 2.408 56.472 ;
     RECT  0.06 56.472 2.408 56.592 ;
     RECT  0.084 56.592 2.408 56.616 ;
     RECT  0.06 56.616 2.408 56.736 ;
     RECT  0.084 56.736 2.408 56.76 ;
     RECT  0.06 56.76 2.408 56.88 ;
     RECT  0.084 56.88 2.408 56.904 ;
     RECT  0.06 56.904 2.408 57.024 ;
     RECT  0.084 57.024 2.408 57.048 ;
     RECT  0.06 57.048 2.408 57.168 ;
     RECT  0.084 57.168 2.408 57.192 ;
     RECT  0.06 57.192 2.408 57.312 ;
     RECT  0.084 57.312 2.408 57.336 ;
     RECT  0.06 57.336 2.408 57.456 ;
     RECT  0.084 57.456 2.408 57.48 ;
     RECT  0.06 57.48 2.408 57.6 ;
     RECT  0.084 57.6 2.408 57.624 ;
     RECT  0.06 57.624 2.408 57.744 ;
     RECT  0.084 57.744 2.408 57.768 ;
     RECT  0.06 57.768 2.408 57.888 ;
     RECT  0.084 57.888 2.408 57.912 ;
     RECT  0.06 57.912 2.408 58.032 ;
     RECT  0.084 58.032 2.408 58.056 ;
     RECT  0.06 58.056 2.408 58.176 ;
     RECT  0.084 58.176 2.408 58.2 ;
     RECT  0.06 58.2 2.408 58.32 ;
     RECT  0.084 58.32 2.408 58.344 ;
     RECT  0.06 58.344 2.408 58.464 ;
     RECT  0.084 58.464 2.408 58.488 ;
     RECT  0.06 58.488 2.408 58.608 ;
     RECT  0.084 58.608 2.408 58.632 ;
     RECT  0.06 58.632 2.408 58.752 ;
     RECT  0.084 58.752 2.408 58.776 ;
     RECT  0.06 58.776 2.408 58.896 ;
     RECT  0.084 58.896 2.408 58.92 ;
     RECT  0.06 58.92 2.408 59.04 ;
     RECT  0.084 59.04 2.408 59.064 ;
     RECT  0.06 59.064 2.408 59.184 ;
     RECT  0.084 59.184 2.408 59.208 ;
     RECT  0.06 59.208 2.408 59.328 ;
     RECT  0.084 59.328 2.408 59.352 ;
     RECT  0.06 59.352 2.408 59.472 ;
     RECT  0.084 59.472 2.408 59.496 ;
     RECT  0.06 59.496 2.408 59.616 ;
     RECT  0.084 59.616 2.408 59.64 ;
     RECT  0.06 59.64 2.408 59.76 ;
     RECT  0.084 59.76 2.408 59.784 ;
     RECT  0.06 59.784 2.408 59.904 ;
     RECT  0.084 59.904 2.408 59.928 ;
     RECT  0.06 59.928 2.408 60.048 ;
     RECT  0.084 60.048 2.408 60.072 ;
     RECT  0.06 60.072 2.408 60.192 ;
     RECT  0.084 60.192 2.408 60.216 ;
     RECT  0.06 60.216 2.408 60.336 ;
     RECT  0.084 60.336 2.408 60.36 ;
     RECT  0.06 60.36 2.408 60.48 ;
     RECT  0.084 60.48 2.408 60.504 ;
     RECT  0.06 60.504 2.408 60.624 ;
     RECT  0.084 60.624 2.408 60.648 ;
     RECT  0.06 60.648 2.408 60.768 ;
     RECT  0.084 60.768 2.408 60.792 ;
     RECT  0.06 60.792 2.408 60.912 ;
     RECT  0.084 60.912 2.408 60.936 ;
     RECT  0.06 60.936 2.408 61.056 ;
     RECT  0.084 61.056 2.408 61.08 ;
     RECT  0.06 61.08 2.408 61.2 ;
     RECT  0.084 61.2 2.408 61.224 ;
     RECT  0.06 61.224 2.408 61.344 ;
     RECT  0.084 61.344 2.408 61.368 ;
     RECT  0.06 61.368 2.408 61.488 ;
     RECT  0.084 61.488 2.408 61.512 ;
     RECT  0.06 61.512 2.408 61.632 ;
     RECT  0.084 61.632 2.408 61.656 ;
     RECT  0.06 61.656 2.408 61.776 ;
     RECT  0.084 61.776 2.408 61.8 ;
     RECT  0.06 61.8 2.408 61.92 ;
     RECT  0.084 61.92 2.408 61.944 ;
     RECT  0.06 61.944 2.408 62.064 ;
     RECT  0.084 62.064 2.408 62.088 ;
     RECT  0.06 62.088 2.408 62.208 ;
     RECT  0.084 62.208 2.408 62.232 ;
     RECT  0.06 62.232 2.408 62.352 ;
     RECT  0.084 62.352 2.408 62.376 ;
     RECT  0.06 62.376 2.408 62.496 ;
     RECT  0.084 62.496 2.408 62.52 ;
     RECT  0.06 62.52 2.408 62.64 ;
     RECT  0.084 62.64 2.408 62.664 ;
     RECT  0.06 62.664 2.408 62.784 ;
     RECT  0.084 62.784 2.408 62.808 ;
     RECT  0.06 62.808 2.408 62.928 ;
     RECT  0.084 62.928 2.408 62.952 ;
     RECT  0.06 62.952 2.408 63.072 ;
     RECT  0.084 63.072 2.408 63.096 ;
     RECT  0.06 63.096 2.408 63.216 ;
     RECT  0.084 63.216 2.408 63.24 ;
     RECT  0.06 63.24 2.408 63.36 ;
     RECT  0.084 63.36 2.408 63.384 ;
     RECT  0.06 63.384 2.408 63.504 ;
     RECT  0.084 63.504 2.408 63.528 ;
     RECT  0.06 63.528 2.408 63.648 ;
     RECT  0.084 63.648 2.408 63.672 ;
     RECT  0.06 63.672 2.408 63.792 ;
     RECT  0.084 63.792 2.408 63.816 ;
     RECT  0.06 63.816 2.408 63.936 ;
     RECT  0.084 63.936 2.408 63.96 ;
     RECT  0.06 63.96 2.408 64.08 ;
     RECT  0.084 64.08 2.408 64.104 ;
     RECT  0.06 64.104 2.408 64.224 ;
     RECT  0.084 64.224 2.408 64.248 ;
     RECT  0.06 64.248 2.408 64.368 ;
     RECT  0.084 64.368 2.408 64.392 ;
     RECT  0.06 64.392 2.408 64.512 ;
     RECT  0.084 64.512 2.408 64.536 ;
     RECT  0.06 64.536 2.408 64.656 ;
     RECT  0.084 64.656 2.408 64.68 ;
     RECT  0.06 64.68 2.408 64.8 ;
     RECT  0.084 64.8 2.408 64.824 ;
     RECT  0.06 64.824 2.408 64.944 ;
     RECT  0.084 64.944 2.408 64.968 ;
     RECT  0.06 64.968 2.408 65.088 ;
     RECT  0.084 65.088 2.408 65.112 ;
     RECT  0.06 65.112 2.408 65.232 ;
     RECT  0.084 65.232 2.408 65.256 ;
     RECT  0.06 65.256 2.408 65.376 ;
     RECT  0.084 65.376 2.408 65.4 ;
     RECT  0.06 65.4 2.408 65.52 ;
     RECT  0.084 65.52 2.408 65.544 ;
     RECT  0.06 65.544 2.408 65.664 ;
     RECT  0.084 65.664 2.408 65.688 ;
     RECT  0.06 65.688 2.408 65.808 ;
     RECT  0.084 65.808 2.408 65.832 ;
     RECT  0.06 65.832 2.408 65.952 ;
     RECT  0.084 65.952 2.408 65.976 ;
     RECT  0.06 65.976 2.408 66.096 ;
     RECT  0.084 66.096 2.408 66.12 ;
     RECT  0.06 66.12 2.408 66.24 ;
     RECT  0.084 66.24 2.408 66.264 ;
     RECT  0.06 66.264 2.408 66.384 ;
     RECT  0.084 66.384 2.408 66.408 ;
     RECT  0.06 66.408 2.408 66.528 ;
     RECT  0.084 66.528 2.408 66.552 ;
     RECT  0.06 66.552 2.408 66.672 ;
     RECT  0.084 66.672 2.408 66.696 ;
     RECT  0.06 66.696 2.408 66.816 ;
     RECT  0.084 66.816 2.408 66.84 ;
     RECT  0.06 66.84 2.408 66.96 ;
     RECT  0.084 66.96 2.408 66.984 ;
     RECT  0.06 66.984 2.408 67.104 ;
     RECT  0.084 67.104 2.408 67.128 ;
     RECT  0.06 67.128 2.408 67.248 ;
     RECT  0.084 67.248 2.408 67.272 ;
     RECT  0.06 67.272 2.408 67.392 ;
     RECT  0.084 67.392 2.408 67.416 ;
     RECT  0.06 67.416 2.408 67.536 ;
     RECT  0.084 67.536 2.408 67.56 ;
     RECT  0.084 68.832 2.408 68.856 ;
     RECT  0.06 68.856 2.408 68.976 ;
     RECT  0.084 68.976 2.408 69 ;
     RECT  0.06 69 2.408 69.12 ;
     RECT  0.084 69.12 2.408 69.144 ;
     RECT  0.06 69.144 2.408 69.264 ;
     RECT  0.084 69.264 2.408 69.288 ;
     RECT  0.06 69.288 2.408 69.408 ;
     RECT  0.084 69.408 2.408 69.432 ;
     RECT  0.06 69.432 2.408 69.552 ;
     RECT  0.084 69.552 2.408 69.576 ;
     RECT  0.06 69.576 2.408 69.696 ;
     RECT  0.084 69.696 2.408 69.72 ;
     RECT  0.06 69.72 2.408 69.84 ;
     RECT  0.084 69.84 2.408 69.864 ;
     RECT  0.06 69.864 2.408 69.984 ;
     RECT  0.084 69.984 2.408 70.008 ;
     RECT  0.06 70.008 2.408 70.128 ;
     RECT  0.084 70.128 2.408 70.152 ;
     RECT  0.06 70.152 2.408 70.272 ;
     RECT  0.084 70.272 2.408 70.296 ;
     RECT  0.06 70.296 2.408 70.416 ;
     RECT  0.084 70.416 2.408 70.44 ;
     RECT  0.06 70.44 2.408 70.56 ;
     RECT  0.084 70.56 2.408 70.584 ;
     RECT  0.06 70.584 2.408 70.704 ;
     RECT  0.084 70.704 2.408 70.728 ;
     RECT  0.06 70.728 2.408 70.848 ;
     RECT  0.084 70.848 2.408 70.872 ;
     RECT  0.06 70.872 2.408 70.992 ;
     RECT  0.084 70.992 2.408 71.016 ;
     RECT  0.06 71.016 2.408 71.136 ;
     RECT  0.084 71.136 2.408 71.16 ;
     RECT  0.06 71.16 2.408 71.28 ;
     RECT  0.084 71.28 2.408 71.304 ;
     RECT  0.06 71.304 2.408 71.424 ;
     RECT  0.084 71.424 2.408 71.448 ;
     RECT  0.06 71.448 2.408 71.568 ;
     RECT  0.084 71.568 2.408 71.592 ;
     RECT  0.06 71.592 2.408 71.712 ;
     RECT  0.084 71.712 2.408 71.736 ;
     RECT  0.06 71.736 2.408 71.856 ;
     RECT  0.084 71.856 2.408 71.88 ;
     RECT  0.06 71.88 2.408 72 ;
     RECT  0.084 72 2.408 72.024 ;
     RECT  0.06 72.024 2.408 72.144 ;
     RECT  0.084 72.144 2.408 72.168 ;
     RECT  0.06 72.168 2.408 72.288 ;
     RECT  0.084 72.288 2.408 72.312 ;
     RECT  0.06 72.312 2.408 72.432 ;
     RECT  0.084 72.432 2.408 72.456 ;
     RECT  0.06 72.456 2.408 72.576 ;
     RECT  0.084 72.576 2.408 72.6 ;
     RECT  0.06 72.6 2.408 72.72 ;
     RECT  0.084 72.72 2.408 72.744 ;
     RECT  0.06 72.744 2.408 72.864 ;
     RECT  0.084 72.864 2.408 72.888 ;
     RECT  0.06 72.888 2.408 73.008 ;
     RECT  0.084 73.008 2.408 73.032 ;
     RECT  0.06 73.032 2.408 73.152 ;
     RECT  0.084 73.152 2.408 73.176 ;
     RECT  0.06 73.176 2.408 73.296 ;
     RECT  0.084 73.296 2.408 73.32 ;
     RECT  0.06 73.32 2.408 73.44 ;
     RECT  0.084 73.44 2.408 73.464 ;
     RECT  0.06 73.464 2.408 73.584 ;
     RECT  0.084 73.584 2.408 73.608 ;
     RECT  0.06 73.608 2.408 73.728 ;
     RECT  0.084 73.728 2.408 73.752 ;
     RECT  0.06 73.752 2.408 73.872 ;
     RECT  0.084 73.872 2.408 73.896 ;
     RECT  0.06 73.896 2.408 74.016 ;
     RECT  0.084 74.016 2.408 74.04 ;
     RECT  0.06 74.04 2.408 74.16 ;
     RECT  0.084 74.16 2.408 74.184 ;
     RECT  0.06 74.184 2.408 74.304 ;
     RECT  0.084 74.304 2.408 74.328 ;
     RECT  0.06 74.328 2.408 74.448 ;
     RECT  0.084 74.448 2.408 74.472 ;
     RECT  0.06 74.472 2.408 74.592 ;
     RECT  0.084 74.592 2.408 74.616 ;
     RECT  0.06 74.616 2.408 74.736 ;
     RECT  0.084 74.736 2.408 74.76 ;
     RECT  0.06 74.76 2.408 74.88 ;
     RECT  0.084 74.88 2.408 74.904 ;
     RECT  0.06 74.904 2.408 75.024 ;
     RECT  0.084 75.024 2.408 75.048 ;
     RECT  0.06 75.048 2.408 75.168 ;
     RECT  0.084 75.168 2.408 75.192 ;
     RECT  0.06 75.192 2.408 75.312 ;
     RECT  0.084 75.312 2.408 75.336 ;
     RECT  0.06 75.336 2.408 75.456 ;
     RECT  0.084 75.456 2.408 75.48 ;
     RECT  0.06 75.48 2.408 75.6 ;
     RECT  0.084 75.6 2.408 75.624 ;
     RECT  0.06 75.624 2.408 75.744 ;
     RECT  0.084 75.744 2.408 75.768 ;
     RECT  0.06 75.768 2.408 75.888 ;
     RECT  0.084 75.888 2.408 75.912 ;
     RECT  0.06 75.912 2.408 76.032 ;
     RECT  0.084 76.032 2.408 76.056 ;
     RECT  0.06 76.056 2.408 76.176 ;
     RECT  0.084 76.176 2.408 76.2 ;
     RECT  0.06 76.2 2.408 76.32 ;
     RECT  0.084 76.32 2.408 76.344 ;
     RECT  0.06 76.344 2.408 76.464 ;
     RECT  0.084 76.464 2.408 76.488 ;
     RECT  0.06 76.488 2.408 76.608 ;
     RECT  0.084 76.608 2.408 76.632 ;
     RECT  0.06 76.632 2.408 76.752 ;
     RECT  0.084 76.752 2.408 76.776 ;
     RECT  0.06 76.776 2.408 76.896 ;
     RECT  0.084 76.896 2.408 76.92 ;
     RECT  0.06 76.92 2.408 77.04 ;
     RECT  0.084 77.04 2.408 77.064 ;
     RECT  0.06 77.064 2.408 77.184 ;
     RECT  0.084 77.184 2.408 77.208 ;
     RECT  0.06 77.208 2.408 77.328 ;
     RECT  0.084 77.328 2.408 77.352 ;
     RECT  0.06 77.352 2.408 77.472 ;
     RECT  0.084 77.472 2.408 77.496 ;
     RECT  0.06 77.496 2.408 77.616 ;
     RECT  0.084 77.616 2.408 77.64 ;
     RECT  0.06 77.64 2.408 77.76 ;
     RECT  0.084 77.76 2.408 77.784 ;
     RECT  0.06 77.784 2.408 77.904 ;
     RECT  0.084 77.904 2.408 77.928 ;
     RECT  2.408 1.152 2.512 95.052 ;
     RECT  2.512 1.152 2.704 94.782 ;
     RECT  2.704 33.984 2.729 55.464 ;
     RECT  2.704 13.824 2.765 16.872 ;
     RECT  2.704 75.168 2.765 76.824 ;
     RECT  2.704 1.152 2.801 9.816 ;
     RECT  2.704 20.304 2.801 32.472 ;
     RECT  2.729 33.984 2.801 55.32 ;
     RECT  2.801 7.584 2.837 9.816 ;
     RECT  2.765 13.824 2.837 15.576 ;
     RECT  2.765 16.848 2.837 16.872 ;
     RECT  2.704 18 2.837 19.32 ;
     RECT  2.801 33.984 2.837 53.592 ;
     RECT  2.704 56.592 2.837 74.136 ;
     RECT  2.837 57.312 2.839 58.68 ;
     RECT  2.801 20.304 2.873 22.824 ;
     RECT  2.837 60.912 2.873 60.936 ;
     RECT  2.837 64.08 2.873 74.136 ;
     RECT  2.704 77.904 2.873 78.072 ;
     RECT  2.837 7.584 2.981 9.384 ;
     RECT  2.801 24.096 2.981 26.376 ;
     RECT  2.801 54.672 2.981 55.32 ;
     RECT  2.873 64.08 2.981 67.272 ;
     RECT  2.873 68.352 2.981 74.136 ;
     RECT  2.801 31.152 3.017 32.472 ;
     RECT  2.981 7.584 3.125 8.232 ;
     RECT  2.837 61.92 3.125 62.664 ;
     RECT  2.981 64.272 3.125 67.272 ;
     RECT  2.837 38.064 3.161 50.712 ;
     RECT  2.981 68.352 3.161 69.192 ;
     RECT  3.125 65.952 3.197 67.272 ;
     RECT  2.981 25.44 3.233 26.376 ;
     RECT  2.839 57.36 3.233 58.68 ;
     RECT  3.197 65.952 3.305 65.976 ;
     RECT  3.233 57.84 3.413 58.68 ;
     RECT  3.161 38.064 3.443 50.232 ;
     RECT  2.981 9.216 3.521 9.384 ;
     RECT  2.981 70.224 3.557 74.136 ;
     RECT  3.017 31.152 3.701 31.32 ;
     RECT  2.704 11.136 3.733 12.84 ;
     RECT  2.837 13.824 3.733 13.848 ;
     RECT  3.161 68.352 3.737 68.616 ;
     RECT  2.873 78.048 3.74 78.072 ;
     RECT  3.697 79.44 3.74 79.464 ;
     RECT  2.837 18.768 3.769 19.32 ;
     RECT  2.873 20.304 3.769 20.328 ;
     RECT  2.765 75.648 3.769 76.824 ;
     RECT  2.837 33.984 3.805 36.984 ;
     RECT  2.837 52.56 3.805 53.592 ;
     RECT  3.74 78.048 3.827 79.464 ;
     RECT  3.233 25.584 3.841 26.376 ;
     RECT  3.557 72.336 3.841 74.136 ;
     RECT  3.733 11.136 3.845 13.848 ;
     RECT  2.837 15.552 3.877 15.576 ;
     RECT  3.841 72.336 3.913 74.52 ;
     RECT  3.769 75.648 3.913 76.92 ;
     RECT  3.805 17.664 3.949 17.688 ;
     RECT  3.805 33.984 3.949 37.032 ;
     RECT  3.443 38.064 3.949 38.568 ;
     RECT  3.805 52.56 3.949 53.736 ;
     RECT  2.981 54.864 3.949 55.32 ;
     RECT  3.197 67.248 3.949 67.272 ;
     RECT  3.769 18.768 4.021 20.328 ;
     RECT  2.873 21.312 4.021 22.824 ;
     RECT  2.801 27.84 4.021 30.12 ;
     RECT  3.701 31.152 4.021 31.272 ;
     RECT  3.017 32.4 4.021 32.472 ;
     RECT  3.949 33.984 4.021 38.568 ;
     RECT  4.021 27.84 4.093 31.272 ;
     RECT  4.021 32.4 4.105 38.568 ;
     RECT  3.877 15.552 4.129 16.44 ;
     RECT  2.837 59.904 4.129 59.928 ;
     RECT  3.841 25.584 4.165 26.52 ;
     RECT  4.093 27.504 4.165 31.272 ;
     RECT  3.949 52.368 4.165 55.32 ;
     RECT  4.129 59.808 4.165 59.928 ;
     RECT  3.845 11.136 4.2 13.56 ;
     RECT  4.165 51.696 4.201 55.32 ;
     RECT  3.125 62.64 4.201 62.664 ;
     RECT  3.949 17.616 4.205 17.688 ;
     RECT  2.801 1.152 4.237 6.456 ;
     RECT  3.125 7.584 4.237 7.992 ;
     RECT  4.2 10.848 4.237 13.56 ;
     RECT  3.443 39.744 4.237 50.232 ;
     RECT  4.201 51.264 4.237 55.32 ;
     RECT  4.201 62.64 4.237 63.144 ;
     RECT  3.125 64.272 4.237 64.92 ;
     RECT  2.981 24.096 4.241 24.12 ;
     RECT  4.021 18.768 4.273 22.824 ;
     RECT  4.205 17.616 4.345 17.64 ;
     RECT  4.237 62.64 4.345 64.92 ;
     RECT  4.129 15.408 4.381 16.44 ;
     RECT  3.557 70.224 4.381 70.68 ;
     RECT  4.165 25.584 4.385 31.272 ;
     RECT  4.381 15.408 4.417 16.584 ;
     RECT  4.237 1.152 4.421 7.992 ;
     RECT  4.165 59.808 4.453 60.072 ;
     RECT  4.105 34.032 4.489 38.568 ;
     RECT  4.237 39.744 4.489 55.32 ;
     RECT  4.105 32.4 4.49 33 ;
     RECT  3.413 58.128 4.525 58.68 ;
     RECT  4.453 59.808 4.525 60.984 ;
     RECT  3.949 67.248 4.561 67.56 ;
     RECT  4.489 34.032 4.597 55.32 ;
     RECT  4.525 58.128 4.597 60.984 ;
     RECT  4.345 62.016 4.597 64.92 ;
     RECT  4.597 58.128 4.633 64.92 ;
     RECT  4.561 66.672 4.669 67.56 ;
     RECT  4.633 58.032 4.709 64.92 ;
     RECT  4.597 34.032 4.741 55.56 ;
     RECT  4.669 56.928 4.741 56.952 ;
     RECT  3.913 72.336 4.741 76.92 ;
     RECT  3.827 78.048 4.741 78.12 ;
     RECT  4.49 32.448 4.745 33 ;
     RECT  4.421 1.152 4.817 3 ;
     RECT  4.669 66.288 4.849 67.56 ;
     RECT  4.381 69.792 4.849 70.68 ;
     RECT  4.741 71.76 4.849 78.12 ;
     RECT  4.709 64.176 4.853 64.92 ;
     RECT  4.849 69.792 4.853 78.12 ;
     RECT  4.421 4.128 4.957 7.992 ;
     RECT  4.237 9.744 4.957 13.56 ;
     RECT  4.741 34.032 4.993 56.952 ;
     RECT  4.709 58.032 4.993 63.192 ;
     RECT  4.849 66.192 4.997 67.56 ;
     RECT  4.853 69.792 5.033 77.88 ;
     RECT  4.993 34.032 5.069 63.192 ;
     RECT  4.417 14.784 5.125 16.584 ;
     RECT  4.345 17.568 5.125 17.64 ;
     RECT  4.385 25.584 5.125 31.032 ;
     RECT  5.069 34.032 5.141 63.144 ;
     RECT  4.853 64.176 5.141 64.824 ;
     RECT  5.125 14.784 5.171 17.64 ;
     RECT  4.273 18.768 5.171 23.784 ;
     RECT  4.745 32.976 5.209 33 ;
     RECT  5.141 64.176 5.213 64.344 ;
     RECT  4.957 4.128 5.245 13.56 ;
     RECT  5.171 14.784 5.245 17.592 ;
     RECT  5.213 64.176 5.321 64.248 ;
     RECT  4.817 1.152 5.357 2.904 ;
     RECT  5.245 4.128 5.393 17.592 ;
     RECT  5.141 34.032 5.465 38.136 ;
     RECT  5.141 39.12 5.501 63.144 ;
     RECT  4.997 66.192 5.533 67.032 ;
     RECT  3.737 68.592 5.569 68.616 ;
     RECT  5.033 69.792 5.569 74.664 ;
     RECT  5.393 4.128 5.573 11.16 ;
     RECT  5.501 50.16 5.609 63.144 ;
     RECT  5.573 4.128 5.641 7.944 ;
     RECT  5.501 39.12 5.645 48.84 ;
     RECT  5.209 32.976 5.677 33.048 ;
     RECT  5.465 34.032 5.677 37.032 ;
     RECT  5.533 65.856 5.681 67.032 ;
     RECT  5.033 75.648 5.681 76.296 ;
     RECT  5.641 3.888 5.789 7.944 ;
     RECT  5.573 8.928 5.789 11.16 ;
     RECT  5.393 12.24 5.789 17.592 ;
     RECT  5.357 1.728 5.821 2.904 ;
     RECT  5.789 3.888 5.821 4.728 ;
     RECT  5.569 68.592 5.821 74.664 ;
     RECT  5.821 1.728 5.825 4.728 ;
     RECT  5.789 12.24 5.825 14.28 ;
     RECT  5.171 18.768 5.825 23.256 ;
     RECT  5.125 24.912 5.825 31.032 ;
     RECT  5.033 77.328 5.825 77.88 ;
     RECT  5.677 32.976 5.861 37.032 ;
     RECT  5.861 32.976 5.897 34.056 ;
     RECT  3.827 79.44 5.897 79.464 ;
     RECT  5.825 24.912 5.929 29.4 ;
     RECT  5.609 53.712 5.933 63.144 ;
     RECT  5.681 67.008 5.969 67.032 ;
     RECT  5.645 39.12 5.987 48.744 ;
     RECT  5.609 50.16 6.005 52.392 ;
     RECT  5.821 68.064 6.005 74.664 ;
     RECT  5.825 21.264 6.149 23.256 ;
     RECT  5.861 35.184 6.149 37.032 ;
     RECT  5.681 75.84 6.149 75.864 ;
     RECT  5.933 55.008 6.217 63.144 ;
     RECT  5.321 64.176 6.217 64.2 ;
     RECT  5.825 1.872 6.221 4.728 ;
     RECT  6.005 52.32 6.293 52.392 ;
     RECT  5.933 53.712 6.329 53.976 ;
     RECT  5.789 10.128 6.361 11.16 ;
     RECT  5.825 12.24 6.361 14.232 ;
     RECT  6.293 52.368 6.365 52.392 ;
     RECT  5.825 30.384 6.397 31.032 ;
     RECT  6.397 30.384 6.473 31.848 ;
     RECT  5.987 39.744 6.515 48.744 ;
     RECT  5.825 77.808 6.517 77.88 ;
     RECT  6.005 73.104 6.563 74.616 ;
     RECT  5.929 24.48 6.577 29.4 ;
     RECT  6.473 30.576 6.577 31.848 ;
     RECT  5.897 32.976 6.577 33.624 ;
     RECT  5.465 38.064 6.577 38.136 ;
     RECT  5.789 5.712 6.581 7.944 ;
     RECT  5.789 15.408 6.613 17.592 ;
     RECT  5.825 18.768 6.613 19.944 ;
     RECT  6.217 55.008 6.649 64.2 ;
     RECT  6.517 77.808 6.689 77.976 ;
     RECT  6.149 23.04 6.721 23.256 ;
     RECT  6.577 24.384 6.721 29.4 ;
     RECT  6.149 35.712 6.721 37.032 ;
     RECT  6.577 38.064 6.721 38.328 ;
     RECT  6.361 10.128 6.725 14.232 ;
     RECT  6.725 10.128 6.757 13.56 ;
     RECT  6.757 10.08 6.761 13.56 ;
     RECT  6.221 2.88 6.797 4.728 ;
     RECT  6.005 68.064 6.797 71.928 ;
     RECT  6.797 3.072 6.829 4.728 ;
     RECT  6.581 5.712 6.829 6.84 ;
     RECT  6.797 71.376 6.833 71.928 ;
     RECT  5.681 65.856 6.865 65.976 ;
     RECT  6.329 53.76 6.901 53.976 ;
     RECT  6.649 55.008 6.901 64.872 ;
     RECT  6.613 15.408 6.937 19.944 ;
     RECT  6.005 50.16 6.973 51.192 ;
     RECT  6.563 74.112 7.045 74.616 ;
     RECT  6.973 75.6 7.045 75.624 ;
     RECT  6.221 1.872 7.085 1.896 ;
     RECT  6.973 49.872 7.333 51.192 ;
     RECT  6.937 14.832 7.369 19.944 ;
     RECT  6.865 65.856 7.429 66.696 ;
     RECT  6.797 68.064 7.429 70.008 ;
     RECT  7.333 49.872 7.441 51.624 ;
     RECT  6.515 39.744 7.513 39.768 ;
     RECT  6.515 40.848 7.513 48.744 ;
     RECT  6.689 77.952 7.585 77.976 ;
     RECT  7.045 74.112 7.649 75.624 ;
     RECT  6.829 3.072 7.808 6.84 ;
     RECT  6.581 7.872 7.808 7.944 ;
     RECT  5.789 8.928 7.808 8.952 ;
     RECT  6.761 10.08 7.808 13.416 ;
     RECT  7.369 14.832 7.808 20.184 ;
     RECT  6.149 21.264 7.808 21.72 ;
     RECT  6.721 23.04 7.808 29.4 ;
     RECT  6.577 30.576 7.808 33.624 ;
     RECT  6.721 35.712 7.808 38.328 ;
     RECT  7.513 39.744 7.808 48.744 ;
     RECT  7.441 49.872 7.808 52.2 ;
     RECT  6.901 53.76 7.808 64.872 ;
     RECT  7.429 65.856 7.808 70.008 ;
     RECT  6.833 71.616 7.808 71.928 ;
     RECT  6.563 73.104 7.808 73.128 ;
     RECT  7.649 74.112 7.808 76.2 ;
     RECT  7.585 77.952 7.808 78.696 ;
     RECT  7.808 2.148 7.912 95.052 ;
     RECT  7.912 2.418 8.104 94.782 ;
     RECT  8.104 22.896 8.165 24.936 ;
     RECT  8.104 26.016 8.165 28.488 ;
     RECT  8.104 60.816 8.165 64.104 ;
     RECT  8.104 77.952 8.165 78.504 ;
     RECT  8.165 27.84 8.273 28.488 ;
     RECT  8.104 3.168 8.291 8.472 ;
     RECT  8.104 50.64 8.291 58.68 ;
     RECT  8.104 68.64 8.339 70.68 ;
     RECT  8.104 71.904 8.339 71.928 ;
     RECT  8.104 72.912 8.339 73.8 ;
     RECT  8.104 10.08 8.417 13.416 ;
     RECT  8.165 22.896 8.561 23.688 ;
     RECT  8.104 31.296 8.597 36.264 ;
     RECT  8.165 60.816 8.597 63.624 ;
     RECT  8.417 10.08 8.669 11.928 ;
     RECT  8.104 65.808 8.669 67.656 ;
     RECT  8.104 15.36 8.705 21.816 ;
     RECT  8.165 78.48 8.705 78.504 ;
     RECT  8.291 6.768 8.777 8.472 ;
     RECT  8.705 18.576 8.777 21.816 ;
     RECT  8.165 26.016 8.777 26.76 ;
     RECT  8.597 31.296 8.813 32.472 ;
     RECT  8.104 37.584 8.849 44.904 ;
     RECT  8.291 50.64 8.849 52.44 ;
     RECT  8.291 54 8.849 58.68 ;
     RECT  8.777 6.768 8.885 6.936 ;
     RECT  8.669 65.808 8.993 67.176 ;
     RECT  8.417 13.392 9.029 13.416 ;
     RECT  8.339 73.536 9.029 73.8 ;
     RECT  8.993 65.904 9.037 67.176 ;
     RECT  8.339 68.64 9.065 69.72 ;
     RECT  8.104 75.12 9.065 75.144 ;
     RECT  8.885 6.768 9.137 6.792 ;
     RECT  8.669 10.08 9.137 11.832 ;
     RECT  8.597 33.552 9.155 36.264 ;
     RECT  8.104 46.224 9.173 48.936 ;
     RECT  8.597 61.488 9.245 63.624 ;
     RECT  9.173 46.656 9.277 48.936 ;
     RECT  8.777 18.576 9.281 20.184 ;
     RECT  8.165 24.912 9.301 24.936 ;
     RECT  9.155 34.608 9.313 36.264 ;
     RECT  8.849 37.584 9.353 39.528 ;
     RECT  9.245 61.536 9.385 63.624 ;
     RECT  8.291 3.168 9.425 5.688 ;
     RECT  9.353 37.68 9.443 39.528 ;
     RECT  8.104 30 9.445 30.024 ;
     RECT  8.813 31.296 9.445 31.752 ;
     RECT  8.777 21.504 9.457 21.816 ;
     RECT  8.561 22.896 9.457 23.112 ;
     RECT  9.313 34.608 9.491 36.504 ;
     RECT  9.301 24.096 9.533 24.936 ;
     RECT  9.425 3.168 9.565 3.816 ;
     RECT  9.385 58.704 9.569 58.728 ;
     RECT  9.137 10.08 9.601 11.784 ;
     RECT  8.273 27.84 9.637 28.248 ;
     RECT  9.421 70.8 9.637 70.824 ;
     RECT  9.565 3.072 9.677 3.816 ;
     RECT  9.065 68.64 9.683 69.336 ;
     RECT  8.849 54 9.731 57.624 ;
     RECT  9.637 27.84 9.733 28.536 ;
     RECT  9.445 30 9.733 31.752 ;
     RECT  9.425 5.136 9.745 5.688 ;
     RECT  9.677 3.072 9.749 3.576 ;
     RECT  9.733 27.84 9.749 31.752 ;
     RECT  9.749 27.888 9.82 31.752 ;
     RECT  9.82 29.952 9.853 31.752 ;
     RECT  9.731 54.576 9.875 57.624 ;
     RECT  9.601 9.792 9.893 11.784 ;
     RECT  9.457 21.504 9.893 23.112 ;
     RECT  8.104 76.128 9.923 76.152 ;
     RECT  9.097 14.208 9.929 14.232 ;
     RECT  9.277 46.656 9.932 49.752 ;
     RECT  8.849 50.88 9.932 52.44 ;
     RECT  9.491 34.608 9.965 34.776 ;
     RECT  9.385 61.536 9.965 63.864 ;
     RECT  9.877 77.52 9.965 77.544 ;
     RECT  9.281 18.576 9.971 20.04 ;
     RECT  8.777 8.448 9.997 8.472 ;
     RECT  9.893 9.792 9.997 10.968 ;
     RECT  9.037 67.152 9.997 67.176 ;
     RECT  9.683 68.64 9.997 69 ;
     RECT  9.875 54.912 10.001 57.624 ;
     RECT  9.997 67.152 10.001 67.272 ;
     RECT  9.932 46.656 10.019 52.44 ;
     RECT  9.637 70.656 10.021 70.824 ;
     RECT  10.021 70.656 10.037 71.304 ;
     RECT  9.82 27.888 10.109 28.536 ;
     RECT  10.019 50.832 10.109 52.44 ;
     RECT  9.349 64.896 10.145 64.92 ;
     RECT  10.109 50.832 10.163 50.904 ;
     RECT  10.001 67.248 10.177 67.272 ;
     RECT  9.997 68.4 10.177 69 ;
     RECT  10.037 70.8 10.177 71.304 ;
     RECT  9.749 3.072 10.253 3.336 ;
     RECT  10.109 51.888 10.253 52.44 ;
     RECT  10.019 46.656 10.259 49.512 ;
     RECT  9.893 22.224 10.289 23.112 ;
     RECT  10.259 49.008 10.289 49.512 ;
     RECT  9.971 18.576 10.307 19.608 ;
     RECT  10.069 75.648 10.307 75.672 ;
     RECT  9.997 8.448 10.325 10.968 ;
     RECT  9.029 73.536 10.325 73.56 ;
     RECT  10.241 74.64 10.325 74.664 ;
     RECT  9.965 61.536 10.357 62.712 ;
     RECT  10.177 70.8 10.364 71.832 ;
     RECT  10.364 70.8 10.451 72.408 ;
     RECT  10.109 28.512 10.469 28.536 ;
     RECT  9.037 65.904 10.501 66.12 ;
     RECT  10.393 2.496 10.505 2.76 ;
     RECT  9.965 63.84 10.505 63.864 ;
     RECT  9.853 29.952 10.54 32.28 ;
     RECT  9.155 33.552 10.541 33.576 ;
     RECT  9.443 38.688 10.541 39.528 ;
     RECT  10.001 55.056 10.541 57.624 ;
     RECT  10.177 67.248 10.541 69 ;
     RECT  10.451 70.8 10.541 71.832 ;
     RECT  9.443 37.68 10.577 37.704 ;
     RECT  8.705 15.36 10.604 17.352 ;
     RECT  10.54 30.24 10.609 32.28 ;
     RECT  10.604 15.168 10.691 17.352 ;
     RECT  10.253 51.888 10.691 51.912 ;
     RECT  10.325 8.448 10.721 9.048 ;
     RECT  10.541 67.248 10.721 67.848 ;
     RECT  8.777 26.112 10.789 26.76 ;
     RECT  10.609 30.24 10.825 32.472 ;
     RECT  9.965 34.752 10.837 34.776 ;
     RECT  9.491 35.952 10.837 36.504 ;
     RECT  10.691 16.032 10.865 17.352 ;
     RECT  10.825 30.24 10.865 33.048 ;
     RECT  10.307 18.576 10.901 19.56 ;
     RECT  10.837 34.752 10.924 36.504 ;
     RECT  10.924 36.48 10.929 36.504 ;
     RECT  10.325 10.512 10.933 10.968 ;
     RECT  10.357 61.008 10.937 62.712 ;
     RECT  10.924 34.752 11.009 34.776 ;
     RECT  10.259 46.848 11.009 47.88 ;
     RECT  9.533 24.912 11.041 24.936 ;
     RECT  10.789 26.016 11.041 26.76 ;
     RECT  10.505 2.736 11.045 2.76 ;
     RECT  10.865 30.24 11.081 31.944 ;
     RECT  10.541 68.976 11.081 69 ;
     RECT  11.041 24.912 11.149 26.76 ;
     RECT  10.865 16.176 11.153 17.352 ;
     RECT  10.933 10.512 11.18 11.352 ;
     RECT  10.141 13.008 11.18 13.032 ;
     RECT  10.541 55.056 11.189 57.192 ;
     RECT  10.501 65.52 11.257 66.12 ;
     RECT  10.721 67.248 11.257 67.272 ;
     RECT  11.081 31.488 11.261 31.944 ;
     RECT  11.189 56.256 11.261 57.192 ;
     RECT  11.18 10.512 11.267 13.032 ;
     RECT  11.153 16.368 11.297 17.352 ;
     RECT  11.081 30.24 11.297 30.504 ;
     RECT  11.009 46.896 11.333 47.88 ;
     RECT  11.149 24.912 11.369 27.384 ;
     RECT  11.317 34.032 11.404 34.056 ;
     RECT  11.297 16.368 11.405 16.632 ;
     RECT  10.033 21.216 11.437 21.24 ;
     RECT  11.369 24.912 11.461 25.128 ;
     RECT  10.289 22.224 11.473 23.016 ;
     RECT  11.461 24.144 11.473 25.128 ;
     RECT  11.267 10.512 11.477 11.352 ;
     RECT  11.267 12.528 11.477 13.032 ;
     RECT  11.005 14.832 11.477 14.856 ;
     RECT  11.437 21.12 11.477 21.24 ;
     RECT  10.937 61.008 11.507 62.616 ;
     RECT  11.257 65.52 11.507 67.272 ;
     RECT  10.541 71.28 11.507 71.304 ;
     RECT  10.163 50.832 11.512 50.856 ;
     RECT  10.289 49.488 11.513 49.512 ;
     RECT  11.512 50.832 11.513 50.904 ;
     RECT  11.473 22.224 11.548 25.128 ;
     RECT  10.901 19.344 11.549 19.56 ;
     RECT  11.477 10.512 11.581 10.872 ;
     RECT  11.507 61.008 11.621 62.088 ;
     RECT  11.461 63.792 11.657 63.816 ;
     RECT  9.745 5.136 11.689 6.12 ;
     RECT  10.609 7.2 11.689 7.224 ;
     RECT  11.261 31.92 11.729 31.944 ;
     RECT  11.261 57.168 11.729 57.192 ;
     RECT  11.507 65.52 11.729 65.544 ;
     RECT  11.507 66.576 11.729 67.272 ;
     RECT  11.513 50.88 11.801 50.904 ;
     RECT  11.405 16.368 11.836 16.536 ;
     RECT  11.729 66.576 11.873 66.792 ;
     RECT  11.548 22.224 11.891 23.736 ;
     RECT  11.689 5.136 11.981 7.224 ;
     RECT  11.621 61.728 12.017 62.088 ;
     RECT  11.873 66.576 12.017 66.6 ;
     RECT  11.581 9.936 12.035 10.872 ;
     RECT  12.035 10.848 12.061 10.872 ;
     RECT  11.725 2.832 12.095 2.856 ;
     RECT  10.865 33.024 12.161 33.048 ;
     RECT  12.095 2.832 12.179 3.096 ;
     RECT  11.981 5.424 12.38 7.224 ;
     RECT  10.721 8.448 12.38 8.712 ;
     RECT  11.549 19.344 12.553 19.368 ;
     RECT  11.941 29.04 12.62 29.064 ;
     RECT  11.297 30.24 12.62 30.264 ;
     RECT  11.836 16.368 12.86 16.392 ;
     RECT  12.86 15.84 12.863 16.392 ;
     RECT  11.717 17.664 12.863 17.688 ;
     RECT  11.477 21.12 12.908 21.144 ;
     RECT  12.179 3.024 12.913 3.096 ;
     RECT  12.908 20.784 13.021 21.144 ;
     RECT  11.891 22.224 13.021 22.248 ;
     RECT  12.913 3.024 13.208 3.384 ;
     RECT  12.265 4.416 13.208 4.44 ;
     RECT  12.38 5.424 13.208 8.712 ;
     RECT  12.863 15.84 13.208 17.688 ;
     RECT  12.553 19.344 13.208 19.8 ;
     RECT  13.021 20.784 13.208 22.248 ;
     RECT  11.891 23.376 13.208 23.736 ;
     RECT  11.548 24.912 13.208 25.128 ;
     RECT  11.369 26.208 13.208 27.384 ;
     RECT  12.62 29.04 13.208 30.264 ;
     RECT  10.541 38.688 13.208 38.712 ;
     RECT  8.849 41.136 13.208 44.904 ;
     RECT  11.333 47.856 13.208 47.88 ;
     RECT  11.189 55.056 13.208 55.176 ;
     RECT  12.017 61.728 13.208 61.752 ;
     RECT  13.208 2.148 13.312 95.052 ;
     RECT  13.312 2.418 13.504 94.782 ;
     RECT  13.504 2.832 13.565 3.384 ;
     RECT  13.504 18.912 13.709 18.936 ;
     RECT  13.504 61.728 13.811 61.752 ;
     RECT  13.504 57.552 13.817 57.576 ;
     RECT  13.504 23.376 13.889 23.736 ;
     RECT  13.504 25.008 13.955 25.032 ;
     RECT  13.504 55.152 13.955 55.176 ;
     RECT  13.504 56.448 13.955 56.472 ;
     RECT  13.504 6.096 14.003 6.312 ;
     RECT  13.565 2.832 14.005 2.856 ;
     RECT  13.889 23.712 14.033 23.736 ;
     RECT  14.821 0.576 14.905 0.6 ;
     RECT  15.101 0.096 16.549 0.12 ;
     RECT  16.549 0.096 16.633 0.6 ;
     RECT  13.504 35.424 18.169 35.448 ;
     RECT  14.461 1.728 18.608 1.752 ;
     RECT  18.169 35.424 18.608 35.88 ;
     RECT  13.504 38.688 18.608 38.712 ;
     RECT  13.504 41.136 18.608 44.952 ;
     RECT  13.504 47.856 18.608 47.88 ;
     RECT  18.608 1.728 18.712 95.052 ;
     RECT  18.712 1.728 18.904 94.782 ;
     RECT  16.633 0.096 21.157 0.12 ;
     RECT  21.157 0.096 21.241 0.6 ;
     RECT  21.241 0.096 23.965 0.12 ;
     RECT  18.904 1.728 24.008 1.752 ;
     RECT  18.904 38.688 24.008 38.712 ;
     RECT  18.904 41.136 24.008 44.904 ;
     RECT  18.904 47.856 24.008 47.88 ;
     RECT  23.965 0.096 24.083 0.552 ;
     RECT  24.008 1.728 24.112 95.052 ;
     RECT  24.112 1.728 24.304 94.782 ;
     RECT  24.083 0.096 26.189 0.12 ;
     RECT  26.189 0.096 26.273 0.6 ;
     RECT  26.273 0.096 28.153 0.12 ;
     RECT  24.304 1.728 28.261 1.752 ;
     RECT  24.304 38.688 29.408 38.712 ;
     RECT  24.304 41.136 29.408 44.904 ;
     RECT  24.304 47.856 29.408 47.88 ;
     RECT  29.408 2.148 29.501 95.052 ;
     RECT  29.501 1.728 29.512 95.052 ;
     RECT  29.512 1.728 29.704 94.782 ;
     RECT  29.653 0.528 29.765 0.552 ;
     RECT  29.905 0.096 33.761 0.12 ;
     RECT  29.704 1.728 34.192 1.752 ;
     RECT  34.192 1.728 34.765 1.8 ;
     RECT  34.765 1.728 34.808 1.848 ;
     RECT  29.704 38.688 34.808 38.712 ;
     RECT  29.704 41.136 34.808 44.904 ;
     RECT  29.704 47.856 34.808 47.88 ;
     RECT  34.808 1.728 34.912 95.052 ;
     RECT  34.912 1.728 35.104 94.782 ;
     RECT  35.104 38.688 38.293 38.712 ;
     RECT  38.293 38.688 38.657 38.76 ;
     RECT  35.104 1.728 40.208 1.752 ;
     RECT  38.657 38.736 40.208 38.76 ;
     RECT  35.104 41.136 40.208 44.904 ;
     RECT  35.104 47.856 40.208 47.88 ;
     RECT  40.208 1.728 40.312 95.052 ;
     RECT  40.312 1.728 40.504 94.782 ;
     RECT  35.845 0.096 42.757 0.12 ;
     RECT  42.757 0.096 43.417 0.6 ;
     RECT  43.417 0.096 44.425 0.12 ;
     RECT  40.504 1.728 45.46 1.752 ;
     RECT  45.46 1.728 45.608 1.8 ;
     RECT  40.504 38.736 45.608 38.76 ;
     RECT  40.504 41.136 45.608 44.904 ;
     RECT  40.504 47.856 45.608 47.88 ;
     RECT  45.608 1.728 45.712 95.052 ;
     RECT  45.712 1.728 45.904 94.782 ;
     RECT  45.904 1.728 45.973 1.8 ;
     RECT  45.904 38.736 48.421 38.76 ;
     RECT  45.904 41.136 48.421 44.904 ;
     RECT  48.421 41.088 48.508 44.904 ;
     RECT  45.973 1.728 49.6 1.752 ;
     RECT  49.6 1.728 49.717 1.8 ;
     RECT  49.717 1.728 51.008 1.752 ;
     RECT  48.421 38.736 51.008 39 ;
     RECT  48.508 41.376 51.008 44.904 ;
     RECT  45.904 47.856 51.008 47.88 ;
     RECT  51.008 1.728 51.112 95.052 ;
     RECT  51.112 1.728 51.304 94.782 ;
     RECT  51.304 41.376 53.957 44.904 ;
     RECT  51.304 38.736 54.085 39 ;
     RECT  54.085 38.736 54.137 39.144 ;
     RECT  54.137 38.976 54.172 39.144 ;
     RECT  53.957 41.376 55.825 44.616 ;
     RECT  45.637 0.096 55.861 0.12 ;
     RECT  55.861 0.096 55.945 0.6 ;
     RECT  51.304 1.728 56.408 1.752 ;
     RECT  54.172 38.976 56.408 39 ;
     RECT  55.825 41.376 56.408 44.712 ;
     RECT  51.304 47.856 56.408 47.88 ;
     RECT  56.408 1.728 56.512 95.052 ;
     RECT  55.945 0.096 56.585 0.552 ;
     RECT  56.512 1.728 56.704 94.782 ;
     RECT  56.704 41.376 56.801 44.712 ;
     RECT  56.585 0.096 56.981 0.12 ;
     RECT  56.704 1.728 57.097 1.752 ;
     RECT  58.309 1.728 61.808 1.752 ;
     RECT  56.704 38.976 61.808 39 ;
     RECT  56.801 41.376 61.808 44.616 ;
     RECT  56.704 47.856 61.808 47.88 ;
     RECT  61.808 1.728 61.912 95.052 ;
     RECT  61.912 1.728 62.104 94.782 ;
     RECT  62.104 47.712 62.561 47.88 ;
     RECT  62.104 1.728 62.675 1.848 ;
     RECT  62.561 47.712 62.849 47.736 ;
     RECT  62.104 41.376 64.033 44.712 ;
     RECT  64.033 41.376 64.181 44.952 ;
     RECT  64.285 94.032 64.316 94.056 ;
     RECT  64.213 95.136 64.316 95.16 ;
     RECT  64.316 94.032 64.325 95.16 ;
     RECT  64.325 94.032 64.403 94.68 ;
     RECT  64.403 94.032 64.429 94.056 ;
     RECT  64.429 93.552 64.469 94.056 ;
     RECT  64.321 96.336 64.547 96.36 ;
     RECT  63.241 46.704 64.753 46.728 ;
     RECT  64.681 47.76 64.753 47.784 ;
     RECT  64.753 46.704 65.297 47.784 ;
     RECT  62.104 38.976 65.324 39 ;
     RECT  65.257 40.368 65.324 40.392 ;
     RECT  65.324 38.976 65.357 40.392 ;
     RECT  64.181 41.376 65.357 44.904 ;
     RECT  65.297 46.704 65.405 47.64 ;
     RECT  65.357 38.976 65.689 44.904 ;
     RECT  65.689 38.976 65.797 45.096 ;
     RECT  65.797 38.736 65.869 45.096 ;
     RECT  65.405 46.752 65.939 47.64 ;
     RECT  62.675 1.728 66.62 1.752 ;
     RECT  66.62 1.728 67.208 1.8 ;
     RECT  65.869 38.736 67.208 45.768 ;
     RECT  65.939 46.896 67.208 47.64 ;
     RECT  64.469 93.552 67.208 93.576 ;
     RECT  67.208 1.728 67.237 95.052 ;
     RECT  67.237 1.104 67.312 95.052 ;
     RECT  67.312 1.104 67.465 94.782 ;
     RECT  67.465 2.256 67.504 94.782 ;
     RECT  67.504 46.896 67.565 47.64 ;
     RECT  67.465 1.104 67.571 1.128 ;
     RECT  67.565 46.896 67.673 47.16 ;
     RECT  58.417 0.096 67.741 0.12 ;
     RECT  67.504 38.88 67.817 45.816 ;
     RECT  67.741 0.096 67.859 0.216 ;
     RECT  67.504 2.256 67.859 5.208 ;
     RECT  67.859 2.256 68.003 4.536 ;
     RECT  68.003 2.88 68.177 4.536 ;
     RECT  67.817 38.976 68.177 45.816 ;
     RECT  67.859 0.096 68.609 0.168 ;
     RECT  68.177 3.072 68.821 4.536 ;
     RECT  68.821 3.072 68.825 4.728 ;
     RECT  68.177 38.976 68.885 45.192 ;
     RECT  68.825 4.224 68.965 4.728 ;
     RECT  68.885 38.16 68.969 45.192 ;
     RECT  68.825 3.072 69.005 3.096 ;
     RECT  68.677 6.24 69.073 6.264 ;
     RECT  68.965 4.224 69.217 4.776 ;
     RECT  67.673 47.136 69.301 47.16 ;
     RECT  69.301 46.176 69.401 47.16 ;
     RECT  69.325 1.728 69.443 1.752 ;
     RECT  69.401 46.608 69.539 47.16 ;
     RECT  68.969 38.4 69.617 45.192 ;
     RECT  69.617 38.4 69.725 45 ;
     RECT  68.609 0.096 69.829 0.12 ;
     RECT  69.217 4.224 69.865 5.112 ;
     RECT  69.073 6.24 69.865 6.552 ;
     RECT  69.725 38.4 69.905 44.952 ;
     RECT  69.865 4.224 70.045 6.552 ;
     RECT  69.829 0.096 70.117 0.216 ;
     RECT  69.905 38.4 70.193 39.864 ;
     RECT  70.117 0.096 70.229 0.6 ;
     RECT  70.193 38.4 70.301 39 ;
     RECT  69.905 40.944 70.697 44.952 ;
     RECT  69.539 46.608 70.697 46.68 ;
     RECT  70.697 46.656 70.805 46.68 ;
     RECT  70.045 3.936 70.873 6.552 ;
     RECT  70.873 3.168 71.017 6.552 ;
     RECT  71.017 2.256 71.117 6.552 ;
     RECT  70.229 0.096 71.129 0.168 ;
     RECT  71.129 0.144 71.228 0.168 ;
     RECT  71.228 0.144 71.315 0.552 ;
     RECT  70.697 41.184 71.485 44.952 ;
     RECT  71.315 0.144 72.133 0.312 ;
     RECT  71.485 41.184 72.236 45 ;
     RECT  72.236 40.656 72.349 45 ;
     RECT  72.349 40.608 72.385 45 ;
     RECT  71.117 1.728 72.608 6.552 ;
     RECT  70.301 38.592 72.608 39 ;
     RECT  72.385 40.608 72.608 45.048 ;
     RECT  67.504 93.552 72.608 93.576 ;
     RECT  72.608 1.728 72.712 95.052 ;
     RECT  72.712 1.728 72.904 94.782 ;
     RECT  72.904 2.88 73.037 5.016 ;
     RECT  73.037 2.88 73.073 4.152 ;
     RECT  72.133 0.096 73.361 0.312 ;
     RECT  73.361 0.096 73.577 0.264 ;
     RECT  72.904 1.728 73.997 1.8 ;
     RECT  72.904 38.16 74.045 39 ;
     RECT  73.997 1.728 74.081 1.896 ;
     RECT  73.073 2.88 74.101 3.96 ;
     RECT  74.081 1.728 74.117 1.8 ;
     RECT  72.904 6.384 74.147 6.408 ;
     RECT  74.101 2.88 74.333 4.392 ;
     RECT  74.333 3.408 74.541 4.392 ;
     RECT  74.541 3.696 74.765 4.392 ;
     RECT  74.045 38.304 74.833 39 ;
     RECT  72.904 40.032 74.833 45.048 ;
     RECT  74.833 38.304 74.873 45.048 ;
     RECT  74.873 38.976 75.413 45.048 ;
     RECT  75.517 46.128 75.601 46.152 ;
     RECT  75.413 38.976 75.827 39.096 ;
     RECT  75.413 40.128 75.917 45.048 ;
     RECT  75.917 40.416 76.025 45.048 ;
     RECT  74.765 3.84 76.165 4.392 ;
     RECT  76.165 3.408 76.453 4.392 ;
     RECT  76.412 5.712 76.499 5.736 ;
     RECT  74.117 1.728 76.561 1.752 ;
     RECT  76.453 3.408 76.561 4.536 ;
     RECT  76.561 1.728 76.741 1.8 ;
     RECT  76.561 3.072 76.741 4.536 ;
     RECT  76.741 1.728 76.777 4.536 ;
     RECT  76.777 1.104 76.931 4.536 ;
     RECT  76.025 40.464 76.961 45.048 ;
     RECT  76.961 40.464 76.997 44.184 ;
     RECT  76.931 1.728 77.507 4.536 ;
     RECT  77.507 1.824 77.537 4.536 ;
     RECT  73.577 0.096 77.605 0.12 ;
     RECT  77.537 2.148 78.008 4.536 ;
     RECT  77.389 5.76 78.008 5.784 ;
     RECT  75.827 38.976 78.008 39 ;
     RECT  76.997 41.184 78.008 44.184 ;
     RECT  77.497 45.168 78.008 45.192 ;
     RECT  77.365 46.224 78.008 46.248 ;
     RECT  77.353 47.328 78.008 47.352 ;
     RECT  77.137 48.432 78.008 48.456 ;
     RECT  75.541 49.488 78.008 49.512 ;
     RECT  72.904 93.552 78.008 93.576 ;
     RECT  78.008 2.148 78.112 95.052 ;
     RECT  78.112 2.148 78.304 94.782 ;
     RECT  78.304 2.148 78.613 6.504 ;
     RECT  78.613 1.728 78.797 6.504 ;
     RECT  78.797 1.728 79.229 3.432 ;
     RECT  79.229 2.208 79.265 3.432 ;
     RECT  78.304 46.608 79.301 48.408 ;
     RECT  78.797 4.512 79.373 6.504 ;
     RECT  79.265 2.208 79.445 2.28 ;
     RECT  79.373 5.76 79.445 6.504 ;
     RECT  78.304 41.184 79.481 45.192 ;
     RECT  77.605 0.096 79.553 0.552 ;
     RECT  79.481 41.184 79.769 44.712 ;
     RECT  79.445 5.76 79.877 6.312 ;
     RECT  79.301 47.856 80.017 48.408 ;
     RECT  80.017 47.856 80.057 48.504 ;
     RECT  79.445 2.256 80.129 2.28 ;
     RECT  79.553 0.096 80.233 0.408 ;
     RECT  78.304 49.488 80.233 50.184 ;
     RECT  79.301 46.608 80.341 46.632 ;
     RECT  79.265 3.408 80.521 3.432 ;
     RECT  80.341 46.08 80.557 46.872 ;
     RECT  80.413 67.248 80.581 67.272 ;
     RECT  78.304 38.976 80.593 39 ;
     RECT  78.304 93.552 80.627 93.576 ;
     RECT  80.521 2.736 80.737 3.432 ;
     RECT  79.373 4.512 80.737 4.536 ;
     RECT  79.877 5.76 80.737 5.784 ;
     RECT  80.233 0.048 80.773 0.408 ;
     RECT  80.593 38.976 80.777 39.096 ;
     RECT  80.581 67.248 80.777 67.752 ;
     RECT  80.737 5.712 80.881 5.784 ;
     RECT  79.769 41.184 80.885 44.52 ;
     RECT  80.881 5.712 81.097 6.312 ;
     RECT  80.057 48.48 81.173 48.504 ;
     RECT  80.737 2.736 81.205 4.536 ;
     RECT  80.885 41.232 81.395 44.52 ;
     RECT  81.395 41.424 81.529 44.52 ;
     RECT  80.557 45.792 81.565 46.872 ;
     RECT  81.565 45.792 81.589 47.352 ;
     RECT  81.097 5.712 81.673 6.552 ;
     RECT  81.529 41.424 81.673 44.664 ;
     RECT  81.589 45.744 81.673 47.352 ;
     RECT  81.673 5.712 81.821 6.648 ;
     RECT  80.233 49.488 81.821 50.472 ;
     RECT  80.581 56.496 81.925 56.52 ;
     RECT  81.821 5.712 82.037 6.312 ;
     RECT  81.673 41.424 82.141 47.352 ;
     RECT  82.037 6.288 82.181 6.312 ;
     RECT  81.205 2.736 82.217 4.584 ;
     RECT  81.565 38.736 82.271 38.76 ;
     RECT  82.46 31.872 82.465 31.896 ;
     RECT  81.821 49.488 82.537 50.328 ;
     RECT  80.773 0.048 82.613 0.552 ;
     RECT  82.217 2.784 82.645 4.584 ;
     RECT  82.465 31.872 82.645 32.136 ;
     RECT  82.141 41.424 82.645 47.784 ;
     RECT  82.537 49.008 82.645 50.328 ;
     RECT  82.613 0.048 82.901 0.504 ;
     RECT  81.961 55.104 83.005 55.128 ;
     RECT  81.925 56.496 83.005 56.904 ;
     RECT  82.271 38.736 83.185 38.904 ;
     RECT  83.185 38.736 83.221 39.288 ;
     RECT  82.429 40.272 83.221 40.296 ;
     RECT  83.221 38.736 83.269 40.296 ;
     RECT  82.645 41.424 83.269 50.328 ;
     RECT  83.221 54.048 83.269 54.072 ;
     RECT  82.213 1.728 83.408 1.752 ;
     RECT  82.645 2.784 83.408 4.824 ;
     RECT  82.645 31.872 83.408 32.232 ;
     RECT  83.269 38.736 83.408 50.376 ;
     RECT  83.269 53.76 83.408 54.072 ;
     RECT  83.005 55.104 83.408 56.904 ;
     RECT  80.777 67.248 83.408 67.272 ;
     RECT  83.408 1.728 83.512 95.052 ;
     RECT  82.901 0.048 83.585 0.456 ;
     RECT  83.512 1.728 83.704 94.782 ;
     RECT  83.704 1.728 83.729 1.8 ;
     RECT  83.704 38.4 83.765 39.288 ;
     RECT  83.704 40.944 83.837 50.376 ;
     RECT  83.585 0.048 84.053 0.12 ;
     RECT  83.704 32.064 84.083 32.232 ;
     RECT  83.704 55.728 84.323 57 ;
     RECT  83.837 47.856 84.341 50.376 ;
     RECT  84.323 55.728 84.341 56.712 ;
     RECT  84.341 55.824 84.364 56.712 ;
     RECT  84.341 49.536 84.413 50.376 ;
     RECT  83.837 40.944 84.737 46.68 ;
     RECT  83.704 3.936 84.949 3.96 ;
     RECT  83.704 54.048 84.949 54.072 ;
     RECT  84.737 41.376 84.953 46.68 ;
     RECT  84.364 56.352 84.953 56.712 ;
     RECT  84.949 3.648 84.989 3.96 ;
     RECT  84.949 54.048 84.995 54.168 ;
     RECT  84.953 41.376 85.061 43.656 ;
     RECT  85.061 41.376 85.169 43.416 ;
     RECT  85.169 41.664 85.205 43.416 ;
     RECT  85.205 41.952 85.349 43.416 ;
     RECT  84.953 44.64 85.453 46.68 ;
     RECT  85.453 44.64 85.489 46.872 ;
     RECT  84.341 47.856 85.489 48.216 ;
     RECT  84.953 56.496 85.489 56.712 ;
     RECT  84.413 50.304 85.493 50.376 ;
     RECT  85.489 44.64 85.529 48.216 ;
     RECT  85.489 56.496 85.637 57 ;
     RECT  85.637 56.544 85.745 57 ;
     RECT  85.349 42.144 85.997 43.416 ;
     RECT  85.997 43.392 86.033 43.416 ;
     RECT  84.053 0.096 86.213 0.12 ;
     RECT  84.989 3.648 86.393 3.672 ;
     RECT  85.493 50.352 86.533 50.376 ;
     RECT  85.529 44.64 86.713 47.88 ;
     RECT  85.745 56.688 86.749 57 ;
     RECT  86.533 49.536 86.915 50.376 ;
     RECT  86.821 43.632 86.917 43.656 ;
     RECT  86.713 44.64 86.917 47.976 ;
     RECT  85.997 42.144 87.205 42.168 ;
     RECT  86.917 43.632 87.205 47.976 ;
     RECT  86.749 56.544 87.217 57 ;
     RECT  87.205 42.144 87.251 47.976 ;
     RECT  84.995 54.144 87.325 54.168 ;
     RECT  87.325 54.144 87.541 54.84 ;
     RECT  87.251 42.816 87.649 47.976 ;
     RECT  87.541 54.144 87.685 54.936 ;
     RECT  87.217 56.064 87.685 57 ;
     RECT  83.765 38.4 87.721 38.424 ;
     RECT  87.685 54.144 87.761 57 ;
     RECT  87.721 38.4 87.937 38.712 ;
     RECT  86.915 49.536 88.22 50.04 ;
     RECT  88.22 49.488 88.261 50.04 ;
     RECT  87.649 42.816 88.657 48.456 ;
     RECT  88.261 49.488 88.657 50.136 ;
     RECT  87.721 52.176 88.657 52.2 ;
     RECT  83.729 1.728 88.74 1.752 ;
     RECT  88.74 1.728 88.808 1.8 ;
     RECT  87.937 38.4 88.808 39.336 ;
     RECT  88.657 42.816 88.808 50.136 ;
     RECT  88.657 52.176 88.808 52.824 ;
     RECT  87.761 54.336 88.808 57 ;
     RECT  88.808 1.728 88.912 95.052 ;
     RECT  88.912 1.728 89.104 94.782 ;
     RECT  89.104 38.4 89.404 40.344 ;
     RECT  89.104 42.48 89.453 52.968 ;
     RECT  89.453 42.72 89.486 52.968 ;
     RECT  89.404 38.4 89.525 39.768 ;
     RECT  89.486 42.768 90.029 52.968 ;
     RECT  90.029 44.064 90.124 52.968 ;
     RECT  90.124 50.592 90.227 52.968 ;
     RECT  89.525 38.688 90.781 39.768 ;
     RECT  90.029 42.768 90.997 43.032 ;
     RECT  90.124 44.064 90.997 49.56 ;
     RECT  90.781 38.688 91.033 39.816 ;
     RECT  90.997 42.768 91.037 49.56 ;
     RECT  91.033 38.592 91.052 39.816 ;
     RECT  91.052 38.592 91.139 40.056 ;
     RECT  89.104 54.048 91.285 56.904 ;
     RECT  91.139 38.592 91.325 39.816 ;
     RECT  91.285 54 91.393 56.904 ;
     RECT  91.037 43.008 91.541 49.56 ;
     RECT  91.541 49.536 92.341 49.56 ;
     RECT  90.227 50.688 92.341 52.968 ;
     RECT  92.341 49.536 92.473 52.968 ;
     RECT  91.393 54 92.473 57.048 ;
     RECT  91.325 38.592 92.549 39.72 ;
     RECT  92.473 49.536 92.549 57.048 ;
     RECT  92.549 39.312 92.693 39.72 ;
     RECT  91.541 43.008 92.693 48.504 ;
     RECT  92.693 43.152 92.729 48.504 ;
     RECT  92.729 46.224 92.797 48.504 ;
     RECT  92.549 49.536 92.797 56.856 ;
     RECT  92.693 39.408 92.801 39.72 ;
     RECT  92.729 43.152 92.837 45.192 ;
     RECT  92.797 46.224 92.837 56.856 ;
     RECT  92.837 46.224 92.873 52.584 ;
     RECT  92.837 43.2 92.981 45.192 ;
     RECT  92.873 46.224 92.981 52.488 ;
     RECT  92.837 54 93.125 56.856 ;
     RECT  92.981 46.224 93.161 51.24 ;
     RECT  93.125 55.728 93.161 56.856 ;
     RECT  92.981 43.2 93.233 43.224 ;
     RECT  93.161 55.728 93.233 56.712 ;
     RECT  89.104 1.728 94.208 1.752 ;
     RECT  92.801 39.696 94.208 39.72 ;
     RECT  92.981 44.496 94.208 45.192 ;
     RECT  93.161 46.224 94.208 49.56 ;
     RECT  93.161 50.688 94.208 51.24 ;
     RECT  92.981 52.464 94.208 52.488 ;
     RECT  93.125 54 94.208 54.552 ;
     RECT  93.233 56.256 94.208 56.712 ;
     RECT  94.208 1.728 94.312 95.052 ;
     RECT  87.253 0.096 94.385 0.12 ;
     RECT  94.312 1.728 94.504 94.782 ;
     RECT  94.504 1.728 94.537 2.376 ;
     RECT  94.597 0.144 94.739 0.168 ;
     RECT  94.669 1.152 94.741 1.176 ;
     RECT  94.537 2.256 95.075 2.376 ;
     RECT  94.504 43.92 95.713 49.128 ;
     RECT  94.504 50.256 95.713 51.24 ;
     RECT  94.504 52.272 95.713 52.44 ;
     RECT  94.504 53.856 95.713 56.904 ;
     RECT  95.713 43.488 95.749 57.048 ;
     RECT  94.741 0.576 95.833 1.176 ;
     RECT  95.075 2.256 96.083 2.28 ;
     RECT  95.833 0.576 96.265 0.6 ;
     RECT  94.504 39.024 96.289 39.48 ;
     RECT  96.289 38.736 96.325 39.48 ;
     RECT  96.325 38.736 97.116 38.76 ;
     RECT  96.325 38.76 97.164 38.88 ;
     RECT  96.325 38.88 97.116 38.904 ;
     RECT  96.325 38.904 97.164 39.024 ;
     RECT  96.325 39.024 97.116 39.048 ;
     RECT  96.325 39.048 97.164 39.168 ;
     RECT  96.325 39.168 97.116 39.192 ;
     RECT  96.325 39.192 97.164 39.312 ;
     RECT  96.325 39.312 97.116 39.336 ;
     RECT  96.325 39.336 97.164 39.456 ;
     RECT  96.325 39.456 97.116 39.48 ;
     RECT  96.325 39.48 97.164 39.6 ;
     RECT  96.325 39.6 97.116 39.624 ;
     RECT  96.325 39.624 97.164 39.744 ;
     RECT  96.325 39.744 97.116 39.768 ;
     RECT  95.749 43.344 97.116 43.368 ;
     RECT  95.749 43.368 97.164 43.488 ;
     RECT  95.749 43.488 97.116 43.512 ;
     RECT  95.749 43.512 97.164 43.632 ;
     RECT  95.749 43.632 97.116 43.656 ;
     RECT  95.749 43.656 97.164 43.776 ;
     RECT  95.749 43.776 97.116 43.8 ;
     RECT  95.749 43.8 97.164 43.92 ;
     RECT  95.749 43.92 97.116 43.944 ;
     RECT  95.749 43.944 97.164 44.064 ;
     RECT  95.749 44.064 97.116 44.088 ;
     RECT  95.749 44.088 97.164 44.208 ;
     RECT  95.749 44.208 97.116 44.232 ;
     RECT  95.749 44.232 97.164 44.352 ;
     RECT  95.749 44.352 97.116 44.376 ;
     RECT  95.749 44.376 97.164 44.496 ;
     RECT  95.749 44.496 97.116 44.52 ;
     RECT  95.749 44.52 97.164 44.64 ;
     RECT  95.749 44.64 97.116 44.664 ;
     RECT  95.749 44.664 97.164 44.784 ;
     RECT  95.749 44.784 97.116 44.808 ;
     RECT  95.749 44.808 97.164 44.928 ;
     RECT  95.749 44.928 97.116 44.952 ;
     RECT  95.749 44.952 97.164 45.072 ;
     RECT  95.749 45.072 97.116 45.096 ;
     RECT  95.749 45.096 97.164 45.216 ;
     RECT  95.749 45.216 97.116 45.24 ;
     RECT  95.749 45.24 97.164 45.36 ;
     RECT  95.749 45.36 97.116 45.384 ;
     RECT  95.749 45.384 97.164 45.504 ;
     RECT  95.749 45.504 97.116 45.528 ;
     RECT  95.749 45.528 97.164 45.648 ;
     RECT  95.749 45.648 97.116 45.672 ;
     RECT  95.749 45.672 97.164 45.792 ;
     RECT  95.749 45.792 97.116 45.816 ;
     RECT  95.749 45.816 97.164 45.936 ;
     RECT  95.749 45.936 97.116 45.96 ;
     RECT  95.749 45.96 97.164 46.08 ;
     RECT  95.749 46.08 97.116 46.104 ;
     RECT  95.749 46.104 97.164 46.224 ;
     RECT  95.749 46.224 97.116 46.248 ;
     RECT  95.749 46.248 97.164 46.368 ;
     RECT  95.749 46.368 97.116 46.392 ;
     RECT  95.749 46.392 97.164 46.512 ;
     RECT  95.749 46.512 97.116 46.536 ;
     RECT  95.749 46.536 97.164 46.656 ;
     RECT  95.749 46.656 97.116 46.68 ;
     RECT  95.749 46.68 97.164 46.8 ;
     RECT  95.749 46.8 97.116 46.824 ;
     RECT  95.749 46.824 97.164 46.944 ;
     RECT  95.749 46.944 97.116 46.968 ;
     RECT  95.749 46.968 97.164 47.088 ;
     RECT  95.749 47.088 97.116 47.112 ;
     RECT  95.749 47.112 97.164 47.232 ;
     RECT  95.749 47.232 97.116 47.256 ;
     RECT  95.749 47.256 97.164 47.376 ;
     RECT  95.749 47.376 97.116 47.4 ;
     RECT  95.749 47.4 97.164 47.52 ;
     RECT  95.749 47.52 97.116 47.544 ;
     RECT  95.749 47.544 97.164 47.664 ;
     RECT  95.749 47.664 97.116 47.688 ;
     RECT  95.749 47.688 97.164 47.808 ;
     RECT  95.749 47.808 97.116 47.832 ;
     RECT  95.749 47.832 97.164 47.952 ;
     RECT  95.749 47.952 97.116 47.976 ;
     RECT  95.749 47.976 97.164 48.096 ;
     RECT  95.749 48.096 97.116 48.12 ;
     RECT  95.749 48.12 97.164 48.24 ;
     RECT  95.749 48.24 97.116 48.264 ;
     RECT  95.749 48.264 97.164 48.384 ;
     RECT  95.749 48.384 97.116 48.408 ;
     RECT  95.749 48.408 97.164 48.528 ;
     RECT  95.749 48.528 97.116 48.552 ;
     RECT  95.749 48.552 97.164 48.672 ;
     RECT  95.749 48.672 97.116 48.696 ;
     RECT  95.749 48.696 97.164 48.816 ;
     RECT  95.749 48.816 97.116 48.84 ;
     RECT  95.749 48.84 97.164 48.96 ;
     RECT  95.749 48.96 97.116 48.984 ;
     RECT  95.749 48.984 97.164 49.104 ;
     RECT  95.749 49.104 97.116 49.128 ;
     RECT  95.749 49.128 97.164 49.248 ;
     RECT  95.749 49.248 97.116 49.272 ;
     RECT  95.749 49.272 97.164 49.392 ;
     RECT  95.749 49.392 97.116 49.416 ;
     RECT  95.749 49.416 97.164 49.536 ;
     RECT  95.749 49.536 97.116 49.56 ;
     RECT  95.749 49.56 97.164 49.68 ;
     RECT  95.749 49.68 97.116 49.704 ;
     RECT  95.749 49.704 97.164 49.824 ;
     RECT  95.749 49.824 97.116 49.848 ;
     RECT  95.749 49.848 97.164 49.968 ;
     RECT  95.749 49.968 97.116 49.992 ;
     RECT  95.749 49.992 97.164 50.112 ;
     RECT  95.749 50.112 97.116 50.136 ;
     RECT  95.749 50.136 97.164 50.256 ;
     RECT  95.749 50.256 97.116 50.28 ;
     RECT  95.749 50.28 97.164 50.4 ;
     RECT  95.749 50.4 97.116 50.424 ;
     RECT  95.749 50.424 97.164 50.544 ;
     RECT  95.749 50.544 97.116 50.568 ;
     RECT  95.749 50.568 97.164 50.688 ;
     RECT  95.749 50.688 97.116 50.712 ;
     RECT  95.749 50.712 97.164 50.832 ;
     RECT  95.749 50.832 97.116 50.856 ;
     RECT  95.749 50.856 97.164 50.976 ;
     RECT  95.749 50.976 97.116 51 ;
     RECT  95.749 51 97.164 51.12 ;
     RECT  95.749 51.12 97.116 51.144 ;
     RECT  95.749 51.144 97.164 51.264 ;
     RECT  95.749 51.264 97.116 51.288 ;
     RECT  95.749 51.288 97.164 51.408 ;
     RECT  95.749 51.408 97.116 51.432 ;
     RECT  95.749 51.432 97.164 51.552 ;
     RECT  95.749 51.552 97.116 51.576 ;
     RECT  95.749 51.576 97.164 51.696 ;
     RECT  95.749 51.696 97.116 51.72 ;
     RECT  95.749 51.72 97.164 51.84 ;
     RECT  95.749 51.84 97.116 51.864 ;
     RECT  95.749 51.864 97.164 51.984 ;
     RECT  95.749 51.984 97.116 52.008 ;
     RECT  95.749 52.008 97.164 52.128 ;
     RECT  95.749 52.128 97.116 52.152 ;
     RECT  95.749 52.152 97.164 52.272 ;
     RECT  95.749 52.272 97.116 52.296 ;
     RECT  95.749 52.296 97.164 52.416 ;
     RECT  95.749 52.416 97.116 52.44 ;
     RECT  95.749 52.44 97.164 52.56 ;
     RECT  95.749 52.56 97.116 52.584 ;
     RECT  95.749 52.584 97.164 52.704 ;
     RECT  95.749 52.704 97.116 52.728 ;
     RECT  95.749 52.728 97.164 52.848 ;
     RECT  95.749 52.848 97.116 52.872 ;
     RECT  95.749 52.872 97.164 52.992 ;
     RECT  95.749 52.992 97.116 53.016 ;
     RECT  95.749 53.016 97.164 53.136 ;
     RECT  95.749 53.136 97.116 53.16 ;
     RECT  95.749 53.16 97.164 53.28 ;
     RECT  95.749 53.28 97.116 53.304 ;
     RECT  95.749 53.304 97.164 53.424 ;
     RECT  95.749 53.424 97.116 53.448 ;
     RECT  95.749 53.448 97.164 53.568 ;
     RECT  95.749 53.568 97.116 53.592 ;
     RECT  95.749 53.592 97.164 53.712 ;
     RECT  95.749 53.712 97.116 53.736 ;
     RECT  95.749 53.736 97.164 53.856 ;
     RECT  95.749 53.856 97.116 53.88 ;
     RECT  95.749 53.88 97.164 54 ;
     RECT  95.749 54 97.116 54.024 ;
     RECT  95.749 54.024 97.164 54.144 ;
     RECT  95.749 54.144 97.116 54.168 ;
     RECT  95.749 54.168 97.164 54.288 ;
     RECT  95.749 54.288 97.116 54.312 ;
     RECT  95.749 54.312 97.164 54.432 ;
     RECT  95.749 54.432 97.116 54.456 ;
     RECT  95.749 54.456 97.164 54.576 ;
     RECT  95.749 54.576 97.116 54.6 ;
     RECT  95.749 54.6 97.164 54.72 ;
     RECT  95.749 54.72 97.116 54.744 ;
     RECT  95.749 54.744 97.164 54.864 ;
     RECT  95.749 54.864 97.116 54.888 ;
     RECT  95.749 54.888 97.164 55.008 ;
     RECT  95.749 55.008 97.116 55.032 ;
     RECT  95.749 55.032 97.164 55.152 ;
     RECT  95.749 55.152 97.116 55.176 ;
     RECT  95.749 55.176 97.164 55.296 ;
     RECT  95.749 55.296 97.116 55.32 ;
     RECT  95.749 55.32 97.164 55.44 ;
     RECT  95.749 55.44 97.116 55.464 ;
     RECT  95.749 55.464 97.164 55.584 ;
     RECT  95.749 55.584 97.116 55.608 ;
     RECT  95.749 55.608 97.164 55.728 ;
     RECT  95.749 55.728 97.116 55.752 ;
     RECT  95.749 55.752 97.164 55.872 ;
     RECT  95.749 55.872 97.116 55.896 ;
     RECT  95.749 55.896 97.164 56.016 ;
     RECT  95.749 56.016 97.116 56.04 ;
     RECT  95.749 56.04 97.164 56.16 ;
     RECT  95.749 56.16 97.116 56.184 ;
     RECT  95.749 56.184 97.164 56.304 ;
     RECT  95.749 56.304 97.116 56.328 ;
     RECT  95.749 56.328 97.164 56.448 ;
     RECT  95.749 56.448 97.116 56.472 ;
     RECT  95.749 56.472 97.164 56.592 ;
     RECT  95.749 56.592 97.116 56.616 ;
     RECT  95.749 56.616 97.164 56.736 ;
     RECT  95.749 56.736 97.116 56.76 ;
     RECT  95.749 56.76 97.164 56.88 ;
     RECT  95.749 56.88 97.116 56.904 ;
     RECT  95.749 56.904 97.164 57.024 ;
     RECT  95.749 57.024 97.116 57.048 ;
    LAYER M5 ;
     RECT  58.344 0.016 58.464 0.084 ;
     RECT  58.488 0.016 58.608 0.084 ;
     RECT  58.632 0.016 58.752 0.084 ;
     RECT  58.776 0.016 58.896 0.084 ;
     RECT  58.92 0.016 59.04 0.084 ;
     RECT  59.064 0.016 59.184 0.084 ;
     RECT  59.208 0.016 59.328 0.084 ;
     RECT  59.352 0.016 59.472 0.084 ;
     RECT  59.496 0.016 59.616 0.084 ;
     RECT  59.64 0.016 59.76 0.084 ;
     RECT  59.784 0.016 59.904 0.084 ;
     RECT  59.928 0.016 60.048 0.084 ;
     RECT  60.072 0.016 60.192 0.084 ;
     RECT  60.216 0.016 60.336 0.084 ;
     RECT  60.36 0.016 60.48 0.084 ;
     RECT  60.504 0.016 60.624 0.084 ;
     RECT  60.648 0.016 60.768 0.084 ;
     RECT  60.792 0.016 60.912 0.084 ;
     RECT  60.936 0.016 61.056 0.084 ;
     RECT  61.08 0.016 61.2 0.084 ;
     RECT  61.224 0.016 61.344 0.084 ;
     RECT  61.368 0.016 61.488 0.084 ;
     RECT  61.512 0.016 61.632 0.084 ;
     RECT  61.656 0.016 61.776 0.084 ;
     RECT  61.8 0.016 61.92 0.084 ;
     RECT  61.944 0.016 62.064 0.084 ;
     RECT  62.088 0.016 62.208 0.084 ;
     RECT  62.232 0.016 62.352 0.084 ;
     RECT  62.376 0.016 62.496 0.084 ;
     RECT  62.52 0.016 62.64 0.084 ;
     RECT  62.664 0.016 62.784 0.084 ;
     RECT  62.808 0.016 62.928 0.084 ;
     RECT  62.952 0.016 63.072 0.084 ;
     RECT  63.096 0.016 63.216 0.084 ;
     RECT  63.24 0.016 63.36 0.084 ;
     RECT  63.384 0.016 63.504 0.084 ;
     RECT  63.528 0.016 63.648 0.084 ;
     RECT  63.672 0.016 63.792 0.084 ;
     RECT  63.816 0.016 63.936 0.084 ;
     RECT  63.96 0.016 64.08 0.084 ;
     RECT  64.104 0.016 64.224 0.084 ;
     RECT  64.248 0.016 64.368 0.084 ;
     RECT  64.392 0.016 64.512 0.084 ;
     RECT  64.536 0.016 64.656 0.084 ;
     RECT  64.68 0.016 64.8 0.084 ;
     RECT  64.824 0.016 64.944 0.084 ;
     RECT  64.968 0.016 65.088 0.084 ;
     RECT  65.112 0.016 65.232 0.084 ;
     RECT  65.256 0.016 65.376 0.084 ;
     RECT  65.4 0.016 65.52 0.084 ;
     RECT  65.544 0.016 65.664 0.084 ;
     RECT  65.688 0.016 65.808 0.084 ;
     RECT  65.832 0.016 65.952 0.084 ;
     RECT  65.976 0.016 66.096 0.084 ;
     RECT  66.12 0.016 66.24 0.084 ;
     RECT  66.264 0.016 66.384 0.084 ;
     RECT  66.408 0.016 66.528 0.084 ;
     RECT  66.552 0.016 66.672 0.084 ;
     RECT  66.696 0.016 66.816 0.084 ;
     RECT  66.84 0.016 66.96 0.084 ;
     RECT  66.984 0.016 67.104 0.084 ;
     RECT  67.128 0.016 67.248 0.084 ;
     RECT  67.272 0.016 67.392 0.084 ;
     RECT  67.416 0.016 67.536 0.084 ;
     RECT  67.56 0.016 67.68 0.084 ;
     RECT  67.704 0.016 67.824 0.084 ;
     RECT  67.848 0.016 67.968 0.084 ;
     RECT  67.992 0.016 68.112 0.084 ;
     RECT  68.136 0.016 68.256 0.084 ;
     RECT  68.28 0.016 68.4 0.084 ;
     RECT  68.424 0.016 68.544 0.084 ;
     RECT  68.568 0.016 68.688 0.084 ;
     RECT  68.712 0.016 68.832 0.084 ;
     RECT  68.856 0.016 68.976 0.084 ;
     RECT  69 0.016 69.12 0.084 ;
     RECT  69.144 0.016 69.264 0.084 ;
     RECT  69.288 0.016 69.408 0.084 ;
     RECT  69.432 0.016 69.552 0.084 ;
     RECT  69.576 0.016 69.696 0.084 ;
     RECT  69.72 0.016 69.84 0.084 ;
     RECT  69.864 0.016 69.984 0.084 ;
     RECT  70.008 0.016 70.128 0.084 ;
     RECT  70.152 0.016 70.272 0.084 ;
     RECT  70.296 0.016 70.416 0.084 ;
     RECT  70.44 0.016 70.56 0.084 ;
     RECT  70.584 0.016 70.704 0.084 ;
     RECT  70.728 0.016 70.848 0.084 ;
     RECT  70.872 0.016 70.992 0.084 ;
     RECT  71.016 0.016 71.136 0.084 ;
     RECT  71.16 0.016 71.28 0.084 ;
     RECT  71.304 0.016 71.424 0.084 ;
     RECT  71.448 0.016 71.568 0.084 ;
     RECT  71.592 0.016 71.712 0.084 ;
     RECT  71.736 0.016 71.856 0.084 ;
     RECT  71.88 0.016 72 0.084 ;
     RECT  72.024 0.016 72.144 0.084 ;
     RECT  72.168 0.016 72.288 0.084 ;
     RECT  72.312 0.016 72.432 0.084 ;
     RECT  72.456 0.016 72.576 0.084 ;
     RECT  72.6 0.016 72.72 0.084 ;
     RECT  72.744 0.016 72.864 0.084 ;
     RECT  72.888 0.016 73.008 0.084 ;
     RECT  73.032 0.016 73.152 0.084 ;
     RECT  73.176 0.016 73.296 0.084 ;
     RECT  73.32 0.016 73.44 0.084 ;
     RECT  73.464 0.016 73.584 0.084 ;
     RECT  73.608 0.016 73.728 0.084 ;
     RECT  73.752 0.016 73.872 0.084 ;
     RECT  73.896 0.016 74.016 0.084 ;
     RECT  74.04 0.016 74.16 0.084 ;
     RECT  74.184 0.016 74.304 0.084 ;
     RECT  74.328 0.016 74.448 0.084 ;
     RECT  74.472 0.016 74.592 0.084 ;
     RECT  74.616 0.016 74.736 0.084 ;
     RECT  74.76 0.016 74.88 0.084 ;
     RECT  74.904 0.016 75.024 0.084 ;
     RECT  75.048 0.016 75.168 0.084 ;
     RECT  75.192 0.016 75.312 0.084 ;
     RECT  75.336 0.016 75.456 0.084 ;
     RECT  75.48 0.016 75.6 0.084 ;
     RECT  75.624 0.016 75.744 0.084 ;
     RECT  75.768 0.016 75.888 0.084 ;
     RECT  75.912 0.016 76.032 0.084 ;
     RECT  76.056 0.016 76.176 0.084 ;
     RECT  76.2 0.016 76.32 0.084 ;
     RECT  76.344 0.016 76.464 0.084 ;
     RECT  76.488 0.016 76.608 0.084 ;
     RECT  76.632 0.016 76.752 0.084 ;
     RECT  76.776 0.016 76.896 0.084 ;
     RECT  76.92 0.016 77.04 0.084 ;
     RECT  77.064 0.016 77.184 0.084 ;
     RECT  77.208 0.016 77.328 0.084 ;
     RECT  77.352 0.016 77.472 0.084 ;
     RECT  77.496 0.016 77.616 0.084 ;
     RECT  77.64 0.016 77.76 0.084 ;
     RECT  77.784 0.016 77.904 0.084 ;
     RECT  77.928 0.016 78.048 0.084 ;
     RECT  78.072 0.016 78.192 0.084 ;
     RECT  78.216 0.016 78.336 0.084 ;
     RECT  78.36 0.016 78.48 0.084 ;
     RECT  78.504 0.016 78.624 0.084 ;
     RECT  78.648 0.016 78.768 0.084 ;
     RECT  78.792 0.016 78.912 0.084 ;
     RECT  78.936 0.016 79.056 0.084 ;
     RECT  79.08 0.016 79.2 0.084 ;
     RECT  79.224 0.016 79.344 0.084 ;
     RECT  79.368 0.016 79.488 0.084 ;
     RECT  79.512 0.016 79.632 0.084 ;
     RECT  79.656 0.016 79.776 0.084 ;
     RECT  79.8 0.016 79.92 0.084 ;
     RECT  79.944 0.016 80.064 0.084 ;
     RECT  80.088 0.016 80.208 0.084 ;
     RECT  80.232 0.016 80.352 0.084 ;
     RECT  80.376 0.016 80.496 0.084 ;
     RECT  80.52 0.016 80.64 0.084 ;
     RECT  80.664 0.016 80.784 0.084 ;
     RECT  80.808 0.016 80.928 0.084 ;
     RECT  80.952 0.016 81.072 0.084 ;
     RECT  81.096 0.016 81.216 0.084 ;
     RECT  81.24 0.016 81.36 0.084 ;
     RECT  81.384 0.016 81.504 0.084 ;
     RECT  81.528 0.016 81.648 0.084 ;
     RECT  81.672 0.016 81.792 0.084 ;
     RECT  81.816 0.016 81.936 0.084 ;
     RECT  81.96 0.016 82.08 0.084 ;
     RECT  82.104 0.016 82.224 0.084 ;
     RECT  82.248 0.016 82.368 0.084 ;
     RECT  82.392 0.016 82.512 0.084 ;
     RECT  82.536 0.016 82.656 0.084 ;
     RECT  82.68 0.016 82.8 0.084 ;
     RECT  82.824 0.016 82.944 0.084 ;
     RECT  82.968 0.016 83.088 0.084 ;
     RECT  83.112 0.016 83.232 0.084 ;
     RECT  83.256 0.016 83.376 0.084 ;
     RECT  83.4 0.016 83.52 0.084 ;
     RECT  83.544 0.016 83.664 0.084 ;
     RECT  83.688 0.016 83.808 0.084 ;
     RECT  83.832 0.016 83.952 0.084 ;
     RECT  83.976 0.016 84.096 0.084 ;
     RECT  84.12 0.016 84.24 0.084 ;
     RECT  84.264 0.016 84.384 0.084 ;
     RECT  84.408 0.016 84.528 0.084 ;
     RECT  84.552 0.016 84.672 0.084 ;
     RECT  84.696 0.016 84.816 0.084 ;
     RECT  84.84 0.016 84.96 0.084 ;
     RECT  84.984 0.016 85.104 0.084 ;
     RECT  85.128 0.016 85.248 0.084 ;
     RECT  85.272 0.016 85.392 0.084 ;
     RECT  85.416 0.016 85.536 0.084 ;
     RECT  85.56 0.016 85.68 0.084 ;
     RECT  85.704 0.016 85.824 0.084 ;
     RECT  85.848 0.016 85.968 0.084 ;
     RECT  85.992 0.016 86.112 0.084 ;
     RECT  86.136 0.016 86.256 0.084 ;
     RECT  86.28 0.016 87.12 0.084 ;
     RECT  87.144 0.016 87.264 0.084 ;
     RECT  87.288 0.016 87.408 0.084 ;
     RECT  87.432 0.016 87.552 0.084 ;
     RECT  87.576 0.016 87.696 0.084 ;
     RECT  87.72 0.016 87.84 0.084 ;
     RECT  87.864 0.016 87.984 0.084 ;
     RECT  88.008 0.016 88.128 0.084 ;
     RECT  88.152 0.016 88.272 0.084 ;
     RECT  88.296 0.016 88.416 0.084 ;
     RECT  88.44 0.016 88.56 0.084 ;
     RECT  88.584 0.016 88.704 0.084 ;
     RECT  88.728 0.016 88.848 0.084 ;
     RECT  88.872 0.016 88.992 0.084 ;
     RECT  89.016 0.016 89.136 0.084 ;
     RECT  89.16 0.016 89.28 0.084 ;
     RECT  89.304 0.016 89.424 0.084 ;
     RECT  89.448 0.016 89.568 0.084 ;
     RECT  89.592 0.016 89.712 0.084 ;
     RECT  89.736 0.016 89.856 0.084 ;
     RECT  89.88 0.016 90 0.084 ;
     RECT  90.024 0.016 90.144 0.084 ;
     RECT  90.168 0.016 90.288 0.084 ;
     RECT  90.312 0.016 90.432 0.084 ;
     RECT  90.456 0.016 90.576 0.084 ;
     RECT  90.6 0.016 90.72 0.084 ;
     RECT  90.744 0.016 90.864 0.084 ;
     RECT  90.888 0.016 91.008 0.084 ;
     RECT  91.032 0.016 91.152 0.084 ;
     RECT  91.176 0.016 91.296 0.084 ;
     RECT  91.32 0.016 91.44 0.084 ;
     RECT  91.464 0.016 91.584 0.084 ;
     RECT  91.608 0.016 91.728 0.084 ;
     RECT  91.752 0.016 91.872 0.084 ;
     RECT  91.896 0.016 92.016 0.084 ;
     RECT  92.04 0.016 92.16 0.084 ;
     RECT  92.184 0.016 92.304 0.084 ;
     RECT  92.328 0.016 92.448 0.084 ;
     RECT  92.472 0.016 92.592 0.084 ;
     RECT  92.616 0.016 92.736 0.084 ;
     RECT  92.76 0.016 92.88 0.084 ;
     RECT  92.904 0.016 93.024 0.084 ;
     RECT  93.048 0.016 93.168 0.084 ;
     RECT  93.192 0.016 93.312 0.084 ;
     RECT  93.336 0.016 93.456 0.084 ;
     RECT  93.48 0.016 93.6 0.084 ;
     RECT  93.624 0.016 93.744 0.084 ;
     RECT  93.768 0.016 93.888 0.084 ;
     RECT  93.912 0.016 94.032 0.084 ;
     RECT  94.056 0.016 94.176 0.084 ;
     RECT  94.2 0.016 94.32 0.084 ;
     RECT  94.344 0.016 94.464 0.084 ;
     RECT  94.488 0.016 94.608 0.084 ;
     RECT  94.632 0.016 94.752 0.084 ;
     RECT  94.776 0.016 94.896 0.084 ;
     RECT  94.92 0.016 95.04 0.084 ;
     RECT  95.064 0.016 95.184 0.084 ;
     RECT  95.208 0.016 95.328 0.084 ;
     RECT  95.352 0.016 95.472 0.084 ;
     RECT  95.496 0.016 95.616 0.084 ;
     RECT  95.64 0.016 95.76 0.084 ;
     RECT  95.784 0.016 95.904 0.084 ;
     RECT  95.928 0.016 96.048 0.084 ;
     RECT  96.072 0.016 96.192 0.084 ;
     RECT  58.32 0.084 96.216 0.179 ;
     RECT  71.136 0.179 96.216 0.323 ;
     RECT  80.496 0.323 96.216 0.371 ;
     RECT  80.496 0.371 81.24 0.419 ;
     RECT  71.136 0.323 79.512 0.563 ;
     RECT  80.784 0.419 81.24 0.563 ;
     RECT  69.408 0.179 70.152 0.611 ;
     RECT  82.224 0.371 96.216 0.611 ;
     RECT  14.568 0.016 14.688 0.084 ;
     RECT  14.712 0.016 14.832 0.084 ;
     RECT  14.856 0.016 14.976 0.084 ;
     RECT  15 0.016 15.12 0.084 ;
     RECT  15.144 0.016 15.264 0.084 ;
     RECT  15.288 0.016 15.408 0.084 ;
     RECT  15.432 0.016 15.552 0.084 ;
     RECT  15.576 0.016 15.696 0.084 ;
     RECT  15.72 0.016 15.84 0.084 ;
     RECT  15.864 0.016 15.984 0.084 ;
     RECT  16.008 0.016 16.128 0.084 ;
     RECT  16.152 0.016 16.272 0.084 ;
     RECT  16.296 0.016 16.416 0.084 ;
     RECT  16.44 0.016 16.56 0.084 ;
     RECT  16.584 0.016 16.704 0.084 ;
     RECT  16.728 0.016 16.848 0.084 ;
     RECT  16.872 0.016 16.992 0.084 ;
     RECT  17.016 0.016 17.136 0.084 ;
     RECT  17.16 0.016 17.28 0.084 ;
     RECT  17.304 0.016 17.424 0.084 ;
     RECT  17.448 0.016 17.568 0.084 ;
     RECT  17.592 0.016 17.712 0.084 ;
     RECT  17.736 0.016 17.856 0.084 ;
     RECT  17.88 0.016 18 0.084 ;
     RECT  18.024 0.016 18.144 0.084 ;
     RECT  18.168 0.016 18.288 0.084 ;
     RECT  18.312 0.016 18.432 0.084 ;
     RECT  18.456 0.016 18.576 0.084 ;
     RECT  18.6 0.016 18.72 0.084 ;
     RECT  18.744 0.016 18.864 0.084 ;
     RECT  18.888 0.016 19.008 0.084 ;
     RECT  19.032 0.016 19.152 0.084 ;
     RECT  19.176 0.016 19.296 0.084 ;
     RECT  19.32 0.016 19.44 0.084 ;
     RECT  19.464 0.016 19.584 0.084 ;
     RECT  19.608 0.016 19.728 0.084 ;
     RECT  19.752 0.016 19.872 0.084 ;
     RECT  19.896 0.016 20.016 0.084 ;
     RECT  20.04 0.016 20.16 0.084 ;
     RECT  20.184 0.016 20.304 0.084 ;
     RECT  20.328 0.016 20.448 0.084 ;
     RECT  20.472 0.016 20.592 0.084 ;
     RECT  20.616 0.016 20.736 0.084 ;
     RECT  20.76 0.016 20.88 0.084 ;
     RECT  20.904 0.016 21.024 0.084 ;
     RECT  21.048 0.016 21.168 0.084 ;
     RECT  21.192 0.016 21.312 0.084 ;
     RECT  21.336 0.016 21.456 0.084 ;
     RECT  21.48 0.016 21.6 0.084 ;
     RECT  21.624 0.016 21.744 0.084 ;
     RECT  21.768 0.016 21.888 0.084 ;
     RECT  21.912 0.016 22.032 0.084 ;
     RECT  22.056 0.016 22.176 0.084 ;
     RECT  22.2 0.016 22.32 0.084 ;
     RECT  22.344 0.016 22.464 0.084 ;
     RECT  22.488 0.016 22.608 0.084 ;
     RECT  22.632 0.016 22.752 0.084 ;
     RECT  22.776 0.016 22.896 0.084 ;
     RECT  22.92 0.016 23.04 0.084 ;
     RECT  23.064 0.016 23.184 0.084 ;
     RECT  23.208 0.016 23.328 0.084 ;
     RECT  23.352 0.016 23.472 0.084 ;
     RECT  23.496 0.016 23.616 0.084 ;
     RECT  23.64 0.016 23.76 0.084 ;
     RECT  23.784 0.016 23.904 0.084 ;
     RECT  23.928 0.016 24.048 0.084 ;
     RECT  24.072 0.016 24.192 0.084 ;
     RECT  24.216 0.016 24.336 0.084 ;
     RECT  24.36 0.016 24.48 0.084 ;
     RECT  24.504 0.016 24.624 0.084 ;
     RECT  24.648 0.016 24.768 0.084 ;
     RECT  24.792 0.016 24.912 0.084 ;
     RECT  24.936 0.016 25.056 0.084 ;
     RECT  25.08 0.016 25.2 0.084 ;
     RECT  25.224 0.016 25.344 0.084 ;
     RECT  25.368 0.016 25.488 0.084 ;
     RECT  25.512 0.016 25.632 0.084 ;
     RECT  25.656 0.016 25.776 0.084 ;
     RECT  25.8 0.016 25.92 0.084 ;
     RECT  25.944 0.016 26.064 0.084 ;
     RECT  26.088 0.016 26.208 0.084 ;
     RECT  26.232 0.016 26.352 0.084 ;
     RECT  26.376 0.016 26.496 0.084 ;
     RECT  26.52 0.016 26.64 0.084 ;
     RECT  26.664 0.016 26.784 0.084 ;
     RECT  26.808 0.016 26.928 0.084 ;
     RECT  26.952 0.016 27.072 0.084 ;
     RECT  27.096 0.016 27.216 0.084 ;
     RECT  27.24 0.016 27.36 0.084 ;
     RECT  27.384 0.016 27.504 0.084 ;
     RECT  27.528 0.016 27.648 0.084 ;
     RECT  27.672 0.016 27.792 0.084 ;
     RECT  27.816 0.016 27.936 0.084 ;
     RECT  27.96 0.016 28.08 0.084 ;
     RECT  28.104 0.016 28.224 0.084 ;
     RECT  14.544 0.084 28.248 1.763 ;
     RECT  29.544 0.016 29.664 0.084 ;
     RECT  29.688 0.016 29.808 0.084 ;
     RECT  29.832 0.016 29.952 0.084 ;
     RECT  29.976 0.016 30.096 0.084 ;
     RECT  30.12 0.016 30.24 0.084 ;
     RECT  30.264 0.016 30.384 0.084 ;
     RECT  30.408 0.016 30.528 0.084 ;
     RECT  30.552 0.016 30.672 0.084 ;
     RECT  30.696 0.016 30.816 0.084 ;
     RECT  30.84 0.016 30.96 0.084 ;
     RECT  30.984 0.016 31.104 0.084 ;
     RECT  31.128 0.016 31.248 0.084 ;
     RECT  31.272 0.016 31.392 0.084 ;
     RECT  31.416 0.016 31.536 0.084 ;
     RECT  31.56 0.016 31.68 0.084 ;
     RECT  31.704 0.016 31.824 0.084 ;
     RECT  31.848 0.016 31.968 0.084 ;
     RECT  31.992 0.016 32.112 0.084 ;
     RECT  32.136 0.016 32.256 0.084 ;
     RECT  32.28 0.016 32.4 0.084 ;
     RECT  32.424 0.016 32.544 0.084 ;
     RECT  32.568 0.016 32.688 0.084 ;
     RECT  32.712 0.016 32.832 0.084 ;
     RECT  32.856 0.016 32.976 0.084 ;
     RECT  33 0.016 33.12 0.084 ;
     RECT  33.144 0.016 33.264 0.084 ;
     RECT  33.288 0.016 33.408 0.084 ;
     RECT  33.432 0.016 33.552 0.084 ;
     RECT  33.576 0.016 33.696 0.084 ;
     RECT  33.72 0.016 33.84 0.084 ;
     RECT  33.864 0.016 33.984 0.084 ;
     RECT  34.008 0.016 34.128 0.084 ;
     RECT  34.152 0.016 34.272 0.084 ;
     RECT  34.296 0.016 34.416 0.084 ;
     RECT  34.44 0.016 34.56 0.084 ;
     RECT  34.584 0.016 34.704 0.084 ;
     RECT  34.728 0.016 34.848 0.084 ;
     RECT  34.872 0.016 34.992 0.084 ;
     RECT  35.016 0.016 35.136 0.084 ;
     RECT  35.16 0.016 35.28 0.084 ;
     RECT  35.304 0.016 35.424 0.084 ;
     RECT  35.448 0.016 35.568 0.084 ;
     RECT  35.592 0.016 35.712 0.084 ;
     RECT  35.736 0.016 35.856 0.084 ;
     RECT  35.88 0.016 36 0.084 ;
     RECT  36.024 0.016 36.144 0.084 ;
     RECT  36.168 0.016 36.288 0.084 ;
     RECT  36.312 0.016 36.432 0.084 ;
     RECT  36.456 0.016 36.576 0.084 ;
     RECT  36.6 0.016 36.72 0.084 ;
     RECT  36.744 0.016 36.864 0.084 ;
     RECT  36.888 0.016 37.008 0.084 ;
     RECT  37.032 0.016 37.152 0.084 ;
     RECT  37.176 0.016 37.296 0.084 ;
     RECT  37.32 0.016 37.44 0.084 ;
     RECT  37.464 0.016 37.584 0.084 ;
     RECT  37.608 0.016 37.728 0.084 ;
     RECT  37.752 0.016 37.872 0.084 ;
     RECT  37.896 0.016 38.016 0.084 ;
     RECT  38.04 0.016 38.16 0.084 ;
     RECT  38.184 0.016 38.304 0.084 ;
     RECT  38.328 0.016 38.448 0.084 ;
     RECT  38.472 0.016 38.592 0.084 ;
     RECT  38.616 0.016 38.736 0.084 ;
     RECT  38.76 0.016 38.88 0.084 ;
     RECT  38.904 0.016 39.024 0.084 ;
     RECT  39.048 0.016 39.168 0.084 ;
     RECT  39.192 0.016 39.312 0.084 ;
     RECT  39.336 0.016 39.456 0.084 ;
     RECT  39.48 0.016 39.6 0.084 ;
     RECT  39.624 0.016 39.744 0.084 ;
     RECT  39.768 0.016 39.888 0.084 ;
     RECT  39.912 0.016 40.032 0.084 ;
     RECT  40.056 0.016 40.176 0.084 ;
     RECT  40.2 0.016 40.32 0.084 ;
     RECT  40.344 0.016 40.464 0.084 ;
     RECT  40.488 0.016 40.608 0.084 ;
     RECT  40.632 0.016 40.752 0.084 ;
     RECT  40.776 0.016 40.896 0.084 ;
     RECT  40.92 0.016 41.04 0.084 ;
     RECT  41.064 0.016 41.184 0.084 ;
     RECT  41.208 0.016 41.328 0.084 ;
     RECT  41.352 0.016 41.472 0.084 ;
     RECT  41.496 0.016 41.616 0.084 ;
     RECT  41.64 0.016 41.76 0.084 ;
     RECT  41.784 0.016 41.904 0.084 ;
     RECT  41.928 0.016 42.048 0.084 ;
     RECT  42.072 0.016 42.192 0.084 ;
     RECT  42.216 0.016 42.336 0.084 ;
     RECT  42.36 0.016 42.48 0.084 ;
     RECT  42.504 0.016 42.624 0.084 ;
     RECT  42.648 0.016 42.768 0.084 ;
     RECT  42.792 0.016 42.912 0.084 ;
     RECT  42.936 0.016 43.056 0.084 ;
     RECT  43.08 0.016 43.2 0.084 ;
     RECT  43.224 0.016 43.344 0.084 ;
     RECT  43.368 0.016 43.488 0.084 ;
     RECT  43.512 0.016 43.632 0.084 ;
     RECT  43.656 0.016 43.776 0.084 ;
     RECT  43.8 0.016 43.92 0.084 ;
     RECT  43.944 0.016 44.064 0.084 ;
     RECT  44.088 0.016 44.208 0.084 ;
     RECT  44.232 0.016 44.352 0.084 ;
     RECT  44.376 0.016 44.496 0.084 ;
     RECT  44.52 0.016 44.64 0.084 ;
     RECT  44.664 0.016 44.784 0.084 ;
     RECT  44.808 0.016 44.928 0.084 ;
     RECT  44.952 0.016 45.072 0.084 ;
     RECT  45.096 0.016 45.216 0.084 ;
     RECT  45.24 0.016 45.36 0.084 ;
     RECT  45.384 0.016 45.504 0.084 ;
     RECT  45.528 0.016 45.648 0.084 ;
     RECT  45.672 0.016 45.792 0.084 ;
     RECT  45.816 0.016 45.936 0.084 ;
     RECT  45.96 0.016 46.08 0.084 ;
     RECT  46.104 0.016 46.224 0.084 ;
     RECT  46.248 0.016 46.368 0.084 ;
     RECT  46.392 0.016 46.512 0.084 ;
     RECT  46.536 0.016 46.656 0.084 ;
     RECT  46.68 0.016 46.8 0.084 ;
     RECT  46.824 0.016 46.944 0.084 ;
     RECT  46.968 0.016 47.088 0.084 ;
     RECT  47.112 0.016 47.232 0.084 ;
     RECT  47.256 0.016 47.376 0.084 ;
     RECT  47.4 0.016 47.52 0.084 ;
     RECT  47.544 0.016 47.664 0.084 ;
     RECT  47.688 0.016 47.808 0.084 ;
     RECT  47.832 0.016 47.952 0.084 ;
     RECT  47.976 0.016 48.096 0.084 ;
     RECT  48.12 0.016 48.24 0.084 ;
     RECT  48.264 0.016 48.384 0.084 ;
     RECT  48.408 0.016 48.528 0.084 ;
     RECT  48.552 0.016 48.672 0.084 ;
     RECT  48.696 0.016 48.816 0.084 ;
     RECT  48.84 0.016 48.96 0.084 ;
     RECT  48.984 0.016 49.104 0.084 ;
     RECT  49.128 0.016 49.248 0.084 ;
     RECT  49.272 0.016 49.392 0.084 ;
     RECT  49.416 0.016 49.536 0.084 ;
     RECT  49.56 0.016 49.68 0.084 ;
     RECT  49.704 0.016 49.824 0.084 ;
     RECT  49.848 0.016 49.968 0.084 ;
     RECT  49.992 0.016 50.112 0.084 ;
     RECT  50.136 0.016 50.256 0.084 ;
     RECT  50.28 0.016 50.4 0.084 ;
     RECT  50.424 0.016 50.544 0.084 ;
     RECT  50.568 0.016 50.688 0.084 ;
     RECT  50.712 0.016 50.832 0.084 ;
     RECT  50.856 0.016 50.976 0.084 ;
     RECT  51 0.016 51.12 0.084 ;
     RECT  51.144 0.016 51.264 0.084 ;
     RECT  51.288 0.016 51.408 0.084 ;
     RECT  51.432 0.016 51.552 0.084 ;
     RECT  51.576 0.016 51.696 0.084 ;
     RECT  51.72 0.016 51.84 0.084 ;
     RECT  51.864 0.016 51.984 0.084 ;
     RECT  52.008 0.016 52.128 0.084 ;
     RECT  52.152 0.016 52.272 0.084 ;
     RECT  52.296 0.016 52.416 0.084 ;
     RECT  52.44 0.016 52.56 0.084 ;
     RECT  52.584 0.016 52.704 0.084 ;
     RECT  52.728 0.016 52.848 0.084 ;
     RECT  52.872 0.016 52.992 0.084 ;
     RECT  53.016 0.016 53.136 0.084 ;
     RECT  53.16 0.016 53.28 0.084 ;
     RECT  53.304 0.016 53.424 0.084 ;
     RECT  53.448 0.016 53.568 0.084 ;
     RECT  53.592 0.016 53.712 0.084 ;
     RECT  53.736 0.016 53.856 0.084 ;
     RECT  53.88 0.016 54 0.084 ;
     RECT  54.024 0.016 54.144 0.084 ;
     RECT  54.168 0.016 54.288 0.084 ;
     RECT  54.312 0.016 54.432 0.084 ;
     RECT  54.456 0.016 54.576 0.084 ;
     RECT  54.6 0.016 54.72 0.084 ;
     RECT  54.744 0.016 54.864 0.084 ;
     RECT  54.888 0.016 55.008 0.084 ;
     RECT  55.032 0.016 55.152 0.084 ;
     RECT  55.176 0.016 55.296 0.084 ;
     RECT  55.32 0.016 55.44 0.084 ;
     RECT  55.464 0.016 55.584 0.084 ;
     RECT  55.608 0.016 55.728 0.084 ;
     RECT  55.752 0.016 55.872 0.084 ;
     RECT  55.896 0.016 56.016 0.084 ;
     RECT  56.04 0.016 56.16 0.084 ;
     RECT  56.184 0.016 56.304 0.084 ;
     RECT  56.328 0.016 56.448 0.084 ;
     RECT  56.472 0.016 56.592 0.084 ;
     RECT  56.616 0.016 56.736 0.084 ;
     RECT  56.76 0.016 56.88 0.084 ;
     RECT  56.904 0.016 57.024 0.084 ;
     RECT  29.52 0.084 57.048 1.763 ;
     RECT  58.32 0.179 67.992 1.763 ;
     RECT  69.408 0.611 69.432 1.763 ;
     RECT  71.136 0.563 77.496 1.763 ;
     RECT  82.224 0.611 96.072 1.763 ;
     RECT  34.272 1.763 35.112 1.811 ;
     RECT  45.504 1.763 45.96 1.811 ;
     RECT  49.68 1.763 49.704 1.811 ;
     RECT  66.672 1.763 67.992 1.811 ;
     RECT  76.608 1.763 77.496 1.811 ;
     RECT  61.8 1.763 62.664 1.859 ;
     RECT  77.184 1.811 77.496 1.859 ;
     RECT  71.856 1.763 74.04 1.907 ;
     RECT  29.52 1.763 29.712 2.137 ;
     RECT  77.472 1.859 77.496 2.137 ;
     RECT  78.624 0.563 79.224 2.137 ;
     RECT  2.4 2.137 2.52 2.151 ;
     RECT  7.8 2.137 7.92 2.151 ;
     RECT  13.2 2.137 13.32 2.151 ;
     RECT  77.472 2.137 79.224 2.243 ;
     RECT  67.2 1.811 67.992 2.291 ;
     RECT  94.2 1.763 96.072 2.291 ;
     RECT  94.2 2.291 95.064 2.387 ;
     RECT  13.2 2.151 13.512 2.821 ;
     RECT  67.2 2.291 67.848 2.915 ;
     RECT  71.856 1.907 73.32 2.915 ;
     RECT  12.144 2.821 12.168 3.107 ;
     RECT  7.8 2.151 8.112 3.301 ;
     RECT  77.472 2.243 78.936 3.397 ;
     RECT  74.448 3.397 74.472 3.829 ;
     RECT  74.352 3.829 74.472 3.875 ;
     RECT  7.8 3.301 8.76 4.355 ;
     RECT  4.224 3.397 4.248 4.357 ;
     RECT  74.352 3.875 74.376 4.357 ;
     RECT  74.112 4.357 74.376 4.403 ;
     RECT  67.2 2.915 67.512 4.501 ;
     RECT  72.6 2.915 72.912 4.501 ;
     RECT  76.944 3.397 78.936 4.501 ;
     RECT  83.4 1.763 83.712 4.501 ;
     RECT  76.464 4.501 78.936 4.547 ;
     RECT  81.216 0.563 81.24 4.595 ;
     RECT  68.976 4.501 69 4.741 ;
     RECT  68.976 4.741 69.432 4.787 ;
     RECT  4.224 4.357 4.296 5.171 ;
     RECT  67.2 4.501 67.848 5.219 ;
     RECT  7.8 4.355 8.112 5.653 ;
     RECT  72.192 4.501 72.912 5.747 ;
     RECT  76.464 4.547 76.488 5.747 ;
     RECT  7.8 5.653 8.232 6.229 ;
     RECT  69.408 4.787 69.432 6.275 ;
     RECT  13.2 2.821 13.992 6.323 ;
     RECT  74.112 4.403 74.136 6.419 ;
     RECT  78 4.547 78.936 6.515 ;
     RECT  13.2 6.323 13.512 6.901 ;
     RECT  7.8 6.229 8.28 7.619 ;
     RECT  12.432 6.901 13.512 7.859 ;
     RECT  2.4 2.151 2.712 9.349 ;
     RECT  4.272 5.171 4.296 9.349 ;
     RECT  10.032 8.437 10.68 9.779 ;
     RECT  7.8 7.619 8.232 10.453 ;
     RECT  2.4 9.349 4.296 10.883 ;
     RECT  12 9.925 12.024 10.883 ;
     RECT  7.536 10.453 8.232 11.267 ;
     RECT  10.656 9.779 10.68 11.317 ;
     RECT  2.4 10.883 3.432 11.939 ;
     RECT  10.656 11.317 11.256 12.179 ;
     RECT  13.2 7.859 13.512 15.829 ;
     RECT  12.912 15.829 13.512 17.123 ;
     RECT  7.8 11.267 8.232 17.363 ;
     RECT  11.76 16.501 11.784 17.699 ;
     RECT  9.504 18.565 9.528 19.381 ;
     RECT  10.656 12.179 10.68 19.381 ;
     RECT  9.504 19.381 10.68 19.427 ;
     RECT  13.2 17.123 13.512 19.765 ;
     RECT  7.8 17.363 8.112 19.861 ;
     RECT  9.504 19.427 10.296 19.861 ;
     RECT  7.8 19.861 10.296 20.003 ;
     RECT  9.936 20.003 10.296 20.051 ;
     RECT  7.8 20.003 8.568 20.579 ;
     RECT  12.96 19.765 13.512 21.155 ;
     RECT  10.272 20.051 10.296 22.981 ;
     RECT  9.312 22.981 10.296 23.027 ;
     RECT  13.2 21.155 13.512 23.701 ;
     RECT  11.856 22.597 11.88 23.747 ;
     RECT  9.312 23.027 9.336 24.131 ;
     RECT  11.472 24.133 11.496 25.139 ;
     RECT  5.136 17.317 5.16 26.243 ;
     RECT  13.2 23.701 13.944 27.349 ;
     RECT  7.8 20.579 8.112 28.213 ;
     RECT  6.96 28.213 8.112 28.787 ;
     RECT  9.744 27.877 9.768 29.507 ;
     RECT  5.184 26.725 5.208 29.891 ;
     RECT  12.672 27.349 13.944 30.275 ;
     RECT  10.464 29.941 10.488 30.467 ;
     RECT  82.8 4.501 83.712 31.861 ;
     RECT  10.8 31.285 10.824 31.955 ;
     RECT  82.512 31.861 83.712 32.053 ;
     RECT  7.8 28.787 8.112 32.197 ;
     RECT  4.032 29.845 4.056 33.107 ;
     RECT  7.248 32.197 8.112 33.155 ;
     RECT  9.456 30.469 9.48 33.541 ;
     RECT  2.4 11.939 2.712 33.973 ;
     RECT  11.328 33.013 11.352 34.067 ;
     RECT  0.144 34.453 0.168 34.739 ;
     RECT  9.12 33.541 9.48 34.883 ;
     RECT  2.4 33.973 3.48 35.363 ;
     RECT  13.2 30.275 13.944 35.459 ;
     RECT  18.6 1.763 18.912 35.845 ;
     RECT  10.848 35.605 10.872 36.515 ;
     RECT  82.512 32.053 84.072 38.435 ;
     RECT  9.456 34.883 9.48 38.581 ;
     RECT  72.6 5.747 72.912 38.677 ;
     RECT  9.408 38.581 9.48 38.749 ;
     RECT  82.512 38.435 83.976 38.869 ;
     RECT  5.952 36.229 5.976 39.109 ;
     RECT  68.928 38.149 68.952 39.251 ;
     RECT  2.4 35.363 2.712 39.301 ;
     RECT  5.712 39.109 5.976 39.301 ;
     RECT  65.808 38.725 65.832 39.301 ;
     RECT  88.8 1.763 89.112 39.301 ;
     RECT  65.376 39.301 65.832 39.347 ;
     RECT  9.408 38.749 9.432 39.539 ;
     RECT  91.104 39.301 91.128 39.637 ;
     RECT  67.2 5.219 67.512 39.733 ;
     RECT  4.752 39.301 5.976 39.829 ;
     RECT  2.4 39.301 3.432 39.923 ;
     RECT  90.912 39.637 91.128 40.067 ;
     RECT  75.792 39.061 75.816 40.643 ;
     RECT  4.752 39.829 6.504 40.691 ;
     RECT  72.288 38.677 72.912 40.691 ;
     RECT  5.712 40.691 6.504 41.027 ;
     RECT  65.376 39.347 65.4 41.171 ;
     RECT  67.2 39.733 67.704 41.173 ;
     RECT  68.688 39.829 68.712 41.173 ;
     RECT  82.32 38.869 83.976 41.221 ;
     RECT  48.432 38.965 48.456 41.315 ;
     RECT  0.144 41.173 0.168 41.603 ;
     RECT  81.36 41.221 83.976 41.651 ;
     RECT  81.36 41.651 82.344 41.987 ;
     RECT  72.6 40.691 72.912 41.989 ;
     RECT  72.6 41.989 74.712 42.131 ;
     RECT  5.712 41.027 5.736 42.227 ;
     RECT  2.4 39.923 2.712 42.229 ;
     RECT  2.304 42.229 2.712 42.371 ;
     RECT  7.8 33.155 8.112 42.565 ;
     RECT  83.4 41.651 83.976 42.565 ;
     RECT  88.8 39.301 89.352 42.709 ;
     RECT  83.4 42.565 84.696 42.755 ;
     RECT  61.8 1.859 62.112 42.757 ;
     RECT  71.136 3.685 71.16 42.757 ;
     RECT  90.912 40.067 90.936 42.803 ;
     RECT  67.2 41.173 68.712 42.853 ;
     RECT  70.656 42.757 71.16 42.947 ;
     RECT  80.208 42.469 80.232 43.043 ;
     RECT  87.216 42.133 87.24 43.091 ;
     RECT  88.8 42.709 89.4 43.091 ;
     RECT  5.952 42.421 5.976 43.811 ;
     RECT  78 6.515 78.312 43.813 ;
     RECT  83.4 42.755 83.976 43.955 ;
     RECT  67.2 42.853 69.336 44.051 ;
     RECT  2.4 42.371 2.712 44.437 ;
     RECT  18.192 35.845 18.912 44.483 ;
     RECT  54.096 39.109 54.12 44.483 ;
     RECT  61.8 42.757 62.232 44.483 ;
     RECT  71.136 42.947 71.16 44.483 ;
     RECT  72.6 42.131 73.608 44.483 ;
     RECT  78 43.813 79.224 44.483 ;
     RECT  2.304 44.437 2.712 44.627 ;
     RECT  7.8 42.565 8.232 44.869 ;
     RECT  68.64 44.051 69.336 44.915 ;
     RECT  13.2 35.459 13.512 44.917 ;
     RECT  7.68 44.869 8.232 44.965 ;
     RECT  86.928 44.053 86.952 45.013 ;
     RECT  90.624 45.061 90.648 45.203 ;
     RECT  82.32 41.987 82.344 45.253 ;
     RECT  83.4 43.955 83.712 45.253 ;
     RECT  6.864 44.965 8.232 45.587 ;
     RECT  82.32 45.253 83.712 45.733 ;
     RECT  86.016 45.013 86.952 46.165 ;
     RECT  69.312 44.915 69.336 46.211 ;
     RECT  78 44.483 78.312 46.213 ;
     RECT  86.016 46.165 87.72 46.259 ;
     RECT  81.6 45.733 83.712 46.547 ;
     RECT  9.36 42.709 9.384 46.645 ;
     RECT  77.376 46.213 78.312 46.693 ;
     RECT  4.512 45.541 4.536 46.787 ;
     RECT  9.36 46.645 10.248 46.787 ;
     RECT  86.88 46.259 87.72 46.885 ;
     RECT  88.8 43.091 89.112 46.885 ;
     RECT  69.504 46.645 69.528 47.171 ;
     RECT  65.904 46.741 65.928 47.363 ;
     RECT  77.376 46.693 78.696 47.363 ;
     RECT  81.6 46.547 82.344 47.363 ;
     RECT  86.88 46.885 89.112 48.131 ;
     RECT  10.224 46.787 10.248 48.419 ;
     RECT  88.8 48.131 89.112 48.421 ;
     RECT  7.104 45.587 8.232 48.515 ;
     RECT  82.32 47.363 82.344 49.477 ;
     RECT  83.4 46.547 83.712 49.477 ;
     RECT  86.88 48.131 87.72 49.477 ;
     RECT  88.8 48.421 90.072 49.477 ;
     RECT  75.552 46.117 75.576 49.523 ;
     RECT  86.88 49.477 90.072 50.147 ;
     RECT  4.56 47.269 4.584 50.197 ;
     RECT  4.56 50.197 4.728 50.243 ;
     RECT  9.984 49.477 10.008 50.243 ;
     RECT  82.32 49.477 83.712 50.339 ;
     RECT  86.88 50.147 87.72 50.387 ;
     RECT  88.8 50.147 90.072 50.581 ;
     RECT  88.8 50.581 90.216 50.723 ;
     RECT  92.352 50.149 92.376 50.771 ;
     RECT  4.704 50.243 4.728 50.819 ;
     RECT  88.8 50.723 89.496 51.395 ;
     RECT  96.336 51.205 96.36 51.395 ;
     RECT  88.8 51.395 89.208 51.683 ;
     RECT  7.8 48.515 8.232 51.923 ;
     RECT  10.128 50.821 10.68 51.923 ;
     RECT  10.128 51.923 10.152 52.405 ;
     RECT  7.8 51.923 8.112 53.365 ;
     RECT  84.96 54.037 84.984 54.179 ;
     RECT  88.8 51.683 89.112 54.469 ;
     RECT  90.48 51.349 90.504 54.469 ;
     RECT  9.696 52.405 10.152 54.611 ;
     RECT  88.8 54.469 90.504 54.755 ;
     RECT  83.232 50.339 83.712 55.139 ;
     RECT  87.696 50.387 87.72 55.237 ;
     RECT  88.8 54.755 89.544 55.237 ;
     RECT  9.84 54.611 10.152 55.283 ;
     RECT  87.696 55.237 89.544 55.427 ;
     RECT  7.8 53.365 8.28 55.669 ;
     RECT  83.28 55.139 83.712 55.813 ;
     RECT  88.656 55.427 89.544 55.907 ;
     RECT  7.2 55.669 8.28 56.483 ;
     RECT  13.2 44.917 13.944 56.483 ;
     RECT  10.128 55.283 10.152 56.531 ;
     RECT  88.8 55.907 89.544 56.819 ;
     RECT  83.28 55.813 84.312 57.011 ;
     RECT  13.2 56.483 13.512 57.541 ;
     RECT  5.328 56.341 5.352 58.693 ;
     RECT  5.328 58.693 5.544 59.027 ;
     RECT  5.328 59.027 5.352 59.989 ;
     RECT  7.8 56.483 8.28 60.037 ;
     RECT  5.328 59.989 5.496 60.563 ;
     RECT  7.248 60.037 8.28 60.851 ;
     RECT  13.2 57.541 13.8 61.763 ;
     RECT  5.328 60.563 5.352 61.861 ;
     RECT  7.8 60.851 8.28 62.149 ;
     RECT  7.248 62.149 8.28 62.771 ;
     RECT  4.752 61.861 5.352 64.835 ;
     RECT  7.8 62.771 8.28 64.837 ;
     RECT  6.816 64.837 8.28 65.987 ;
     RECT  7.8 65.987 8.28 66.085 ;
     RECT  9.696 64.885 9.72 66.085 ;
     RECT  7.8 66.085 10.296 66.131 ;
     RECT  7.8 66.131 9 66.755 ;
     RECT  7.8 66.755 8.28 67.237 ;
     RECT  10.272 66.131 10.296 67.283 ;
     RECT  83.28 57.011 83.712 67.283 ;
     RECT  5.088 64.835 5.352 68.581 ;
     RECT  5.088 68.581 5.784 68.627 ;
     RECT  10.032 68.389 10.056 68.773 ;
     RECT  7.44 67.237 8.28 69.155 ;
     RECT  7.8 69.155 8.28 69.587 ;
     RECT  7.8 69.587 8.112 70.645 ;
     RECT  9.648 68.773 10.056 70.835 ;
     RECT  10.032 70.835 10.056 71.315 ;
     RECT  11.472 62.053 11.496 71.315 ;
     RECT  10.416 71.797 10.44 72.419 ;
     RECT  7.8 70.645 8.328 72.947 ;
     RECT  5.328 68.627 5.784 74.053 ;
     RECT  5.328 74.053 6.552 74.099 ;
     RECT  7.8 72.947 8.112 75.109 ;
     RECT  10.272 74.629 10.296 75.683 ;
     RECT  7.68 75.109 8.112 76.211 ;
     RECT  9.888 76.117 9.912 77.555 ;
     RECT  5.76 74.099 6.552 77.891 ;
     RECT  6.528 77.891 6.552 77.987 ;
     RECT  3.792 78.037 3.816 79.475 ;
     RECT  80.592 56.485 80.616 93.587 ;
     RECT  2.4 44.627 2.712 95.049 ;
     RECT  7.8 76.211 8.112 95.049 ;
     RECT  13.2 61.763 13.512 95.049 ;
     RECT  18.6 44.483 18.912 95.049 ;
     RECT  24 1.763 24.312 95.049 ;
     RECT  29.4 2.137 29.712 95.049 ;
     RECT  34.8 1.811 35.112 95.049 ;
     RECT  40.2 1.763 40.512 95.049 ;
     RECT  45.6 1.811 45.912 95.049 ;
     RECT  51 1.763 51.312 95.049 ;
     RECT  56.4 1.763 56.712 95.049 ;
     RECT  61.8 44.483 62.112 95.049 ;
     RECT  67.2 44.051 67.512 95.049 ;
     RECT  72.6 44.483 72.912 95.049 ;
     RECT  78 47.363 78.312 95.049 ;
     RECT  83.4 67.283 83.712 95.049 ;
     RECT  88.8 56.819 89.112 95.049 ;
     RECT  94.2 2.387 94.512 95.049 ;
     RECT  2.4 95.049 2.52 95.063 ;
     RECT  7.8 95.049 7.92 95.063 ;
     RECT  13.2 95.049 13.32 95.063 ;
     RECT  18.6 95.049 18.72 95.063 ;
     RECT  24 95.049 24.12 95.063 ;
     RECT  29.4 95.049 29.52 95.063 ;
     RECT  34.8 95.049 34.92 95.063 ;
     RECT  40.2 95.049 40.32 95.063 ;
     RECT  45.6 95.049 45.72 95.063 ;
     RECT  51 95.049 51.12 95.063 ;
     RECT  56.4 95.049 56.52 95.063 ;
     RECT  61.8 95.049 61.92 95.063 ;
     RECT  67.2 95.049 67.32 95.063 ;
     RECT  72.6 95.049 72.72 95.063 ;
     RECT  78 95.049 78.12 95.063 ;
     RECT  83.4 95.049 83.52 95.063 ;
     RECT  88.8 95.049 88.92 95.063 ;
     RECT  94.2 95.049 94.32 95.063 ;
     RECT  64.368 94.645 64.392 95.125 ;
     RECT  64.224 95.125 64.392 96.325 ;
     RECT  64.224 96.325 64.536 97.116 ;
     RECT  64.248 97.116 64.368 97.168 ;
     RECT  64.392 97.116 64.512 97.168 ;
     RECT  28.296 0.016 29.472 0.132 ;
     RECT  57.096 0.016 58.272 0.132 ;
     RECT  28.248 0.132 29.52 1.763 ;
     RECT  57.048 0.132 58.32 1.763 ;
     RECT  67.992 0.179 69.408 1.763 ;
     RECT  70.152 0.179 71.136 0.611 ;
     RECT  79.512 0.323 80.496 0.419 ;
     RECT  81.24 0.371 82.224 1.763 ;
     RECT  79.512 0.419 80.784 0.563 ;
     RECT  77.496 0.563 78.624 2.137 ;
     RECT  29.4 1.763 29.52 2.137 ;
     RECT  49.704 1.763 51 1.811 ;
     RECT  73.32 1.907 74.04 2.915 ;
     RECT  12.168 2.821 13.2 3.107 ;
     RECT  71.856 2.915 72.6 3.685 ;
     RECT  72.912 2.915 74.04 3.397 ;
     RECT  2.712 3.397 4.224 5.171 ;
     RECT  72.912 3.397 74.448 3.829 ;
     RECT  71.16 3.685 72.6 4.501 ;
     RECT  72.912 3.829 74.352 4.357 ;
     RECT  8.112 4.355 8.232 5.653 ;
     RECT  72.912 4.357 74.112 6.419 ;
     RECT  67.848 4.501 68.976 4.787 ;
     RECT  71.16 4.501 72.192 5.747 ;
     RECT  76.488 4.547 78 5.747 ;
     RECT  71.16 5.747 72.6 38.677 ;
     RECT  10.68 9.925 12 10.883 ;
     RECT  12.024 9.925 13.2 10.883 ;
     RECT  10.68 10.883 11.256 11.317 ;
     RECT  10.68 16.501 11.76 17.699 ;
     RECT  11.784 16.501 12.912 17.123 ;
     RECT  11.784 17.123 13.2 17.699 ;
     RECT  8.112 17.363 8.232 18.565 ;
     RECT  8.112 18.565 9.504 19.861 ;
     RECT  9.528 18.565 10.656 19.381 ;
     RECT  8.568 20.003 9.936 20.051 ;
     RECT  12.96 21.155 13.2 22.597 ;
     RECT  11.88 22.597 13.2 23.747 ;
     RECT  8.112 22.981 9.312 24.131 ;
     RECT  9.744 29.507 9.768 29.941 ;
     RECT  2.712 29.845 4.032 33.107 ;
     RECT  4.056 29.845 5.184 29.891 ;
     RECT  9.744 29.941 10.464 30.467 ;
     RECT  9.744 30.467 10.488 30.469 ;
     RECT  8.112 30.469 9.456 33.541 ;
     RECT  9.48 30.469 10.488 31.285 ;
     RECT  9.48 31.285 10.8 31.955 ;
     RECT  2.712 33.107 3.48 33.973 ;
     RECT  8.112 33.541 9.12 34.883 ;
     RECT  8.112 34.883 9.456 38.581 ;
     RECT  9.48 35.605 10.848 36.515 ;
     RECT  67.512 38.149 68.928 39.251 ;
     RECT  8.112 38.581 9.408 39.539 ;
     RECT  71.16 38.677 72.288 40.691 ;
     RECT  65.832 38.725 67.2 39.347 ;
     RECT  67.512 39.251 68.712 39.733 ;
     RECT  3.432 39.301 4.752 39.923 ;
     RECT  67.704 39.733 68.712 39.829 ;
     RECT  6.504 39.829 7.8 41.027 ;
     RECT  67.704 39.829 68.688 41.173 ;
     RECT  71.16 40.691 72.6 44.483 ;
     RECT  5.736 41.027 5.976 42.227 ;
     RECT  82.344 41.651 83.4 45.253 ;
     RECT  5.952 42.227 5.976 42.421 ;
     RECT  8.232 42.709 9.36 46.787 ;
     RECT  89.4 42.709 90.912 42.803 ;
     RECT  69.336 42.853 70.656 42.947 ;
     RECT  67.512 44.051 68.64 44.915 ;
     RECT  89.112 45.061 90.624 45.203 ;
     RECT  87.72 46.165 88.8 46.885 ;
     RECT  82.344 46.547 83.4 49.477 ;
     RECT  65.928 46.741 67.2 47.363 ;
     RECT  87.72 48.131 88.8 49.477 ;
     RECT  87.72 50.147 88.8 55.237 ;
     RECT  89.496 50.723 90.216 51.349 ;
     RECT  89.496 51.349 90.48 51.395 ;
     RECT  89.208 51.395 90.48 51.683 ;
     RECT  89.112 51.683 90.48 54.469 ;
     RECT  8.112 51.923 8.232 52.405 ;
     RECT  8.112 52.405 9.696 53.365 ;
     RECT  8.28 53.365 9.696 54.611 ;
     RECT  83.712 54.037 84.96 54.179 ;
     RECT  13.512 56.483 13.8 57.541 ;
     RECT  5.352 59.027 5.496 59.989 ;
     RECT  7.248 60.851 7.8 62.149 ;
     RECT  5.352 64.837 6.816 65.987 ;
     RECT  8.28 64.885 9.696 66.085 ;
     RECT  7.44 65.987 7.8 67.237 ;
     RECT  10.296 66.085 11.472 67.283 ;
     RECT  9 66.131 10.272 66.755 ;
     RECT  10.272 67.283 11.472 68.389 ;
     RECT  10.056 68.389 11.472 71.315 ;
     RECT  8.28 68.773 9.648 69.587 ;
     RECT  8.112 69.587 9.648 70.645 ;
     RECT  8.328 70.645 9.648 70.835 ;
     RECT  10.416 71.315 10.44 71.797 ;
     RECT  6.552 74.053 7.8 75.109 ;
     RECT  6.552 75.109 7.68 76.211 ;
     RECT  6.552 76.211 7.8 77.987 ;
     RECT  2.712 78.037 3.792 79.475 ;
  END
END ot_hbm_host_packet_static
END LIBRARY
